VERSION 5.8 ;
BUSBITCHARS "[]" ;
DIVIDERCHAR "/" ;
UNITS
    DATABASE MICRONS 1000 ;
END UNITS

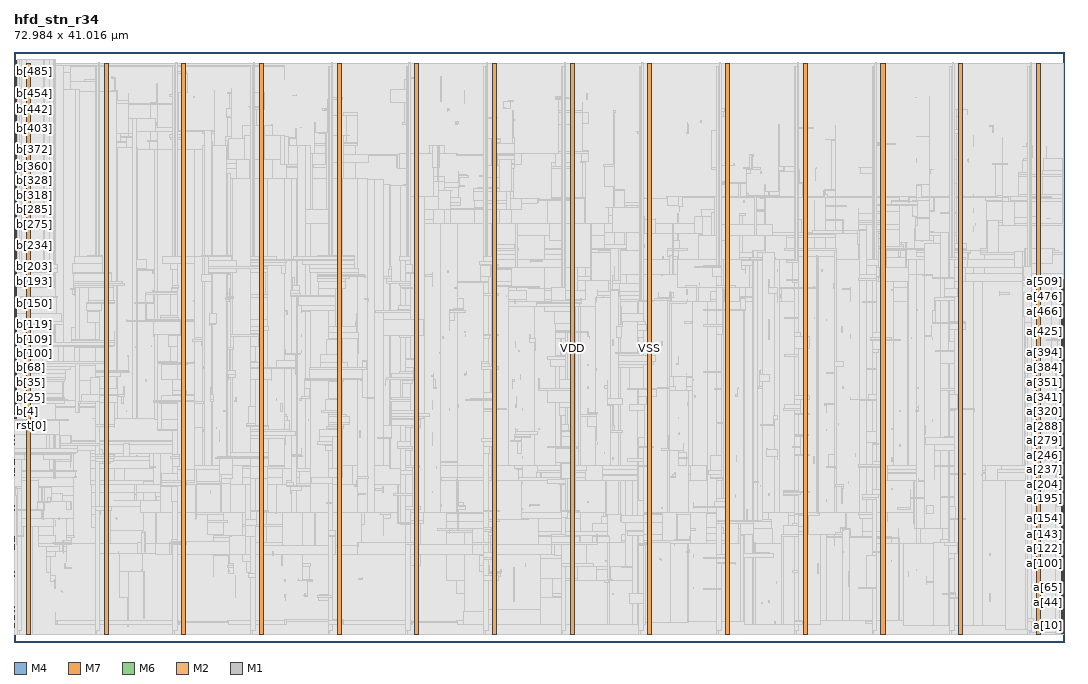
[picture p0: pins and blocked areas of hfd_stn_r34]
MACRO hfd_stn_r34
  FOREIGN hfd_stn_r34 0 0 ;
  CLASS BLOCK ;
  SIZE 72.984 BY 41.016 ;
  PIN a[0]
    DIRECTION INPUT ;
    USE SIGNAL ;
    PORT
      LAYER M4 ;
        RECT  72.792 0.624 72.984 0.648 ;
    END
  END a[0]
  PIN a[100]
    DIRECTION INPUT ;
    USE SIGNAL ;
    PORT
      LAYER M4 ;
        RECT  72.792 5.424 72.984 5.448 ;
    END
  END a[100]
  PIN a[101]
    DIRECTION INPUT ;
    USE SIGNAL ;
    PORT
      LAYER M4 ;
        RECT  72.792 5.472 72.984 5.496 ;
    END
  END a[101]
  PIN a[102]
    DIRECTION INPUT ;
    USE SIGNAL ;
    PORT
      LAYER M4 ;
        RECT  72.792 5.52 72.984 5.544 ;
    END
  END a[102]
  PIN a[103]
    DIRECTION INPUT ;
    USE SIGNAL ;
    PORT
      LAYER M4 ;
        RECT  72.792 5.568 72.984 5.592 ;
    END
  END a[103]
  PIN a[104]
    DIRECTION INPUT ;
    USE SIGNAL ;
    PORT
      LAYER M4 ;
        RECT  72.792 5.616 72.984 5.64 ;
    END
  END a[104]
  PIN a[105]
    DIRECTION INPUT ;
    USE SIGNAL ;
    PORT
      LAYER M4 ;
        RECT  72.792 5.664 72.984 5.688 ;
    END
  END a[105]
  PIN a[106]
    DIRECTION INPUT ;
    USE SIGNAL ;
    PORT
      LAYER M4 ;
        RECT  72.792 5.712 72.984 5.736 ;
    END
  END a[106]
  PIN a[107]
    DIRECTION INPUT ;
    USE SIGNAL ;
    PORT
      LAYER M4 ;
        RECT  72.792 5.76 72.984 5.784 ;
    END
  END a[107]
  PIN a[108]
    DIRECTION INPUT ;
    USE SIGNAL ;
    PORT
      LAYER M4 ;
        RECT  72.792 5.808 72.984 5.832 ;
    END
  END a[108]
  PIN a[109]
    DIRECTION INPUT ;
    USE SIGNAL ;
    PORT
      LAYER M4 ;
        RECT  72.792 5.856 72.984 5.88 ;
    END
  END a[109]
  PIN a[10]
    DIRECTION INPUT ;
    USE SIGNAL ;
    PORT
      LAYER M4 ;
        RECT  72.792 1.104 72.984 1.128 ;
    END
  END a[10]
  PIN a[110]
    DIRECTION INPUT ;
    USE SIGNAL ;
    PORT
      LAYER M4 ;
        RECT  72.792 5.904 72.984 5.928 ;
    END
  END a[110]
  PIN a[111]
    DIRECTION INPUT ;
    USE SIGNAL ;
    PORT
      LAYER M4 ;
        RECT  72.792 5.952 72.984 5.976 ;
    END
  END a[111]
  PIN a[112]
    DIRECTION INPUT ;
    USE SIGNAL ;
    PORT
      LAYER M4 ;
        RECT  72.792 6 72.984 6.024 ;
    END
  END a[112]
  PIN a[113]
    DIRECTION INPUT ;
    USE SIGNAL ;
    PORT
      LAYER M4 ;
        RECT  72.792 6.048 72.984 6.072 ;
    END
  END a[113]
  PIN a[114]
    DIRECTION INPUT ;
    USE SIGNAL ;
    PORT
      LAYER M4 ;
        RECT  72.792 6.096 72.984 6.12 ;
    END
  END a[114]
  PIN a[115]
    DIRECTION INPUT ;
    USE SIGNAL ;
    PORT
      LAYER M4 ;
        RECT  72.792 6.144 72.984 6.168 ;
    END
  END a[115]
  PIN a[116]
    DIRECTION INPUT ;
    USE SIGNAL ;
    PORT
      LAYER M4 ;
        RECT  72.792 6.192 72.984 6.216 ;
    END
  END a[116]
  PIN a[117]
    DIRECTION INPUT ;
    USE SIGNAL ;
    PORT
      LAYER M4 ;
        RECT  72.792 6.24 72.984 6.264 ;
    END
  END a[117]
  PIN a[118]
    DIRECTION INPUT ;
    USE SIGNAL ;
    PORT
      LAYER M4 ;
        RECT  72.792 6.288 72.984 6.312 ;
    END
  END a[118]
  PIN a[119]
    DIRECTION INPUT ;
    USE SIGNAL ;
    PORT
      LAYER M4 ;
        RECT  72.792 6.336 72.984 6.36 ;
    END
  END a[119]
  PIN a[11]
    DIRECTION INPUT ;
    USE SIGNAL ;
    PORT
      LAYER M4 ;
        RECT  72.792 1.152 72.984 1.176 ;
    END
  END a[11]
  PIN a[120]
    DIRECTION INPUT ;
    USE SIGNAL ;
    PORT
      LAYER M4 ;
        RECT  72.792 6.384 72.984 6.408 ;
    END
  END a[120]
  PIN a[121]
    DIRECTION INPUT ;
    USE SIGNAL ;
    PORT
      LAYER M4 ;
        RECT  72.792 6.432 72.984 6.456 ;
    END
  END a[121]
  PIN a[122]
    DIRECTION INPUT ;
    USE SIGNAL ;
    PORT
      LAYER M4 ;
        RECT  72.792 6.48 72.984 6.504 ;
    END
  END a[122]
  PIN a[123]
    DIRECTION INPUT ;
    USE SIGNAL ;
    PORT
      LAYER M4 ;
        RECT  72.792 6.528 72.984 6.552 ;
    END
  END a[123]
  PIN a[124]
    DIRECTION INPUT ;
    USE SIGNAL ;
    PORT
      LAYER M4 ;
        RECT  72.792 6.576 72.984 6.6 ;
    END
  END a[124]
  PIN a[125]
    DIRECTION INPUT ;
    USE SIGNAL ;
    PORT
      LAYER M4 ;
        RECT  72.792 6.624 72.984 6.648 ;
    END
  END a[125]
  PIN a[126]
    DIRECTION INPUT ;
    USE SIGNAL ;
    PORT
      LAYER M4 ;
        RECT  72.792 6.672 72.984 6.696 ;
    END
  END a[126]
  PIN a[127]
    DIRECTION INPUT ;
    USE SIGNAL ;
    PORT
      LAYER M4 ;
        RECT  72.792 6.72 72.984 6.744 ;
    END
  END a[127]
  PIN a[128]
    DIRECTION INPUT ;
    USE SIGNAL ;
    PORT
      LAYER M4 ;
        RECT  72.792 6.768 72.984 6.792 ;
    END
  END a[128]
  PIN a[129]
    DIRECTION INPUT ;
    USE SIGNAL ;
    PORT
      LAYER M4 ;
        RECT  72.792 6.816 72.984 6.84 ;
    END
  END a[129]
  PIN a[12]
    DIRECTION INPUT ;
    USE SIGNAL ;
    PORT
      LAYER M4 ;
        RECT  72.792 1.2 72.984 1.224 ;
    END
  END a[12]
  PIN a[130]
    DIRECTION INPUT ;
    USE SIGNAL ;
    PORT
      LAYER M4 ;
        RECT  72.792 6.864 72.984 6.888 ;
    END
  END a[130]
  PIN a[131]
    DIRECTION INPUT ;
    USE SIGNAL ;
    PORT
      LAYER M4 ;
        RECT  72.792 6.912 72.984 6.936 ;
    END
  END a[131]
  PIN a[132]
    DIRECTION INPUT ;
    USE SIGNAL ;
    PORT
      LAYER M4 ;
        RECT  72.792 6.96 72.984 6.984 ;
    END
  END a[132]
  PIN a[133]
    DIRECTION INPUT ;
    USE SIGNAL ;
    PORT
      LAYER M4 ;
        RECT  72.792 7.008 72.984 7.032 ;
    END
  END a[133]
  PIN a[134]
    DIRECTION INPUT ;
    USE SIGNAL ;
    PORT
      LAYER M4 ;
        RECT  72.792 7.056 72.984 7.08 ;
    END
  END a[134]
  PIN a[135]
    DIRECTION INPUT ;
    USE SIGNAL ;
    PORT
      LAYER M4 ;
        RECT  72.792 7.104 72.984 7.128 ;
    END
  END a[135]
  PIN a[136]
    DIRECTION INPUT ;
    USE SIGNAL ;
    PORT
      LAYER M4 ;
        RECT  72.792 7.152 72.984 7.176 ;
    END
  END a[136]
  PIN a[137]
    DIRECTION INPUT ;
    USE SIGNAL ;
    PORT
      LAYER M4 ;
        RECT  72.792 7.2 72.984 7.224 ;
    END
  END a[137]
  PIN a[138]
    DIRECTION INPUT ;
    USE SIGNAL ;
    PORT
      LAYER M4 ;
        RECT  72.792 7.248 72.984 7.272 ;
    END
  END a[138]
  PIN a[139]
    DIRECTION INPUT ;
    USE SIGNAL ;
    PORT
      LAYER M4 ;
        RECT  72.792 7.296 72.984 7.32 ;
    END
  END a[139]
  PIN a[13]
    DIRECTION INPUT ;
    USE SIGNAL ;
    PORT
      LAYER M4 ;
        RECT  72.792 1.248 72.984 1.272 ;
    END
  END a[13]
  PIN a[140]
    DIRECTION INPUT ;
    USE SIGNAL ;
    PORT
      LAYER M4 ;
        RECT  72.792 7.344 72.984 7.368 ;
    END
  END a[140]
  PIN a[141]
    DIRECTION INPUT ;
    USE SIGNAL ;
    PORT
      LAYER M4 ;
        RECT  72.792 7.392 72.984 7.416 ;
    END
  END a[141]
  PIN a[142]
    DIRECTION INPUT ;
    USE SIGNAL ;
    PORT
      LAYER M4 ;
        RECT  72.792 7.44 72.984 7.464 ;
    END
  END a[142]
  PIN a[143]
    DIRECTION INPUT ;
    USE SIGNAL ;
    PORT
      LAYER M4 ;
        RECT  72.792 7.488 72.984 7.512 ;
    END
  END a[143]
  PIN a[144]
    DIRECTION INPUT ;
    USE SIGNAL ;
    PORT
      LAYER M4 ;
        RECT  72.792 7.536 72.984 7.56 ;
    END
  END a[144]
  PIN a[145]
    DIRECTION INPUT ;
    USE SIGNAL ;
    PORT
      LAYER M4 ;
        RECT  72.792 7.584 72.984 7.608 ;
    END
  END a[145]
  PIN a[146]
    DIRECTION INPUT ;
    USE SIGNAL ;
    PORT
      LAYER M4 ;
        RECT  72.792 7.632 72.984 7.656 ;
    END
  END a[146]
  PIN a[147]
    DIRECTION INPUT ;
    USE SIGNAL ;
    PORT
      LAYER M4 ;
        RECT  72.792 7.68 72.984 7.704 ;
    END
  END a[147]
  PIN a[148]
    DIRECTION INPUT ;
    USE SIGNAL ;
    PORT
      LAYER M4 ;
        RECT  72.792 7.728 72.984 7.752 ;
    END
  END a[148]
  PIN a[149]
    DIRECTION INPUT ;
    USE SIGNAL ;
    PORT
      LAYER M4 ;
        RECT  72.792 7.776 72.984 7.8 ;
    END
  END a[149]
  PIN a[14]
    DIRECTION INPUT ;
    USE SIGNAL ;
    PORT
      LAYER M4 ;
        RECT  72.792 1.296 72.984 1.32 ;
    END
  END a[14]
  PIN a[150]
    DIRECTION INPUT ;
    USE SIGNAL ;
    PORT
      LAYER M4 ;
        RECT  72.792 7.824 72.984 7.848 ;
    END
  END a[150]
  PIN a[151]
    DIRECTION INPUT ;
    USE SIGNAL ;
    PORT
      LAYER M4 ;
        RECT  72.792 7.872 72.984 7.896 ;
    END
  END a[151]
  PIN a[152]
    DIRECTION INPUT ;
    USE SIGNAL ;
    PORT
      LAYER M4 ;
        RECT  72.792 7.92 72.984 7.944 ;
    END
  END a[152]
  PIN a[153]
    DIRECTION INPUT ;
    USE SIGNAL ;
    PORT
      LAYER M4 ;
        RECT  72.792 7.968 72.984 7.992 ;
    END
  END a[153]
  PIN a[154]
    DIRECTION INPUT ;
    USE SIGNAL ;
    PORT
      LAYER M4 ;
        RECT  72.792 8.016 72.984 8.04 ;
    END
  END a[154]
  PIN a[155]
    DIRECTION INPUT ;
    USE SIGNAL ;
    PORT
      LAYER M4 ;
        RECT  72.792 8.064 72.984 8.088 ;
    END
  END a[155]
  PIN a[156]
    DIRECTION INPUT ;
    USE SIGNAL ;
    PORT
      LAYER M4 ;
        RECT  72.792 8.112 72.984 8.136 ;
    END
  END a[156]
  PIN a[157]
    DIRECTION INPUT ;
    USE SIGNAL ;
    PORT
      LAYER M4 ;
        RECT  72.792 8.16 72.984 8.184 ;
    END
  END a[157]
  PIN a[158]
    DIRECTION INPUT ;
    USE SIGNAL ;
    PORT
      LAYER M4 ;
        RECT  72.792 8.208 72.984 8.232 ;
    END
  END a[158]
  PIN a[159]
    DIRECTION INPUT ;
    USE SIGNAL ;
    PORT
      LAYER M4 ;
        RECT  72.792 8.256 72.984 8.28 ;
    END
  END a[159]
  PIN a[15]
    DIRECTION INPUT ;
    USE SIGNAL ;
    PORT
      LAYER M4 ;
        RECT  72.792 1.344 72.984 1.368 ;
    END
  END a[15]
  PIN a[160]
    DIRECTION INPUT ;
    USE SIGNAL ;
    PORT
      LAYER M4 ;
        RECT  72.792 8.304 72.984 8.328 ;
    END
  END a[160]
  PIN a[161]
    DIRECTION INPUT ;
    USE SIGNAL ;
    PORT
      LAYER M4 ;
        RECT  72.792 8.352 72.984 8.376 ;
    END
  END a[161]
  PIN a[162]
    DIRECTION INPUT ;
    USE SIGNAL ;
    PORT
      LAYER M4 ;
        RECT  72.792 8.4 72.984 8.424 ;
    END
  END a[162]
  PIN a[163]
    DIRECTION INPUT ;
    USE SIGNAL ;
    PORT
      LAYER M4 ;
        RECT  72.792 8.448 72.984 8.472 ;
    END
  END a[163]
  PIN a[164]
    DIRECTION INPUT ;
    USE SIGNAL ;
    PORT
      LAYER M4 ;
        RECT  72.792 8.496 72.984 8.52 ;
    END
  END a[164]
  PIN a[165]
    DIRECTION INPUT ;
    USE SIGNAL ;
    PORT
      LAYER M4 ;
        RECT  72.792 8.544 72.984 8.568 ;
    END
  END a[165]
  PIN a[166]
    DIRECTION INPUT ;
    USE SIGNAL ;
    PORT
      LAYER M4 ;
        RECT  72.792 8.592 72.984 8.616 ;
    END
  END a[166]
  PIN a[167]
    DIRECTION INPUT ;
    USE SIGNAL ;
    PORT
      LAYER M4 ;
        RECT  72.792 8.64 72.984 8.664 ;
    END
  END a[167]
  PIN a[168]
    DIRECTION INPUT ;
    USE SIGNAL ;
    PORT
      LAYER M4 ;
        RECT  72.792 8.688 72.984 8.712 ;
    END
  END a[168]
  PIN a[169]
    DIRECTION INPUT ;
    USE SIGNAL ;
    PORT
      LAYER M4 ;
        RECT  72.792 8.736 72.984 8.76 ;
    END
  END a[169]
  PIN a[16]
    DIRECTION INPUT ;
    USE SIGNAL ;
    PORT
      LAYER M4 ;
        RECT  72.792 1.392 72.984 1.416 ;
    END
  END a[16]
  PIN a[170]
    DIRECTION INPUT ;
    USE SIGNAL ;
    PORT
      LAYER M4 ;
        RECT  72.792 8.784 72.984 8.808 ;
    END
  END a[170]
  PIN a[171]
    DIRECTION INPUT ;
    USE SIGNAL ;
    PORT
      LAYER M4 ;
        RECT  72.792 8.832 72.984 8.856 ;
    END
  END a[171]
  PIN a[172]
    DIRECTION INPUT ;
    USE SIGNAL ;
    PORT
      LAYER M4 ;
        RECT  72.792 8.88 72.984 8.904 ;
    END
  END a[172]
  PIN a[173]
    DIRECTION INPUT ;
    USE SIGNAL ;
    PORT
      LAYER M4 ;
        RECT  72.792 8.928 72.984 8.952 ;
    END
  END a[173]
  PIN a[174]
    DIRECTION INPUT ;
    USE SIGNAL ;
    PORT
      LAYER M4 ;
        RECT  72.792 8.976 72.984 9 ;
    END
  END a[174]
  PIN a[175]
    DIRECTION INPUT ;
    USE SIGNAL ;
    PORT
      LAYER M4 ;
        RECT  72.792 9.024 72.984 9.048 ;
    END
  END a[175]
  PIN a[176]
    DIRECTION INPUT ;
    USE SIGNAL ;
    PORT
      LAYER M4 ;
        RECT  72.792 9.072 72.984 9.096 ;
    END
  END a[176]
  PIN a[177]
    DIRECTION INPUT ;
    USE SIGNAL ;
    PORT
      LAYER M4 ;
        RECT  72.792 9.12 72.984 9.144 ;
    END
  END a[177]
  PIN a[178]
    DIRECTION INPUT ;
    USE SIGNAL ;
    PORT
      LAYER M4 ;
        RECT  72.792 9.168 72.984 9.192 ;
    END
  END a[178]
  PIN a[179]
    DIRECTION INPUT ;
    USE SIGNAL ;
    PORT
      LAYER M4 ;
        RECT  72.792 9.216 72.984 9.24 ;
    END
  END a[179]
  PIN a[17]
    DIRECTION INPUT ;
    USE SIGNAL ;
    PORT
      LAYER M4 ;
        RECT  72.792 1.44 72.984 1.464 ;
    END
  END a[17]
  PIN a[180]
    DIRECTION INPUT ;
    USE SIGNAL ;
    PORT
      LAYER M4 ;
        RECT  72.792 9.264 72.984 9.288 ;
    END
  END a[180]
  PIN a[181]
    DIRECTION INPUT ;
    USE SIGNAL ;
    PORT
      LAYER M4 ;
        RECT  72.792 9.312 72.984 9.336 ;
    END
  END a[181]
  PIN a[182]
    DIRECTION INPUT ;
    USE SIGNAL ;
    PORT
      LAYER M4 ;
        RECT  72.792 9.36 72.984 9.384 ;
    END
  END a[182]
  PIN a[183]
    DIRECTION INPUT ;
    USE SIGNAL ;
    PORT
      LAYER M4 ;
        RECT  72.792 9.408 72.984 9.432 ;
    END
  END a[183]
  PIN a[184]
    DIRECTION INPUT ;
    USE SIGNAL ;
    PORT
      LAYER M4 ;
        RECT  72.792 9.456 72.984 9.48 ;
    END
  END a[184]
  PIN a[185]
    DIRECTION INPUT ;
    USE SIGNAL ;
    PORT
      LAYER M4 ;
        RECT  72.792 9.504 72.984 9.528 ;
    END
  END a[185]
  PIN a[186]
    DIRECTION INPUT ;
    USE SIGNAL ;
    PORT
      LAYER M4 ;
        RECT  72.792 9.552 72.984 9.576 ;
    END
  END a[186]
  PIN a[187]
    DIRECTION INPUT ;
    USE SIGNAL ;
    PORT
      LAYER M4 ;
        RECT  72.792 9.6 72.984 9.624 ;
    END
  END a[187]
  PIN a[188]
    DIRECTION INPUT ;
    USE SIGNAL ;
    PORT
      LAYER M4 ;
        RECT  72.792 9.648 72.984 9.672 ;
    END
  END a[188]
  PIN a[189]
    DIRECTION INPUT ;
    USE SIGNAL ;
    PORT
      LAYER M4 ;
        RECT  72.792 9.696 72.984 9.72 ;
    END
  END a[189]
  PIN a[18]
    DIRECTION INPUT ;
    USE SIGNAL ;
    PORT
      LAYER M4 ;
        RECT  72.792 1.488 72.984 1.512 ;
    END
  END a[18]
  PIN a[190]
    DIRECTION INPUT ;
    USE SIGNAL ;
    PORT
      LAYER M4 ;
        RECT  72.792 9.744 72.984 9.768 ;
    END
  END a[190]
  PIN a[191]
    DIRECTION INPUT ;
    USE SIGNAL ;
    PORT
      LAYER M4 ;
        RECT  72.792 9.792 72.984 9.816 ;
    END
  END a[191]
  PIN a[192]
    DIRECTION INPUT ;
    USE SIGNAL ;
    PORT
      LAYER M4 ;
        RECT  72.792 9.84 72.984 9.864 ;
    END
  END a[192]
  PIN a[193]
    DIRECTION INPUT ;
    USE SIGNAL ;
    PORT
      LAYER M4 ;
        RECT  72.792 9.888 72.984 9.912 ;
    END
  END a[193]
  PIN a[194]
    DIRECTION INPUT ;
    USE SIGNAL ;
    PORT
      LAYER M4 ;
        RECT  72.792 9.936 72.984 9.96 ;
    END
  END a[194]
  PIN a[195]
    DIRECTION INPUT ;
    USE SIGNAL ;
    PORT
      LAYER M4 ;
        RECT  72.792 9.984 72.984 10.008 ;
    END
  END a[195]
  PIN a[196]
    DIRECTION INPUT ;
    USE SIGNAL ;
    PORT
      LAYER M4 ;
        RECT  72.792 10.032 72.984 10.056 ;
    END
  END a[196]
  PIN a[197]
    DIRECTION INPUT ;
    USE SIGNAL ;
    PORT
      LAYER M4 ;
        RECT  72.792 10.08 72.984 10.104 ;
    END
  END a[197]
  PIN a[198]
    DIRECTION INPUT ;
    USE SIGNAL ;
    PORT
      LAYER M4 ;
        RECT  72.792 10.128 72.984 10.152 ;
    END
  END a[198]
  PIN a[199]
    DIRECTION INPUT ;
    USE SIGNAL ;
    PORT
      LAYER M4 ;
        RECT  72.792 10.176 72.984 10.2 ;
    END
  END a[199]
  PIN a[19]
    DIRECTION INPUT ;
    USE SIGNAL ;
    PORT
      LAYER M4 ;
        RECT  72.792 1.536 72.984 1.56 ;
    END
  END a[19]
  PIN a[1]
    DIRECTION INPUT ;
    USE SIGNAL ;
    PORT
      LAYER M4 ;
        RECT  72.792 0.672 72.984 0.696 ;
    END
  END a[1]
  PIN a[200]
    DIRECTION INPUT ;
    USE SIGNAL ;
    PORT
      LAYER M4 ;
        RECT  72.792 10.224 72.984 10.248 ;
    END
  END a[200]
  PIN a[201]
    DIRECTION INPUT ;
    USE SIGNAL ;
    PORT
      LAYER M4 ;
        RECT  72.792 10.272 72.984 10.296 ;
    END
  END a[201]
  PIN a[202]
    DIRECTION INPUT ;
    USE SIGNAL ;
    PORT
      LAYER M4 ;
        RECT  72.792 10.32 72.984 10.344 ;
    END
  END a[202]
  PIN a[203]
    DIRECTION INPUT ;
    USE SIGNAL ;
    PORT
      LAYER M4 ;
        RECT  72.792 10.368 72.984 10.392 ;
    END
  END a[203]
  PIN a[204]
    DIRECTION INPUT ;
    USE SIGNAL ;
    PORT
      LAYER M4 ;
        RECT  72.792 10.416 72.984 10.44 ;
    END
  END a[204]
  PIN a[205]
    DIRECTION INPUT ;
    USE SIGNAL ;
    PORT
      LAYER M4 ;
        RECT  72.792 10.464 72.984 10.488 ;
    END
  END a[205]
  PIN a[206]
    DIRECTION INPUT ;
    USE SIGNAL ;
    PORT
      LAYER M4 ;
        RECT  72.792 10.512 72.984 10.536 ;
    END
  END a[206]
  PIN a[207]
    DIRECTION INPUT ;
    USE SIGNAL ;
    PORT
      LAYER M4 ;
        RECT  72.792 10.56 72.984 10.584 ;
    END
  END a[207]
  PIN a[208]
    DIRECTION INPUT ;
    USE SIGNAL ;
    PORT
      LAYER M4 ;
        RECT  72.792 10.608 72.984 10.632 ;
    END
  END a[208]
  PIN a[209]
    DIRECTION INPUT ;
    USE SIGNAL ;
    PORT
      LAYER M4 ;
        RECT  72.792 10.656 72.984 10.68 ;
    END
  END a[209]
  PIN a[20]
    DIRECTION INPUT ;
    USE SIGNAL ;
    PORT
      LAYER M4 ;
        RECT  72.792 1.584 72.984 1.608 ;
    END
  END a[20]
  PIN a[210]
    DIRECTION INPUT ;
    USE SIGNAL ;
    PORT
      LAYER M4 ;
        RECT  72.792 10.704 72.984 10.728 ;
    END
  END a[210]
  PIN a[211]
    DIRECTION INPUT ;
    USE SIGNAL ;
    PORT
      LAYER M4 ;
        RECT  72.792 10.752 72.984 10.776 ;
    END
  END a[211]
  PIN a[212]
    DIRECTION INPUT ;
    USE SIGNAL ;
    PORT
      LAYER M4 ;
        RECT  72.792 10.8 72.984 10.824 ;
    END
  END a[212]
  PIN a[213]
    DIRECTION INPUT ;
    USE SIGNAL ;
    PORT
      LAYER M4 ;
        RECT  72.792 10.848 72.984 10.872 ;
    END
  END a[213]
  PIN a[214]
    DIRECTION INPUT ;
    USE SIGNAL ;
    PORT
      LAYER M4 ;
        RECT  72.792 10.896 72.984 10.92 ;
    END
  END a[214]
  PIN a[215]
    DIRECTION INPUT ;
    USE SIGNAL ;
    PORT
      LAYER M4 ;
        RECT  72.792 10.944 72.984 10.968 ;
    END
  END a[215]
  PIN a[216]
    DIRECTION INPUT ;
    USE SIGNAL ;
    PORT
      LAYER M4 ;
        RECT  72.792 10.992 72.984 11.016 ;
    END
  END a[216]
  PIN a[217]
    DIRECTION INPUT ;
    USE SIGNAL ;
    PORT
      LAYER M4 ;
        RECT  72.792 11.04 72.984 11.064 ;
    END
  END a[217]
  PIN a[218]
    DIRECTION INPUT ;
    USE SIGNAL ;
    PORT
      LAYER M4 ;
        RECT  72.792 11.088 72.984 11.112 ;
    END
  END a[218]
  PIN a[219]
    DIRECTION INPUT ;
    USE SIGNAL ;
    PORT
      LAYER M4 ;
        RECT  72.792 11.136 72.984 11.16 ;
    END
  END a[219]
  PIN a[21]
    DIRECTION INPUT ;
    USE SIGNAL ;
    PORT
      LAYER M4 ;
        RECT  72.792 1.632 72.984 1.656 ;
    END
  END a[21]
  PIN a[220]
    DIRECTION INPUT ;
    USE SIGNAL ;
    PORT
      LAYER M4 ;
        RECT  72.792 11.184 72.984 11.208 ;
    END
  END a[220]
  PIN a[221]
    DIRECTION INPUT ;
    USE SIGNAL ;
    PORT
      LAYER M4 ;
        RECT  72.792 11.232 72.984 11.256 ;
    END
  END a[221]
  PIN a[222]
    DIRECTION INPUT ;
    USE SIGNAL ;
    PORT
      LAYER M4 ;
        RECT  72.792 11.28 72.984 11.304 ;
    END
  END a[222]
  PIN a[223]
    DIRECTION INPUT ;
    USE SIGNAL ;
    PORT
      LAYER M4 ;
        RECT  72.792 11.328 72.984 11.352 ;
    END
  END a[223]
  PIN a[224]
    DIRECTION INPUT ;
    USE SIGNAL ;
    PORT
      LAYER M4 ;
        RECT  72.792 11.376 72.984 11.4 ;
    END
  END a[224]
  PIN a[225]
    DIRECTION INPUT ;
    USE SIGNAL ;
    PORT
      LAYER M4 ;
        RECT  72.792 11.424 72.984 11.448 ;
    END
  END a[225]
  PIN a[226]
    DIRECTION INPUT ;
    USE SIGNAL ;
    PORT
      LAYER M4 ;
        RECT  72.792 11.472 72.984 11.496 ;
    END
  END a[226]
  PIN a[227]
    DIRECTION INPUT ;
    USE SIGNAL ;
    PORT
      LAYER M4 ;
        RECT  72.792 11.52 72.984 11.544 ;
    END
  END a[227]
  PIN a[228]
    DIRECTION INPUT ;
    USE SIGNAL ;
    PORT
      LAYER M4 ;
        RECT  72.792 11.568 72.984 11.592 ;
    END
  END a[228]
  PIN a[229]
    DIRECTION INPUT ;
    USE SIGNAL ;
    PORT
      LAYER M4 ;
        RECT  72.792 11.616 72.984 11.64 ;
    END
  END a[229]
  PIN a[22]
    DIRECTION INPUT ;
    USE SIGNAL ;
    PORT
      LAYER M4 ;
        RECT  72.792 1.68 72.984 1.704 ;
    END
  END a[22]
  PIN a[230]
    DIRECTION INPUT ;
    USE SIGNAL ;
    PORT
      LAYER M4 ;
        RECT  72.792 11.664 72.984 11.688 ;
    END
  END a[230]
  PIN a[231]
    DIRECTION INPUT ;
    USE SIGNAL ;
    PORT
      LAYER M4 ;
        RECT  72.792 11.712 72.984 11.736 ;
    END
  END a[231]
  PIN a[232]
    DIRECTION INPUT ;
    USE SIGNAL ;
    PORT
      LAYER M4 ;
        RECT  72.792 11.76 72.984 11.784 ;
    END
  END a[232]
  PIN a[233]
    DIRECTION INPUT ;
    USE SIGNAL ;
    PORT
      LAYER M4 ;
        RECT  72.792 11.808 72.984 11.832 ;
    END
  END a[233]
  PIN a[234]
    DIRECTION INPUT ;
    USE SIGNAL ;
    PORT
      LAYER M4 ;
        RECT  72.792 11.856 72.984 11.88 ;
    END
  END a[234]
  PIN a[235]
    DIRECTION INPUT ;
    USE SIGNAL ;
    PORT
      LAYER M4 ;
        RECT  72.792 11.904 72.984 11.928 ;
    END
  END a[235]
  PIN a[236]
    DIRECTION INPUT ;
    USE SIGNAL ;
    PORT
      LAYER M4 ;
        RECT  72.792 11.952 72.984 11.976 ;
    END
  END a[236]
  PIN a[237]
    DIRECTION INPUT ;
    USE SIGNAL ;
    PORT
      LAYER M4 ;
        RECT  72.792 12 72.984 12.024 ;
    END
  END a[237]
  PIN a[238]
    DIRECTION INPUT ;
    USE SIGNAL ;
    PORT
      LAYER M4 ;
        RECT  72.792 12.048 72.984 12.072 ;
    END
  END a[238]
  PIN a[239]
    DIRECTION INPUT ;
    USE SIGNAL ;
    PORT
      LAYER M4 ;
        RECT  72.792 12.096 72.984 12.12 ;
    END
  END a[239]
  PIN a[23]
    DIRECTION INPUT ;
    USE SIGNAL ;
    PORT
      LAYER M4 ;
        RECT  72.792 1.728 72.984 1.752 ;
    END
  END a[23]
  PIN a[240]
    DIRECTION INPUT ;
    USE SIGNAL ;
    PORT
      LAYER M4 ;
        RECT  72.792 12.144 72.984 12.168 ;
    END
  END a[240]
  PIN a[241]
    DIRECTION INPUT ;
    USE SIGNAL ;
    PORT
      LAYER M4 ;
        RECT  72.792 12.192 72.984 12.216 ;
    END
  END a[241]
  PIN a[242]
    DIRECTION INPUT ;
    USE SIGNAL ;
    PORT
      LAYER M4 ;
        RECT  72.792 12.24 72.984 12.264 ;
    END
  END a[242]
  PIN a[243]
    DIRECTION INPUT ;
    USE SIGNAL ;
    PORT
      LAYER M4 ;
        RECT  72.792 12.288 72.984 12.312 ;
    END
  END a[243]
  PIN a[244]
    DIRECTION INPUT ;
    USE SIGNAL ;
    PORT
      LAYER M4 ;
        RECT  72.792 12.336 72.984 12.36 ;
    END
  END a[244]
  PIN a[245]
    DIRECTION INPUT ;
    USE SIGNAL ;
    PORT
      LAYER M4 ;
        RECT  72.792 12.384 72.984 12.408 ;
    END
  END a[245]
  PIN a[246]
    DIRECTION INPUT ;
    USE SIGNAL ;
    PORT
      LAYER M4 ;
        RECT  72.792 12.432 72.984 12.456 ;
    END
  END a[246]
  PIN a[247]
    DIRECTION INPUT ;
    USE SIGNAL ;
    PORT
      LAYER M4 ;
        RECT  72.792 12.48 72.984 12.504 ;
    END
  END a[247]
  PIN a[248]
    DIRECTION INPUT ;
    USE SIGNAL ;
    PORT
      LAYER M4 ;
        RECT  72.792 12.528 72.984 12.552 ;
    END
  END a[248]
  PIN a[249]
    DIRECTION INPUT ;
    USE SIGNAL ;
    PORT
      LAYER M4 ;
        RECT  72.792 12.576 72.984 12.6 ;
    END
  END a[249]
  PIN a[24]
    DIRECTION INPUT ;
    USE SIGNAL ;
    PORT
      LAYER M4 ;
        RECT  72.792 1.776 72.984 1.8 ;
    END
  END a[24]
  PIN a[250]
    DIRECTION INPUT ;
    USE SIGNAL ;
    PORT
      LAYER M4 ;
        RECT  72.792 12.624 72.984 12.648 ;
    END
  END a[250]
  PIN a[251]
    DIRECTION INPUT ;
    USE SIGNAL ;
    PORT
      LAYER M4 ;
        RECT  72.792 12.672 72.984 12.696 ;
    END
  END a[251]
  PIN a[252]
    DIRECTION INPUT ;
    USE SIGNAL ;
    PORT
      LAYER M4 ;
        RECT  72.792 12.72 72.984 12.744 ;
    END
  END a[252]
  PIN a[253]
    DIRECTION INPUT ;
    USE SIGNAL ;
    PORT
      LAYER M4 ;
        RECT  72.792 12.768 72.984 12.792 ;
    END
  END a[253]
  PIN a[254]
    DIRECTION INPUT ;
    USE SIGNAL ;
    PORT
      LAYER M4 ;
        RECT  72.792 12.816 72.984 12.84 ;
    END
  END a[254]
  PIN a[255]
    DIRECTION INPUT ;
    USE SIGNAL ;
    PORT
      LAYER M4 ;
        RECT  72.792 12.864 72.984 12.888 ;
    END
  END a[255]
  PIN a[256]
    DIRECTION INPUT ;
    USE SIGNAL ;
    PORT
      LAYER M4 ;
        RECT  72.792 12.912 72.984 12.936 ;
    END
  END a[256]
  PIN a[257]
    DIRECTION INPUT ;
    USE SIGNAL ;
    PORT
      LAYER M4 ;
        RECT  72.792 12.96 72.984 12.984 ;
    END
  END a[257]
  PIN a[258]
    DIRECTION INPUT ;
    USE SIGNAL ;
    PORT
      LAYER M4 ;
        RECT  72.792 13.008 72.984 13.032 ;
    END
  END a[258]
  PIN a[259]
    DIRECTION INPUT ;
    USE SIGNAL ;
    PORT
      LAYER M4 ;
        RECT  72.792 13.056 72.984 13.08 ;
    END
  END a[259]
  PIN a[25]
    DIRECTION INPUT ;
    USE SIGNAL ;
    PORT
      LAYER M4 ;
        RECT  72.792 1.824 72.984 1.848 ;
    END
  END a[25]
  PIN a[260]
    DIRECTION INPUT ;
    USE SIGNAL ;
    PORT
      LAYER M4 ;
        RECT  72.792 13.104 72.984 13.128 ;
    END
  END a[260]
  PIN a[261]
    DIRECTION INPUT ;
    USE SIGNAL ;
    PORT
      LAYER M4 ;
        RECT  72.792 13.152 72.984 13.176 ;
    END
  END a[261]
  PIN a[262]
    DIRECTION INPUT ;
    USE SIGNAL ;
    PORT
      LAYER M4 ;
        RECT  72.792 13.2 72.984 13.224 ;
    END
  END a[262]
  PIN a[263]
    DIRECTION INPUT ;
    USE SIGNAL ;
    PORT
      LAYER M4 ;
        RECT  72.792 13.248 72.984 13.272 ;
    END
  END a[263]
  PIN a[264]
    DIRECTION INPUT ;
    USE SIGNAL ;
    PORT
      LAYER M4 ;
        RECT  72.792 13.296 72.984 13.32 ;
    END
  END a[264]
  PIN a[265]
    DIRECTION INPUT ;
    USE SIGNAL ;
    PORT
      LAYER M4 ;
        RECT  72.792 13.344 72.984 13.368 ;
    END
  END a[265]
  PIN a[266]
    DIRECTION INPUT ;
    USE SIGNAL ;
    PORT
      LAYER M4 ;
        RECT  72.792 13.392 72.984 13.416 ;
    END
  END a[266]
  PIN a[267]
    DIRECTION INPUT ;
    USE SIGNAL ;
    PORT
      LAYER M4 ;
        RECT  72.792 13.44 72.984 13.464 ;
    END
  END a[267]
  PIN a[268]
    DIRECTION INPUT ;
    USE SIGNAL ;
    PORT
      LAYER M4 ;
        RECT  72.792 13.488 72.984 13.512 ;
    END
  END a[268]
  PIN a[269]
    DIRECTION INPUT ;
    USE SIGNAL ;
    PORT
      LAYER M4 ;
        RECT  72.792 13.536 72.984 13.56 ;
    END
  END a[269]
  PIN a[26]
    DIRECTION INPUT ;
    USE SIGNAL ;
    PORT
      LAYER M4 ;
        RECT  72.792 1.872 72.984 1.896 ;
    END
  END a[26]
  PIN a[270]
    DIRECTION INPUT ;
    USE SIGNAL ;
    PORT
      LAYER M4 ;
        RECT  72.792 13.584 72.984 13.608 ;
    END
  END a[270]
  PIN a[271]
    DIRECTION INPUT ;
    USE SIGNAL ;
    PORT
      LAYER M4 ;
        RECT  72.792 13.632 72.984 13.656 ;
    END
  END a[271]
  PIN a[272]
    DIRECTION INPUT ;
    USE SIGNAL ;
    PORT
      LAYER M4 ;
        RECT  72.792 13.68 72.984 13.704 ;
    END
  END a[272]
  PIN a[273]
    DIRECTION INPUT ;
    USE SIGNAL ;
    PORT
      LAYER M4 ;
        RECT  72.792 13.728 72.984 13.752 ;
    END
  END a[273]
  PIN a[274]
    DIRECTION INPUT ;
    USE SIGNAL ;
    PORT
      LAYER M4 ;
        RECT  72.792 13.776 72.984 13.8 ;
    END
  END a[274]
  PIN a[275]
    DIRECTION INPUT ;
    USE SIGNAL ;
    PORT
      LAYER M4 ;
        RECT  72.792 13.824 72.984 13.848 ;
    END
  END a[275]
  PIN a[276]
    DIRECTION INPUT ;
    USE SIGNAL ;
    PORT
      LAYER M4 ;
        RECT  72.792 13.872 72.984 13.896 ;
    END
  END a[276]
  PIN a[277]
    DIRECTION INPUT ;
    USE SIGNAL ;
    PORT
      LAYER M4 ;
        RECT  72.792 13.92 72.984 13.944 ;
    END
  END a[277]
  PIN a[278]
    DIRECTION INPUT ;
    USE SIGNAL ;
    PORT
      LAYER M4 ;
        RECT  72.792 13.968 72.984 13.992 ;
    END
  END a[278]
  PIN a[279]
    DIRECTION INPUT ;
    USE SIGNAL ;
    PORT
      LAYER M4 ;
        RECT  72.792 14.016 72.984 14.04 ;
    END
  END a[279]
  PIN a[27]
    DIRECTION INPUT ;
    USE SIGNAL ;
    PORT
      LAYER M4 ;
        RECT  72.792 1.92 72.984 1.944 ;
    END
  END a[27]
  PIN a[280]
    DIRECTION INPUT ;
    USE SIGNAL ;
    PORT
      LAYER M4 ;
        RECT  72.792 14.064 72.984 14.088 ;
    END
  END a[280]
  PIN a[281]
    DIRECTION INPUT ;
    USE SIGNAL ;
    PORT
      LAYER M4 ;
        RECT  72.792 14.112 72.984 14.136 ;
    END
  END a[281]
  PIN a[282]
    DIRECTION INPUT ;
    USE SIGNAL ;
    PORT
      LAYER M4 ;
        RECT  72.792 14.16 72.984 14.184 ;
    END
  END a[282]
  PIN a[283]
    DIRECTION INPUT ;
    USE SIGNAL ;
    PORT
      LAYER M4 ;
        RECT  72.792 14.208 72.984 14.232 ;
    END
  END a[283]
  PIN a[284]
    DIRECTION INPUT ;
    USE SIGNAL ;
    PORT
      LAYER M4 ;
        RECT  72.792 14.256 72.984 14.28 ;
    END
  END a[284]
  PIN a[285]
    DIRECTION INPUT ;
    USE SIGNAL ;
    PORT
      LAYER M4 ;
        RECT  72.792 14.304 72.984 14.328 ;
    END
  END a[285]
  PIN a[286]
    DIRECTION INPUT ;
    USE SIGNAL ;
    PORT
      LAYER M4 ;
        RECT  72.792 14.352 72.984 14.376 ;
    END
  END a[286]
  PIN a[287]
    DIRECTION INPUT ;
    USE SIGNAL ;
    PORT
      LAYER M4 ;
        RECT  72.792 14.4 72.984 14.424 ;
    END
  END a[287]
  PIN a[288]
    DIRECTION INPUT ;
    USE SIGNAL ;
    PORT
      LAYER M4 ;
        RECT  72.792 14.448 72.984 14.472 ;
    END
  END a[288]
  PIN a[289]
    DIRECTION INPUT ;
    USE SIGNAL ;
    PORT
      LAYER M4 ;
        RECT  72.792 14.496 72.984 14.52 ;
    END
  END a[289]
  PIN a[28]
    DIRECTION INPUT ;
    USE SIGNAL ;
    PORT
      LAYER M4 ;
        RECT  72.792 1.968 72.984 1.992 ;
    END
  END a[28]
  PIN a[290]
    DIRECTION INPUT ;
    USE SIGNAL ;
    PORT
      LAYER M4 ;
        RECT  72.792 14.544 72.984 14.568 ;
    END
  END a[290]
  PIN a[291]
    DIRECTION INPUT ;
    USE SIGNAL ;
    PORT
      LAYER M4 ;
        RECT  72.792 14.592 72.984 14.616 ;
    END
  END a[291]
  PIN a[292]
    DIRECTION INPUT ;
    USE SIGNAL ;
    PORT
      LAYER M4 ;
        RECT  72.792 14.64 72.984 14.664 ;
    END
  END a[292]
  PIN a[293]
    DIRECTION INPUT ;
    USE SIGNAL ;
    PORT
      LAYER M4 ;
        RECT  72.792 14.688 72.984 14.712 ;
    END
  END a[293]
  PIN a[294]
    DIRECTION INPUT ;
    USE SIGNAL ;
    PORT
      LAYER M4 ;
        RECT  72.792 14.736 72.984 14.76 ;
    END
  END a[294]
  PIN a[295]
    DIRECTION INPUT ;
    USE SIGNAL ;
    PORT
      LAYER M4 ;
        RECT  72.792 14.784 72.984 14.808 ;
    END
  END a[295]
  PIN a[296]
    DIRECTION INPUT ;
    USE SIGNAL ;
    PORT
      LAYER M4 ;
        RECT  72.792 14.832 72.984 14.856 ;
    END
  END a[296]
  PIN a[297]
    DIRECTION INPUT ;
    USE SIGNAL ;
    PORT
      LAYER M4 ;
        RECT  72.792 14.88 72.984 14.904 ;
    END
  END a[297]
  PIN a[298]
    DIRECTION INPUT ;
    USE SIGNAL ;
    PORT
      LAYER M4 ;
        RECT  72.792 14.928 72.984 14.952 ;
    END
  END a[298]
  PIN a[299]
    DIRECTION INPUT ;
    USE SIGNAL ;
    PORT
      LAYER M4 ;
        RECT  72.792 14.976 72.984 15 ;
    END
  END a[299]
  PIN a[29]
    DIRECTION INPUT ;
    USE SIGNAL ;
    PORT
      LAYER M4 ;
        RECT  72.792 2.016 72.984 2.04 ;
    END
  END a[29]
  PIN a[2]
    DIRECTION INPUT ;
    USE SIGNAL ;
    PORT
      LAYER M4 ;
        RECT  72.792 0.72 72.984 0.744 ;
    END
  END a[2]
  PIN a[300]
    DIRECTION INPUT ;
    USE SIGNAL ;
    PORT
      LAYER M4 ;
        RECT  72.792 15.024 72.984 15.048 ;
    END
  END a[300]
  PIN a[301]
    DIRECTION INPUT ;
    USE SIGNAL ;
    PORT
      LAYER M4 ;
        RECT  72.792 15.072 72.984 15.096 ;
    END
  END a[301]
  PIN a[302]
    DIRECTION INPUT ;
    USE SIGNAL ;
    PORT
      LAYER M4 ;
        RECT  72.792 15.12 72.984 15.144 ;
    END
  END a[302]
  PIN a[303]
    DIRECTION INPUT ;
    USE SIGNAL ;
    PORT
      LAYER M4 ;
        RECT  72.792 15.168 72.984 15.192 ;
    END
  END a[303]
  PIN a[304]
    DIRECTION INPUT ;
    USE SIGNAL ;
    PORT
      LAYER M4 ;
        RECT  72.792 15.216 72.984 15.24 ;
    END
  END a[304]
  PIN a[305]
    DIRECTION INPUT ;
    USE SIGNAL ;
    PORT
      LAYER M4 ;
        RECT  72.792 15.264 72.984 15.288 ;
    END
  END a[305]
  PIN a[306]
    DIRECTION INPUT ;
    USE SIGNAL ;
    PORT
      LAYER M4 ;
        RECT  72.792 15.312 72.984 15.336 ;
    END
  END a[306]
  PIN a[307]
    DIRECTION INPUT ;
    USE SIGNAL ;
    PORT
      LAYER M4 ;
        RECT  72.792 15.36 72.984 15.384 ;
    END
  END a[307]
  PIN a[308]
    DIRECTION INPUT ;
    USE SIGNAL ;
    PORT
      LAYER M4 ;
        RECT  72.792 15.408 72.984 15.432 ;
    END
  END a[308]
  PIN a[309]
    DIRECTION INPUT ;
    USE SIGNAL ;
    PORT
      LAYER M4 ;
        RECT  72.792 15.456 72.984 15.48 ;
    END
  END a[309]
  PIN a[30]
    DIRECTION INPUT ;
    USE SIGNAL ;
    PORT
      LAYER M4 ;
        RECT  72.792 2.064 72.984 2.088 ;
    END
  END a[30]
  PIN a[310]
    DIRECTION INPUT ;
    USE SIGNAL ;
    PORT
      LAYER M4 ;
        RECT  72.792 15.504 72.984 15.528 ;
    END
  END a[310]
  PIN a[311]
    DIRECTION INPUT ;
    USE SIGNAL ;
    PORT
      LAYER M4 ;
        RECT  72.792 15.552 72.984 15.576 ;
    END
  END a[311]
  PIN a[312]
    DIRECTION INPUT ;
    USE SIGNAL ;
    PORT
      LAYER M4 ;
        RECT  72.792 15.6 72.984 15.624 ;
    END
  END a[312]
  PIN a[313]
    DIRECTION INPUT ;
    USE SIGNAL ;
    PORT
      LAYER M4 ;
        RECT  72.792 15.648 72.984 15.672 ;
    END
  END a[313]
  PIN a[314]
    DIRECTION INPUT ;
    USE SIGNAL ;
    PORT
      LAYER M4 ;
        RECT  72.792 15.696 72.984 15.72 ;
    END
  END a[314]
  PIN a[315]
    DIRECTION INPUT ;
    USE SIGNAL ;
    PORT
      LAYER M4 ;
        RECT  72.792 15.744 72.984 15.768 ;
    END
  END a[315]
  PIN a[316]
    DIRECTION INPUT ;
    USE SIGNAL ;
    PORT
      LAYER M4 ;
        RECT  72.792 15.792 72.984 15.816 ;
    END
  END a[316]
  PIN a[317]
    DIRECTION INPUT ;
    USE SIGNAL ;
    PORT
      LAYER M4 ;
        RECT  72.792 15.84 72.984 15.864 ;
    END
  END a[317]
  PIN a[318]
    DIRECTION INPUT ;
    USE SIGNAL ;
    PORT
      LAYER M4 ;
        RECT  72.792 15.888 72.984 15.912 ;
    END
  END a[318]
  PIN a[319]
    DIRECTION INPUT ;
    USE SIGNAL ;
    PORT
      LAYER M4 ;
        RECT  72.792 15.936 72.984 15.96 ;
    END
  END a[319]
  PIN a[31]
    DIRECTION INPUT ;
    USE SIGNAL ;
    PORT
      LAYER M4 ;
        RECT  72.792 2.112 72.984 2.136 ;
    END
  END a[31]
  PIN a[320]
    DIRECTION INPUT ;
    USE SIGNAL ;
    PORT
      LAYER M4 ;
        RECT  72.792 15.984 72.984 16.008 ;
    END
  END a[320]
  PIN a[321]
    DIRECTION INPUT ;
    USE SIGNAL ;
    PORT
      LAYER M4 ;
        RECT  72.792 16.032 72.984 16.056 ;
    END
  END a[321]
  PIN a[322]
    DIRECTION INPUT ;
    USE SIGNAL ;
    PORT
      LAYER M4 ;
        RECT  72.792 16.08 72.984 16.104 ;
    END
  END a[322]
  PIN a[323]
    DIRECTION INPUT ;
    USE SIGNAL ;
    PORT
      LAYER M4 ;
        RECT  72.792 16.128 72.984 16.152 ;
    END
  END a[323]
  PIN a[324]
    DIRECTION INPUT ;
    USE SIGNAL ;
    PORT
      LAYER M4 ;
        RECT  72.792 16.176 72.984 16.2 ;
    END
  END a[324]
  PIN a[325]
    DIRECTION INPUT ;
    USE SIGNAL ;
    PORT
      LAYER M4 ;
        RECT  72.792 16.224 72.984 16.248 ;
    END
  END a[325]
  PIN a[326]
    DIRECTION INPUT ;
    USE SIGNAL ;
    PORT
      LAYER M4 ;
        RECT  72.792 16.272 72.984 16.296 ;
    END
  END a[326]
  PIN a[327]
    DIRECTION INPUT ;
    USE SIGNAL ;
    PORT
      LAYER M4 ;
        RECT  72.792 16.32 72.984 16.344 ;
    END
  END a[327]
  PIN a[328]
    DIRECTION INPUT ;
    USE SIGNAL ;
    PORT
      LAYER M4 ;
        RECT  72.792 16.368 72.984 16.392 ;
    END
  END a[328]
  PIN a[329]
    DIRECTION INPUT ;
    USE SIGNAL ;
    PORT
      LAYER M4 ;
        RECT  72.792 16.416 72.984 16.44 ;
    END
  END a[329]
  PIN a[32]
    DIRECTION INPUT ;
    USE SIGNAL ;
    PORT
      LAYER M4 ;
        RECT  72.792 2.16 72.984 2.184 ;
    END
  END a[32]
  PIN a[330]
    DIRECTION INPUT ;
    USE SIGNAL ;
    PORT
      LAYER M4 ;
        RECT  72.792 16.464 72.984 16.488 ;
    END
  END a[330]
  PIN a[331]
    DIRECTION INPUT ;
    USE SIGNAL ;
    PORT
      LAYER M4 ;
        RECT  72.792 16.512 72.984 16.536 ;
    END
  END a[331]
  PIN a[332]
    DIRECTION INPUT ;
    USE SIGNAL ;
    PORT
      LAYER M4 ;
        RECT  72.792 16.56 72.984 16.584 ;
    END
  END a[332]
  PIN a[333]
    DIRECTION INPUT ;
    USE SIGNAL ;
    PORT
      LAYER M4 ;
        RECT  72.792 16.608 72.984 16.632 ;
    END
  END a[333]
  PIN a[334]
    DIRECTION INPUT ;
    USE SIGNAL ;
    PORT
      LAYER M4 ;
        RECT  72.792 16.656 72.984 16.68 ;
    END
  END a[334]
  PIN a[335]
    DIRECTION INPUT ;
    USE SIGNAL ;
    PORT
      LAYER M4 ;
        RECT  72.792 16.704 72.984 16.728 ;
    END
  END a[335]
  PIN a[336]
    DIRECTION INPUT ;
    USE SIGNAL ;
    PORT
      LAYER M4 ;
        RECT  72.792 16.752 72.984 16.776 ;
    END
  END a[336]
  PIN a[337]
    DIRECTION INPUT ;
    USE SIGNAL ;
    PORT
      LAYER M4 ;
        RECT  72.792 16.8 72.984 16.824 ;
    END
  END a[337]
  PIN a[338]
    DIRECTION INPUT ;
    USE SIGNAL ;
    PORT
      LAYER M4 ;
        RECT  72.792 16.848 72.984 16.872 ;
    END
  END a[338]
  PIN a[339]
    DIRECTION INPUT ;
    USE SIGNAL ;
    PORT
      LAYER M4 ;
        RECT  72.792 16.896 72.984 16.92 ;
    END
  END a[339]
  PIN a[33]
    DIRECTION INPUT ;
    USE SIGNAL ;
    PORT
      LAYER M4 ;
        RECT  72.792 2.208 72.984 2.232 ;
    END
  END a[33]
  PIN a[340]
    DIRECTION INPUT ;
    USE SIGNAL ;
    PORT
      LAYER M4 ;
        RECT  72.792 16.944 72.984 16.968 ;
    END
  END a[340]
  PIN a[341]
    DIRECTION INPUT ;
    USE SIGNAL ;
    PORT
      LAYER M4 ;
        RECT  72.792 16.992 72.984 17.016 ;
    END
  END a[341]
  PIN a[342]
    DIRECTION INPUT ;
    USE SIGNAL ;
    PORT
      LAYER M4 ;
        RECT  72.792 17.04 72.984 17.064 ;
    END
  END a[342]
  PIN a[343]
    DIRECTION INPUT ;
    USE SIGNAL ;
    PORT
      LAYER M4 ;
        RECT  72.792 17.088 72.984 17.112 ;
    END
  END a[343]
  PIN a[344]
    DIRECTION INPUT ;
    USE SIGNAL ;
    PORT
      LAYER M4 ;
        RECT  72.792 17.136 72.984 17.16 ;
    END
  END a[344]
  PIN a[345]
    DIRECTION INPUT ;
    USE SIGNAL ;
    PORT
      LAYER M4 ;
        RECT  72.792 17.184 72.984 17.208 ;
    END
  END a[345]
  PIN a[346]
    DIRECTION INPUT ;
    USE SIGNAL ;
    PORT
      LAYER M4 ;
        RECT  72.792 17.232 72.984 17.256 ;
    END
  END a[346]
  PIN a[347]
    DIRECTION INPUT ;
    USE SIGNAL ;
    PORT
      LAYER M4 ;
        RECT  72.792 17.28 72.984 17.304 ;
    END
  END a[347]
  PIN a[348]
    DIRECTION INPUT ;
    USE SIGNAL ;
    PORT
      LAYER M4 ;
        RECT  72.792 17.328 72.984 17.352 ;
    END
  END a[348]
  PIN a[349]
    DIRECTION INPUT ;
    USE SIGNAL ;
    PORT
      LAYER M4 ;
        RECT  72.792 17.376 72.984 17.4 ;
    END
  END a[349]
  PIN a[34]
    DIRECTION INPUT ;
    USE SIGNAL ;
    PORT
      LAYER M4 ;
        RECT  72.792 2.256 72.984 2.28 ;
    END
  END a[34]
  PIN a[350]
    DIRECTION INPUT ;
    USE SIGNAL ;
    PORT
      LAYER M4 ;
        RECT  72.792 17.424 72.984 17.448 ;
    END
  END a[350]
  PIN a[351]
    DIRECTION INPUT ;
    USE SIGNAL ;
    PORT
      LAYER M4 ;
        RECT  72.792 17.472 72.984 17.496 ;
    END
  END a[351]
  PIN a[352]
    DIRECTION INPUT ;
    USE SIGNAL ;
    PORT
      LAYER M4 ;
        RECT  72.792 17.52 72.984 17.544 ;
    END
  END a[352]
  PIN a[353]
    DIRECTION INPUT ;
    USE SIGNAL ;
    PORT
      LAYER M4 ;
        RECT  72.792 17.568 72.984 17.592 ;
    END
  END a[353]
  PIN a[354]
    DIRECTION INPUT ;
    USE SIGNAL ;
    PORT
      LAYER M4 ;
        RECT  72.792 17.616 72.984 17.64 ;
    END
  END a[354]
  PIN a[355]
    DIRECTION INPUT ;
    USE SIGNAL ;
    PORT
      LAYER M4 ;
        RECT  72.792 17.664 72.984 17.688 ;
    END
  END a[355]
  PIN a[356]
    DIRECTION INPUT ;
    USE SIGNAL ;
    PORT
      LAYER M4 ;
        RECT  72.792 17.712 72.984 17.736 ;
    END
  END a[356]
  PIN a[357]
    DIRECTION INPUT ;
    USE SIGNAL ;
    PORT
      LAYER M4 ;
        RECT  72.792 17.76 72.984 17.784 ;
    END
  END a[357]
  PIN a[358]
    DIRECTION INPUT ;
    USE SIGNAL ;
    PORT
      LAYER M4 ;
        RECT  72.792 17.808 72.984 17.832 ;
    END
  END a[358]
  PIN a[359]
    DIRECTION INPUT ;
    USE SIGNAL ;
    PORT
      LAYER M4 ;
        RECT  72.792 17.856 72.984 17.88 ;
    END
  END a[359]
  PIN a[35]
    DIRECTION INPUT ;
    USE SIGNAL ;
    PORT
      LAYER M4 ;
        RECT  72.792 2.304 72.984 2.328 ;
    END
  END a[35]
  PIN a[360]
    DIRECTION INPUT ;
    USE SIGNAL ;
    PORT
      LAYER M4 ;
        RECT  72.792 17.904 72.984 17.928 ;
    END
  END a[360]
  PIN a[361]
    DIRECTION INPUT ;
    USE SIGNAL ;
    PORT
      LAYER M4 ;
        RECT  72.792 17.952 72.984 17.976 ;
    END
  END a[361]
  PIN a[362]
    DIRECTION INPUT ;
    USE SIGNAL ;
    PORT
      LAYER M4 ;
        RECT  72.792 18 72.984 18.024 ;
    END
  END a[362]
  PIN a[363]
    DIRECTION INPUT ;
    USE SIGNAL ;
    PORT
      LAYER M4 ;
        RECT  72.792 18.048 72.984 18.072 ;
    END
  END a[363]
  PIN a[364]
    DIRECTION INPUT ;
    USE SIGNAL ;
    PORT
      LAYER M4 ;
        RECT  72.792 18.096 72.984 18.12 ;
    END
  END a[364]
  PIN a[365]
    DIRECTION INPUT ;
    USE SIGNAL ;
    PORT
      LAYER M4 ;
        RECT  72.792 18.144 72.984 18.168 ;
    END
  END a[365]
  PIN a[366]
    DIRECTION INPUT ;
    USE SIGNAL ;
    PORT
      LAYER M4 ;
        RECT  72.792 18.192 72.984 18.216 ;
    END
  END a[366]
  PIN a[367]
    DIRECTION INPUT ;
    USE SIGNAL ;
    PORT
      LAYER M4 ;
        RECT  72.792 18.24 72.984 18.264 ;
    END
  END a[367]
  PIN a[368]
    DIRECTION INPUT ;
    USE SIGNAL ;
    PORT
      LAYER M4 ;
        RECT  72.792 18.288 72.984 18.312 ;
    END
  END a[368]
  PIN a[369]
    DIRECTION INPUT ;
    USE SIGNAL ;
    PORT
      LAYER M4 ;
        RECT  72.792 18.336 72.984 18.36 ;
    END
  END a[369]
  PIN a[36]
    DIRECTION INPUT ;
    USE SIGNAL ;
    PORT
      LAYER M4 ;
        RECT  72.792 2.352 72.984 2.376 ;
    END
  END a[36]
  PIN a[370]
    DIRECTION INPUT ;
    USE SIGNAL ;
    PORT
      LAYER M4 ;
        RECT  72.792 18.384 72.984 18.408 ;
    END
  END a[370]
  PIN a[371]
    DIRECTION INPUT ;
    USE SIGNAL ;
    PORT
      LAYER M4 ;
        RECT  72.792 18.432 72.984 18.456 ;
    END
  END a[371]
  PIN a[372]
    DIRECTION INPUT ;
    USE SIGNAL ;
    PORT
      LAYER M4 ;
        RECT  72.792 18.48 72.984 18.504 ;
    END
  END a[372]
  PIN a[373]
    DIRECTION INPUT ;
    USE SIGNAL ;
    PORT
      LAYER M4 ;
        RECT  72.792 18.528 72.984 18.552 ;
    END
  END a[373]
  PIN a[374]
    DIRECTION INPUT ;
    USE SIGNAL ;
    PORT
      LAYER M4 ;
        RECT  72.792 18.576 72.984 18.6 ;
    END
  END a[374]
  PIN a[375]
    DIRECTION INPUT ;
    USE SIGNAL ;
    PORT
      LAYER M4 ;
        RECT  72.792 18.624 72.984 18.648 ;
    END
  END a[375]
  PIN a[376]
    DIRECTION INPUT ;
    USE SIGNAL ;
    PORT
      LAYER M4 ;
        RECT  72.792 18.672 72.984 18.696 ;
    END
  END a[376]
  PIN a[377]
    DIRECTION INPUT ;
    USE SIGNAL ;
    PORT
      LAYER M4 ;
        RECT  72.792 18.72 72.984 18.744 ;
    END
  END a[377]
  PIN a[378]
    DIRECTION INPUT ;
    USE SIGNAL ;
    PORT
      LAYER M4 ;
        RECT  72.792 18.768 72.984 18.792 ;
    END
  END a[378]
  PIN a[379]
    DIRECTION INPUT ;
    USE SIGNAL ;
    PORT
      LAYER M4 ;
        RECT  72.792 18.816 72.984 18.84 ;
    END
  END a[379]
  PIN a[37]
    DIRECTION INPUT ;
    USE SIGNAL ;
    PORT
      LAYER M4 ;
        RECT  72.792 2.4 72.984 2.424 ;
    END
  END a[37]
  PIN a[380]
    DIRECTION INPUT ;
    USE SIGNAL ;
    PORT
      LAYER M4 ;
        RECT  72.792 18.864 72.984 18.888 ;
    END
  END a[380]
  PIN a[381]
    DIRECTION INPUT ;
    USE SIGNAL ;
    PORT
      LAYER M4 ;
        RECT  72.792 18.912 72.984 18.936 ;
    END
  END a[381]
  PIN a[382]
    DIRECTION INPUT ;
    USE SIGNAL ;
    PORT
      LAYER M4 ;
        RECT  72.792 18.96 72.984 18.984 ;
    END
  END a[382]
  PIN a[383]
    DIRECTION INPUT ;
    USE SIGNAL ;
    PORT
      LAYER M4 ;
        RECT  72.792 19.008 72.984 19.032 ;
    END
  END a[383]
  PIN a[384]
    DIRECTION INPUT ;
    USE SIGNAL ;
    PORT
      LAYER M4 ;
        RECT  72.792 19.056 72.984 19.08 ;
    END
  END a[384]
  PIN a[385]
    DIRECTION INPUT ;
    USE SIGNAL ;
    PORT
      LAYER M4 ;
        RECT  72.792 19.104 72.984 19.128 ;
    END
  END a[385]
  PIN a[386]
    DIRECTION INPUT ;
    USE SIGNAL ;
    PORT
      LAYER M4 ;
        RECT  72.792 19.152 72.984 19.176 ;
    END
  END a[386]
  PIN a[387]
    DIRECTION INPUT ;
    USE SIGNAL ;
    PORT
      LAYER M4 ;
        RECT  72.792 19.2 72.984 19.224 ;
    END
  END a[387]
  PIN a[388]
    DIRECTION INPUT ;
    USE SIGNAL ;
    PORT
      LAYER M4 ;
        RECT  72.792 19.248 72.984 19.272 ;
    END
  END a[388]
  PIN a[389]
    DIRECTION INPUT ;
    USE SIGNAL ;
    PORT
      LAYER M4 ;
        RECT  72.792 19.296 72.984 19.32 ;
    END
  END a[389]
  PIN a[38]
    DIRECTION INPUT ;
    USE SIGNAL ;
    PORT
      LAYER M4 ;
        RECT  72.792 2.448 72.984 2.472 ;
    END
  END a[38]
  PIN a[390]
    DIRECTION INPUT ;
    USE SIGNAL ;
    PORT
      LAYER M4 ;
        RECT  72.792 19.344 72.984 19.368 ;
    END
  END a[390]
  PIN a[391]
    DIRECTION INPUT ;
    USE SIGNAL ;
    PORT
      LAYER M4 ;
        RECT  72.792 19.392 72.984 19.416 ;
    END
  END a[391]
  PIN a[392]
    DIRECTION INPUT ;
    USE SIGNAL ;
    PORT
      LAYER M4 ;
        RECT  72.792 19.44 72.984 19.464 ;
    END
  END a[392]
  PIN a[393]
    DIRECTION INPUT ;
    USE SIGNAL ;
    PORT
      LAYER M4 ;
        RECT  72.792 19.488 72.984 19.512 ;
    END
  END a[393]
  PIN a[394]
    DIRECTION INPUT ;
    USE SIGNAL ;
    PORT
      LAYER M4 ;
        RECT  72.792 19.536 72.984 19.56 ;
    END
  END a[394]
  PIN a[395]
    DIRECTION INPUT ;
    USE SIGNAL ;
    PORT
      LAYER M4 ;
        RECT  72.792 19.584 72.984 19.608 ;
    END
  END a[395]
  PIN a[396]
    DIRECTION INPUT ;
    USE SIGNAL ;
    PORT
      LAYER M4 ;
        RECT  72.792 19.632 72.984 19.656 ;
    END
  END a[396]
  PIN a[397]
    DIRECTION INPUT ;
    USE SIGNAL ;
    PORT
      LAYER M4 ;
        RECT  72.792 19.68 72.984 19.704 ;
    END
  END a[397]
  PIN a[398]
    DIRECTION INPUT ;
    USE SIGNAL ;
    PORT
      LAYER M4 ;
        RECT  72.792 19.728 72.984 19.752 ;
    END
  END a[398]
  PIN a[399]
    DIRECTION INPUT ;
    USE SIGNAL ;
    PORT
      LAYER M4 ;
        RECT  72.792 19.776 72.984 19.8 ;
    END
  END a[399]
  PIN a[39]
    DIRECTION INPUT ;
    USE SIGNAL ;
    PORT
      LAYER M4 ;
        RECT  72.792 2.496 72.984 2.52 ;
    END
  END a[39]
  PIN a[3]
    DIRECTION INPUT ;
    USE SIGNAL ;
    PORT
      LAYER M4 ;
        RECT  72.792 0.768 72.984 0.792 ;
    END
  END a[3]
  PIN a[400]
    DIRECTION INPUT ;
    USE SIGNAL ;
    PORT
      LAYER M4 ;
        RECT  72.792 19.824 72.984 19.848 ;
    END
  END a[400]
  PIN a[401]
    DIRECTION INPUT ;
    USE SIGNAL ;
    PORT
      LAYER M4 ;
        RECT  72.792 19.872 72.984 19.896 ;
    END
  END a[401]
  PIN a[402]
    DIRECTION INPUT ;
    USE SIGNAL ;
    PORT
      LAYER M4 ;
        RECT  72.792 19.92 72.984 19.944 ;
    END
  END a[402]
  PIN a[403]
    DIRECTION INPUT ;
    USE SIGNAL ;
    PORT
      LAYER M4 ;
        RECT  72.792 19.968 72.984 19.992 ;
    END
  END a[403]
  PIN a[404]
    DIRECTION INPUT ;
    USE SIGNAL ;
    PORT
      LAYER M4 ;
        RECT  72.792 20.016 72.984 20.04 ;
    END
  END a[404]
  PIN a[405]
    DIRECTION INPUT ;
    USE SIGNAL ;
    PORT
      LAYER M4 ;
        RECT  72.792 20.064 72.984 20.088 ;
    END
  END a[405]
  PIN a[406]
    DIRECTION INPUT ;
    USE SIGNAL ;
    PORT
      LAYER M4 ;
        RECT  72.792 20.112 72.984 20.136 ;
    END
  END a[406]
  PIN a[407]
    DIRECTION INPUT ;
    USE SIGNAL ;
    PORT
      LAYER M4 ;
        RECT  72.792 20.16 72.984 20.184 ;
    END
  END a[407]
  PIN a[408]
    DIRECTION INPUT ;
    USE SIGNAL ;
    PORT
      LAYER M4 ;
        RECT  72.792 20.208 72.984 20.232 ;
    END
  END a[408]
  PIN a[409]
    DIRECTION INPUT ;
    USE SIGNAL ;
    PORT
      LAYER M4 ;
        RECT  72.792 20.256 72.984 20.28 ;
    END
  END a[409]
  PIN a[40]
    DIRECTION INPUT ;
    USE SIGNAL ;
    PORT
      LAYER M4 ;
        RECT  72.792 2.544 72.984 2.568 ;
    END
  END a[40]
  PIN a[410]
    DIRECTION INPUT ;
    USE SIGNAL ;
    PORT
      LAYER M4 ;
        RECT  72.792 20.304 72.984 20.328 ;
    END
  END a[410]
  PIN a[411]
    DIRECTION INPUT ;
    USE SIGNAL ;
    PORT
      LAYER M4 ;
        RECT  72.792 20.352 72.984 20.376 ;
    END
  END a[411]
  PIN a[412]
    DIRECTION INPUT ;
    USE SIGNAL ;
    PORT
      LAYER M4 ;
        RECT  72.792 20.4 72.984 20.424 ;
    END
  END a[412]
  PIN a[413]
    DIRECTION INPUT ;
    USE SIGNAL ;
    PORT
      LAYER M4 ;
        RECT  72.792 20.448 72.984 20.472 ;
    END
  END a[413]
  PIN a[414]
    DIRECTION INPUT ;
    USE SIGNAL ;
    PORT
      LAYER M4 ;
        RECT  72.792 20.496 72.984 20.52 ;
    END
  END a[414]
  PIN a[415]
    DIRECTION INPUT ;
    USE SIGNAL ;
    PORT
      LAYER M4 ;
        RECT  72.792 20.544 72.984 20.568 ;
    END
  END a[415]
  PIN a[416]
    DIRECTION INPUT ;
    USE SIGNAL ;
    PORT
      LAYER M4 ;
        RECT  72.792 20.592 72.984 20.616 ;
    END
  END a[416]
  PIN a[417]
    DIRECTION INPUT ;
    USE SIGNAL ;
    PORT
      LAYER M4 ;
        RECT  72.792 20.64 72.984 20.664 ;
    END
  END a[417]
  PIN a[418]
    DIRECTION INPUT ;
    USE SIGNAL ;
    PORT
      LAYER M4 ;
        RECT  72.792 20.688 72.984 20.712 ;
    END
  END a[418]
  PIN a[419]
    DIRECTION INPUT ;
    USE SIGNAL ;
    PORT
      LAYER M4 ;
        RECT  72.792 20.736 72.984 20.76 ;
    END
  END a[419]
  PIN a[41]
    DIRECTION INPUT ;
    USE SIGNAL ;
    PORT
      LAYER M4 ;
        RECT  72.792 2.592 72.984 2.616 ;
    END
  END a[41]
  PIN a[420]
    DIRECTION INPUT ;
    USE SIGNAL ;
    PORT
      LAYER M4 ;
        RECT  72.792 20.784 72.984 20.808 ;
    END
  END a[420]
  PIN a[421]
    DIRECTION INPUT ;
    USE SIGNAL ;
    PORT
      LAYER M4 ;
        RECT  72.792 20.832 72.984 20.856 ;
    END
  END a[421]
  PIN a[422]
    DIRECTION INPUT ;
    USE SIGNAL ;
    PORT
      LAYER M4 ;
        RECT  72.792 20.88 72.984 20.904 ;
    END
  END a[422]
  PIN a[423]
    DIRECTION INPUT ;
    USE SIGNAL ;
    PORT
      LAYER M4 ;
        RECT  72.792 20.928 72.984 20.952 ;
    END
  END a[423]
  PIN a[424]
    DIRECTION INPUT ;
    USE SIGNAL ;
    PORT
      LAYER M4 ;
        RECT  72.792 20.976 72.984 21 ;
    END
  END a[424]
  PIN a[425]
    DIRECTION INPUT ;
    USE SIGNAL ;
    PORT
      LAYER M4 ;
        RECT  72.792 21.024 72.984 21.048 ;
    END
  END a[425]
  PIN a[426]
    DIRECTION INPUT ;
    USE SIGNAL ;
    PORT
      LAYER M4 ;
        RECT  72.792 21.072 72.984 21.096 ;
    END
  END a[426]
  PIN a[427]
    DIRECTION INPUT ;
    USE SIGNAL ;
    PORT
      LAYER M4 ;
        RECT  72.792 21.12 72.984 21.144 ;
    END
  END a[427]
  PIN a[428]
    DIRECTION INPUT ;
    USE SIGNAL ;
    PORT
      LAYER M4 ;
        RECT  72.792 21.168 72.984 21.192 ;
    END
  END a[428]
  PIN a[429]
    DIRECTION INPUT ;
    USE SIGNAL ;
    PORT
      LAYER M4 ;
        RECT  72.792 21.216 72.984 21.24 ;
    END
  END a[429]
  PIN a[42]
    DIRECTION INPUT ;
    USE SIGNAL ;
    PORT
      LAYER M4 ;
        RECT  72.792 2.64 72.984 2.664 ;
    END
  END a[42]
  PIN a[430]
    DIRECTION INPUT ;
    USE SIGNAL ;
    PORT
      LAYER M4 ;
        RECT  72.792 21.264 72.984 21.288 ;
    END
  END a[430]
  PIN a[431]
    DIRECTION INPUT ;
    USE SIGNAL ;
    PORT
      LAYER M4 ;
        RECT  72.792 21.312 72.984 21.336 ;
    END
  END a[431]
  PIN a[432]
    DIRECTION INPUT ;
    USE SIGNAL ;
    PORT
      LAYER M4 ;
        RECT  72.792 21.36 72.984 21.384 ;
    END
  END a[432]
  PIN a[433]
    DIRECTION INPUT ;
    USE SIGNAL ;
    PORT
      LAYER M4 ;
        RECT  72.792 21.408 72.984 21.432 ;
    END
  END a[433]
  PIN a[434]
    DIRECTION INPUT ;
    USE SIGNAL ;
    PORT
      LAYER M4 ;
        RECT  72.792 21.456 72.984 21.48 ;
    END
  END a[434]
  PIN a[435]
    DIRECTION INPUT ;
    USE SIGNAL ;
    PORT
      LAYER M4 ;
        RECT  72.792 21.504 72.984 21.528 ;
    END
  END a[435]
  PIN a[436]
    DIRECTION INPUT ;
    USE SIGNAL ;
    PORT
      LAYER M4 ;
        RECT  72.792 21.552 72.984 21.576 ;
    END
  END a[436]
  PIN a[437]
    DIRECTION INPUT ;
    USE SIGNAL ;
    PORT
      LAYER M4 ;
        RECT  72.792 21.6 72.984 21.624 ;
    END
  END a[437]
  PIN a[438]
    DIRECTION INPUT ;
    USE SIGNAL ;
    PORT
      LAYER M4 ;
        RECT  72.792 21.648 72.984 21.672 ;
    END
  END a[438]
  PIN a[439]
    DIRECTION INPUT ;
    USE SIGNAL ;
    PORT
      LAYER M4 ;
        RECT  72.792 21.696 72.984 21.72 ;
    END
  END a[439]
  PIN a[43]
    DIRECTION INPUT ;
    USE SIGNAL ;
    PORT
      LAYER M4 ;
        RECT  72.792 2.688 72.984 2.712 ;
    END
  END a[43]
  PIN a[440]
    DIRECTION INPUT ;
    USE SIGNAL ;
    PORT
      LAYER M4 ;
        RECT  72.792 21.744 72.984 21.768 ;
    END
  END a[440]
  PIN a[441]
    DIRECTION INPUT ;
    USE SIGNAL ;
    PORT
      LAYER M4 ;
        RECT  72.792 21.792 72.984 21.816 ;
    END
  END a[441]
  PIN a[442]
    DIRECTION INPUT ;
    USE SIGNAL ;
    PORT
      LAYER M4 ;
        RECT  72.792 21.84 72.984 21.864 ;
    END
  END a[442]
  PIN a[443]
    DIRECTION INPUT ;
    USE SIGNAL ;
    PORT
      LAYER M4 ;
        RECT  72.792 21.888 72.984 21.912 ;
    END
  END a[443]
  PIN a[444]
    DIRECTION INPUT ;
    USE SIGNAL ;
    PORT
      LAYER M4 ;
        RECT  72.792 21.936 72.984 21.96 ;
    END
  END a[444]
  PIN a[445]
    DIRECTION INPUT ;
    USE SIGNAL ;
    PORT
      LAYER M4 ;
        RECT  72.792 21.984 72.984 22.008 ;
    END
  END a[445]
  PIN a[446]
    DIRECTION INPUT ;
    USE SIGNAL ;
    PORT
      LAYER M4 ;
        RECT  72.792 22.032 72.984 22.056 ;
    END
  END a[446]
  PIN a[447]
    DIRECTION INPUT ;
    USE SIGNAL ;
    PORT
      LAYER M4 ;
        RECT  72.792 22.08 72.984 22.104 ;
    END
  END a[447]
  PIN a[448]
    DIRECTION INPUT ;
    USE SIGNAL ;
    PORT
      LAYER M4 ;
        RECT  72.792 22.128 72.984 22.152 ;
    END
  END a[448]
  PIN a[449]
    DIRECTION INPUT ;
    USE SIGNAL ;
    PORT
      LAYER M4 ;
        RECT  72.792 22.176 72.984 22.2 ;
    END
  END a[449]
  PIN a[44]
    DIRECTION INPUT ;
    USE SIGNAL ;
    PORT
      LAYER M4 ;
        RECT  72.792 2.736 72.984 2.76 ;
    END
  END a[44]
  PIN a[450]
    DIRECTION INPUT ;
    USE SIGNAL ;
    PORT
      LAYER M4 ;
        RECT  72.792 22.224 72.984 22.248 ;
    END
  END a[450]
  PIN a[451]
    DIRECTION INPUT ;
    USE SIGNAL ;
    PORT
      LAYER M4 ;
        RECT  72.792 22.272 72.984 22.296 ;
    END
  END a[451]
  PIN a[452]
    DIRECTION INPUT ;
    USE SIGNAL ;
    PORT
      LAYER M4 ;
        RECT  72.792 22.32 72.984 22.344 ;
    END
  END a[452]
  PIN a[453]
    DIRECTION INPUT ;
    USE SIGNAL ;
    PORT
      LAYER M4 ;
        RECT  72.792 22.368 72.984 22.392 ;
    END
  END a[453]
  PIN a[454]
    DIRECTION INPUT ;
    USE SIGNAL ;
    PORT
      LAYER M4 ;
        RECT  72.792 22.416 72.984 22.44 ;
    END
  END a[454]
  PIN a[455]
    DIRECTION INPUT ;
    USE SIGNAL ;
    PORT
      LAYER M4 ;
        RECT  72.792 22.464 72.984 22.488 ;
    END
  END a[455]
  PIN a[456]
    DIRECTION INPUT ;
    USE SIGNAL ;
    PORT
      LAYER M4 ;
        RECT  72.792 22.512 72.984 22.536 ;
    END
  END a[456]
  PIN a[457]
    DIRECTION INPUT ;
    USE SIGNAL ;
    PORT
      LAYER M4 ;
        RECT  72.792 22.56 72.984 22.584 ;
    END
  END a[457]
  PIN a[458]
    DIRECTION INPUT ;
    USE SIGNAL ;
    PORT
      LAYER M4 ;
        RECT  72.792 22.608 72.984 22.632 ;
    END
  END a[458]
  PIN a[459]
    DIRECTION INPUT ;
    USE SIGNAL ;
    PORT
      LAYER M4 ;
        RECT  72.792 22.656 72.984 22.68 ;
    END
  END a[459]
  PIN a[45]
    DIRECTION INPUT ;
    USE SIGNAL ;
    PORT
      LAYER M4 ;
        RECT  72.792 2.784 72.984 2.808 ;
    END
  END a[45]
  PIN a[460]
    DIRECTION INPUT ;
    USE SIGNAL ;
    PORT
      LAYER M4 ;
        RECT  72.792 22.704 72.984 22.728 ;
    END
  END a[460]
  PIN a[461]
    DIRECTION INPUT ;
    USE SIGNAL ;
    PORT
      LAYER M4 ;
        RECT  72.792 22.752 72.984 22.776 ;
    END
  END a[461]
  PIN a[462]
    DIRECTION INPUT ;
    USE SIGNAL ;
    PORT
      LAYER M4 ;
        RECT  72.792 22.8 72.984 22.824 ;
    END
  END a[462]
  PIN a[463]
    DIRECTION INPUT ;
    USE SIGNAL ;
    PORT
      LAYER M4 ;
        RECT  72.792 22.848 72.984 22.872 ;
    END
  END a[463]
  PIN a[464]
    DIRECTION INPUT ;
    USE SIGNAL ;
    PORT
      LAYER M4 ;
        RECT  72.792 22.896 72.984 22.92 ;
    END
  END a[464]
  PIN a[465]
    DIRECTION INPUT ;
    USE SIGNAL ;
    PORT
      LAYER M4 ;
        RECT  72.792 22.944 72.984 22.968 ;
    END
  END a[465]
  PIN a[466]
    DIRECTION INPUT ;
    USE SIGNAL ;
    PORT
      LAYER M4 ;
        RECT  72.792 22.992 72.984 23.016 ;
    END
  END a[466]
  PIN a[467]
    DIRECTION INPUT ;
    USE SIGNAL ;
    PORT
      LAYER M4 ;
        RECT  72.792 23.04 72.984 23.064 ;
    END
  END a[467]
  PIN a[468]
    DIRECTION INPUT ;
    USE SIGNAL ;
    PORT
      LAYER M4 ;
        RECT  72.792 23.088 72.984 23.112 ;
    END
  END a[468]
  PIN a[469]
    DIRECTION INPUT ;
    USE SIGNAL ;
    PORT
      LAYER M4 ;
        RECT  72.792 23.136 72.984 23.16 ;
    END
  END a[469]
  PIN a[46]
    DIRECTION INPUT ;
    USE SIGNAL ;
    PORT
      LAYER M4 ;
        RECT  72.792 2.832 72.984 2.856 ;
    END
  END a[46]
  PIN a[470]
    DIRECTION INPUT ;
    USE SIGNAL ;
    PORT
      LAYER M4 ;
        RECT  72.792 23.184 72.984 23.208 ;
    END
  END a[470]
  PIN a[471]
    DIRECTION INPUT ;
    USE SIGNAL ;
    PORT
      LAYER M4 ;
        RECT  72.792 23.232 72.984 23.256 ;
    END
  END a[471]
  PIN a[472]
    DIRECTION INPUT ;
    USE SIGNAL ;
    PORT
      LAYER M4 ;
        RECT  72.792 23.28 72.984 23.304 ;
    END
  END a[472]
  PIN a[473]
    DIRECTION INPUT ;
    USE SIGNAL ;
    PORT
      LAYER M4 ;
        RECT  72.792 23.328 72.984 23.352 ;
    END
  END a[473]
  PIN a[474]
    DIRECTION INPUT ;
    USE SIGNAL ;
    PORT
      LAYER M4 ;
        RECT  72.792 23.376 72.984 23.4 ;
    END
  END a[474]
  PIN a[475]
    DIRECTION INPUT ;
    USE SIGNAL ;
    PORT
      LAYER M4 ;
        RECT  72.792 23.424 72.984 23.448 ;
    END
  END a[475]
  PIN a[476]
    DIRECTION INPUT ;
    USE SIGNAL ;
    PORT
      LAYER M4 ;
        RECT  72.792 23.472 72.984 23.496 ;
    END
  END a[476]
  PIN a[477]
    DIRECTION INPUT ;
    USE SIGNAL ;
    PORT
      LAYER M4 ;
        RECT  72.792 23.52 72.984 23.544 ;
    END
  END a[477]
  PIN a[478]
    DIRECTION INPUT ;
    USE SIGNAL ;
    PORT
      LAYER M4 ;
        RECT  72.792 23.568 72.984 23.592 ;
    END
  END a[478]
  PIN a[479]
    DIRECTION INPUT ;
    USE SIGNAL ;
    PORT
      LAYER M4 ;
        RECT  72.792 23.616 72.984 23.64 ;
    END
  END a[479]
  PIN a[47]
    DIRECTION INPUT ;
    USE SIGNAL ;
    PORT
      LAYER M4 ;
        RECT  72.792 2.88 72.984 2.904 ;
    END
  END a[47]
  PIN a[480]
    DIRECTION INPUT ;
    USE SIGNAL ;
    PORT
      LAYER M4 ;
        RECT  72.792 23.664 72.984 23.688 ;
    END
  END a[480]
  PIN a[481]
    DIRECTION INPUT ;
    USE SIGNAL ;
    PORT
      LAYER M4 ;
        RECT  72.792 23.712 72.984 23.736 ;
    END
  END a[481]
  PIN a[482]
    DIRECTION INPUT ;
    USE SIGNAL ;
    PORT
      LAYER M4 ;
        RECT  72.792 23.76 72.984 23.784 ;
    END
  END a[482]
  PIN a[483]
    DIRECTION INPUT ;
    USE SIGNAL ;
    PORT
      LAYER M4 ;
        RECT  72.792 23.808 72.984 23.832 ;
    END
  END a[483]
  PIN a[484]
    DIRECTION INPUT ;
    USE SIGNAL ;
    PORT
      LAYER M4 ;
        RECT  72.792 23.856 72.984 23.88 ;
    END
  END a[484]
  PIN a[485]
    DIRECTION INPUT ;
    USE SIGNAL ;
    PORT
      LAYER M4 ;
        RECT  72.792 23.904 72.984 23.928 ;
    END
  END a[485]
  PIN a[486]
    DIRECTION INPUT ;
    USE SIGNAL ;
    PORT
      LAYER M4 ;
        RECT  72.792 23.952 72.984 23.976 ;
    END
  END a[486]
  PIN a[487]
    DIRECTION INPUT ;
    USE SIGNAL ;
    PORT
      LAYER M4 ;
        RECT  72.792 24 72.984 24.024 ;
    END
  END a[487]
  PIN a[488]
    DIRECTION INPUT ;
    USE SIGNAL ;
    PORT
      LAYER M4 ;
        RECT  72.792 24.048 72.984 24.072 ;
    END
  END a[488]
  PIN a[489]
    DIRECTION INPUT ;
    USE SIGNAL ;
    PORT
      LAYER M4 ;
        RECT  72.792 24.096 72.984 24.12 ;
    END
  END a[489]
  PIN a[48]
    DIRECTION INPUT ;
    USE SIGNAL ;
    PORT
      LAYER M4 ;
        RECT  72.792 2.928 72.984 2.952 ;
    END
  END a[48]
  PIN a[490]
    DIRECTION INPUT ;
    USE SIGNAL ;
    PORT
      LAYER M4 ;
        RECT  72.792 24.144 72.984 24.168 ;
    END
  END a[490]
  PIN a[491]
    DIRECTION INPUT ;
    USE SIGNAL ;
    PORT
      LAYER M4 ;
        RECT  72.792 24.192 72.984 24.216 ;
    END
  END a[491]
  PIN a[492]
    DIRECTION INPUT ;
    USE SIGNAL ;
    PORT
      LAYER M4 ;
        RECT  72.792 24.24 72.984 24.264 ;
    END
  END a[492]
  PIN a[493]
    DIRECTION INPUT ;
    USE SIGNAL ;
    PORT
      LAYER M4 ;
        RECT  72.792 24.288 72.984 24.312 ;
    END
  END a[493]
  PIN a[494]
    DIRECTION INPUT ;
    USE SIGNAL ;
    PORT
      LAYER M4 ;
        RECT  72.792 24.336 72.984 24.36 ;
    END
  END a[494]
  PIN a[495]
    DIRECTION INPUT ;
    USE SIGNAL ;
    PORT
      LAYER M4 ;
        RECT  72.792 24.384 72.984 24.408 ;
    END
  END a[495]
  PIN a[496]
    DIRECTION INPUT ;
    USE SIGNAL ;
    PORT
      LAYER M4 ;
        RECT  72.792 24.432 72.984 24.456 ;
    END
  END a[496]
  PIN a[497]
    DIRECTION INPUT ;
    USE SIGNAL ;
    PORT
      LAYER M4 ;
        RECT  72.792 24.48 72.984 24.504 ;
    END
  END a[497]
  PIN a[498]
    DIRECTION INPUT ;
    USE SIGNAL ;
    PORT
      LAYER M4 ;
        RECT  72.792 24.528 72.984 24.552 ;
    END
  END a[498]
  PIN a[499]
    DIRECTION INPUT ;
    USE SIGNAL ;
    PORT
      LAYER M4 ;
        RECT  72.792 24.576 72.984 24.6 ;
    END
  END a[499]
  PIN a[49]
    DIRECTION INPUT ;
    USE SIGNAL ;
    PORT
      LAYER M4 ;
        RECT  72.792 2.976 72.984 3 ;
    END
  END a[49]
  PIN a[4]
    DIRECTION INPUT ;
    USE SIGNAL ;
    PORT
      LAYER M4 ;
        RECT  72.792 0.816 72.984 0.84 ;
    END
  END a[4]
  PIN a[500]
    DIRECTION INPUT ;
    USE SIGNAL ;
    PORT
      LAYER M4 ;
        RECT  72.792 24.624 72.984 24.648 ;
    END
  END a[500]
  PIN a[501]
    DIRECTION INPUT ;
    USE SIGNAL ;
    PORT
      LAYER M4 ;
        RECT  72.792 24.672 72.984 24.696 ;
    END
  END a[501]
  PIN a[502]
    DIRECTION INPUT ;
    USE SIGNAL ;
    PORT
      LAYER M4 ;
        RECT  72.792 24.72 72.984 24.744 ;
    END
  END a[502]
  PIN a[503]
    DIRECTION INPUT ;
    USE SIGNAL ;
    PORT
      LAYER M4 ;
        RECT  72.792 24.768 72.984 24.792 ;
    END
  END a[503]
  PIN a[504]
    DIRECTION INPUT ;
    USE SIGNAL ;
    PORT
      LAYER M4 ;
        RECT  72.792 24.816 72.984 24.84 ;
    END
  END a[504]
  PIN a[505]
    DIRECTION INPUT ;
    USE SIGNAL ;
    PORT
      LAYER M4 ;
        RECT  72.792 24.864 72.984 24.888 ;
    END
  END a[505]
  PIN a[506]
    DIRECTION INPUT ;
    USE SIGNAL ;
    PORT
      LAYER M4 ;
        RECT  72.792 24.912 72.984 24.936 ;
    END
  END a[506]
  PIN a[507]
    DIRECTION INPUT ;
    USE SIGNAL ;
    PORT
      LAYER M4 ;
        RECT  72.792 24.96 72.984 24.984 ;
    END
  END a[507]
  PIN a[508]
    DIRECTION INPUT ;
    USE SIGNAL ;
    PORT
      LAYER M4 ;
        RECT  72.792 25.008 72.984 25.032 ;
    END
  END a[508]
  PIN a[509]
    DIRECTION INPUT ;
    USE SIGNAL ;
    PORT
      LAYER M4 ;
        RECT  72.792 25.056 72.984 25.08 ;
    END
  END a[509]
  PIN a[50]
    DIRECTION INPUT ;
    USE SIGNAL ;
    PORT
      LAYER M4 ;
        RECT  72.792 3.024 72.984 3.048 ;
    END
  END a[50]
  PIN a[510]
    DIRECTION INPUT ;
    USE SIGNAL ;
    PORT
      LAYER M4 ;
        RECT  72.792 25.104 72.984 25.128 ;
    END
  END a[510]
  PIN a[511]
    DIRECTION INPUT ;
    USE SIGNAL ;
    PORT
      LAYER M4 ;
        RECT  72.792 25.152 72.984 25.176 ;
    END
  END a[511]
  PIN a[512]
    DIRECTION INPUT ;
    USE SIGNAL ;
    PORT
      LAYER M4 ;
        RECT  72.792 25.2 72.984 25.224 ;
    END
  END a[512]
  PIN a[51]
    DIRECTION INPUT ;
    USE SIGNAL ;
    PORT
      LAYER M4 ;
        RECT  72.792 3.072 72.984 3.096 ;
    END
  END a[51]
  PIN a[52]
    DIRECTION INPUT ;
    USE SIGNAL ;
    PORT
      LAYER M4 ;
        RECT  72.792 3.12 72.984 3.144 ;
    END
  END a[52]
  PIN a[53]
    DIRECTION INPUT ;
    USE SIGNAL ;
    PORT
      LAYER M4 ;
        RECT  72.792 3.168 72.984 3.192 ;
    END
  END a[53]
  PIN a[54]
    DIRECTION INPUT ;
    USE SIGNAL ;
    PORT
      LAYER M4 ;
        RECT  72.792 3.216 72.984 3.24 ;
    END
  END a[54]
  PIN a[55]
    DIRECTION INPUT ;
    USE SIGNAL ;
    PORT
      LAYER M4 ;
        RECT  72.792 3.264 72.984 3.288 ;
    END
  END a[55]
  PIN a[56]
    DIRECTION INPUT ;
    USE SIGNAL ;
    PORT
      LAYER M4 ;
        RECT  72.792 3.312 72.984 3.336 ;
    END
  END a[56]
  PIN a[57]
    DIRECTION INPUT ;
    USE SIGNAL ;
    PORT
      LAYER M4 ;
        RECT  72.792 3.36 72.984 3.384 ;
    END
  END a[57]
  PIN a[58]
    DIRECTION INPUT ;
    USE SIGNAL ;
    PORT
      LAYER M4 ;
        RECT  72.792 3.408 72.984 3.432 ;
    END
  END a[58]
  PIN a[59]
    DIRECTION INPUT ;
    USE SIGNAL ;
    PORT
      LAYER M4 ;
        RECT  72.792 3.456 72.984 3.48 ;
    END
  END a[59]
  PIN a[5]
    DIRECTION INPUT ;
    USE SIGNAL ;
    PORT
      LAYER M4 ;
        RECT  72.792 0.864 72.984 0.888 ;
    END
  END a[5]
  PIN a[60]
    DIRECTION INPUT ;
    USE SIGNAL ;
    PORT
      LAYER M4 ;
        RECT  72.792 3.504 72.984 3.528 ;
    END
  END a[60]
  PIN a[61]
    DIRECTION INPUT ;
    USE SIGNAL ;
    PORT
      LAYER M4 ;
        RECT  72.792 3.552 72.984 3.576 ;
    END
  END a[61]
  PIN a[62]
    DIRECTION INPUT ;
    USE SIGNAL ;
    PORT
      LAYER M4 ;
        RECT  72.792 3.6 72.984 3.624 ;
    END
  END a[62]
  PIN a[63]
    DIRECTION INPUT ;
    USE SIGNAL ;
    PORT
      LAYER M4 ;
        RECT  72.792 3.648 72.984 3.672 ;
    END
  END a[63]
  PIN a[64]
    DIRECTION INPUT ;
    USE SIGNAL ;
    PORT
      LAYER M4 ;
        RECT  72.792 3.696 72.984 3.72 ;
    END
  END a[64]
  PIN a[65]
    DIRECTION INPUT ;
    USE SIGNAL ;
    PORT
      LAYER M4 ;
        RECT  72.792 3.744 72.984 3.768 ;
    END
  END a[65]
  PIN a[66]
    DIRECTION INPUT ;
    USE SIGNAL ;
    PORT
      LAYER M4 ;
        RECT  72.792 3.792 72.984 3.816 ;
    END
  END a[66]
  PIN a[67]
    DIRECTION INPUT ;
    USE SIGNAL ;
    PORT
      LAYER M4 ;
        RECT  72.792 3.84 72.984 3.864 ;
    END
  END a[67]
  PIN a[68]
    DIRECTION INPUT ;
    USE SIGNAL ;
    PORT
      LAYER M4 ;
        RECT  72.792 3.888 72.984 3.912 ;
    END
  END a[68]
  PIN a[69]
    DIRECTION INPUT ;
    USE SIGNAL ;
    PORT
      LAYER M4 ;
        RECT  72.792 3.936 72.984 3.96 ;
    END
  END a[69]
  PIN a[6]
    DIRECTION INPUT ;
    USE SIGNAL ;
    PORT
      LAYER M4 ;
        RECT  72.792 0.912 72.984 0.936 ;
    END
  END a[6]
  PIN a[70]
    DIRECTION INPUT ;
    USE SIGNAL ;
    PORT
      LAYER M4 ;
        RECT  72.792 3.984 72.984 4.008 ;
    END
  END a[70]
  PIN a[71]
    DIRECTION INPUT ;
    USE SIGNAL ;
    PORT
      LAYER M4 ;
        RECT  72.792 4.032 72.984 4.056 ;
    END
  END a[71]
  PIN a[72]
    DIRECTION INPUT ;
    USE SIGNAL ;
    PORT
      LAYER M4 ;
        RECT  72.792 4.08 72.984 4.104 ;
    END
  END a[72]
  PIN a[73]
    DIRECTION INPUT ;
    USE SIGNAL ;
    PORT
      LAYER M4 ;
        RECT  72.792 4.128 72.984 4.152 ;
    END
  END a[73]
  PIN a[74]
    DIRECTION INPUT ;
    USE SIGNAL ;
    PORT
      LAYER M4 ;
        RECT  72.792 4.176 72.984 4.2 ;
    END
  END a[74]
  PIN a[75]
    DIRECTION INPUT ;
    USE SIGNAL ;
    PORT
      LAYER M4 ;
        RECT  72.792 4.224 72.984 4.248 ;
    END
  END a[75]
  PIN a[76]
    DIRECTION INPUT ;
    USE SIGNAL ;
    PORT
      LAYER M4 ;
        RECT  72.792 4.272 72.984 4.296 ;
    END
  END a[76]
  PIN a[77]
    DIRECTION INPUT ;
    USE SIGNAL ;
    PORT
      LAYER M4 ;
        RECT  72.792 4.32 72.984 4.344 ;
    END
  END a[77]
  PIN a[78]
    DIRECTION INPUT ;
    USE SIGNAL ;
    PORT
      LAYER M4 ;
        RECT  72.792 4.368 72.984 4.392 ;
    END
  END a[78]
  PIN a[79]
    DIRECTION INPUT ;
    USE SIGNAL ;
    PORT
      LAYER M4 ;
        RECT  72.792 4.416 72.984 4.44 ;
    END
  END a[79]
  PIN a[7]
    DIRECTION INPUT ;
    USE SIGNAL ;
    PORT
      LAYER M4 ;
        RECT  72.792 0.96 72.984 0.984 ;
    END
  END a[7]
  PIN a[80]
    DIRECTION INPUT ;
    USE SIGNAL ;
    PORT
      LAYER M4 ;
        RECT  72.792 4.464 72.984 4.488 ;
    END
  END a[80]
  PIN a[81]
    DIRECTION INPUT ;
    USE SIGNAL ;
    PORT
      LAYER M4 ;
        RECT  72.792 4.512 72.984 4.536 ;
    END
  END a[81]
  PIN a[82]
    DIRECTION INPUT ;
    USE SIGNAL ;
    PORT
      LAYER M4 ;
        RECT  72.792 4.56 72.984 4.584 ;
    END
  END a[82]
  PIN a[83]
    DIRECTION INPUT ;
    USE SIGNAL ;
    PORT
      LAYER M4 ;
        RECT  72.792 4.608 72.984 4.632 ;
    END
  END a[83]
  PIN a[84]
    DIRECTION INPUT ;
    USE SIGNAL ;
    PORT
      LAYER M4 ;
        RECT  72.792 4.656 72.984 4.68 ;
    END
  END a[84]
  PIN a[85]
    DIRECTION INPUT ;
    USE SIGNAL ;
    PORT
      LAYER M4 ;
        RECT  72.792 4.704 72.984 4.728 ;
    END
  END a[85]
  PIN a[86]
    DIRECTION INPUT ;
    USE SIGNAL ;
    PORT
      LAYER M4 ;
        RECT  72.792 4.752 72.984 4.776 ;
    END
  END a[86]
  PIN a[87]
    DIRECTION INPUT ;
    USE SIGNAL ;
    PORT
      LAYER M4 ;
        RECT  72.792 4.8 72.984 4.824 ;
    END
  END a[87]
  PIN a[88]
    DIRECTION INPUT ;
    USE SIGNAL ;
    PORT
      LAYER M4 ;
        RECT  72.792 4.848 72.984 4.872 ;
    END
  END a[88]
  PIN a[89]
    DIRECTION INPUT ;
    USE SIGNAL ;
    PORT
      LAYER M4 ;
        RECT  72.792 4.896 72.984 4.92 ;
    END
  END a[89]
  PIN a[8]
    DIRECTION INPUT ;
    USE SIGNAL ;
    PORT
      LAYER M4 ;
        RECT  72.792 1.008 72.984 1.032 ;
    END
  END a[8]
  PIN a[90]
    DIRECTION INPUT ;
    USE SIGNAL ;
    PORT
      LAYER M4 ;
        RECT  72.792 4.944 72.984 4.968 ;
    END
  END a[90]
  PIN a[91]
    DIRECTION INPUT ;
    USE SIGNAL ;
    PORT
      LAYER M4 ;
        RECT  72.792 4.992 72.984 5.016 ;
    END
  END a[91]
  PIN a[92]
    DIRECTION INPUT ;
    USE SIGNAL ;
    PORT
      LAYER M4 ;
        RECT  72.792 5.04 72.984 5.064 ;
    END
  END a[92]
  PIN a[93]
    DIRECTION INPUT ;
    USE SIGNAL ;
    PORT
      LAYER M4 ;
        RECT  72.792 5.088 72.984 5.112 ;
    END
  END a[93]
  PIN a[94]
    DIRECTION INPUT ;
    USE SIGNAL ;
    PORT
      LAYER M4 ;
        RECT  72.792 5.136 72.984 5.16 ;
    END
  END a[94]
  PIN a[95]
    DIRECTION INPUT ;
    USE SIGNAL ;
    PORT
      LAYER M4 ;
        RECT  72.792 5.184 72.984 5.208 ;
    END
  END a[95]
  PIN a[96]
    DIRECTION INPUT ;
    USE SIGNAL ;
    PORT
      LAYER M4 ;
        RECT  72.792 5.232 72.984 5.256 ;
    END
  END a[96]
  PIN a[97]
    DIRECTION INPUT ;
    USE SIGNAL ;
    PORT
      LAYER M4 ;
        RECT  72.792 5.28 72.984 5.304 ;
    END
  END a[97]
  PIN a[98]
    DIRECTION INPUT ;
    USE SIGNAL ;
    PORT
      LAYER M4 ;
        RECT  72.792 5.328 72.984 5.352 ;
    END
  END a[98]
  PIN a[99]
    DIRECTION INPUT ;
    USE SIGNAL ;
    PORT
      LAYER M4 ;
        RECT  72.792 5.376 72.984 5.4 ;
    END
  END a[99]
  PIN a[9]
    DIRECTION INPUT ;
    USE SIGNAL ;
    PORT
      LAYER M4 ;
        RECT  72.792 1.056 72.984 1.08 ;
    END
  END a[9]
  PIN b[0]
    DIRECTION OUTPUT ;
    USE SIGNAL ;
    PORT
      LAYER M4 ;
        RECT  0 15.792 0.192 15.816 ;
    END
  END b[0]
  PIN b[100]
    DIRECTION OUTPUT ;
    USE SIGNAL ;
    PORT
      LAYER M4 ;
        RECT  0 20.592 0.192 20.616 ;
    END
  END b[100]
  PIN b[101]
    DIRECTION OUTPUT ;
    USE SIGNAL ;
    PORT
      LAYER M4 ;
        RECT  0 20.64 0.192 20.664 ;
    END
  END b[101]
  PIN b[102]
    DIRECTION OUTPUT ;
    USE SIGNAL ;
    PORT
      LAYER M4 ;
        RECT  0 20.688 0.192 20.712 ;
    END
  END b[102]
  PIN b[103]
    DIRECTION OUTPUT ;
    USE SIGNAL ;
    PORT
      LAYER M4 ;
        RECT  0 20.736 0.192 20.76 ;
    END
  END b[103]
  PIN b[104]
    DIRECTION OUTPUT ;
    USE SIGNAL ;
    PORT
      LAYER M4 ;
        RECT  0 20.784 0.192 20.808 ;
    END
  END b[104]
  PIN b[105]
    DIRECTION OUTPUT ;
    USE SIGNAL ;
    PORT
      LAYER M4 ;
        RECT  0 20.832 0.192 20.856 ;
    END
  END b[105]
  PIN b[106]
    DIRECTION OUTPUT ;
    USE SIGNAL ;
    PORT
      LAYER M4 ;
        RECT  0 20.88 0.192 20.904 ;
    END
  END b[106]
  PIN b[107]
    DIRECTION OUTPUT ;
    USE SIGNAL ;
    PORT
      LAYER M4 ;
        RECT  0 20.928 0.192 20.952 ;
    END
  END b[107]
  PIN b[108]
    DIRECTION OUTPUT ;
    USE SIGNAL ;
    PORT
      LAYER M4 ;
        RECT  0 20.976 0.192 21 ;
    END
  END b[108]
  PIN b[109]
    DIRECTION OUTPUT ;
    USE SIGNAL ;
    PORT
      LAYER M4 ;
        RECT  0 21.024 0.192 21.048 ;
    END
  END b[109]
  PIN b[10]
    DIRECTION OUTPUT ;
    USE SIGNAL ;
    PORT
      LAYER M4 ;
        RECT  0 16.272 0.192 16.296 ;
    END
  END b[10]
  PIN b[110]
    DIRECTION OUTPUT ;
    USE SIGNAL ;
    PORT
      LAYER M4 ;
        RECT  0 21.072 0.192 21.096 ;
    END
  END b[110]
  PIN b[111]
    DIRECTION OUTPUT ;
    USE SIGNAL ;
    PORT
      LAYER M4 ;
        RECT  0 21.12 0.192 21.144 ;
    END
  END b[111]
  PIN b[112]
    DIRECTION OUTPUT ;
    USE SIGNAL ;
    PORT
      LAYER M4 ;
        RECT  0 21.168 0.192 21.192 ;
    END
  END b[112]
  PIN b[113]
    DIRECTION OUTPUT ;
    USE SIGNAL ;
    PORT
      LAYER M4 ;
        RECT  0 21.216 0.192 21.24 ;
    END
  END b[113]
  PIN b[114]
    DIRECTION OUTPUT ;
    USE SIGNAL ;
    PORT
      LAYER M4 ;
        RECT  0 21.264 0.192 21.288 ;
    END
  END b[114]
  PIN b[115]
    DIRECTION OUTPUT ;
    USE SIGNAL ;
    PORT
      LAYER M4 ;
        RECT  0 21.312 0.192 21.336 ;
    END
  END b[115]
  PIN b[116]
    DIRECTION OUTPUT ;
    USE SIGNAL ;
    PORT
      LAYER M4 ;
        RECT  0 21.36 0.192 21.384 ;
    END
  END b[116]
  PIN b[117]
    DIRECTION OUTPUT ;
    USE SIGNAL ;
    PORT
      LAYER M4 ;
        RECT  0 21.408 0.192 21.432 ;
    END
  END b[117]
  PIN b[118]
    DIRECTION OUTPUT ;
    USE SIGNAL ;
    PORT
      LAYER M4 ;
        RECT  0 21.456 0.192 21.48 ;
    END
  END b[118]
  PIN b[119]
    DIRECTION OUTPUT ;
    USE SIGNAL ;
    PORT
      LAYER M4 ;
        RECT  0 21.504 0.192 21.528 ;
    END
  END b[119]
  PIN b[11]
    DIRECTION OUTPUT ;
    USE SIGNAL ;
    PORT
      LAYER M4 ;
        RECT  0 16.32 0.192 16.344 ;
    END
  END b[11]
  PIN b[120]
    DIRECTION OUTPUT ;
    USE SIGNAL ;
    PORT
      LAYER M4 ;
        RECT  0 21.552 0.192 21.576 ;
    END
  END b[120]
  PIN b[121]
    DIRECTION OUTPUT ;
    USE SIGNAL ;
    PORT
      LAYER M4 ;
        RECT  0 21.6 0.192 21.624 ;
    END
  END b[121]
  PIN b[122]
    DIRECTION OUTPUT ;
    USE SIGNAL ;
    PORT
      LAYER M4 ;
        RECT  0 21.648 0.192 21.672 ;
    END
  END b[122]
  PIN b[123]
    DIRECTION OUTPUT ;
    USE SIGNAL ;
    PORT
      LAYER M4 ;
        RECT  0 21.696 0.192 21.72 ;
    END
  END b[123]
  PIN b[124]
    DIRECTION OUTPUT ;
    USE SIGNAL ;
    PORT
      LAYER M4 ;
        RECT  0 21.744 0.192 21.768 ;
    END
  END b[124]
  PIN b[125]
    DIRECTION OUTPUT ;
    USE SIGNAL ;
    PORT
      LAYER M4 ;
        RECT  0 21.792 0.192 21.816 ;
    END
  END b[125]
  PIN b[126]
    DIRECTION OUTPUT ;
    USE SIGNAL ;
    PORT
      LAYER M4 ;
        RECT  0 21.84 0.192 21.864 ;
    END
  END b[126]
  PIN b[127]
    DIRECTION OUTPUT ;
    USE SIGNAL ;
    PORT
      LAYER M4 ;
        RECT  0 21.888 0.192 21.912 ;
    END
  END b[127]
  PIN b[128]
    DIRECTION OUTPUT ;
    USE SIGNAL ;
    PORT
      LAYER M4 ;
        RECT  0 21.936 0.192 21.96 ;
    END
  END b[128]
  PIN b[129]
    DIRECTION OUTPUT ;
    USE SIGNAL ;
    PORT
      LAYER M4 ;
        RECT  0 21.984 0.192 22.008 ;
    END
  END b[129]
  PIN b[12]
    DIRECTION OUTPUT ;
    USE SIGNAL ;
    PORT
      LAYER M4 ;
        RECT  0 16.368 0.192 16.392 ;
    END
  END b[12]
  PIN b[130]
    DIRECTION OUTPUT ;
    USE SIGNAL ;
    PORT
      LAYER M4 ;
        RECT  0 22.032 0.192 22.056 ;
    END
  END b[130]
  PIN b[131]
    DIRECTION OUTPUT ;
    USE SIGNAL ;
    PORT
      LAYER M4 ;
        RECT  0 22.08 0.192 22.104 ;
    END
  END b[131]
  PIN b[132]
    DIRECTION OUTPUT ;
    USE SIGNAL ;
    PORT
      LAYER M4 ;
        RECT  0 22.128 0.192 22.152 ;
    END
  END b[132]
  PIN b[133]
    DIRECTION OUTPUT ;
    USE SIGNAL ;
    PORT
      LAYER M4 ;
        RECT  0 22.176 0.192 22.2 ;
    END
  END b[133]
  PIN b[134]
    DIRECTION OUTPUT ;
    USE SIGNAL ;
    PORT
      LAYER M4 ;
        RECT  0 22.224 0.192 22.248 ;
    END
  END b[134]
  PIN b[135]
    DIRECTION OUTPUT ;
    USE SIGNAL ;
    PORT
      LAYER M4 ;
        RECT  0 22.272 0.192 22.296 ;
    END
  END b[135]
  PIN b[136]
    DIRECTION OUTPUT ;
    USE SIGNAL ;
    PORT
      LAYER M4 ;
        RECT  0 22.32 0.192 22.344 ;
    END
  END b[136]
  PIN b[137]
    DIRECTION OUTPUT ;
    USE SIGNAL ;
    PORT
      LAYER M4 ;
        RECT  0 22.368 0.192 22.392 ;
    END
  END b[137]
  PIN b[138]
    DIRECTION OUTPUT ;
    USE SIGNAL ;
    PORT
      LAYER M4 ;
        RECT  0 22.416 0.192 22.44 ;
    END
  END b[138]
  PIN b[139]
    DIRECTION OUTPUT ;
    USE SIGNAL ;
    PORT
      LAYER M4 ;
        RECT  0 22.464 0.192 22.488 ;
    END
  END b[139]
  PIN b[13]
    DIRECTION OUTPUT ;
    USE SIGNAL ;
    PORT
      LAYER M4 ;
        RECT  0 16.416 0.192 16.44 ;
    END
  END b[13]
  PIN b[140]
    DIRECTION OUTPUT ;
    USE SIGNAL ;
    PORT
      LAYER M4 ;
        RECT  0 22.512 0.192 22.536 ;
    END
  END b[140]
  PIN b[141]
    DIRECTION OUTPUT ;
    USE SIGNAL ;
    PORT
      LAYER M4 ;
        RECT  0 22.56 0.192 22.584 ;
    END
  END b[141]
  PIN b[142]
    DIRECTION OUTPUT ;
    USE SIGNAL ;
    PORT
      LAYER M4 ;
        RECT  0 22.608 0.192 22.632 ;
    END
  END b[142]
  PIN b[143]
    DIRECTION OUTPUT ;
    USE SIGNAL ;
    PORT
      LAYER M4 ;
        RECT  0 22.656 0.192 22.68 ;
    END
  END b[143]
  PIN b[144]
    DIRECTION OUTPUT ;
    USE SIGNAL ;
    PORT
      LAYER M4 ;
        RECT  0 22.704 0.192 22.728 ;
    END
  END b[144]
  PIN b[145]
    DIRECTION OUTPUT ;
    USE SIGNAL ;
    PORT
      LAYER M4 ;
        RECT  0 22.752 0.192 22.776 ;
    END
  END b[145]
  PIN b[146]
    DIRECTION OUTPUT ;
    USE SIGNAL ;
    PORT
      LAYER M4 ;
        RECT  0 22.8 0.192 22.824 ;
    END
  END b[146]
  PIN b[147]
    DIRECTION OUTPUT ;
    USE SIGNAL ;
    PORT
      LAYER M4 ;
        RECT  0 22.848 0.192 22.872 ;
    END
  END b[147]
  PIN b[148]
    DIRECTION OUTPUT ;
    USE SIGNAL ;
    PORT
      LAYER M4 ;
        RECT  0 22.896 0.192 22.92 ;
    END
  END b[148]
  PIN b[149]
    DIRECTION OUTPUT ;
    USE SIGNAL ;
    PORT
      LAYER M4 ;
        RECT  0 22.944 0.192 22.968 ;
    END
  END b[149]
  PIN b[14]
    DIRECTION OUTPUT ;
    USE SIGNAL ;
    PORT
      LAYER M4 ;
        RECT  0 16.464 0.192 16.488 ;
    END
  END b[14]
  PIN b[150]
    DIRECTION OUTPUT ;
    USE SIGNAL ;
    PORT
      LAYER M4 ;
        RECT  0 22.992 0.192 23.016 ;
    END
  END b[150]
  PIN b[151]
    DIRECTION OUTPUT ;
    USE SIGNAL ;
    PORT
      LAYER M4 ;
        RECT  0 23.04 0.192 23.064 ;
    END
  END b[151]
  PIN b[152]
    DIRECTION OUTPUT ;
    USE SIGNAL ;
    PORT
      LAYER M4 ;
        RECT  0 23.088 0.192 23.112 ;
    END
  END b[152]
  PIN b[153]
    DIRECTION OUTPUT ;
    USE SIGNAL ;
    PORT
      LAYER M4 ;
        RECT  0 23.136 0.192 23.16 ;
    END
  END b[153]
  PIN b[154]
    DIRECTION OUTPUT ;
    USE SIGNAL ;
    PORT
      LAYER M4 ;
        RECT  0 23.184 0.192 23.208 ;
    END
  END b[154]
  PIN b[155]
    DIRECTION OUTPUT ;
    USE SIGNAL ;
    PORT
      LAYER M4 ;
        RECT  0 23.232 0.192 23.256 ;
    END
  END b[155]
  PIN b[156]
    DIRECTION OUTPUT ;
    USE SIGNAL ;
    PORT
      LAYER M4 ;
        RECT  0 23.28 0.192 23.304 ;
    END
  END b[156]
  PIN b[157]
    DIRECTION OUTPUT ;
    USE SIGNAL ;
    PORT
      LAYER M4 ;
        RECT  0 23.328 0.192 23.352 ;
    END
  END b[157]
  PIN b[158]
    DIRECTION OUTPUT ;
    USE SIGNAL ;
    PORT
      LAYER M4 ;
        RECT  0 23.376 0.192 23.4 ;
    END
  END b[158]
  PIN b[159]
    DIRECTION OUTPUT ;
    USE SIGNAL ;
    PORT
      LAYER M4 ;
        RECT  0 23.424 0.192 23.448 ;
    END
  END b[159]
  PIN b[15]
    DIRECTION OUTPUT ;
    USE SIGNAL ;
    PORT
      LAYER M4 ;
        RECT  0 16.512 0.192 16.536 ;
    END
  END b[15]
  PIN b[160]
    DIRECTION OUTPUT ;
    USE SIGNAL ;
    PORT
      LAYER M4 ;
        RECT  0 23.472 0.192 23.496 ;
    END
  END b[160]
  PIN b[161]
    DIRECTION OUTPUT ;
    USE SIGNAL ;
    PORT
      LAYER M4 ;
        RECT  0 23.52 0.192 23.544 ;
    END
  END b[161]
  PIN b[162]
    DIRECTION OUTPUT ;
    USE SIGNAL ;
    PORT
      LAYER M4 ;
        RECT  0 23.568 0.192 23.592 ;
    END
  END b[162]
  PIN b[163]
    DIRECTION OUTPUT ;
    USE SIGNAL ;
    PORT
      LAYER M4 ;
        RECT  0 23.616 0.192 23.64 ;
    END
  END b[163]
  PIN b[164]
    DIRECTION OUTPUT ;
    USE SIGNAL ;
    PORT
      LAYER M4 ;
        RECT  0 23.664 0.192 23.688 ;
    END
  END b[164]
  PIN b[165]
    DIRECTION OUTPUT ;
    USE SIGNAL ;
    PORT
      LAYER M4 ;
        RECT  0 23.712 0.192 23.736 ;
    END
  END b[165]
  PIN b[166]
    DIRECTION OUTPUT ;
    USE SIGNAL ;
    PORT
      LAYER M4 ;
        RECT  0 23.76 0.192 23.784 ;
    END
  END b[166]
  PIN b[167]
    DIRECTION OUTPUT ;
    USE SIGNAL ;
    PORT
      LAYER M4 ;
        RECT  0 23.808 0.192 23.832 ;
    END
  END b[167]
  PIN b[168]
    DIRECTION OUTPUT ;
    USE SIGNAL ;
    PORT
      LAYER M4 ;
        RECT  0 23.856 0.192 23.88 ;
    END
  END b[168]
  PIN b[169]
    DIRECTION OUTPUT ;
    USE SIGNAL ;
    PORT
      LAYER M4 ;
        RECT  0 23.904 0.192 23.928 ;
    END
  END b[169]
  PIN b[16]
    DIRECTION OUTPUT ;
    USE SIGNAL ;
    PORT
      LAYER M4 ;
        RECT  0 16.56 0.192 16.584 ;
    END
  END b[16]
  PIN b[170]
    DIRECTION OUTPUT ;
    USE SIGNAL ;
    PORT
      LAYER M4 ;
        RECT  0 23.952 0.192 23.976 ;
    END
  END b[170]
  PIN b[171]
    DIRECTION OUTPUT ;
    USE SIGNAL ;
    PORT
      LAYER M4 ;
        RECT  0 24 0.192 24.024 ;
    END
  END b[171]
  PIN b[172]
    DIRECTION OUTPUT ;
    USE SIGNAL ;
    PORT
      LAYER M4 ;
        RECT  0 24.048 0.192 24.072 ;
    END
  END b[172]
  PIN b[173]
    DIRECTION OUTPUT ;
    USE SIGNAL ;
    PORT
      LAYER M4 ;
        RECT  0 24.096 0.192 24.12 ;
    END
  END b[173]
  PIN b[174]
    DIRECTION OUTPUT ;
    USE SIGNAL ;
    PORT
      LAYER M4 ;
        RECT  0 24.144 0.192 24.168 ;
    END
  END b[174]
  PIN b[175]
    DIRECTION OUTPUT ;
    USE SIGNAL ;
    PORT
      LAYER M4 ;
        RECT  0 24.192 0.192 24.216 ;
    END
  END b[175]
  PIN b[176]
    DIRECTION OUTPUT ;
    USE SIGNAL ;
    PORT
      LAYER M4 ;
        RECT  0 24.24 0.192 24.264 ;
    END
  END b[176]
  PIN b[177]
    DIRECTION OUTPUT ;
    USE SIGNAL ;
    PORT
      LAYER M4 ;
        RECT  0 24.288 0.192 24.312 ;
    END
  END b[177]
  PIN b[178]
    DIRECTION OUTPUT ;
    USE SIGNAL ;
    PORT
      LAYER M4 ;
        RECT  0 24.336 0.192 24.36 ;
    END
  END b[178]
  PIN b[179]
    DIRECTION OUTPUT ;
    USE SIGNAL ;
    PORT
      LAYER M4 ;
        RECT  0 24.384 0.192 24.408 ;
    END
  END b[179]
  PIN b[17]
    DIRECTION OUTPUT ;
    USE SIGNAL ;
    PORT
      LAYER M4 ;
        RECT  0 16.608 0.192 16.632 ;
    END
  END b[17]
  PIN b[180]
    DIRECTION OUTPUT ;
    USE SIGNAL ;
    PORT
      LAYER M4 ;
        RECT  0 24.432 0.192 24.456 ;
    END
  END b[180]
  PIN b[181]
    DIRECTION OUTPUT ;
    USE SIGNAL ;
    PORT
      LAYER M4 ;
        RECT  0 24.48 0.192 24.504 ;
    END
  END b[181]
  PIN b[182]
    DIRECTION OUTPUT ;
    USE SIGNAL ;
    PORT
      LAYER M4 ;
        RECT  0 24.528 0.192 24.552 ;
    END
  END b[182]
  PIN b[183]
    DIRECTION OUTPUT ;
    USE SIGNAL ;
    PORT
      LAYER M4 ;
        RECT  0 24.576 0.192 24.6 ;
    END
  END b[183]
  PIN b[184]
    DIRECTION OUTPUT ;
    USE SIGNAL ;
    PORT
      LAYER M4 ;
        RECT  0 24.624 0.192 24.648 ;
    END
  END b[184]
  PIN b[185]
    DIRECTION OUTPUT ;
    USE SIGNAL ;
    PORT
      LAYER M4 ;
        RECT  0 24.672 0.192 24.696 ;
    END
  END b[185]
  PIN b[186]
    DIRECTION OUTPUT ;
    USE SIGNAL ;
    PORT
      LAYER M4 ;
        RECT  0 24.72 0.192 24.744 ;
    END
  END b[186]
  PIN b[187]
    DIRECTION OUTPUT ;
    USE SIGNAL ;
    PORT
      LAYER M4 ;
        RECT  0 24.768 0.192 24.792 ;
    END
  END b[187]
  PIN b[188]
    DIRECTION OUTPUT ;
    USE SIGNAL ;
    PORT
      LAYER M4 ;
        RECT  0 24.816 0.192 24.84 ;
    END
  END b[188]
  PIN b[189]
    DIRECTION OUTPUT ;
    USE SIGNAL ;
    PORT
      LAYER M4 ;
        RECT  0 24.864 0.192 24.888 ;
    END
  END b[189]
  PIN b[18]
    DIRECTION OUTPUT ;
    USE SIGNAL ;
    PORT
      LAYER M4 ;
        RECT  0 16.656 0.192 16.68 ;
    END
  END b[18]
  PIN b[190]
    DIRECTION OUTPUT ;
    USE SIGNAL ;
    PORT
      LAYER M4 ;
        RECT  0 24.912 0.192 24.936 ;
    END
  END b[190]
  PIN b[191]
    DIRECTION OUTPUT ;
    USE SIGNAL ;
    PORT
      LAYER M4 ;
        RECT  0 24.96 0.192 24.984 ;
    END
  END b[191]
  PIN b[192]
    DIRECTION OUTPUT ;
    USE SIGNAL ;
    PORT
      LAYER M4 ;
        RECT  0 25.008 0.192 25.032 ;
    END
  END b[192]
  PIN b[193]
    DIRECTION OUTPUT ;
    USE SIGNAL ;
    PORT
      LAYER M4 ;
        RECT  0 25.056 0.192 25.08 ;
    END
  END b[193]
  PIN b[194]
    DIRECTION OUTPUT ;
    USE SIGNAL ;
    PORT
      LAYER M4 ;
        RECT  0 25.104 0.192 25.128 ;
    END
  END b[194]
  PIN b[195]
    DIRECTION OUTPUT ;
    USE SIGNAL ;
    PORT
      LAYER M4 ;
        RECT  0 25.152 0.192 25.176 ;
    END
  END b[195]
  PIN b[196]
    DIRECTION OUTPUT ;
    USE SIGNAL ;
    PORT
      LAYER M4 ;
        RECT  0 25.2 0.192 25.224 ;
    END
  END b[196]
  PIN b[197]
    DIRECTION OUTPUT ;
    USE SIGNAL ;
    PORT
      LAYER M4 ;
        RECT  0 25.248 0.192 25.272 ;
    END
  END b[197]
  PIN b[198]
    DIRECTION OUTPUT ;
    USE SIGNAL ;
    PORT
      LAYER M4 ;
        RECT  0 25.296 0.192 25.32 ;
    END
  END b[198]
  PIN b[199]
    DIRECTION OUTPUT ;
    USE SIGNAL ;
    PORT
      LAYER M4 ;
        RECT  0 25.344 0.192 25.368 ;
    END
  END b[199]
  PIN b[19]
    DIRECTION OUTPUT ;
    USE SIGNAL ;
    PORT
      LAYER M4 ;
        RECT  0 16.704 0.192 16.728 ;
    END
  END b[19]
  PIN b[1]
    DIRECTION OUTPUT ;
    USE SIGNAL ;
    PORT
      LAYER M4 ;
        RECT  0 15.84 0.192 15.864 ;
    END
  END b[1]
  PIN b[200]
    DIRECTION OUTPUT ;
    USE SIGNAL ;
    PORT
      LAYER M4 ;
        RECT  0 25.392 0.192 25.416 ;
    END
  END b[200]
  PIN b[201]
    DIRECTION OUTPUT ;
    USE SIGNAL ;
    PORT
      LAYER M4 ;
        RECT  0 25.44 0.192 25.464 ;
    END
  END b[201]
  PIN b[202]
    DIRECTION OUTPUT ;
    USE SIGNAL ;
    PORT
      LAYER M4 ;
        RECT  0 25.488 0.192 25.512 ;
    END
  END b[202]
  PIN b[203]
    DIRECTION OUTPUT ;
    USE SIGNAL ;
    PORT
      LAYER M4 ;
        RECT  0 25.536 0.192 25.56 ;
    END
  END b[203]
  PIN b[204]
    DIRECTION OUTPUT ;
    USE SIGNAL ;
    PORT
      LAYER M4 ;
        RECT  0 25.584 0.192 25.608 ;
    END
  END b[204]
  PIN b[205]
    DIRECTION OUTPUT ;
    USE SIGNAL ;
    PORT
      LAYER M4 ;
        RECT  0 25.632 0.192 25.656 ;
    END
  END b[205]
  PIN b[206]
    DIRECTION OUTPUT ;
    USE SIGNAL ;
    PORT
      LAYER M4 ;
        RECT  0 25.68 0.192 25.704 ;
    END
  END b[206]
  PIN b[207]
    DIRECTION OUTPUT ;
    USE SIGNAL ;
    PORT
      LAYER M4 ;
        RECT  0 25.728 0.192 25.752 ;
    END
  END b[207]
  PIN b[208]
    DIRECTION OUTPUT ;
    USE SIGNAL ;
    PORT
      LAYER M4 ;
        RECT  0 25.776 0.192 25.8 ;
    END
  END b[208]
  PIN b[209]
    DIRECTION OUTPUT ;
    USE SIGNAL ;
    PORT
      LAYER M4 ;
        RECT  0 25.824 0.192 25.848 ;
    END
  END b[209]
  PIN b[20]
    DIRECTION OUTPUT ;
    USE SIGNAL ;
    PORT
      LAYER M4 ;
        RECT  0 16.752 0.192 16.776 ;
    END
  END b[20]
  PIN b[210]
    DIRECTION OUTPUT ;
    USE SIGNAL ;
    PORT
      LAYER M4 ;
        RECT  0 25.872 0.192 25.896 ;
    END
  END b[210]
  PIN b[211]
    DIRECTION OUTPUT ;
    USE SIGNAL ;
    PORT
      LAYER M4 ;
        RECT  0 25.92 0.192 25.944 ;
    END
  END b[211]
  PIN b[212]
    DIRECTION OUTPUT ;
    USE SIGNAL ;
    PORT
      LAYER M4 ;
        RECT  0 25.968 0.192 25.992 ;
    END
  END b[212]
  PIN b[213]
    DIRECTION OUTPUT ;
    USE SIGNAL ;
    PORT
      LAYER M4 ;
        RECT  0 26.016 0.192 26.04 ;
    END
  END b[213]
  PIN b[214]
    DIRECTION OUTPUT ;
    USE SIGNAL ;
    PORT
      LAYER M4 ;
        RECT  0 26.064 0.192 26.088 ;
    END
  END b[214]
  PIN b[215]
    DIRECTION OUTPUT ;
    USE SIGNAL ;
    PORT
      LAYER M4 ;
        RECT  0 26.112 0.192 26.136 ;
    END
  END b[215]
  PIN b[216]
    DIRECTION OUTPUT ;
    USE SIGNAL ;
    PORT
      LAYER M4 ;
        RECT  0 26.16 0.192 26.184 ;
    END
  END b[216]
  PIN b[217]
    DIRECTION OUTPUT ;
    USE SIGNAL ;
    PORT
      LAYER M4 ;
        RECT  0 26.208 0.192 26.232 ;
    END
  END b[217]
  PIN b[218]
    DIRECTION OUTPUT ;
    USE SIGNAL ;
    PORT
      LAYER M4 ;
        RECT  0 26.256 0.192 26.28 ;
    END
  END b[218]
  PIN b[219]
    DIRECTION OUTPUT ;
    USE SIGNAL ;
    PORT
      LAYER M4 ;
        RECT  0 26.304 0.192 26.328 ;
    END
  END b[219]
  PIN b[21]
    DIRECTION OUTPUT ;
    USE SIGNAL ;
    PORT
      LAYER M4 ;
        RECT  0 16.8 0.192 16.824 ;
    END
  END b[21]
  PIN b[220]
    DIRECTION OUTPUT ;
    USE SIGNAL ;
    PORT
      LAYER M4 ;
        RECT  0 26.352 0.192 26.376 ;
    END
  END b[220]
  PIN b[221]
    DIRECTION OUTPUT ;
    USE SIGNAL ;
    PORT
      LAYER M4 ;
        RECT  0 26.4 0.192 26.424 ;
    END
  END b[221]
  PIN b[222]
    DIRECTION OUTPUT ;
    USE SIGNAL ;
    PORT
      LAYER M4 ;
        RECT  0 26.448 0.192 26.472 ;
    END
  END b[222]
  PIN b[223]
    DIRECTION OUTPUT ;
    USE SIGNAL ;
    PORT
      LAYER M4 ;
        RECT  0 26.496 0.192 26.52 ;
    END
  END b[223]
  PIN b[224]
    DIRECTION OUTPUT ;
    USE SIGNAL ;
    PORT
      LAYER M4 ;
        RECT  0 26.544 0.192 26.568 ;
    END
  END b[224]
  PIN b[225]
    DIRECTION OUTPUT ;
    USE SIGNAL ;
    PORT
      LAYER M4 ;
        RECT  0 26.592 0.192 26.616 ;
    END
  END b[225]
  PIN b[226]
    DIRECTION OUTPUT ;
    USE SIGNAL ;
    PORT
      LAYER M4 ;
        RECT  0 26.64 0.192 26.664 ;
    END
  END b[226]
  PIN b[227]
    DIRECTION OUTPUT ;
    USE SIGNAL ;
    PORT
      LAYER M4 ;
        RECT  0 26.688 0.192 26.712 ;
    END
  END b[227]
  PIN b[228]
    DIRECTION OUTPUT ;
    USE SIGNAL ;
    PORT
      LAYER M4 ;
        RECT  0 26.736 0.192 26.76 ;
    END
  END b[228]
  PIN b[229]
    DIRECTION OUTPUT ;
    USE SIGNAL ;
    PORT
      LAYER M4 ;
        RECT  0 26.784 0.192 26.808 ;
    END
  END b[229]
  PIN b[22]
    DIRECTION OUTPUT ;
    USE SIGNAL ;
    PORT
      LAYER M4 ;
        RECT  0 16.848 0.192 16.872 ;
    END
  END b[22]
  PIN b[230]
    DIRECTION OUTPUT ;
    USE SIGNAL ;
    PORT
      LAYER M4 ;
        RECT  0 26.832 0.192 26.856 ;
    END
  END b[230]
  PIN b[231]
    DIRECTION OUTPUT ;
    USE SIGNAL ;
    PORT
      LAYER M4 ;
        RECT  0 26.88 0.192 26.904 ;
    END
  END b[231]
  PIN b[232]
    DIRECTION OUTPUT ;
    USE SIGNAL ;
    PORT
      LAYER M4 ;
        RECT  0 26.928 0.192 26.952 ;
    END
  END b[232]
  PIN b[233]
    DIRECTION OUTPUT ;
    USE SIGNAL ;
    PORT
      LAYER M4 ;
        RECT  0 26.976 0.192 27 ;
    END
  END b[233]
  PIN b[234]
    DIRECTION OUTPUT ;
    USE SIGNAL ;
    PORT
      LAYER M4 ;
        RECT  0 27.024 0.192 27.048 ;
    END
  END b[234]
  PIN b[235]
    DIRECTION OUTPUT ;
    USE SIGNAL ;
    PORT
      LAYER M4 ;
        RECT  0 27.072 0.192 27.096 ;
    END
  END b[235]
  PIN b[236]
    DIRECTION OUTPUT ;
    USE SIGNAL ;
    PORT
      LAYER M4 ;
        RECT  0 27.12 0.192 27.144 ;
    END
  END b[236]
  PIN b[237]
    DIRECTION OUTPUT ;
    USE SIGNAL ;
    PORT
      LAYER M4 ;
        RECT  0 27.168 0.192 27.192 ;
    END
  END b[237]
  PIN b[238]
    DIRECTION OUTPUT ;
    USE SIGNAL ;
    PORT
      LAYER M4 ;
        RECT  0 27.216 0.192 27.24 ;
    END
  END b[238]
  PIN b[239]
    DIRECTION OUTPUT ;
    USE SIGNAL ;
    PORT
      LAYER M4 ;
        RECT  0 27.264 0.192 27.288 ;
    END
  END b[239]
  PIN b[23]
    DIRECTION OUTPUT ;
    USE SIGNAL ;
    PORT
      LAYER M4 ;
        RECT  0 16.896 0.192 16.92 ;
    END
  END b[23]
  PIN b[240]
    DIRECTION OUTPUT ;
    USE SIGNAL ;
    PORT
      LAYER M4 ;
        RECT  0 27.312 0.192 27.336 ;
    END
  END b[240]
  PIN b[241]
    DIRECTION OUTPUT ;
    USE SIGNAL ;
    PORT
      LAYER M4 ;
        RECT  0 27.36 0.192 27.384 ;
    END
  END b[241]
  PIN b[242]
    DIRECTION OUTPUT ;
    USE SIGNAL ;
    PORT
      LAYER M4 ;
        RECT  0 27.408 0.192 27.432 ;
    END
  END b[242]
  PIN b[243]
    DIRECTION OUTPUT ;
    USE SIGNAL ;
    PORT
      LAYER M4 ;
        RECT  0 27.456 0.192 27.48 ;
    END
  END b[243]
  PIN b[244]
    DIRECTION OUTPUT ;
    USE SIGNAL ;
    PORT
      LAYER M4 ;
        RECT  0 27.504 0.192 27.528 ;
    END
  END b[244]
  PIN b[245]
    DIRECTION OUTPUT ;
    USE SIGNAL ;
    PORT
      LAYER M4 ;
        RECT  0 27.552 0.192 27.576 ;
    END
  END b[245]
  PIN b[246]
    DIRECTION OUTPUT ;
    USE SIGNAL ;
    PORT
      LAYER M4 ;
        RECT  0 27.6 0.192 27.624 ;
    END
  END b[246]
  PIN b[247]
    DIRECTION OUTPUT ;
    USE SIGNAL ;
    PORT
      LAYER M4 ;
        RECT  0 27.648 0.192 27.672 ;
    END
  END b[247]
  PIN b[248]
    DIRECTION OUTPUT ;
    USE SIGNAL ;
    PORT
      LAYER M4 ;
        RECT  0 27.696 0.192 27.72 ;
    END
  END b[248]
  PIN b[249]
    DIRECTION OUTPUT ;
    USE SIGNAL ;
    PORT
      LAYER M4 ;
        RECT  0 27.744 0.192 27.768 ;
    END
  END b[249]
  PIN b[24]
    DIRECTION OUTPUT ;
    USE SIGNAL ;
    PORT
      LAYER M4 ;
        RECT  0 16.944 0.192 16.968 ;
    END
  END b[24]
  PIN b[250]
    DIRECTION OUTPUT ;
    USE SIGNAL ;
    PORT
      LAYER M4 ;
        RECT  0 27.792 0.192 27.816 ;
    END
  END b[250]
  PIN b[251]
    DIRECTION OUTPUT ;
    USE SIGNAL ;
    PORT
      LAYER M4 ;
        RECT  0 27.84 0.192 27.864 ;
    END
  END b[251]
  PIN b[252]
    DIRECTION OUTPUT ;
    USE SIGNAL ;
    PORT
      LAYER M4 ;
        RECT  0 27.888 0.192 27.912 ;
    END
  END b[252]
  PIN b[253]
    DIRECTION OUTPUT ;
    USE SIGNAL ;
    PORT
      LAYER M4 ;
        RECT  0 27.936 0.192 27.96 ;
    END
  END b[253]
  PIN b[254]
    DIRECTION OUTPUT ;
    USE SIGNAL ;
    PORT
      LAYER M4 ;
        RECT  0 27.984 0.192 28.008 ;
    END
  END b[254]
  PIN b[255]
    DIRECTION OUTPUT ;
    USE SIGNAL ;
    PORT
      LAYER M4 ;
        RECT  0 28.032 0.192 28.056 ;
    END
  END b[255]
  PIN b[256]
    DIRECTION OUTPUT ;
    USE SIGNAL ;
    PORT
      LAYER M4 ;
        RECT  0 28.08 0.192 28.104 ;
    END
  END b[256]
  PIN b[257]
    DIRECTION OUTPUT ;
    USE SIGNAL ;
    PORT
      LAYER M4 ;
        RECT  0 28.128 0.192 28.152 ;
    END
  END b[257]
  PIN b[258]
    DIRECTION OUTPUT ;
    USE SIGNAL ;
    PORT
      LAYER M4 ;
        RECT  0 28.176 0.192 28.2 ;
    END
  END b[258]
  PIN b[259]
    DIRECTION OUTPUT ;
    USE SIGNAL ;
    PORT
      LAYER M4 ;
        RECT  0 28.224 0.192 28.248 ;
    END
  END b[259]
  PIN b[25]
    DIRECTION OUTPUT ;
    USE SIGNAL ;
    PORT
      LAYER M4 ;
        RECT  0 16.992 0.192 17.016 ;
    END
  END b[25]
  PIN b[260]
    DIRECTION OUTPUT ;
    USE SIGNAL ;
    PORT
      LAYER M4 ;
        RECT  0 28.272 0.192 28.296 ;
    END
  END b[260]
  PIN b[261]
    DIRECTION OUTPUT ;
    USE SIGNAL ;
    PORT
      LAYER M4 ;
        RECT  0 28.32 0.192 28.344 ;
    END
  END b[261]
  PIN b[262]
    DIRECTION OUTPUT ;
    USE SIGNAL ;
    PORT
      LAYER M4 ;
        RECT  0 28.368 0.192 28.392 ;
    END
  END b[262]
  PIN b[263]
    DIRECTION OUTPUT ;
    USE SIGNAL ;
    PORT
      LAYER M4 ;
        RECT  0 28.416 0.192 28.44 ;
    END
  END b[263]
  PIN b[264]
    DIRECTION OUTPUT ;
    USE SIGNAL ;
    PORT
      LAYER M4 ;
        RECT  0 28.464 0.192 28.488 ;
    END
  END b[264]
  PIN b[265]
    DIRECTION OUTPUT ;
    USE SIGNAL ;
    PORT
      LAYER M4 ;
        RECT  0 28.512 0.192 28.536 ;
    END
  END b[265]
  PIN b[266]
    DIRECTION OUTPUT ;
    USE SIGNAL ;
    PORT
      LAYER M4 ;
        RECT  0 28.56 0.192 28.584 ;
    END
  END b[266]
  PIN b[267]
    DIRECTION OUTPUT ;
    USE SIGNAL ;
    PORT
      LAYER M4 ;
        RECT  0 28.608 0.192 28.632 ;
    END
  END b[267]
  PIN b[268]
    DIRECTION OUTPUT ;
    USE SIGNAL ;
    PORT
      LAYER M4 ;
        RECT  0 28.656 0.192 28.68 ;
    END
  END b[268]
  PIN b[269]
    DIRECTION OUTPUT ;
    USE SIGNAL ;
    PORT
      LAYER M4 ;
        RECT  0 28.704 0.192 28.728 ;
    END
  END b[269]
  PIN b[26]
    DIRECTION OUTPUT ;
    USE SIGNAL ;
    PORT
      LAYER M4 ;
        RECT  0 17.04 0.192 17.064 ;
    END
  END b[26]
  PIN b[270]
    DIRECTION OUTPUT ;
    USE SIGNAL ;
    PORT
      LAYER M4 ;
        RECT  0 28.752 0.192 28.776 ;
    END
  END b[270]
  PIN b[271]
    DIRECTION OUTPUT ;
    USE SIGNAL ;
    PORT
      LAYER M4 ;
        RECT  0 28.8 0.192 28.824 ;
    END
  END b[271]
  PIN b[272]
    DIRECTION OUTPUT ;
    USE SIGNAL ;
    PORT
      LAYER M4 ;
        RECT  0 28.848 0.192 28.872 ;
    END
  END b[272]
  PIN b[273]
    DIRECTION OUTPUT ;
    USE SIGNAL ;
    PORT
      LAYER M4 ;
        RECT  0 28.896 0.192 28.92 ;
    END
  END b[273]
  PIN b[274]
    DIRECTION OUTPUT ;
    USE SIGNAL ;
    PORT
      LAYER M4 ;
        RECT  0 28.944 0.192 28.968 ;
    END
  END b[274]
  PIN b[275]
    DIRECTION OUTPUT ;
    USE SIGNAL ;
    PORT
      LAYER M4 ;
        RECT  0 28.992 0.192 29.016 ;
    END
  END b[275]
  PIN b[276]
    DIRECTION OUTPUT ;
    USE SIGNAL ;
    PORT
      LAYER M4 ;
        RECT  0 29.04 0.192 29.064 ;
    END
  END b[276]
  PIN b[277]
    DIRECTION OUTPUT ;
    USE SIGNAL ;
    PORT
      LAYER M4 ;
        RECT  0 29.088 0.192 29.112 ;
    END
  END b[277]
  PIN b[278]
    DIRECTION OUTPUT ;
    USE SIGNAL ;
    PORT
      LAYER M4 ;
        RECT  0 29.136 0.192 29.16 ;
    END
  END b[278]
  PIN b[279]
    DIRECTION OUTPUT ;
    USE SIGNAL ;
    PORT
      LAYER M4 ;
        RECT  0 29.184 0.192 29.208 ;
    END
  END b[279]
  PIN b[27]
    DIRECTION OUTPUT ;
    USE SIGNAL ;
    PORT
      LAYER M4 ;
        RECT  0 17.088 0.192 17.112 ;
    END
  END b[27]
  PIN b[280]
    DIRECTION OUTPUT ;
    USE SIGNAL ;
    PORT
      LAYER M4 ;
        RECT  0 29.232 0.192 29.256 ;
    END
  END b[280]
  PIN b[281]
    DIRECTION OUTPUT ;
    USE SIGNAL ;
    PORT
      LAYER M4 ;
        RECT  0 29.28 0.192 29.304 ;
    END
  END b[281]
  PIN b[282]
    DIRECTION OUTPUT ;
    USE SIGNAL ;
    PORT
      LAYER M4 ;
        RECT  0 29.328 0.192 29.352 ;
    END
  END b[282]
  PIN b[283]
    DIRECTION OUTPUT ;
    USE SIGNAL ;
    PORT
      LAYER M4 ;
        RECT  0 29.376 0.192 29.4 ;
    END
  END b[283]
  PIN b[284]
    DIRECTION OUTPUT ;
    USE SIGNAL ;
    PORT
      LAYER M4 ;
        RECT  0 29.424 0.192 29.448 ;
    END
  END b[284]
  PIN b[285]
    DIRECTION OUTPUT ;
    USE SIGNAL ;
    PORT
      LAYER M4 ;
        RECT  0 29.472 0.192 29.496 ;
    END
  END b[285]
  PIN b[286]
    DIRECTION OUTPUT ;
    USE SIGNAL ;
    PORT
      LAYER M4 ;
        RECT  0 29.52 0.192 29.544 ;
    END
  END b[286]
  PIN b[287]
    DIRECTION OUTPUT ;
    USE SIGNAL ;
    PORT
      LAYER M4 ;
        RECT  0 29.568 0.192 29.592 ;
    END
  END b[287]
  PIN b[288]
    DIRECTION OUTPUT ;
    USE SIGNAL ;
    PORT
      LAYER M4 ;
        RECT  0 29.616 0.192 29.64 ;
    END
  END b[288]
  PIN b[289]
    DIRECTION OUTPUT ;
    USE SIGNAL ;
    PORT
      LAYER M4 ;
        RECT  0 29.664 0.192 29.688 ;
    END
  END b[289]
  PIN b[28]
    DIRECTION OUTPUT ;
    USE SIGNAL ;
    PORT
      LAYER M4 ;
        RECT  0 17.136 0.192 17.16 ;
    END
  END b[28]
  PIN b[290]
    DIRECTION OUTPUT ;
    USE SIGNAL ;
    PORT
      LAYER M4 ;
        RECT  0 29.712 0.192 29.736 ;
    END
  END b[290]
  PIN b[291]
    DIRECTION OUTPUT ;
    USE SIGNAL ;
    PORT
      LAYER M4 ;
        RECT  0 29.76 0.192 29.784 ;
    END
  END b[291]
  PIN b[292]
    DIRECTION OUTPUT ;
    USE SIGNAL ;
    PORT
      LAYER M4 ;
        RECT  0 29.808 0.192 29.832 ;
    END
  END b[292]
  PIN b[293]
    DIRECTION OUTPUT ;
    USE SIGNAL ;
    PORT
      LAYER M4 ;
        RECT  0 29.856 0.192 29.88 ;
    END
  END b[293]
  PIN b[294]
    DIRECTION OUTPUT ;
    USE SIGNAL ;
    PORT
      LAYER M4 ;
        RECT  0 29.904 0.192 29.928 ;
    END
  END b[294]
  PIN b[295]
    DIRECTION OUTPUT ;
    USE SIGNAL ;
    PORT
      LAYER M4 ;
        RECT  0 29.952 0.192 29.976 ;
    END
  END b[295]
  PIN b[296]
    DIRECTION OUTPUT ;
    USE SIGNAL ;
    PORT
      LAYER M4 ;
        RECT  0 30 0.192 30.024 ;
    END
  END b[296]
  PIN b[297]
    DIRECTION OUTPUT ;
    USE SIGNAL ;
    PORT
      LAYER M4 ;
        RECT  0 30.048 0.192 30.072 ;
    END
  END b[297]
  PIN b[298]
    DIRECTION OUTPUT ;
    USE SIGNAL ;
    PORT
      LAYER M4 ;
        RECT  0 30.096 0.192 30.12 ;
    END
  END b[298]
  PIN b[299]
    DIRECTION OUTPUT ;
    USE SIGNAL ;
    PORT
      LAYER M4 ;
        RECT  0 30.144 0.192 30.168 ;
    END
  END b[299]
  PIN b[29]
    DIRECTION OUTPUT ;
    USE SIGNAL ;
    PORT
      LAYER M4 ;
        RECT  0 17.184 0.192 17.208 ;
    END
  END b[29]
  PIN b[2]
    DIRECTION OUTPUT ;
    USE SIGNAL ;
    PORT
      LAYER M4 ;
        RECT  0 15.888 0.192 15.912 ;
    END
  END b[2]
  PIN b[300]
    DIRECTION OUTPUT ;
    USE SIGNAL ;
    PORT
      LAYER M4 ;
        RECT  0 30.192 0.192 30.216 ;
    END
  END b[300]
  PIN b[301]
    DIRECTION OUTPUT ;
    USE SIGNAL ;
    PORT
      LAYER M4 ;
        RECT  0 30.24 0.192 30.264 ;
    END
  END b[301]
  PIN b[302]
    DIRECTION OUTPUT ;
    USE SIGNAL ;
    PORT
      LAYER M4 ;
        RECT  0 30.288 0.192 30.312 ;
    END
  END b[302]
  PIN b[303]
    DIRECTION OUTPUT ;
    USE SIGNAL ;
    PORT
      LAYER M4 ;
        RECT  0 30.336 0.192 30.36 ;
    END
  END b[303]
  PIN b[304]
    DIRECTION OUTPUT ;
    USE SIGNAL ;
    PORT
      LAYER M4 ;
        RECT  0 30.384 0.192 30.408 ;
    END
  END b[304]
  PIN b[305]
    DIRECTION OUTPUT ;
    USE SIGNAL ;
    PORT
      LAYER M4 ;
        RECT  0 30.432 0.192 30.456 ;
    END
  END b[305]
  PIN b[306]
    DIRECTION OUTPUT ;
    USE SIGNAL ;
    PORT
      LAYER M4 ;
        RECT  0 30.48 0.192 30.504 ;
    END
  END b[306]
  PIN b[307]
    DIRECTION OUTPUT ;
    USE SIGNAL ;
    PORT
      LAYER M4 ;
        RECT  0 30.528 0.192 30.552 ;
    END
  END b[307]
  PIN b[308]
    DIRECTION OUTPUT ;
    USE SIGNAL ;
    PORT
      LAYER M4 ;
        RECT  0 30.576 0.192 30.6 ;
    END
  END b[308]
  PIN b[309]
    DIRECTION OUTPUT ;
    USE SIGNAL ;
    PORT
      LAYER M4 ;
        RECT  0 30.624 0.192 30.648 ;
    END
  END b[309]
  PIN b[30]
    DIRECTION OUTPUT ;
    USE SIGNAL ;
    PORT
      LAYER M4 ;
        RECT  0 17.232 0.192 17.256 ;
    END
  END b[30]
  PIN b[310]
    DIRECTION OUTPUT ;
    USE SIGNAL ;
    PORT
      LAYER M4 ;
        RECT  0 30.672 0.192 30.696 ;
    END
  END b[310]
  PIN b[311]
    DIRECTION OUTPUT ;
    USE SIGNAL ;
    PORT
      LAYER M4 ;
        RECT  0 30.72 0.192 30.744 ;
    END
  END b[311]
  PIN b[312]
    DIRECTION OUTPUT ;
    USE SIGNAL ;
    PORT
      LAYER M4 ;
        RECT  0 30.768 0.192 30.792 ;
    END
  END b[312]
  PIN b[313]
    DIRECTION OUTPUT ;
    USE SIGNAL ;
    PORT
      LAYER M4 ;
        RECT  0 30.816 0.192 30.84 ;
    END
  END b[313]
  PIN b[314]
    DIRECTION OUTPUT ;
    USE SIGNAL ;
    PORT
      LAYER M4 ;
        RECT  0 30.864 0.192 30.888 ;
    END
  END b[314]
  PIN b[315]
    DIRECTION OUTPUT ;
    USE SIGNAL ;
    PORT
      LAYER M4 ;
        RECT  0 30.912 0.192 30.936 ;
    END
  END b[315]
  PIN b[316]
    DIRECTION OUTPUT ;
    USE SIGNAL ;
    PORT
      LAYER M4 ;
        RECT  0 30.96 0.192 30.984 ;
    END
  END b[316]
  PIN b[317]
    DIRECTION OUTPUT ;
    USE SIGNAL ;
    PORT
      LAYER M4 ;
        RECT  0 31.008 0.192 31.032 ;
    END
  END b[317]
  PIN b[318]
    DIRECTION OUTPUT ;
    USE SIGNAL ;
    PORT
      LAYER M4 ;
        RECT  0 31.056 0.192 31.08 ;
    END
  END b[318]
  PIN b[319]
    DIRECTION OUTPUT ;
    USE SIGNAL ;
    PORT
      LAYER M4 ;
        RECT  0 31.104 0.192 31.128 ;
    END
  END b[319]
  PIN b[31]
    DIRECTION OUTPUT ;
    USE SIGNAL ;
    PORT
      LAYER M4 ;
        RECT  0 17.28 0.192 17.304 ;
    END
  END b[31]
  PIN b[320]
    DIRECTION OUTPUT ;
    USE SIGNAL ;
    PORT
      LAYER M4 ;
        RECT  0 31.152 0.192 31.176 ;
    END
  END b[320]
  PIN b[321]
    DIRECTION OUTPUT ;
    USE SIGNAL ;
    PORT
      LAYER M4 ;
        RECT  0 31.2 0.192 31.224 ;
    END
  END b[321]
  PIN b[322]
    DIRECTION OUTPUT ;
    USE SIGNAL ;
    PORT
      LAYER M4 ;
        RECT  0 31.248 0.192 31.272 ;
    END
  END b[322]
  PIN b[323]
    DIRECTION OUTPUT ;
    USE SIGNAL ;
    PORT
      LAYER M4 ;
        RECT  0 31.296 0.192 31.32 ;
    END
  END b[323]
  PIN b[324]
    DIRECTION OUTPUT ;
    USE SIGNAL ;
    PORT
      LAYER M4 ;
        RECT  0 31.344 0.192 31.368 ;
    END
  END b[324]
  PIN b[325]
    DIRECTION OUTPUT ;
    USE SIGNAL ;
    PORT
      LAYER M4 ;
        RECT  0 31.392 0.192 31.416 ;
    END
  END b[325]
  PIN b[326]
    DIRECTION OUTPUT ;
    USE SIGNAL ;
    PORT
      LAYER M4 ;
        RECT  0 31.44 0.192 31.464 ;
    END
  END b[326]
  PIN b[327]
    DIRECTION OUTPUT ;
    USE SIGNAL ;
    PORT
      LAYER M4 ;
        RECT  0 31.488 0.192 31.512 ;
    END
  END b[327]
  PIN b[328]
    DIRECTION OUTPUT ;
    USE SIGNAL ;
    PORT
      LAYER M4 ;
        RECT  0 31.536 0.192 31.56 ;
    END
  END b[328]
  PIN b[329]
    DIRECTION OUTPUT ;
    USE SIGNAL ;
    PORT
      LAYER M4 ;
        RECT  0 31.584 0.192 31.608 ;
    END
  END b[329]
  PIN b[32]
    DIRECTION OUTPUT ;
    USE SIGNAL ;
    PORT
      LAYER M4 ;
        RECT  0 17.328 0.192 17.352 ;
    END
  END b[32]
  PIN b[330]
    DIRECTION OUTPUT ;
    USE SIGNAL ;
    PORT
      LAYER M4 ;
        RECT  0 31.632 0.192 31.656 ;
    END
  END b[330]
  PIN b[331]
    DIRECTION OUTPUT ;
    USE SIGNAL ;
    PORT
      LAYER M4 ;
        RECT  0 31.68 0.192 31.704 ;
    END
  END b[331]
  PIN b[332]
    DIRECTION OUTPUT ;
    USE SIGNAL ;
    PORT
      LAYER M4 ;
        RECT  0 31.728 0.192 31.752 ;
    END
  END b[332]
  PIN b[333]
    DIRECTION OUTPUT ;
    USE SIGNAL ;
    PORT
      LAYER M4 ;
        RECT  0 31.776 0.192 31.8 ;
    END
  END b[333]
  PIN b[334]
    DIRECTION OUTPUT ;
    USE SIGNAL ;
    PORT
      LAYER M4 ;
        RECT  0 31.824 0.192 31.848 ;
    END
  END b[334]
  PIN b[335]
    DIRECTION OUTPUT ;
    USE SIGNAL ;
    PORT
      LAYER M4 ;
        RECT  0 31.872 0.192 31.896 ;
    END
  END b[335]
  PIN b[336]
    DIRECTION OUTPUT ;
    USE SIGNAL ;
    PORT
      LAYER M4 ;
        RECT  0 31.92 0.192 31.944 ;
    END
  END b[336]
  PIN b[337]
    DIRECTION OUTPUT ;
    USE SIGNAL ;
    PORT
      LAYER M4 ;
        RECT  0 31.968 0.192 31.992 ;
    END
  END b[337]
  PIN b[338]
    DIRECTION OUTPUT ;
    USE SIGNAL ;
    PORT
      LAYER M4 ;
        RECT  0 32.016 0.192 32.04 ;
    END
  END b[338]
  PIN b[339]
    DIRECTION OUTPUT ;
    USE SIGNAL ;
    PORT
      LAYER M4 ;
        RECT  0 32.064 0.192 32.088 ;
    END
  END b[339]
  PIN b[33]
    DIRECTION OUTPUT ;
    USE SIGNAL ;
    PORT
      LAYER M4 ;
        RECT  0 17.376 0.192 17.4 ;
    END
  END b[33]
  PIN b[340]
    DIRECTION OUTPUT ;
    USE SIGNAL ;
    PORT
      LAYER M4 ;
        RECT  0 32.112 0.192 32.136 ;
    END
  END b[340]
  PIN b[341]
    DIRECTION OUTPUT ;
    USE SIGNAL ;
    PORT
      LAYER M4 ;
        RECT  0 32.16 0.192 32.184 ;
    END
  END b[341]
  PIN b[342]
    DIRECTION OUTPUT ;
    USE SIGNAL ;
    PORT
      LAYER M4 ;
        RECT  0 32.208 0.192 32.232 ;
    END
  END b[342]
  PIN b[343]
    DIRECTION OUTPUT ;
    USE SIGNAL ;
    PORT
      LAYER M4 ;
        RECT  0 32.256 0.192 32.28 ;
    END
  END b[343]
  PIN b[344]
    DIRECTION OUTPUT ;
    USE SIGNAL ;
    PORT
      LAYER M4 ;
        RECT  0 32.304 0.192 32.328 ;
    END
  END b[344]
  PIN b[345]
    DIRECTION OUTPUT ;
    USE SIGNAL ;
    PORT
      LAYER M4 ;
        RECT  0 32.352 0.192 32.376 ;
    END
  END b[345]
  PIN b[346]
    DIRECTION OUTPUT ;
    USE SIGNAL ;
    PORT
      LAYER M4 ;
        RECT  0 32.4 0.192 32.424 ;
    END
  END b[346]
  PIN b[347]
    DIRECTION OUTPUT ;
    USE SIGNAL ;
    PORT
      LAYER M4 ;
        RECT  0 32.448 0.192 32.472 ;
    END
  END b[347]
  PIN b[348]
    DIRECTION OUTPUT ;
    USE SIGNAL ;
    PORT
      LAYER M4 ;
        RECT  0 32.496 0.192 32.52 ;
    END
  END b[348]
  PIN b[349]
    DIRECTION OUTPUT ;
    USE SIGNAL ;
    PORT
      LAYER M4 ;
        RECT  0 32.544 0.192 32.568 ;
    END
  END b[349]
  PIN b[34]
    DIRECTION OUTPUT ;
    USE SIGNAL ;
    PORT
      LAYER M4 ;
        RECT  0 17.424 0.192 17.448 ;
    END
  END b[34]
  PIN b[350]
    DIRECTION OUTPUT ;
    USE SIGNAL ;
    PORT
      LAYER M4 ;
        RECT  0 32.592 0.192 32.616 ;
    END
  END b[350]
  PIN b[351]
    DIRECTION OUTPUT ;
    USE SIGNAL ;
    PORT
      LAYER M4 ;
        RECT  0 32.64 0.192 32.664 ;
    END
  END b[351]
  PIN b[352]
    DIRECTION OUTPUT ;
    USE SIGNAL ;
    PORT
      LAYER M4 ;
        RECT  0 32.688 0.192 32.712 ;
    END
  END b[352]
  PIN b[353]
    DIRECTION OUTPUT ;
    USE SIGNAL ;
    PORT
      LAYER M4 ;
        RECT  0 32.736 0.192 32.76 ;
    END
  END b[353]
  PIN b[354]
    DIRECTION OUTPUT ;
    USE SIGNAL ;
    PORT
      LAYER M4 ;
        RECT  0 32.784 0.192 32.808 ;
    END
  END b[354]
  PIN b[355]
    DIRECTION OUTPUT ;
    USE SIGNAL ;
    PORT
      LAYER M4 ;
        RECT  0 32.832 0.192 32.856 ;
    END
  END b[355]
  PIN b[356]
    DIRECTION OUTPUT ;
    USE SIGNAL ;
    PORT
      LAYER M4 ;
        RECT  0 32.88 0.192 32.904 ;
    END
  END b[356]
  PIN b[357]
    DIRECTION OUTPUT ;
    USE SIGNAL ;
    PORT
      LAYER M4 ;
        RECT  0 32.928 0.192 32.952 ;
    END
  END b[357]
  PIN b[358]
    DIRECTION OUTPUT ;
    USE SIGNAL ;
    PORT
      LAYER M4 ;
        RECT  0 32.976 0.192 33 ;
    END
  END b[358]
  PIN b[359]
    DIRECTION OUTPUT ;
    USE SIGNAL ;
    PORT
      LAYER M4 ;
        RECT  0 33.024 0.192 33.048 ;
    END
  END b[359]
  PIN b[35]
    DIRECTION OUTPUT ;
    USE SIGNAL ;
    PORT
      LAYER M4 ;
        RECT  0 17.472 0.192 17.496 ;
    END
  END b[35]
  PIN b[360]
    DIRECTION OUTPUT ;
    USE SIGNAL ;
    PORT
      LAYER M4 ;
        RECT  0 33.072 0.192 33.096 ;
    END
  END b[360]
  PIN b[361]
    DIRECTION OUTPUT ;
    USE SIGNAL ;
    PORT
      LAYER M4 ;
        RECT  0 33.12 0.192 33.144 ;
    END
  END b[361]
  PIN b[362]
    DIRECTION OUTPUT ;
    USE SIGNAL ;
    PORT
      LAYER M4 ;
        RECT  0 33.168 0.192 33.192 ;
    END
  END b[362]
  PIN b[363]
    DIRECTION OUTPUT ;
    USE SIGNAL ;
    PORT
      LAYER M4 ;
        RECT  0 33.216 0.192 33.24 ;
    END
  END b[363]
  PIN b[364]
    DIRECTION OUTPUT ;
    USE SIGNAL ;
    PORT
      LAYER M4 ;
        RECT  0 33.264 0.192 33.288 ;
    END
  END b[364]
  PIN b[365]
    DIRECTION OUTPUT ;
    USE SIGNAL ;
    PORT
      LAYER M4 ;
        RECT  0 33.312 0.192 33.336 ;
    END
  END b[365]
  PIN b[366]
    DIRECTION OUTPUT ;
    USE SIGNAL ;
    PORT
      LAYER M4 ;
        RECT  0 33.36 0.192 33.384 ;
    END
  END b[366]
  PIN b[367]
    DIRECTION OUTPUT ;
    USE SIGNAL ;
    PORT
      LAYER M4 ;
        RECT  0 33.408 0.192 33.432 ;
    END
  END b[367]
  PIN b[368]
    DIRECTION OUTPUT ;
    USE SIGNAL ;
    PORT
      LAYER M4 ;
        RECT  0 33.456 0.192 33.48 ;
    END
  END b[368]
  PIN b[369]
    DIRECTION OUTPUT ;
    USE SIGNAL ;
    PORT
      LAYER M4 ;
        RECT  0 33.504 0.192 33.528 ;
    END
  END b[369]
  PIN b[36]
    DIRECTION OUTPUT ;
    USE SIGNAL ;
    PORT
      LAYER M4 ;
        RECT  0 17.52 0.192 17.544 ;
    END
  END b[36]
  PIN b[370]
    DIRECTION OUTPUT ;
    USE SIGNAL ;
    PORT
      LAYER M4 ;
        RECT  0 33.552 0.192 33.576 ;
    END
  END b[370]
  PIN b[371]
    DIRECTION OUTPUT ;
    USE SIGNAL ;
    PORT
      LAYER M4 ;
        RECT  0 33.6 0.192 33.624 ;
    END
  END b[371]
  PIN b[372]
    DIRECTION OUTPUT ;
    USE SIGNAL ;
    PORT
      LAYER M4 ;
        RECT  0 33.648 0.192 33.672 ;
    END
  END b[372]
  PIN b[373]
    DIRECTION OUTPUT ;
    USE SIGNAL ;
    PORT
      LAYER M4 ;
        RECT  0 33.696 0.192 33.72 ;
    END
  END b[373]
  PIN b[374]
    DIRECTION OUTPUT ;
    USE SIGNAL ;
    PORT
      LAYER M4 ;
        RECT  0 33.744 0.192 33.768 ;
    END
  END b[374]
  PIN b[375]
    DIRECTION OUTPUT ;
    USE SIGNAL ;
    PORT
      LAYER M4 ;
        RECT  0 33.792 0.192 33.816 ;
    END
  END b[375]
  PIN b[376]
    DIRECTION OUTPUT ;
    USE SIGNAL ;
    PORT
      LAYER M4 ;
        RECT  0 33.84 0.192 33.864 ;
    END
  END b[376]
  PIN b[377]
    DIRECTION OUTPUT ;
    USE SIGNAL ;
    PORT
      LAYER M4 ;
        RECT  0 33.888 0.192 33.912 ;
    END
  END b[377]
  PIN b[378]
    DIRECTION OUTPUT ;
    USE SIGNAL ;
    PORT
      LAYER M4 ;
        RECT  0 33.936 0.192 33.96 ;
    END
  END b[378]
  PIN b[379]
    DIRECTION OUTPUT ;
    USE SIGNAL ;
    PORT
      LAYER M4 ;
        RECT  0 33.984 0.192 34.008 ;
    END
  END b[379]
  PIN b[37]
    DIRECTION OUTPUT ;
    USE SIGNAL ;
    PORT
      LAYER M4 ;
        RECT  0 17.568 0.192 17.592 ;
    END
  END b[37]
  PIN b[380]
    DIRECTION OUTPUT ;
    USE SIGNAL ;
    PORT
      LAYER M4 ;
        RECT  0 34.032 0.192 34.056 ;
    END
  END b[380]
  PIN b[381]
    DIRECTION OUTPUT ;
    USE SIGNAL ;
    PORT
      LAYER M4 ;
        RECT  0 34.08 0.192 34.104 ;
    END
  END b[381]
  PIN b[382]
    DIRECTION OUTPUT ;
    USE SIGNAL ;
    PORT
      LAYER M4 ;
        RECT  0 34.128 0.192 34.152 ;
    END
  END b[382]
  PIN b[383]
    DIRECTION OUTPUT ;
    USE SIGNAL ;
    PORT
      LAYER M4 ;
        RECT  0 34.176 0.192 34.2 ;
    END
  END b[383]
  PIN b[384]
    DIRECTION OUTPUT ;
    USE SIGNAL ;
    PORT
      LAYER M4 ;
        RECT  0 34.224 0.192 34.248 ;
    END
  END b[384]
  PIN b[385]
    DIRECTION OUTPUT ;
    USE SIGNAL ;
    PORT
      LAYER M4 ;
        RECT  0 34.272 0.192 34.296 ;
    END
  END b[385]
  PIN b[386]
    DIRECTION OUTPUT ;
    USE SIGNAL ;
    PORT
      LAYER M4 ;
        RECT  0 34.32 0.192 34.344 ;
    END
  END b[386]
  PIN b[387]
    DIRECTION OUTPUT ;
    USE SIGNAL ;
    PORT
      LAYER M4 ;
        RECT  0 34.368 0.192 34.392 ;
    END
  END b[387]
  PIN b[388]
    DIRECTION OUTPUT ;
    USE SIGNAL ;
    PORT
      LAYER M4 ;
        RECT  0 34.416 0.192 34.44 ;
    END
  END b[388]
  PIN b[389]
    DIRECTION OUTPUT ;
    USE SIGNAL ;
    PORT
      LAYER M4 ;
        RECT  0 34.464 0.192 34.488 ;
    END
  END b[389]
  PIN b[38]
    DIRECTION OUTPUT ;
    USE SIGNAL ;
    PORT
      LAYER M4 ;
        RECT  0 17.616 0.192 17.64 ;
    END
  END b[38]
  PIN b[390]
    DIRECTION OUTPUT ;
    USE SIGNAL ;
    PORT
      LAYER M4 ;
        RECT  0 34.512 0.192 34.536 ;
    END
  END b[390]
  PIN b[391]
    DIRECTION OUTPUT ;
    USE SIGNAL ;
    PORT
      LAYER M4 ;
        RECT  0 34.56 0.192 34.584 ;
    END
  END b[391]
  PIN b[392]
    DIRECTION OUTPUT ;
    USE SIGNAL ;
    PORT
      LAYER M4 ;
        RECT  0 34.608 0.192 34.632 ;
    END
  END b[392]
  PIN b[393]
    DIRECTION OUTPUT ;
    USE SIGNAL ;
    PORT
      LAYER M4 ;
        RECT  0 34.656 0.192 34.68 ;
    END
  END b[393]
  PIN b[394]
    DIRECTION OUTPUT ;
    USE SIGNAL ;
    PORT
      LAYER M4 ;
        RECT  0 34.704 0.192 34.728 ;
    END
  END b[394]
  PIN b[395]
    DIRECTION OUTPUT ;
    USE SIGNAL ;
    PORT
      LAYER M4 ;
        RECT  0 34.752 0.192 34.776 ;
    END
  END b[395]
  PIN b[396]
    DIRECTION OUTPUT ;
    USE SIGNAL ;
    PORT
      LAYER M4 ;
        RECT  0 34.8 0.192 34.824 ;
    END
  END b[396]
  PIN b[397]
    DIRECTION OUTPUT ;
    USE SIGNAL ;
    PORT
      LAYER M4 ;
        RECT  0 34.848 0.192 34.872 ;
    END
  END b[397]
  PIN b[398]
    DIRECTION OUTPUT ;
    USE SIGNAL ;
    PORT
      LAYER M4 ;
        RECT  0 34.896 0.192 34.92 ;
    END
  END b[398]
  PIN b[399]
    DIRECTION OUTPUT ;
    USE SIGNAL ;
    PORT
      LAYER M4 ;
        RECT  0 34.944 0.192 34.968 ;
    END
  END b[399]
  PIN b[39]
    DIRECTION OUTPUT ;
    USE SIGNAL ;
    PORT
      LAYER M4 ;
        RECT  0 17.664 0.192 17.688 ;
    END
  END b[39]
  PIN b[3]
    DIRECTION OUTPUT ;
    USE SIGNAL ;
    PORT
      LAYER M4 ;
        RECT  0 15.936 0.192 15.96 ;
    END
  END b[3]
  PIN b[400]
    DIRECTION OUTPUT ;
    USE SIGNAL ;
    PORT
      LAYER M4 ;
        RECT  0 34.992 0.192 35.016 ;
    END
  END b[400]
  PIN b[401]
    DIRECTION OUTPUT ;
    USE SIGNAL ;
    PORT
      LAYER M4 ;
        RECT  0 35.04 0.192 35.064 ;
    END
  END b[401]
  PIN b[402]
    DIRECTION OUTPUT ;
    USE SIGNAL ;
    PORT
      LAYER M4 ;
        RECT  0 35.088 0.192 35.112 ;
    END
  END b[402]
  PIN b[403]
    DIRECTION OUTPUT ;
    USE SIGNAL ;
    PORT
      LAYER M4 ;
        RECT  0 35.136 0.192 35.16 ;
    END
  END b[403]
  PIN b[404]
    DIRECTION OUTPUT ;
    USE SIGNAL ;
    PORT
      LAYER M4 ;
        RECT  0 35.184 0.192 35.208 ;
    END
  END b[404]
  PIN b[405]
    DIRECTION OUTPUT ;
    USE SIGNAL ;
    PORT
      LAYER M4 ;
        RECT  0 35.232 0.192 35.256 ;
    END
  END b[405]
  PIN b[406]
    DIRECTION OUTPUT ;
    USE SIGNAL ;
    PORT
      LAYER M4 ;
        RECT  0 35.28 0.192 35.304 ;
    END
  END b[406]
  PIN b[407]
    DIRECTION OUTPUT ;
    USE SIGNAL ;
    PORT
      LAYER M4 ;
        RECT  0 35.328 0.192 35.352 ;
    END
  END b[407]
  PIN b[408]
    DIRECTION OUTPUT ;
    USE SIGNAL ;
    PORT
      LAYER M4 ;
        RECT  0 35.376 0.192 35.4 ;
    END
  END b[408]
  PIN b[409]
    DIRECTION OUTPUT ;
    USE SIGNAL ;
    PORT
      LAYER M4 ;
        RECT  0 35.424 0.192 35.448 ;
    END
  END b[409]
  PIN b[40]
    DIRECTION OUTPUT ;
    USE SIGNAL ;
    PORT
      LAYER M4 ;
        RECT  0 17.712 0.192 17.736 ;
    END
  END b[40]
  PIN b[410]
    DIRECTION OUTPUT ;
    USE SIGNAL ;
    PORT
      LAYER M4 ;
        RECT  0 35.472 0.192 35.496 ;
    END
  END b[410]
  PIN b[411]
    DIRECTION OUTPUT ;
    USE SIGNAL ;
    PORT
      LAYER M4 ;
        RECT  0 35.52 0.192 35.544 ;
    END
  END b[411]
  PIN b[412]
    DIRECTION OUTPUT ;
    USE SIGNAL ;
    PORT
      LAYER M4 ;
        RECT  0 35.568 0.192 35.592 ;
    END
  END b[412]
  PIN b[413]
    DIRECTION OUTPUT ;
    USE SIGNAL ;
    PORT
      LAYER M4 ;
        RECT  0 35.616 0.192 35.64 ;
    END
  END b[413]
  PIN b[414]
    DIRECTION OUTPUT ;
    USE SIGNAL ;
    PORT
      LAYER M4 ;
        RECT  0 35.664 0.192 35.688 ;
    END
  END b[414]
  PIN b[415]
    DIRECTION OUTPUT ;
    USE SIGNAL ;
    PORT
      LAYER M4 ;
        RECT  0 35.712 0.192 35.736 ;
    END
  END b[415]
  PIN b[416]
    DIRECTION OUTPUT ;
    USE SIGNAL ;
    PORT
      LAYER M4 ;
        RECT  0 35.76 0.192 35.784 ;
    END
  END b[416]
  PIN b[417]
    DIRECTION OUTPUT ;
    USE SIGNAL ;
    PORT
      LAYER M4 ;
        RECT  0 35.808 0.192 35.832 ;
    END
  END b[417]
  PIN b[418]
    DIRECTION OUTPUT ;
    USE SIGNAL ;
    PORT
      LAYER M4 ;
        RECT  0 35.856 0.192 35.88 ;
    END
  END b[418]
  PIN b[419]
    DIRECTION OUTPUT ;
    USE SIGNAL ;
    PORT
      LAYER M4 ;
        RECT  0 35.904 0.192 35.928 ;
    END
  END b[419]
  PIN b[41]
    DIRECTION OUTPUT ;
    USE SIGNAL ;
    PORT
      LAYER M4 ;
        RECT  0 17.76 0.192 17.784 ;
    END
  END b[41]
  PIN b[420]
    DIRECTION OUTPUT ;
    USE SIGNAL ;
    PORT
      LAYER M4 ;
        RECT  0 35.952 0.192 35.976 ;
    END
  END b[420]
  PIN b[421]
    DIRECTION OUTPUT ;
    USE SIGNAL ;
    PORT
      LAYER M4 ;
        RECT  0 36 0.192 36.024 ;
    END
  END b[421]
  PIN b[422]
    DIRECTION OUTPUT ;
    USE SIGNAL ;
    PORT
      LAYER M4 ;
        RECT  0 36.048 0.192 36.072 ;
    END
  END b[422]
  PIN b[423]
    DIRECTION OUTPUT ;
    USE SIGNAL ;
    PORT
      LAYER M4 ;
        RECT  0 36.096 0.192 36.12 ;
    END
  END b[423]
  PIN b[424]
    DIRECTION OUTPUT ;
    USE SIGNAL ;
    PORT
      LAYER M4 ;
        RECT  0 36.144 0.192 36.168 ;
    END
  END b[424]
  PIN b[425]
    DIRECTION OUTPUT ;
    USE SIGNAL ;
    PORT
      LAYER M4 ;
        RECT  0 36.192 0.192 36.216 ;
    END
  END b[425]
  PIN b[426]
    DIRECTION OUTPUT ;
    USE SIGNAL ;
    PORT
      LAYER M4 ;
        RECT  0 36.24 0.192 36.264 ;
    END
  END b[426]
  PIN b[427]
    DIRECTION OUTPUT ;
    USE SIGNAL ;
    PORT
      LAYER M4 ;
        RECT  0 36.288 0.192 36.312 ;
    END
  END b[427]
  PIN b[428]
    DIRECTION OUTPUT ;
    USE SIGNAL ;
    PORT
      LAYER M4 ;
        RECT  0 36.336 0.192 36.36 ;
    END
  END b[428]
  PIN b[429]
    DIRECTION OUTPUT ;
    USE SIGNAL ;
    PORT
      LAYER M4 ;
        RECT  0 36.384 0.192 36.408 ;
    END
  END b[429]
  PIN b[42]
    DIRECTION OUTPUT ;
    USE SIGNAL ;
    PORT
      LAYER M4 ;
        RECT  0 17.808 0.192 17.832 ;
    END
  END b[42]
  PIN b[430]
    DIRECTION OUTPUT ;
    USE SIGNAL ;
    PORT
      LAYER M4 ;
        RECT  0 36.432 0.192 36.456 ;
    END
  END b[430]
  PIN b[431]
    DIRECTION OUTPUT ;
    USE SIGNAL ;
    PORT
      LAYER M4 ;
        RECT  0 36.48 0.192 36.504 ;
    END
  END b[431]
  PIN b[432]
    DIRECTION OUTPUT ;
    USE SIGNAL ;
    PORT
      LAYER M4 ;
        RECT  0 36.528 0.192 36.552 ;
    END
  END b[432]
  PIN b[433]
    DIRECTION OUTPUT ;
    USE SIGNAL ;
    PORT
      LAYER M4 ;
        RECT  0 36.576 0.192 36.6 ;
    END
  END b[433]
  PIN b[434]
    DIRECTION OUTPUT ;
    USE SIGNAL ;
    PORT
      LAYER M4 ;
        RECT  0 36.624 0.192 36.648 ;
    END
  END b[434]
  PIN b[435]
    DIRECTION OUTPUT ;
    USE SIGNAL ;
    PORT
      LAYER M4 ;
        RECT  0 36.672 0.192 36.696 ;
    END
  END b[435]
  PIN b[436]
    DIRECTION OUTPUT ;
    USE SIGNAL ;
    PORT
      LAYER M4 ;
        RECT  0 36.72 0.192 36.744 ;
    END
  END b[436]
  PIN b[437]
    DIRECTION OUTPUT ;
    USE SIGNAL ;
    PORT
      LAYER M4 ;
        RECT  0 36.768 0.192 36.792 ;
    END
  END b[437]
  PIN b[438]
    DIRECTION OUTPUT ;
    USE SIGNAL ;
    PORT
      LAYER M4 ;
        RECT  0 36.816 0.192 36.84 ;
    END
  END b[438]
  PIN b[439]
    DIRECTION OUTPUT ;
    USE SIGNAL ;
    PORT
      LAYER M4 ;
        RECT  0 36.864 0.192 36.888 ;
    END
  END b[439]
  PIN b[43]
    DIRECTION OUTPUT ;
    USE SIGNAL ;
    PORT
      LAYER M4 ;
        RECT  0 17.856 0.192 17.88 ;
    END
  END b[43]
  PIN b[440]
    DIRECTION OUTPUT ;
    USE SIGNAL ;
    PORT
      LAYER M4 ;
        RECT  0 36.912 0.192 36.936 ;
    END
  END b[440]
  PIN b[441]
    DIRECTION OUTPUT ;
    USE SIGNAL ;
    PORT
      LAYER M4 ;
        RECT  0 36.96 0.192 36.984 ;
    END
  END b[441]
  PIN b[442]
    DIRECTION OUTPUT ;
    USE SIGNAL ;
    PORT
      LAYER M4 ;
        RECT  0 37.008 0.192 37.032 ;
    END
  END b[442]
  PIN b[443]
    DIRECTION OUTPUT ;
    USE SIGNAL ;
    PORT
      LAYER M4 ;
        RECT  0 37.056 0.192 37.08 ;
    END
  END b[443]
  PIN b[444]
    DIRECTION OUTPUT ;
    USE SIGNAL ;
    PORT
      LAYER M4 ;
        RECT  0 37.104 0.192 37.128 ;
    END
  END b[444]
  PIN b[445]
    DIRECTION OUTPUT ;
    USE SIGNAL ;
    PORT
      LAYER M4 ;
        RECT  0 37.152 0.192 37.176 ;
    END
  END b[445]
  PIN b[446]
    DIRECTION OUTPUT ;
    USE SIGNAL ;
    PORT
      LAYER M4 ;
        RECT  0 37.2 0.192 37.224 ;
    END
  END b[446]
  PIN b[447]
    DIRECTION OUTPUT ;
    USE SIGNAL ;
    PORT
      LAYER M4 ;
        RECT  0 37.248 0.192 37.272 ;
    END
  END b[447]
  PIN b[448]
    DIRECTION OUTPUT ;
    USE SIGNAL ;
    PORT
      LAYER M4 ;
        RECT  0 37.296 0.192 37.32 ;
    END
  END b[448]
  PIN b[449]
    DIRECTION OUTPUT ;
    USE SIGNAL ;
    PORT
      LAYER M4 ;
        RECT  0 37.344 0.192 37.368 ;
    END
  END b[449]
  PIN b[44]
    DIRECTION OUTPUT ;
    USE SIGNAL ;
    PORT
      LAYER M4 ;
        RECT  0 17.904 0.192 17.928 ;
    END
  END b[44]
  PIN b[450]
    DIRECTION OUTPUT ;
    USE SIGNAL ;
    PORT
      LAYER M4 ;
        RECT  0 37.392 0.192 37.416 ;
    END
  END b[450]
  PIN b[451]
    DIRECTION OUTPUT ;
    USE SIGNAL ;
    PORT
      LAYER M4 ;
        RECT  0 37.44 0.192 37.464 ;
    END
  END b[451]
  PIN b[452]
    DIRECTION OUTPUT ;
    USE SIGNAL ;
    PORT
      LAYER M4 ;
        RECT  0 37.488 0.192 37.512 ;
    END
  END b[452]
  PIN b[453]
    DIRECTION OUTPUT ;
    USE SIGNAL ;
    PORT
      LAYER M4 ;
        RECT  0 37.536 0.192 37.56 ;
    END
  END b[453]
  PIN b[454]
    DIRECTION OUTPUT ;
    USE SIGNAL ;
    PORT
      LAYER M4 ;
        RECT  0 37.584 0.192 37.608 ;
    END
  END b[454]
  PIN b[455]
    DIRECTION OUTPUT ;
    USE SIGNAL ;
    PORT
      LAYER M4 ;
        RECT  0 37.632 0.192 37.656 ;
    END
  END b[455]
  PIN b[456]
    DIRECTION OUTPUT ;
    USE SIGNAL ;
    PORT
      LAYER M4 ;
        RECT  0 37.68 0.192 37.704 ;
    END
  END b[456]
  PIN b[457]
    DIRECTION OUTPUT ;
    USE SIGNAL ;
    PORT
      LAYER M4 ;
        RECT  0 37.728 0.192 37.752 ;
    END
  END b[457]
  PIN b[458]
    DIRECTION OUTPUT ;
    USE SIGNAL ;
    PORT
      LAYER M4 ;
        RECT  0 37.776 0.192 37.8 ;
    END
  END b[458]
  PIN b[459]
    DIRECTION OUTPUT ;
    USE SIGNAL ;
    PORT
      LAYER M4 ;
        RECT  0 37.824 0.192 37.848 ;
    END
  END b[459]
  PIN b[45]
    DIRECTION OUTPUT ;
    USE SIGNAL ;
    PORT
      LAYER M4 ;
        RECT  0 17.952 0.192 17.976 ;
    END
  END b[45]
  PIN b[460]
    DIRECTION OUTPUT ;
    USE SIGNAL ;
    PORT
      LAYER M4 ;
        RECT  0 37.872 0.192 37.896 ;
    END
  END b[460]
  PIN b[461]
    DIRECTION OUTPUT ;
    USE SIGNAL ;
    PORT
      LAYER M4 ;
        RECT  0 37.92 0.192 37.944 ;
    END
  END b[461]
  PIN b[462]
    DIRECTION OUTPUT ;
    USE SIGNAL ;
    PORT
      LAYER M4 ;
        RECT  0 37.968 0.192 37.992 ;
    END
  END b[462]
  PIN b[463]
    DIRECTION OUTPUT ;
    USE SIGNAL ;
    PORT
      LAYER M4 ;
        RECT  0 38.016 0.192 38.04 ;
    END
  END b[463]
  PIN b[464]
    DIRECTION OUTPUT ;
    USE SIGNAL ;
    PORT
      LAYER M4 ;
        RECT  0 38.064 0.192 38.088 ;
    END
  END b[464]
  PIN b[465]
    DIRECTION OUTPUT ;
    USE SIGNAL ;
    PORT
      LAYER M4 ;
        RECT  0 38.112 0.192 38.136 ;
    END
  END b[465]
  PIN b[466]
    DIRECTION OUTPUT ;
    USE SIGNAL ;
    PORT
      LAYER M4 ;
        RECT  0 38.16 0.192 38.184 ;
    END
  END b[466]
  PIN b[467]
    DIRECTION OUTPUT ;
    USE SIGNAL ;
    PORT
      LAYER M4 ;
        RECT  0 38.208 0.192 38.232 ;
    END
  END b[467]
  PIN b[468]
    DIRECTION OUTPUT ;
    USE SIGNAL ;
    PORT
      LAYER M4 ;
        RECT  0 38.256 0.192 38.28 ;
    END
  END b[468]
  PIN b[469]
    DIRECTION OUTPUT ;
    USE SIGNAL ;
    PORT
      LAYER M4 ;
        RECT  0 38.304 0.192 38.328 ;
    END
  END b[469]
  PIN b[46]
    DIRECTION OUTPUT ;
    USE SIGNAL ;
    PORT
      LAYER M4 ;
        RECT  0 18 0.192 18.024 ;
    END
  END b[46]
  PIN b[470]
    DIRECTION OUTPUT ;
    USE SIGNAL ;
    PORT
      LAYER M4 ;
        RECT  0 38.352 0.192 38.376 ;
    END
  END b[470]
  PIN b[471]
    DIRECTION OUTPUT ;
    USE SIGNAL ;
    PORT
      LAYER M4 ;
        RECT  0 38.4 0.192 38.424 ;
    END
  END b[471]
  PIN b[472]
    DIRECTION OUTPUT ;
    USE SIGNAL ;
    PORT
      LAYER M4 ;
        RECT  0 38.448 0.192 38.472 ;
    END
  END b[472]
  PIN b[473]
    DIRECTION OUTPUT ;
    USE SIGNAL ;
    PORT
      LAYER M4 ;
        RECT  0 38.496 0.192 38.52 ;
    END
  END b[473]
  PIN b[474]
    DIRECTION OUTPUT ;
    USE SIGNAL ;
    PORT
      LAYER M4 ;
        RECT  0 38.544 0.192 38.568 ;
    END
  END b[474]
  PIN b[475]
    DIRECTION OUTPUT ;
    USE SIGNAL ;
    PORT
      LAYER M4 ;
        RECT  0 38.592 0.192 38.616 ;
    END
  END b[475]
  PIN b[476]
    DIRECTION OUTPUT ;
    USE SIGNAL ;
    PORT
      LAYER M4 ;
        RECT  0 38.64 0.192 38.664 ;
    END
  END b[476]
  PIN b[477]
    DIRECTION OUTPUT ;
    USE SIGNAL ;
    PORT
      LAYER M4 ;
        RECT  0 38.688 0.192 38.712 ;
    END
  END b[477]
  PIN b[478]
    DIRECTION OUTPUT ;
    USE SIGNAL ;
    PORT
      LAYER M4 ;
        RECT  0 38.736 0.192 38.76 ;
    END
  END b[478]
  PIN b[479]
    DIRECTION OUTPUT ;
    USE SIGNAL ;
    PORT
      LAYER M4 ;
        RECT  0 38.784 0.192 38.808 ;
    END
  END b[479]
  PIN b[47]
    DIRECTION OUTPUT ;
    USE SIGNAL ;
    PORT
      LAYER M4 ;
        RECT  0 18.048 0.192 18.072 ;
    END
  END b[47]
  PIN b[480]
    DIRECTION OUTPUT ;
    USE SIGNAL ;
    PORT
      LAYER M4 ;
        RECT  0 38.832 0.192 38.856 ;
    END
  END b[480]
  PIN b[481]
    DIRECTION OUTPUT ;
    USE SIGNAL ;
    PORT
      LAYER M4 ;
        RECT  0 38.88 0.192 38.904 ;
    END
  END b[481]
  PIN b[482]
    DIRECTION OUTPUT ;
    USE SIGNAL ;
    PORT
      LAYER M4 ;
        RECT  0 38.928 0.192 38.952 ;
    END
  END b[482]
  PIN b[483]
    DIRECTION OUTPUT ;
    USE SIGNAL ;
    PORT
      LAYER M4 ;
        RECT  0 38.976 0.192 39 ;
    END
  END b[483]
  PIN b[484]
    DIRECTION OUTPUT ;
    USE SIGNAL ;
    PORT
      LAYER M4 ;
        RECT  0 39.024 0.192 39.048 ;
    END
  END b[484]
  PIN b[485]
    DIRECTION OUTPUT ;
    USE SIGNAL ;
    PORT
      LAYER M4 ;
        RECT  0 39.072 0.192 39.096 ;
    END
  END b[485]
  PIN b[486]
    DIRECTION OUTPUT ;
    USE SIGNAL ;
    PORT
      LAYER M4 ;
        RECT  0 39.12 0.192 39.144 ;
    END
  END b[486]
  PIN b[487]
    DIRECTION OUTPUT ;
    USE SIGNAL ;
    PORT
      LAYER M4 ;
        RECT  0 39.168 0.192 39.192 ;
    END
  END b[487]
  PIN b[488]
    DIRECTION OUTPUT ;
    USE SIGNAL ;
    PORT
      LAYER M4 ;
        RECT  0 39.216 0.192 39.24 ;
    END
  END b[488]
  PIN b[489]
    DIRECTION OUTPUT ;
    USE SIGNAL ;
    PORT
      LAYER M4 ;
        RECT  0 39.264 0.192 39.288 ;
    END
  END b[489]
  PIN b[48]
    DIRECTION OUTPUT ;
    USE SIGNAL ;
    PORT
      LAYER M4 ;
        RECT  0 18.096 0.192 18.12 ;
    END
  END b[48]
  PIN b[490]
    DIRECTION OUTPUT ;
    USE SIGNAL ;
    PORT
      LAYER M4 ;
        RECT  0 39.312 0.192 39.336 ;
    END
  END b[490]
  PIN b[491]
    DIRECTION OUTPUT ;
    USE SIGNAL ;
    PORT
      LAYER M4 ;
        RECT  0 39.36 0.192 39.384 ;
    END
  END b[491]
  PIN b[492]
    DIRECTION OUTPUT ;
    USE SIGNAL ;
    PORT
      LAYER M4 ;
        RECT  0 39.408 0.192 39.432 ;
    END
  END b[492]
  PIN b[493]
    DIRECTION OUTPUT ;
    USE SIGNAL ;
    PORT
      LAYER M4 ;
        RECT  0 39.456 0.192 39.48 ;
    END
  END b[493]
  PIN b[494]
    DIRECTION OUTPUT ;
    USE SIGNAL ;
    PORT
      LAYER M4 ;
        RECT  0 39.504 0.192 39.528 ;
    END
  END b[494]
  PIN b[495]
    DIRECTION OUTPUT ;
    USE SIGNAL ;
    PORT
      LAYER M4 ;
        RECT  0 39.552 0.192 39.576 ;
    END
  END b[495]
  PIN b[496]
    DIRECTION OUTPUT ;
    USE SIGNAL ;
    PORT
      LAYER M4 ;
        RECT  0 39.6 0.192 39.624 ;
    END
  END b[496]
  PIN b[497]
    DIRECTION OUTPUT ;
    USE SIGNAL ;
    PORT
      LAYER M4 ;
        RECT  0 39.648 0.192 39.672 ;
    END
  END b[497]
  PIN b[498]
    DIRECTION OUTPUT ;
    USE SIGNAL ;
    PORT
      LAYER M4 ;
        RECT  0 39.696 0.192 39.72 ;
    END
  END b[498]
  PIN b[499]
    DIRECTION OUTPUT ;
    USE SIGNAL ;
    PORT
      LAYER M4 ;
        RECT  0 39.744 0.192 39.768 ;
    END
  END b[499]
  PIN b[49]
    DIRECTION OUTPUT ;
    USE SIGNAL ;
    PORT
      LAYER M4 ;
        RECT  0 18.144 0.192 18.168 ;
    END
  END b[49]
  PIN b[4]
    DIRECTION OUTPUT ;
    USE SIGNAL ;
    PORT
      LAYER M4 ;
        RECT  0 15.984 0.192 16.008 ;
    END
  END b[4]
  PIN b[500]
    DIRECTION OUTPUT ;
    USE SIGNAL ;
    PORT
      LAYER M4 ;
        RECT  0 39.792 0.192 39.816 ;
    END
  END b[500]
  PIN b[501]
    DIRECTION OUTPUT ;
    USE SIGNAL ;
    PORT
      LAYER M4 ;
        RECT  0 39.84 0.192 39.864 ;
    END
  END b[501]
  PIN b[502]
    DIRECTION OUTPUT ;
    USE SIGNAL ;
    PORT
      LAYER M4 ;
        RECT  0 39.888 0.192 39.912 ;
    END
  END b[502]
  PIN b[503]
    DIRECTION OUTPUT ;
    USE SIGNAL ;
    PORT
      LAYER M4 ;
        RECT  0 39.936 0.192 39.96 ;
    END
  END b[503]
  PIN b[504]
    DIRECTION OUTPUT ;
    USE SIGNAL ;
    PORT
      LAYER M4 ;
        RECT  0 39.984 0.192 40.008 ;
    END
  END b[504]
  PIN b[505]
    DIRECTION OUTPUT ;
    USE SIGNAL ;
    PORT
      LAYER M4 ;
        RECT  0 40.032 0.192 40.056 ;
    END
  END b[505]
  PIN b[506]
    DIRECTION OUTPUT ;
    USE SIGNAL ;
    PORT
      LAYER M4 ;
        RECT  0 40.08 0.192 40.104 ;
    END
  END b[506]
  PIN b[507]
    DIRECTION OUTPUT ;
    USE SIGNAL ;
    PORT
      LAYER M4 ;
        RECT  0 40.128 0.192 40.152 ;
    END
  END b[507]
  PIN b[508]
    DIRECTION OUTPUT ;
    USE SIGNAL ;
    PORT
      LAYER M4 ;
        RECT  0 40.176 0.192 40.2 ;
    END
  END b[508]
  PIN b[509]
    DIRECTION OUTPUT ;
    USE SIGNAL ;
    PORT
      LAYER M4 ;
        RECT  0 40.224 0.192 40.248 ;
    END
  END b[509]
  PIN b[50]
    DIRECTION OUTPUT ;
    USE SIGNAL ;
    PORT
      LAYER M4 ;
        RECT  0 18.192 0.192 18.216 ;
    END
  END b[50]
  PIN b[510]
    DIRECTION OUTPUT ;
    USE SIGNAL ;
    PORT
      LAYER M4 ;
        RECT  0 40.272 0.192 40.296 ;
    END
  END b[510]
  PIN b[511]
    DIRECTION OUTPUT ;
    USE SIGNAL ;
    PORT
      LAYER M4 ;
        RECT  0 40.32 0.192 40.344 ;
    END
  END b[511]
  PIN b[512]
    DIRECTION OUTPUT ;
    USE SIGNAL ;
    PORT
      LAYER M4 ;
        RECT  0 40.368 0.192 40.392 ;
    END
  END b[512]
  PIN b[51]
    DIRECTION OUTPUT ;
    USE SIGNAL ;
    PORT
      LAYER M4 ;
        RECT  0 18.24 0.192 18.264 ;
    END
  END b[51]
  PIN b[52]
    DIRECTION OUTPUT ;
    USE SIGNAL ;
    PORT
      LAYER M4 ;
        RECT  0 18.288 0.192 18.312 ;
    END
  END b[52]
  PIN b[53]
    DIRECTION OUTPUT ;
    USE SIGNAL ;
    PORT
      LAYER M4 ;
        RECT  0 18.336 0.192 18.36 ;
    END
  END b[53]
  PIN b[54]
    DIRECTION OUTPUT ;
    USE SIGNAL ;
    PORT
      LAYER M4 ;
        RECT  0 18.384 0.192 18.408 ;
    END
  END b[54]
  PIN b[55]
    DIRECTION OUTPUT ;
    USE SIGNAL ;
    PORT
      LAYER M4 ;
        RECT  0 18.432 0.192 18.456 ;
    END
  END b[55]
  PIN b[56]
    DIRECTION OUTPUT ;
    USE SIGNAL ;
    PORT
      LAYER M4 ;
        RECT  0 18.48 0.192 18.504 ;
    END
  END b[56]
  PIN b[57]
    DIRECTION OUTPUT ;
    USE SIGNAL ;
    PORT
      LAYER M4 ;
        RECT  0 18.528 0.192 18.552 ;
    END
  END b[57]
  PIN b[58]
    DIRECTION OUTPUT ;
    USE SIGNAL ;
    PORT
      LAYER M4 ;
        RECT  0 18.576 0.192 18.6 ;
    END
  END b[58]
  PIN b[59]
    DIRECTION OUTPUT ;
    USE SIGNAL ;
    PORT
      LAYER M4 ;
        RECT  0 18.624 0.192 18.648 ;
    END
  END b[59]
  PIN b[5]
    DIRECTION OUTPUT ;
    USE SIGNAL ;
    PORT
      LAYER M4 ;
        RECT  0 16.032 0.192 16.056 ;
    END
  END b[5]
  PIN b[60]
    DIRECTION OUTPUT ;
    USE SIGNAL ;
    PORT
      LAYER M4 ;
        RECT  0 18.672 0.192 18.696 ;
    END
  END b[60]
  PIN b[61]
    DIRECTION OUTPUT ;
    USE SIGNAL ;
    PORT
      LAYER M4 ;
        RECT  0 18.72 0.192 18.744 ;
    END
  END b[61]
  PIN b[62]
    DIRECTION OUTPUT ;
    USE SIGNAL ;
    PORT
      LAYER M4 ;
        RECT  0 18.768 0.192 18.792 ;
    END
  END b[62]
  PIN b[63]
    DIRECTION OUTPUT ;
    USE SIGNAL ;
    PORT
      LAYER M4 ;
        RECT  0 18.816 0.192 18.84 ;
    END
  END b[63]
  PIN b[64]
    DIRECTION OUTPUT ;
    USE SIGNAL ;
    PORT
      LAYER M4 ;
        RECT  0 18.864 0.192 18.888 ;
    END
  END b[64]
  PIN b[65]
    DIRECTION OUTPUT ;
    USE SIGNAL ;
    PORT
      LAYER M4 ;
        RECT  0 18.912 0.192 18.936 ;
    END
  END b[65]
  PIN b[66]
    DIRECTION OUTPUT ;
    USE SIGNAL ;
    PORT
      LAYER M4 ;
        RECT  0 18.96 0.192 18.984 ;
    END
  END b[66]
  PIN b[67]
    DIRECTION OUTPUT ;
    USE SIGNAL ;
    PORT
      LAYER M4 ;
        RECT  0 19.008 0.192 19.032 ;
    END
  END b[67]
  PIN b[68]
    DIRECTION OUTPUT ;
    USE SIGNAL ;
    PORT
      LAYER M4 ;
        RECT  0 19.056 0.192 19.08 ;
    END
  END b[68]
  PIN b[69]
    DIRECTION OUTPUT ;
    USE SIGNAL ;
    PORT
      LAYER M4 ;
        RECT  0 19.104 0.192 19.128 ;
    END
  END b[69]
  PIN b[6]
    DIRECTION OUTPUT ;
    USE SIGNAL ;
    PORT
      LAYER M4 ;
        RECT  0 16.08 0.192 16.104 ;
    END
  END b[6]
  PIN b[70]
    DIRECTION OUTPUT ;
    USE SIGNAL ;
    PORT
      LAYER M4 ;
        RECT  0 19.152 0.192 19.176 ;
    END
  END b[70]
  PIN b[71]
    DIRECTION OUTPUT ;
    USE SIGNAL ;
    PORT
      LAYER M4 ;
        RECT  0 19.2 0.192 19.224 ;
    END
  END b[71]
  PIN b[72]
    DIRECTION OUTPUT ;
    USE SIGNAL ;
    PORT
      LAYER M4 ;
        RECT  0 19.248 0.192 19.272 ;
    END
  END b[72]
  PIN b[73]
    DIRECTION OUTPUT ;
    USE SIGNAL ;
    PORT
      LAYER M4 ;
        RECT  0 19.296 0.192 19.32 ;
    END
  END b[73]
  PIN b[74]
    DIRECTION OUTPUT ;
    USE SIGNAL ;
    PORT
      LAYER M4 ;
        RECT  0 19.344 0.192 19.368 ;
    END
  END b[74]
  PIN b[75]
    DIRECTION OUTPUT ;
    USE SIGNAL ;
    PORT
      LAYER M4 ;
        RECT  0 19.392 0.192 19.416 ;
    END
  END b[75]
  PIN b[76]
    DIRECTION OUTPUT ;
    USE SIGNAL ;
    PORT
      LAYER M4 ;
        RECT  0 19.44 0.192 19.464 ;
    END
  END b[76]
  PIN b[77]
    DIRECTION OUTPUT ;
    USE SIGNAL ;
    PORT
      LAYER M4 ;
        RECT  0 19.488 0.192 19.512 ;
    END
  END b[77]
  PIN b[78]
    DIRECTION OUTPUT ;
    USE SIGNAL ;
    PORT
      LAYER M4 ;
        RECT  0 19.536 0.192 19.56 ;
    END
  END b[78]
  PIN b[79]
    DIRECTION OUTPUT ;
    USE SIGNAL ;
    PORT
      LAYER M4 ;
        RECT  0 19.584 0.192 19.608 ;
    END
  END b[79]
  PIN b[7]
    DIRECTION OUTPUT ;
    USE SIGNAL ;
    PORT
      LAYER M4 ;
        RECT  0 16.128 0.192 16.152 ;
    END
  END b[7]
  PIN b[80]
    DIRECTION OUTPUT ;
    USE SIGNAL ;
    PORT
      LAYER M4 ;
        RECT  0 19.632 0.192 19.656 ;
    END
  END b[80]
  PIN b[81]
    DIRECTION OUTPUT ;
    USE SIGNAL ;
    PORT
      LAYER M4 ;
        RECT  0 19.68 0.192 19.704 ;
    END
  END b[81]
  PIN b[82]
    DIRECTION OUTPUT ;
    USE SIGNAL ;
    PORT
      LAYER M4 ;
        RECT  0 19.728 0.192 19.752 ;
    END
  END b[82]
  PIN b[83]
    DIRECTION OUTPUT ;
    USE SIGNAL ;
    PORT
      LAYER M4 ;
        RECT  0 19.776 0.192 19.8 ;
    END
  END b[83]
  PIN b[84]
    DIRECTION OUTPUT ;
    USE SIGNAL ;
    PORT
      LAYER M4 ;
        RECT  0 19.824 0.192 19.848 ;
    END
  END b[84]
  PIN b[85]
    DIRECTION OUTPUT ;
    USE SIGNAL ;
    PORT
      LAYER M4 ;
        RECT  0 19.872 0.192 19.896 ;
    END
  END b[85]
  PIN b[86]
    DIRECTION OUTPUT ;
    USE SIGNAL ;
    PORT
      LAYER M4 ;
        RECT  0 19.92 0.192 19.944 ;
    END
  END b[86]
  PIN b[87]
    DIRECTION OUTPUT ;
    USE SIGNAL ;
    PORT
      LAYER M4 ;
        RECT  0 19.968 0.192 19.992 ;
    END
  END b[87]
  PIN b[88]
    DIRECTION OUTPUT ;
    USE SIGNAL ;
    PORT
      LAYER M4 ;
        RECT  0 20.016 0.192 20.04 ;
    END
  END b[88]
  PIN b[89]
    DIRECTION OUTPUT ;
    USE SIGNAL ;
    PORT
      LAYER M4 ;
        RECT  0 20.064 0.192 20.088 ;
    END
  END b[89]
  PIN b[8]
    DIRECTION OUTPUT ;
    USE SIGNAL ;
    PORT
      LAYER M4 ;
        RECT  0 16.176 0.192 16.2 ;
    END
  END b[8]
  PIN b[90]
    DIRECTION OUTPUT ;
    USE SIGNAL ;
    PORT
      LAYER M4 ;
        RECT  0 20.112 0.192 20.136 ;
    END
  END b[90]
  PIN b[91]
    DIRECTION OUTPUT ;
    USE SIGNAL ;
    PORT
      LAYER M4 ;
        RECT  0 20.16 0.192 20.184 ;
    END
  END b[91]
  PIN b[92]
    DIRECTION OUTPUT ;
    USE SIGNAL ;
    PORT
      LAYER M4 ;
        RECT  0 20.208 0.192 20.232 ;
    END
  END b[92]
  PIN b[93]
    DIRECTION OUTPUT ;
    USE SIGNAL ;
    PORT
      LAYER M4 ;
        RECT  0 20.256 0.192 20.28 ;
    END
  END b[93]
  PIN b[94]
    DIRECTION OUTPUT ;
    USE SIGNAL ;
    PORT
      LAYER M4 ;
        RECT  0 20.304 0.192 20.328 ;
    END
  END b[94]
  PIN b[95]
    DIRECTION OUTPUT ;
    USE SIGNAL ;
    PORT
      LAYER M4 ;
        RECT  0 20.352 0.192 20.376 ;
    END
  END b[95]
  PIN b[96]
    DIRECTION OUTPUT ;
    USE SIGNAL ;
    PORT
      LAYER M4 ;
        RECT  0 20.4 0.192 20.424 ;
    END
  END b[96]
  PIN b[97]
    DIRECTION OUTPUT ;
    USE SIGNAL ;
    PORT
      LAYER M4 ;
        RECT  0 20.448 0.192 20.472 ;
    END
  END b[97]
  PIN b[98]
    DIRECTION OUTPUT ;
    USE SIGNAL ;
    PORT
      LAYER M4 ;
        RECT  0 20.496 0.192 20.52 ;
    END
  END b[98]
  PIN b[99]
    DIRECTION OUTPUT ;
    USE SIGNAL ;
    PORT
      LAYER M4 ;
        RECT  0 20.544 0.192 20.568 ;
    END
  END b[99]
  PIN b[9]
    DIRECTION OUTPUT ;
    USE SIGNAL ;
    PORT
      LAYER M4 ;
        RECT  0 16.224 0.192 16.248 ;
    END
  END b[9]
  PIN rst[0]
    DIRECTION INPUT ;
    USE SIGNAL ;
    PORT
      LAYER M4 ;
        RECT  0 15.552 0.192 15.576 ;
    END
  END rst[0]
  PIN VDD
    DIRECTION INOUT ;
    USE POWER ;
    PORT
      LAYER M7 ;
        RECT  71.056 0.531 71.344 40.239 ;
        RECT  60.256 0.531 60.544 40.239 ;
        RECT  49.456 0.531 49.744 40.239 ;
        RECT  38.656 0.531 38.944 40.239 ;
        RECT  27.856 0.531 28.144 40.239 ;
        RECT  17.056 0.531 17.344 40.239 ;
        RECT  6.256 0.531 6.544 40.239 ;
      LAYER M6 ;
        RECT  0 39.372 0.032 39.66 ;
        RECT  0 33.972 0.032 34.26 ;
        RECT  0 28.572 0.032 28.86 ;
        RECT  0 23.172 0.032 23.46 ;
        RECT  0 17.772 0.032 18.06 ;
        RECT  0 12.372 0.032 12.66 ;
        RECT  0 6.972 0.032 7.26 ;
        RECT  0 1.572 0.032 1.86 ;
      LAYER M2 ;
        RECT  0 40.221 0.018 40.239 ;
        RECT  0 39.681 0.018 39.699 ;
        RECT  0 39.141 0.018 39.159 ;
        RECT  0 38.601 0.018 38.619 ;
        RECT  0 38.061 0.018 38.079 ;
        RECT  0 37.521 0.018 37.539 ;
        RECT  0 36.981 0.018 36.999 ;
        RECT  0 36.441 0.018 36.459 ;
        RECT  0 35.901 0.018 35.919 ;
        RECT  0 35.361 0.018 35.379 ;
        RECT  0 34.821 0.018 34.839 ;
        RECT  0 34.281 0.018 34.299 ;
        RECT  0 33.741 0.018 33.759 ;
        RECT  0 33.201 0.018 33.219 ;
        RECT  0 32.661 0.018 32.679 ;
        RECT  0 32.121 0.018 32.139 ;
        RECT  0 31.581 0.018 31.599 ;
        RECT  0 31.041 0.018 31.059 ;
        RECT  0 30.501 0.018 30.519 ;
        RECT  0 29.961 0.018 29.979 ;
        RECT  0 29.421 0.018 29.439 ;
        RECT  0 28.881 0.018 28.899 ;
        RECT  0 28.341 0.018 28.359 ;
        RECT  0 27.801 0.018 27.819 ;
        RECT  0 27.261 0.018 27.279 ;
        RECT  0 26.721 0.018 26.739 ;
        RECT  0 26.181 0.018 26.199 ;
        RECT  0 25.641 0.018 25.659 ;
        RECT  0 25.101 0.018 25.119 ;
        RECT  0 24.561 0.018 24.579 ;
        RECT  0 24.021 0.018 24.039 ;
        RECT  0 23.481 0.018 23.499 ;
        RECT  0 22.941 0.018 22.959 ;
        RECT  0 22.401 0.018 22.419 ;
        RECT  0 21.861 0.018 21.879 ;
        RECT  0 21.321 0.018 21.339 ;
        RECT  0 20.781 0.018 20.799 ;
        RECT  0 20.241 0.018 20.259 ;
        RECT  0 19.701 0.018 19.719 ;
        RECT  0 19.161 0.018 19.179 ;
        RECT  0 18.621 0.018 18.639 ;
        RECT  0 18.081 0.018 18.099 ;
        RECT  0 17.541 0.018 17.559 ;
        RECT  0 17.001 0.018 17.019 ;
        RECT  0 16.461 0.018 16.479 ;
        RECT  0 15.921 0.018 15.939 ;
        RECT  0 15.381 0.018 15.399 ;
        RECT  0 14.841 0.018 14.859 ;
        RECT  0 14.301 0.018 14.319 ;
        RECT  0 13.761 0.018 13.779 ;
        RECT  0 13.221 0.018 13.239 ;
        RECT  0 12.681 0.018 12.699 ;
        RECT  0 12.141 0.018 12.159 ;
        RECT  0 11.601 0.018 11.619 ;
        RECT  0 11.061 0.018 11.079 ;
        RECT  0 10.521 0.018 10.539 ;
        RECT  0 9.981 0.018 9.999 ;
        RECT  0 9.441 0.018 9.459 ;
        RECT  0 8.901 0.018 8.919 ;
        RECT  0 8.361 0.018 8.379 ;
        RECT  0 7.821 0.018 7.839 ;
        RECT  0 7.281 0.018 7.299 ;
        RECT  0 6.741 0.018 6.759 ;
        RECT  0 6.201 0.018 6.219 ;
        RECT  0 5.661 0.018 5.679 ;
        RECT  0 5.121 0.018 5.139 ;
        RECT  0 4.581 0.018 4.599 ;
        RECT  0 4.041 0.018 4.059 ;
        RECT  0 3.501 0.018 3.519 ;
        RECT  0 2.961 0.018 2.979 ;
        RECT  0 2.421 0.018 2.439 ;
        RECT  0 1.881 0.018 1.899 ;
        RECT  0 1.341 0.018 1.359 ;
        RECT  0 0.801 0.018 0.819 ;
      LAYER M1 ;
        RECT  0 40.221 0.018 40.239 ;
        RECT  0 39.681 0.018 39.699 ;
        RECT  0 39.141 0.018 39.159 ;
        RECT  0 38.601 0.018 38.619 ;
        RECT  0 38.061 0.018 38.079 ;
        RECT  0 37.521 0.018 37.539 ;
        RECT  0 36.981 0.018 36.999 ;
        RECT  0 36.441 0.018 36.459 ;
        RECT  0 35.901 0.018 35.919 ;
        RECT  0 35.361 0.018 35.379 ;
        RECT  0 34.821 0.018 34.839 ;
        RECT  0 34.281 0.018 34.299 ;
        RECT  0 33.741 0.018 33.759 ;
        RECT  0 33.201 0.018 33.219 ;
        RECT  0 32.661 0.018 32.679 ;
        RECT  0 32.121 0.018 32.139 ;
        RECT  0 31.581 0.018 31.599 ;
        RECT  0 31.041 0.018 31.059 ;
        RECT  0 30.501 0.018 30.519 ;
        RECT  0 29.961 0.018 29.979 ;
        RECT  0 29.421 0.018 29.439 ;
        RECT  0 28.881 0.018 28.899 ;
        RECT  0 28.341 0.018 28.359 ;
        RECT  0 27.801 0.018 27.819 ;
        RECT  0 27.261 0.018 27.279 ;
        RECT  0 26.721 0.018 26.739 ;
        RECT  0 26.181 0.018 26.199 ;
        RECT  0 25.641 0.018 25.659 ;
        RECT  0 25.101 0.018 25.119 ;
        RECT  0 24.561 0.018 24.579 ;
        RECT  0 24.021 0.018 24.039 ;
        RECT  0 23.481 0.018 23.499 ;
        RECT  0 22.941 0.018 22.959 ;
        RECT  0 22.401 0.018 22.419 ;
        RECT  0 21.861 0.018 21.879 ;
        RECT  0 21.321 0.018 21.339 ;
        RECT  0 20.781 0.018 20.799 ;
        RECT  0 20.241 0.018 20.259 ;
        RECT  0 19.701 0.018 19.719 ;
        RECT  0 19.161 0.018 19.179 ;
        RECT  0 18.621 0.018 18.639 ;
        RECT  0 18.081 0.018 18.099 ;
        RECT  0 17.541 0.018 17.559 ;
        RECT  0 17.001 0.018 17.019 ;
        RECT  0 16.461 0.018 16.479 ;
        RECT  0 15.921 0.018 15.939 ;
        RECT  0 15.381 0.018 15.399 ;
        RECT  0 14.841 0.018 14.859 ;
        RECT  0 14.301 0.018 14.319 ;
        RECT  0 13.761 0.018 13.779 ;
        RECT  0 13.221 0.018 13.239 ;
        RECT  0 12.681 0.018 12.699 ;
        RECT  0 12.141 0.018 12.159 ;
        RECT  0 11.601 0.018 11.619 ;
        RECT  0 11.061 0.018 11.079 ;
        RECT  0 10.521 0.018 10.539 ;
        RECT  0 9.981 0.018 9.999 ;
        RECT  0 9.441 0.018 9.459 ;
        RECT  0 8.901 0.018 8.919 ;
        RECT  0 8.361 0.018 8.379 ;
        RECT  0 7.821 0.018 7.839 ;
        RECT  0 7.281 0.018 7.299 ;
        RECT  0 6.741 0.018 6.759 ;
        RECT  0 6.201 0.018 6.219 ;
        RECT  0 5.661 0.018 5.679 ;
        RECT  0 5.121 0.018 5.139 ;
        RECT  0 4.581 0.018 4.599 ;
        RECT  0 4.041 0.018 4.059 ;
        RECT  0 3.501 0.018 3.519 ;
        RECT  0 2.961 0.018 2.979 ;
        RECT  0 2.421 0.018 2.439 ;
        RECT  0 1.881 0.018 1.899 ;
        RECT  0 1.341 0.018 1.359 ;
        RECT  0 0.801 0.018 0.819 ;
    END
  END VDD
  PIN VSS
    DIRECTION INOUT ;
    USE GROUND ;
    PORT
      LAYER M7 ;
        RECT  65.656 0.531 65.944 40.239 ;
        RECT  54.856 0.531 55.144 40.239 ;
        RECT  44.056 0.531 44.344 40.239 ;
        RECT  33.256 0.531 33.544 40.239 ;
        RECT  22.456 0.531 22.744 40.239 ;
        RECT  11.656 0.531 11.944 40.239 ;
        RECT  0.856 0.531 1.144 40.239 ;
      LAYER M6 ;
        RECT  0 38.796 0.032 39.084 ;
        RECT  0 33.396 0.032 33.684 ;
        RECT  0 27.996 0.032 28.284 ;
        RECT  0 22.596 0.032 22.884 ;
        RECT  0 17.196 0.032 17.484 ;
        RECT  0 11.796 0.032 12.084 ;
        RECT  0 6.396 0.032 6.684 ;
        RECT  0 0.996 0.032 1.284 ;
      LAYER M2 ;
        RECT  0 39.951 0.018 39.969 ;
        RECT  0 39.411 0.018 39.429 ;
        RECT  0 38.871 0.018 38.889 ;
        RECT  0 38.331 0.018 38.349 ;
        RECT  0 37.791 0.018 37.809 ;
        RECT  0 37.251 0.018 37.269 ;
        RECT  0 36.711 0.018 36.729 ;
        RECT  0 36.171 0.018 36.189 ;
        RECT  0 35.631 0.018 35.649 ;
        RECT  0 35.091 0.018 35.109 ;
        RECT  0 34.551 0.018 34.569 ;
        RECT  0 34.011 0.018 34.029 ;
        RECT  0 33.471 0.018 33.489 ;
        RECT  0 32.931 0.018 32.949 ;
        RECT  0 32.391 0.018 32.409 ;
        RECT  0 31.851 0.018 31.869 ;
        RECT  0 31.311 0.018 31.329 ;
        RECT  0 30.771 0.018 30.789 ;
        RECT  0 30.231 0.018 30.249 ;
        RECT  0 29.691 0.018 29.709 ;
        RECT  0 29.151 0.018 29.169 ;
        RECT  0 28.611 0.018 28.629 ;
        RECT  0 28.071 0.018 28.089 ;
        RECT  0 27.531 0.018 27.549 ;
        RECT  0 26.991 0.018 27.009 ;
        RECT  0 26.451 0.018 26.469 ;
        RECT  0 25.911 0.018 25.929 ;
        RECT  0 25.371 0.018 25.389 ;
        RECT  0 24.831 0.018 24.849 ;
        RECT  0 24.291 0.018 24.309 ;
        RECT  0 23.751 0.018 23.769 ;
        RECT  0 23.211 0.018 23.229 ;
        RECT  0 22.671 0.018 22.689 ;
        RECT  0 22.131 0.018 22.149 ;
        RECT  0 21.591 0.018 21.609 ;
        RECT  0 21.051 0.018 21.069 ;
        RECT  0 20.511 0.018 20.529 ;
        RECT  0 19.971 0.018 19.989 ;
        RECT  0 19.431 0.018 19.449 ;
        RECT  0 18.891 0.018 18.909 ;
        RECT  0 18.351 0.018 18.369 ;
        RECT  0 17.811 0.018 17.829 ;
        RECT  0 17.271 0.018 17.289 ;
        RECT  0 16.731 0.018 16.749 ;
        RECT  0 16.191 0.018 16.209 ;
        RECT  0 15.651 0.018 15.669 ;
        RECT  0 15.111 0.018 15.129 ;
        RECT  0 14.571 0.018 14.589 ;
        RECT  0 14.031 0.018 14.049 ;
        RECT  0 13.491 0.018 13.509 ;
        RECT  0 12.951 0.018 12.969 ;
        RECT  0 12.411 0.018 12.429 ;
        RECT  0 11.871 0.018 11.889 ;
        RECT  0 11.331 0.018 11.349 ;
        RECT  0 10.791 0.018 10.809 ;
        RECT  0 10.251 0.018 10.269 ;
        RECT  0 9.711 0.018 9.729 ;
        RECT  0 9.171 0.018 9.189 ;
        RECT  0 8.631 0.018 8.649 ;
        RECT  0 8.091 0.018 8.109 ;
        RECT  0 7.551 0.018 7.569 ;
        RECT  0 7.011 0.018 7.029 ;
        RECT  0 6.471 0.018 6.489 ;
        RECT  0 5.931 0.018 5.949 ;
        RECT  0 5.391 0.018 5.409 ;
        RECT  0 4.851 0.018 4.869 ;
        RECT  0 4.311 0.018 4.329 ;
        RECT  0 3.771 0.018 3.789 ;
        RECT  0 3.231 0.018 3.249 ;
        RECT  0 2.691 0.018 2.709 ;
        RECT  0 2.151 0.018 2.169 ;
        RECT  0 1.611 0.018 1.629 ;
        RECT  0 1.071 0.018 1.089 ;
        RECT  0 0.531 0.018 0.549 ;
      LAYER M1 ;
        RECT  0 39.951 0.018 39.969 ;
        RECT  0 39.411 0.018 39.429 ;
        RECT  0 38.871 0.018 38.889 ;
        RECT  0 38.331 0.018 38.349 ;
        RECT  0 37.791 0.018 37.809 ;
        RECT  0 37.251 0.018 37.269 ;
        RECT  0 36.711 0.018 36.729 ;
        RECT  0 36.171 0.018 36.189 ;
        RECT  0 35.631 0.018 35.649 ;
        RECT  0 35.091 0.018 35.109 ;
        RECT  0 34.551 0.018 34.569 ;
        RECT  0 34.011 0.018 34.029 ;
        RECT  0 33.471 0.018 33.489 ;
        RECT  0 32.931 0.018 32.949 ;
        RECT  0 32.391 0.018 32.409 ;
        RECT  0 31.851 0.018 31.869 ;
        RECT  0 31.311 0.018 31.329 ;
        RECT  0 30.771 0.018 30.789 ;
        RECT  0 30.231 0.018 30.249 ;
        RECT  0 29.691 0.018 29.709 ;
        RECT  0 29.151 0.018 29.169 ;
        RECT  0 28.611 0.018 28.629 ;
        RECT  0 28.071 0.018 28.089 ;
        RECT  0 27.531 0.018 27.549 ;
        RECT  0 26.991 0.018 27.009 ;
        RECT  0 26.451 0.018 26.469 ;
        RECT  0 25.911 0.018 25.929 ;
        RECT  0 25.371 0.018 25.389 ;
        RECT  0 24.831 0.018 24.849 ;
        RECT  0 24.291 0.018 24.309 ;
        RECT  0 23.751 0.018 23.769 ;
        RECT  0 23.211 0.018 23.229 ;
        RECT  0 22.671 0.018 22.689 ;
        RECT  0 22.131 0.018 22.149 ;
        RECT  0 21.591 0.018 21.609 ;
        RECT  0 21.051 0.018 21.069 ;
        RECT  0 20.511 0.018 20.529 ;
        RECT  0 19.971 0.018 19.989 ;
        RECT  0 19.431 0.018 19.449 ;
        RECT  0 18.891 0.018 18.909 ;
        RECT  0 18.351 0.018 18.369 ;
        RECT  0 17.811 0.018 17.829 ;
        RECT  0 17.271 0.018 17.289 ;
        RECT  0 16.731 0.018 16.749 ;
        RECT  0 16.191 0.018 16.209 ;
        RECT  0 15.651 0.018 15.669 ;
        RECT  0 15.111 0.018 15.129 ;
        RECT  0 14.571 0.018 14.589 ;
        RECT  0 14.031 0.018 14.049 ;
        RECT  0 13.491 0.018 13.509 ;
        RECT  0 12.951 0.018 12.969 ;
        RECT  0 12.411 0.018 12.429 ;
        RECT  0 11.871 0.018 11.889 ;
        RECT  0 11.331 0.018 11.349 ;
        RECT  0 10.791 0.018 10.809 ;
        RECT  0 10.251 0.018 10.269 ;
        RECT  0 9.711 0.018 9.729 ;
        RECT  0 9.171 0.018 9.189 ;
        RECT  0 8.631 0.018 8.649 ;
        RECT  0 8.091 0.018 8.109 ;
        RECT  0 7.551 0.018 7.569 ;
        RECT  0 7.011 0.018 7.029 ;
        RECT  0 6.471 0.018 6.489 ;
        RECT  0 5.931 0.018 5.949 ;
        RECT  0 5.391 0.018 5.409 ;
        RECT  0 4.851 0.018 4.869 ;
        RECT  0 4.311 0.018 4.329 ;
        RECT  0 3.771 0.018 3.789 ;
        RECT  0 3.231 0.018 3.249 ;
        RECT  0 2.691 0.018 2.709 ;
        RECT  0 2.151 0.018 2.169 ;
        RECT  0 1.611 0.018 1.629 ;
        RECT  0 1.071 0.018 1.089 ;
        RECT  0 0.531 0.018 0.549 ;
    END
  END VSS
  OBS
    LAYER RVTN ;
     RECT  0 0.54 72.954 0.675 ;
     RECT  0 0.945 72.954 1.215 ;
     RECT  0 1.485 72.954 1.755 ;
     RECT  0 2.025 72.954 2.295 ;
     RECT  0 2.565 72.954 2.835 ;
     RECT  0 3.105 72.954 3.375 ;
     RECT  0 3.645 72.954 3.915 ;
     RECT  0 4.185 72.954 4.455 ;
     RECT  0 4.725 72.954 4.995 ;
     RECT  0 5.265 72.954 5.535 ;
     RECT  0 5.805 72.954 6.075 ;
     RECT  0 6.345 72.954 6.615 ;
     RECT  0 6.885 72.954 7.155 ;
     RECT  0 7.425 72.954 7.695 ;
     RECT  0 7.965 72.954 8.235 ;
     RECT  0 8.505 72.954 8.775 ;
     RECT  0 9.045 72.954 9.315 ;
     RECT  0 9.585 72.954 9.855 ;
     RECT  0 10.125 72.954 10.395 ;
     RECT  0 10.665 72.954 10.935 ;
     RECT  0 11.205 72.954 11.475 ;
     RECT  0 11.745 72.954 12.015 ;
     RECT  0 12.285 72.954 12.555 ;
     RECT  0 12.825 72.954 13.095 ;
     RECT  0 13.365 72.954 13.635 ;
     RECT  0 13.905 72.954 14.175 ;
     RECT  0 14.445 72.954 14.715 ;
     RECT  0 14.985 72.954 15.255 ;
     RECT  0 15.525 72.954 15.795 ;
     RECT  0 16.065 72.954 16.335 ;
     RECT  0 16.605 72.954 16.875 ;
     RECT  0 17.145 72.954 17.415 ;
     RECT  0 17.685 72.954 17.955 ;
     RECT  0 18.225 72.954 18.495 ;
     RECT  0 18.765 72.954 19.035 ;
     RECT  0 19.305 72.954 19.575 ;
     RECT  0 19.845 72.954 20.115 ;
     RECT  0 20.385 72.954 20.655 ;
     RECT  0 20.925 72.954 21.195 ;
     RECT  0 21.465 72.954 21.735 ;
     RECT  0 22.005 72.954 22.275 ;
     RECT  0 22.545 72.954 22.815 ;
     RECT  0 23.085 72.954 23.355 ;
     RECT  0 23.625 72.954 23.895 ;
     RECT  0 24.165 72.954 24.435 ;
     RECT  0 24.705 72.954 24.975 ;
     RECT  0 25.245 72.954 25.515 ;
     RECT  0 25.785 72.954 26.055 ;
     RECT  0 26.325 72.954 26.595 ;
     RECT  0 26.865 72.954 27.135 ;
     RECT  0 27.405 72.954 27.675 ;
     RECT  0 27.945 72.954 28.215 ;
     RECT  0 28.485 72.954 28.755 ;
     RECT  0 29.025 72.954 29.295 ;
     RECT  0 29.565 72.954 29.835 ;
     RECT  0 30.105 72.954 30.375 ;
     RECT  0 30.645 72.954 30.915 ;
     RECT  0 31.185 72.954 31.455 ;
     RECT  0 31.725 72.954 31.995 ;
     RECT  0 32.265 72.954 32.535 ;
     RECT  0 32.805 72.954 33.075 ;
     RECT  0 33.345 72.954 33.615 ;
     RECT  0 33.885 72.954 34.155 ;
     RECT  0 34.425 72.954 34.695 ;
     RECT  0 34.965 72.954 35.235 ;
     RECT  0 35.505 72.954 35.775 ;
     RECT  0 36.045 72.954 36.315 ;
     RECT  0 36.585 72.954 36.855 ;
     RECT  0 37.125 72.954 37.395 ;
     RECT  0 37.665 72.954 37.935 ;
     RECT  0 38.205 72.954 38.475 ;
     RECT  0 38.745 72.954 39.015 ;
     RECT  0 39.285 72.954 39.555 ;
     RECT  0 39.825 72.954 40.095 ;
    LAYER RVTP ;
     RECT  0 0.675 72.954 0.945 ;
     RECT  0 1.215 72.954 1.485 ;
     RECT  0 1.755 72.954 2.025 ;
     RECT  0 2.295 72.954 2.565 ;
     RECT  0 2.835 72.954 3.105 ;
     RECT  0 3.375 72.954 3.645 ;
     RECT  0 3.915 72.954 4.185 ;
     RECT  0 4.455 72.954 4.725 ;
     RECT  0 4.995 72.954 5.265 ;
     RECT  0 5.535 72.954 5.805 ;
     RECT  0 6.075 72.954 6.345 ;
     RECT  0 6.615 72.954 6.885 ;
     RECT  0 7.155 72.954 7.425 ;
     RECT  0 7.695 72.954 7.965 ;
     RECT  0 8.235 72.954 8.505 ;
     RECT  0 8.775 72.954 9.045 ;
     RECT  0 9.315 72.954 9.585 ;
     RECT  0 9.855 72.954 10.125 ;
     RECT  0 10.395 72.954 10.665 ;
     RECT  0 10.935 72.954 11.205 ;
     RECT  0 11.475 72.954 11.745 ;
     RECT  0 12.015 72.954 12.285 ;
     RECT  0 12.555 72.954 12.825 ;
     RECT  0 13.095 72.954 13.365 ;
     RECT  0 13.635 72.954 13.905 ;
     RECT  0 14.175 72.954 14.445 ;
     RECT  0 14.715 72.954 14.985 ;
     RECT  0 15.255 72.954 15.525 ;
     RECT  0 15.795 72.954 16.065 ;
     RECT  0 16.335 72.954 16.605 ;
     RECT  0 16.875 72.954 17.145 ;
     RECT  0 17.415 72.954 17.685 ;
     RECT  0 17.955 72.954 18.225 ;
     RECT  0 18.495 72.954 18.765 ;
     RECT  0 19.035 72.954 19.305 ;
     RECT  0 19.575 72.954 19.845 ;
     RECT  0 20.115 72.954 20.385 ;
     RECT  0 20.655 72.954 20.925 ;
     RECT  0 21.195 72.954 21.465 ;
     RECT  0 21.735 72.954 22.005 ;
     RECT  0 22.275 72.954 22.545 ;
     RECT  0 22.815 72.954 23.085 ;
     RECT  0 23.355 72.954 23.625 ;
     RECT  0 23.895 72.954 24.165 ;
     RECT  0 24.435 72.954 24.705 ;
     RECT  0 24.975 72.954 25.245 ;
     RECT  0 25.515 72.954 25.785 ;
     RECT  0 26.055 72.954 26.325 ;
     RECT  0 26.595 72.954 26.865 ;
     RECT  0 27.135 72.954 27.405 ;
     RECT  0 27.675 72.954 27.945 ;
     RECT  0 28.215 72.954 28.485 ;
     RECT  0 28.755 72.954 29.025 ;
     RECT  0 29.295 72.954 29.565 ;
     RECT  0 29.835 72.954 30.105 ;
     RECT  0 30.375 72.954 30.645 ;
     RECT  0 30.915 72.954 31.185 ;
     RECT  0 31.455 72.954 31.725 ;
     RECT  0 31.995 72.954 32.265 ;
     RECT  0 32.535 72.954 32.805 ;
     RECT  0 33.075 72.954 33.345 ;
     RECT  0 33.615 72.954 33.885 ;
     RECT  0 34.155 72.954 34.425 ;
     RECT  0 34.695 72.954 34.965 ;
     RECT  0 35.235 72.954 35.505 ;
     RECT  0 35.775 72.954 36.045 ;
     RECT  0 36.315 72.954 36.585 ;
     RECT  0 36.855 72.954 37.125 ;
     RECT  0 37.395 72.954 37.665 ;
     RECT  0 37.935 72.954 38.205 ;
     RECT  0 38.475 72.954 38.745 ;
     RECT  0 39.015 72.954 39.285 ;
     RECT  0 39.555 72.954 39.825 ;
     RECT  0 40.095 72.954 40.23 ;
    LAYER M1 ;
     RECT  0 0.531 72.954 40.239 ;
    LAYER M2 ;
     RECT  0 0.531 0.319 40.239 ;
     RECT  0.319 0.531 1.283 40.284 ;
     RECT  1.283 0.531 72.954 40.239 ;
     RECT  72.954 25.056 72.959 25.074 ;
     RECT  72.954 29.034 72.959 29.052 ;
    LAYER M3 ;
     RECT  70.455 0.523 70.545 0.667 ;
     RECT  70.455 0.667 71.262 0.715 ;
     RECT  72.396 0.619 72.414 0.715 ;
     RECT  70.455 0.715 72.414 0.763 ;
     RECT  0.255 0.523 0.345 0.793 ;
     RECT  5.655 0.523 5.745 0.793 ;
     RECT  11.055 0.523 11.145 0.793 ;
     RECT  16.455 0.523 16.545 0.793 ;
     RECT  21.855 0.523 21.945 0.793 ;
     RECT  27.255 0.523 27.345 0.793 ;
     RECT  32.655 0.523 32.745 0.793 ;
     RECT  38.055 0.523 38.145 0.793 ;
     RECT  43.455 0.523 43.545 0.793 ;
     RECT  48.855 0.523 48.945 0.793 ;
     RECT  54.255 0.523 54.345 0.793 ;
     RECT  59.655 0.523 59.745 0.793 ;
     RECT  65.055 0.523 65.145 0.793 ;
     RECT  69.408 0.841 69.426 0.859 ;
     RECT  70.455 0.763 72.594 0.859 ;
     RECT  68.94 0.859 69.426 0.907 ;
     RECT  70.455 0.859 72.63 0.949 ;
     RECT  70.38 0.949 72.63 0.955 ;
     RECT  70.38 0.955 72.666 1.021 ;
     RECT  66.744 1.183 66.762 1.195 ;
     RECT  11.055 0.793 11.337 1.243 ;
     RECT  27.255 0.793 27.537 1.243 ;
     RECT  43.455 0.793 43.737 1.243 ;
     RECT  59.655 0.793 59.937 1.291 ;
     RECT  14.904 1.243 14.922 1.339 ;
     RECT  30.852 1.243 30.87 1.339 ;
     RECT  46.764 1.339 46.782 1.387 ;
     RECT  65.055 0.793 65.337 1.387 ;
     RECT  66.168 1.195 66.762 1.387 ;
     RECT  50.76 1.195 50.778 1.417 ;
     RECT  54.255 0.793 54.537 1.417 ;
     RECT  11.055 1.243 11.502 1.421 ;
     RECT  14.832 1.339 14.922 1.421 ;
     RECT  27.255 1.243 27.702 1.421 ;
     RECT  43.455 1.243 43.902 1.421 ;
     RECT  18.936 1.243 18.954 1.435 ;
     RECT  54.255 1.417 54.738 1.435 ;
     RECT  65.055 1.387 66.762 1.435 ;
     RECT  46.764 1.387 46.854 1.445 ;
     RECT  59.22 1.291 59.937 1.445 ;
     RECT  11.055 1.421 11.43 1.469 ;
     RECT  14.832 1.421 14.85 1.469 ;
     RECT  18.828 1.435 18.954 1.469 ;
     RECT  27.255 1.421 27.63 1.469 ;
     RECT  30.78 1.339 30.87 1.469 ;
     RECT  43.455 1.421 43.83 1.469 ;
     RECT  46.764 1.445 46.782 1.469 ;
     RECT  50.508 1.417 50.778 1.469 ;
     RECT  38.055 0.793 38.337 1.483 ;
     RECT  68.94 0.907 69.534 1.489 ;
     RECT  50.508 1.469 50.742 1.517 ;
     RECT  54.255 1.435 54.846 1.525 ;
     RECT  68.832 1.489 69.534 1.561 ;
     RECT  70.38 1.021 72.81 1.561 ;
     RECT  18.828 1.469 18.846 1.565 ;
     RECT  22.896 1.435 22.914 1.565 ;
     RECT  50.508 1.517 50.526 1.679 ;
     RECT  54.255 1.525 55.062 1.679 ;
     RECT  45.72 1.561 45.738 1.715 ;
     RECT  54.255 1.679 54.846 1.715 ;
     RECT  59.328 1.445 59.937 1.723 ;
     RECT  64.944 1.435 66.762 1.723 ;
     RECT  56.052 1.243 56.07 1.831 ;
     RECT  55.872 1.831 56.07 1.985 ;
     RECT  59.328 1.723 60.534 2.101 ;
     RECT  56.052 1.985 56.07 2.191 ;
     RECT  64.944 1.723 66.798 2.255 ;
     RECT  68.832 1.561 72.81 2.263 ;
     RECT  46.08 1.963 46.098 2.335 ;
     RECT  68.832 2.263 72.846 2.335 ;
     RECT  42.588 2.227 42.606 2.371 ;
     RECT  48.855 0.793 49.137 2.461 ;
     RECT  50.904 2.299 50.922 2.533 ;
     RECT  53.28 1.687 53.298 2.533 ;
     RECT  38.055 1.483 38.754 2.569 ;
     RECT  46.08 2.335 46.314 2.587 ;
     RECT  54.255 1.715 54.537 2.605 ;
     RECT  37.404 2.569 38.754 2.641 ;
     RECT  43.455 1.469 43.737 2.641 ;
     RECT  48.204 2.461 49.137 2.641 ;
     RECT  50.904 2.533 50.994 2.641 ;
     RECT  50.904 2.641 51.606 2.725 ;
     RECT  42.588 2.371 42.714 2.731 ;
     RECT  43.455 2.641 44.046 2.731 ;
     RECT  52.92 2.533 53.298 2.731 ;
     RECT  54.255 2.605 54.666 2.731 ;
     RECT  68.364 2.335 72.846 2.759 ;
     RECT  50.904 2.725 51.966 2.765 ;
     RECT  50.904 2.765 51.822 2.795 ;
     RECT  42.588 2.731 44.046 2.803 ;
     RECT  42.084 2.803 44.046 2.827 ;
     RECT  50.904 2.795 50.994 2.831 ;
     RECT  54.216 2.731 54.666 2.839 ;
     RECT  62.712 2.101 62.73 2.839 ;
     RECT  68.364 2.759 68.382 2.861 ;
     RECT  62.712 2.839 62.766 2.875 ;
     RECT  21.855 0.793 22.137 2.911 ;
     RECT  59.328 2.101 60.606 3.037 ;
     RECT  64.944 2.255 66.726 3.037 ;
     RECT  18.864 2.911 18.882 3.1 ;
     RECT  18.828 3.1 18.882 3.101 ;
     RECT  7.92 1.111 7.938 3.109 ;
     RECT  58.788 3.037 60.606 3.109 ;
     RECT  62.712 2.875 62.802 3.109 ;
     RECT  46.08 2.587 46.854 3.137 ;
     RECT  50.652 3.037 50.742 3.137 ;
     RECT  62.712 3.109 62.874 3.137 ;
     RECT  37.404 2.641 38.79 3.145 ;
     RECT  64.944 3.037 66.798 3.145 ;
     RECT  21.168 2.911 22.137 3.163 ;
     RECT  62.784 3.137 62.874 3.173 ;
     RECT  37.404 3.145 39.186 3.181 ;
     RECT  56.052 2.191 56.718 3.181 ;
     RECT  21.132 3.163 22.137 3.209 ;
     RECT  50.724 3.137 50.742 3.209 ;
     RECT  64.728 3.145 66.798 3.211 ;
     RECT  20.196 3.181 20.394 3.245 ;
     RECT  18.828 3.101 18.846 3.299 ;
     RECT  21.204 3.209 22.137 3.299 ;
     RECT  64.728 3.211 67.05 3.301 ;
     RECT  55.872 3.181 56.718 3.335 ;
     RECT  64.512 3.301 67.05 3.341 ;
     RECT  31.284 2.059 31.302 3.343 ;
     RECT  52.884 2.731 53.298 3.355 ;
     RECT  41.436 2.827 44.046 3.358 ;
     RECT  37.404 3.181 39.222 3.371 ;
     RECT  62.856 3.173 62.874 3.371 ;
     RECT  64.944 3.341 67.05 3.371 ;
     RECT  54.144 2.839 54.666 3.379 ;
     RECT  55.98 3.335 56.718 3.407 ;
     RECT  46.08 3.137 46.17 3.443 ;
     RECT  42.588 3.358 44.046 3.451 ;
     RECT  3.312 3.499 3.33 3.569 ;
     RECT  69.228 2.759 72.846 3.569 ;
     RECT  42.588 3.451 44.586 3.605 ;
     RECT  58.716 3.109 60.606 3.649 ;
     RECT  42.588 3.605 43.974 3.677 ;
     RECT  41.436 3.358 41.454 3.685 ;
     RECT  58.32 3.649 60.606 3.685 ;
     RECT  48.204 2.641 49.734 3.691 ;
     RECT  48.132 3.691 49.734 3.749 ;
     RECT  58.032 3.685 60.606 3.787 ;
     RECT  57.96 3.787 60.606 3.839 ;
     RECT  58.032 3.839 60.606 3.911 ;
     RECT  58.032 3.911 58.05 3.917 ;
     RECT  58.968 3.911 60.606 3.919 ;
     RECT  68.4 3.649 68.418 3.931 ;
     RECT  69.228 3.569 72.774 3.931 ;
     RECT  63.252 3.691 63.27 4.075 ;
     RECT  64.944 3.371 67.014 4.081 ;
     RECT  63.252 4.075 63.414 4.115 ;
     RECT  64.332 4.081 67.014 4.157 ;
     RECT  41.292 3.685 41.454 4.171 ;
     RECT  2.844 3.721 2.862 4.189 ;
     RECT  20.376 3.245 20.394 4.189 ;
     RECT  42.588 3.677 43.737 4.205 ;
     RECT  20.376 4.189 20.754 4.261 ;
     RECT  30.744 3.343 31.302 4.261 ;
     RECT  41.292 4.171 41.562 4.261 ;
     RECT  52.704 3.355 53.298 4.261 ;
     RECT  54.144 3.379 55.242 4.261 ;
     RECT  63.252 4.115 63.27 4.261 ;
     RECT  52.704 4.261 55.242 4.289 ;
     RECT  19.764 4.261 20.754 4.301 ;
     RECT  46.08 3.443 46.098 4.363 ;
     RECT  47.196 3.181 47.394 4.363 ;
     RECT  18.828 4.189 18.846 4.379 ;
     RECT  20.052 4.301 20.754 4.379 ;
     RECT  41.292 4.261 41.634 4.379 ;
     RECT  50.796 4.261 50.814 4.379 ;
     RECT  53.964 4.289 55.242 4.379 ;
     RECT  23.976 4.351 24.246 4.397 ;
     RECT  36.576 3.067 36.594 4.423 ;
     RECT  37.404 3.371 39.186 4.423 ;
     RECT  24.228 4.397 24.246 4.451 ;
     RECT  43.02 4.205 43.737 4.507 ;
     RECT  16.455 0.793 16.737 4.555 ;
     RECT  48.204 3.749 49.734 4.621 ;
     RECT  2.52 4.189 2.862 4.649 ;
     RECT  15.408 3.073 15.426 4.649 ;
     RECT  32.655 0.793 32.937 4.729 ;
     RECT  33.804 4.555 33.822 4.729 ;
     RECT  34.74 2.803 34.758 4.729 ;
     RECT  62.712 4.261 63.27 4.765 ;
     RECT  2.52 4.649 2.538 4.801 ;
     RECT  16.452 4.555 16.737 4.801 ;
     RECT  32.655 4.729 33.822 4.801 ;
     RECT  56.052 3.407 56.718 4.801 ;
     RECT  58.968 3.919 61.002 4.801 ;
     RECT  34.74 4.729 34.794 4.829 ;
     RECT  61.812 1.147 61.83 4.843 ;
     RECT  62.676 4.765 63.27 4.843 ;
     RECT  54.144 4.379 55.242 4.891 ;
     RECT  56.052 4.801 57.582 4.891 ;
     RECT  9.036 1.651 9.054 4.919 ;
     RECT  32.655 4.801 33.858 4.919 ;
     RECT  7.308 3.109 7.938 4.927 ;
     RECT  32.655 4.919 33.03 4.927 ;
     RECT  58.536 4.801 61.002 5.027 ;
     RECT  11.055 1.469 11.337 5.035 ;
     RECT  33.84 4.919 33.858 5.063 ;
     RECT  64.944 4.157 67.014 5.063 ;
     RECT  40.464 4.225 40.482 5.071 ;
     RECT  41.292 4.379 41.454 5.071 ;
     RECT  58.536 5.027 58.806 5.131 ;
     RECT  48.204 4.621 50.382 5.161 ;
     RECT  34.74 4.829 34.758 5.189 ;
     RECT  61.812 4.843 63.27 5.189 ;
     RECT  14.94 4.765 15.246 5.197 ;
     RECT  42.228 5.161 42.246 5.197 ;
     RECT  43.02 4.507 43.83 5.197 ;
     RECT  48.204 5.161 50.634 5.197 ;
     RECT  48.204 5.197 50.706 5.233 ;
     RECT  20.052 4.379 20.538 5.269 ;
     RECT  48.168 5.233 50.706 5.269 ;
     RECT  52.704 4.289 52.974 5.269 ;
     RECT  14.832 5.197 15.246 5.297 ;
     RECT  32.364 4.927 33.03 5.297 ;
     RECT  54.144 4.891 57.582 5.297 ;
     RECT  27.255 1.469 27.537 5.305 ;
     RECT  46.08 4.363 47.394 5.323 ;
     RECT  61.812 5.189 61.83 5.333 ;
     RECT  40.464 5.071 41.454 5.419 ;
     RECT  45.756 5.323 47.394 5.431 ;
     RECT  48.168 5.269 50.922 5.431 ;
     RECT  3.528 5.131 3.546 5.459 ;
     RECT  14.94 5.297 15.246 5.459 ;
     RECT  20.052 5.269 20.61 5.459 ;
     RECT  35.568 5.269 35.586 5.459 ;
     RECT  45.756 5.431 50.922 5.459 ;
     RECT  54.144 5.297 56.718 5.459 ;
     RECT  62.604 5.189 63.27 5.459 ;
     RECT  40.212 5.419 41.454 5.495 ;
     RECT  58.356 5.131 58.806 5.495 ;
     RECT  45.756 5.459 49.518 5.501 ;
     RECT  68.4 3.931 72.774 5.501 ;
     RECT  54.144 5.459 55.386 5.531 ;
     RECT  42.228 5.197 43.83 5.539 ;
     RECT  16.164 4.801 16.737 5.611 ;
     RECT  54.144 5.531 55.242 5.611 ;
     RECT  56.16 5.459 56.718 5.639 ;
     RECT  45.756 5.501 49.137 5.701 ;
     RECT  50.292 5.459 50.922 5.701 ;
     RECT  51.804 2.795 51.822 5.701 ;
     RECT  44.892 5.701 49.137 5.729 ;
     RECT  57.564 5.297 57.582 5.755 ;
     RECT  40.464 5.495 41.454 5.765 ;
     RECT  36.576 4.423 39.186 5.773 ;
     RECT  59.544 5.027 61.002 5.773 ;
     RECT  64.944 5.063 65.826 5.803 ;
     RECT  50.292 5.701 51.966 5.809 ;
     RECT  52.704 5.269 53.046 5.809 ;
     RECT  64.368 5.803 65.826 5.881 ;
     RECT  59.544 5.773 61.182 5.909 ;
     RECT  44.892 5.729 47.214 5.933 ;
     RECT  58.608 5.495 58.806 5.947 ;
     RECT  59.544 5.909 61.11 5.947 ;
     RECT  2.232 4.801 2.538 5.971 ;
     RECT  50.292 5.809 53.046 6.035 ;
     RECT  13.86 4.531 13.878 6.043 ;
     RECT  14.94 5.459 14.958 6.043 ;
     RECT  32.364 5.297 32.937 6.043 ;
     RECT  58.608 5.947 61.11 6.071 ;
     RECT  66.708 5.063 67.014 6.115 ;
     RECT  67.896 6.091 67.986 6.115 ;
     RECT  7.308 4.927 8.946 6.139 ;
     RECT  6.732 6.139 8.946 6.151 ;
     RECT  9.864 6.091 9.882 6.151 ;
     RECT  11.055 5.035 11.394 6.187 ;
     RECT  42.192 5.539 43.83 6.187 ;
     RECT  57.564 5.755 57.834 6.241 ;
     RECT  58.608 6.071 61.002 6.241 ;
     RECT  6.732 6.151 9.882 6.269 ;
     RECT  44.892 5.933 47.106 6.269 ;
     RECT  32.364 6.043 33.21 6.277 ;
     RECT  36.576 5.773 39.726 6.277 ;
     RECT  2.232 5.971 2.862 6.283 ;
     RECT  3.636 5.611 3.654 6.283 ;
     RECT  18.612 5.305 18.63 6.283 ;
     RECT  15.876 5.611 16.737 6.313 ;
     RECT  66.708 6.115 67.986 6.313 ;
     RECT  11.055 6.187 11.43 6.317 ;
     RECT  32.364 6.277 33.246 6.317 ;
     RECT  35.892 6.277 39.726 6.365 ;
     RECT  48.096 5.729 49.137 6.377 ;
     RECT  15.876 6.313 17.118 6.385 ;
     RECT  17.964 6.283 18.63 6.385 ;
     RECT  56.7 5.639 56.718 6.385 ;
     RECT  50.364 6.035 53.046 6.413 ;
     RECT  68.94 5.501 72.774 6.413 ;
     RECT  36.468 6.365 39.726 6.421 ;
     RECT  40.464 5.765 41.418 6.421 ;
     RECT  56.376 6.385 56.718 6.421 ;
     RECT  57.564 6.241 61.002 6.421 ;
     RECT  62.712 5.459 63.27 6.421 ;
     RECT  64.26 5.881 65.826 6.421 ;
     RECT  44.892 6.269 47.034 6.461 ;
     RECT  66.564 6.313 67.986 6.475 ;
     RECT  62.712 6.421 65.826 6.511 ;
     RECT  66.564 6.475 68.166 6.511 ;
     RECT  56.376 6.421 61.002 6.547 ;
     RECT  56.088 6.547 61.002 6.571 ;
     RECT  36.468 6.421 41.418 6.575 ;
     RECT  68.976 6.413 72.774 6.583 ;
     RECT  50.364 6.413 53.01 6.611 ;
     RECT  56.016 6.571 61.002 6.611 ;
     RECT  2.232 6.283 3.654 6.619 ;
     RECT  62.712 6.511 68.166 6.653 ;
     RECT  42.192 6.187 43.866 6.655 ;
     RECT  44.892 6.461 46.998 6.655 ;
     RECT  50.364 6.611 52.974 6.683 ;
     RECT  62.712 6.653 67.806 6.719 ;
     RECT  0.255 0.793 0.537 6.781 ;
     RECT  56.088 6.611 61.002 6.797 ;
     RECT  68.976 6.583 72.882 6.809 ;
     RECT  1.728 6.619 3.654 6.845 ;
     RECT  63.9 6.719 67.806 6.845 ;
     RECT  15.876 6.385 18.63 6.893 ;
     RECT  63.9 6.845 65.826 6.893 ;
     RECT  66.6 6.845 67.806 6.893 ;
     RECT  3.636 6.845 3.654 6.907 ;
     RECT  48.168 6.377 49.137 7.051 ;
     RECT  42.192 6.655 46.998 7.079 ;
     RECT  45.9 7.079 46.998 7.115 ;
     RECT  64.368 6.893 65.826 7.115 ;
     RECT  66.672 6.893 67.806 7.181 ;
     RECT  56.448 6.797 61.002 7.189 ;
     RECT  56.448 7.189 61.542 7.229 ;
     RECT  3.636 6.907 3.978 7.231 ;
     RECT  13.86 6.043 14.958 7.231 ;
     RECT  15.876 6.893 16.737 7.231 ;
     RECT  46.98 7.115 46.998 7.231 ;
     RECT  36.468 6.575 39.186 7.321 ;
     RECT  40.176 6.575 41.418 7.349 ;
     RECT  46.98 7.231 47.034 7.349 ;
     RECT  56.448 7.229 60.966 7.349 ;
     RECT  13.86 7.231 16.737 7.373 ;
     RECT  0.144 6.781 0.537 7.384 ;
     RECT  1.728 6.845 2.862 7.385 ;
     RECT  3.636 7.231 4.23 7.385 ;
     RECT  40.176 7.349 41.346 7.385 ;
     RECT  66.744 7.181 67.806 7.385 ;
     RECT  21.855 3.299 22.137 7.387 ;
     RECT  21.855 7.387 22.338 7.427 ;
     RECT  32.364 6.317 33.138 7.429 ;
     RECT  36.468 7.321 39.258 7.429 ;
     RECT  40.176 7.385 41.238 7.429 ;
     RECT  56.448 7.349 58.158 7.469 ;
     RECT  42.192 7.079 45.09 7.493 ;
     RECT  13.86 7.373 14.562 7.501 ;
     RECT  48.168 7.051 49.626 7.529 ;
     RECT  57.132 7.469 58.158 7.619 ;
     RECT  30.096 4.261 31.302 7.621 ;
     RECT  32.364 7.429 33.318 7.621 ;
     RECT  69.048 6.809 72.882 7.627 ;
     RECT  36.468 7.429 41.238 7.655 ;
     RECT  46.08 7.115 46.134 7.655 ;
     RECT  53.856 5.611 55.242 7.663 ;
     RECT  58.968 7.349 60.606 7.691 ;
     RECT  30.096 7.621 33.318 7.735 ;
     RECT  6.732 6.269 8.946 7.771 ;
     RECT  47.016 7.349 47.034 7.771 ;
     RECT  62.712 6.719 62.982 7.867 ;
     RECT  29.412 7.735 33.318 7.889 ;
     RECT  47.016 7.771 47.394 7.889 ;
     RECT  50.364 6.683 52.722 7.889 ;
     RECT  57.456 7.619 58.158 7.889 ;
     RECT  68.976 7.627 72.882 7.889 ;
     RECT  30.096 7.889 33.318 7.897 ;
     RECT  68.976 7.889 72.846 7.915 ;
     RECT  48.168 7.529 49.302 7.961 ;
     RECT  57.456 7.889 57.87 7.961 ;
     RECT  5.655 0.793 5.937 7.969 ;
     RECT  53.712 7.663 55.242 8.005 ;
     RECT  64.512 7.115 65.826 8.005 ;
     RECT  66.744 7.385 67.554 8.005 ;
     RECT  0.144 7.384 0.63 8.041 ;
     RECT  1.728 7.385 2.718 8.041 ;
     RECT  15.876 7.373 16.737 8.041 ;
     RECT  17.568 6.893 18.63 8.041 ;
     RECT  53.496 8.005 55.242 8.045 ;
     RECT  24.156 6.583 24.174 8.167 ;
     RECT  68.652 7.915 72.846 8.167 ;
     RECT  15.876 8.041 18.63 8.195 ;
     RECT  27.255 5.305 28.242 8.203 ;
     RECT  68.292 8.167 72.846 8.231 ;
     RECT  62.604 7.867 62.982 8.251 ;
     RECT  40.176 7.655 41.238 8.267 ;
     RECT  13.428 7.501 14.562 8.311 ;
     RECT  42.516 7.493 45.09 8.311 ;
     RECT  50.364 7.889 52.65 8.392 ;
     RECT  30.096 7.897 33.462 8.401 ;
     RECT  13.428 8.311 14.85 8.429 ;
     RECT  26.712 8.203 28.494 8.429 ;
     RECT  68.292 8.231 72.81 8.429 ;
     RECT  50.148 8.392 52.65 8.537 ;
     RECT  35.28 8.539 35.298 8.545 ;
     RECT  64.512 8.005 67.554 8.545 ;
     RECT  25.668 7.429 25.686 8.581 ;
     RECT  35.28 8.545 35.73 8.581 ;
     RECT  36.468 7.655 39.402 8.581 ;
     RECT  58.968 7.691 59.937 8.581 ;
     RECT  63.972 8.545 67.554 8.581 ;
     RECT  0.144 8.041 2.718 8.587 ;
     RECT  3.636 7.385 4.158 8.587 ;
     RECT  12.6 8.587 12.618 8.699 ;
     RECT  50.148 8.537 50.166 8.707 ;
     RECT  62.568 8.251 62.982 8.707 ;
     RECT  40.86 8.267 41.238 8.735 ;
     RECT  53.856 8.045 55.242 8.815 ;
     RECT  62.532 8.707 62.982 8.827 ;
     RECT  63.72 8.581 67.554 8.827 ;
     RECT  5.364 7.969 5.937 8.851 ;
     RECT  13.428 8.429 14.562 8.851 ;
     RECT  25.668 8.581 26.154 8.851 ;
     RECT  42.336 8.311 45.09 8.851 ;
     RECT  46.08 7.655 46.098 8.851 ;
     RECT  47.016 7.889 47.034 8.851 ;
     RECT  58.788 8.581 59.937 8.851 ;
     RECT  42.192 8.851 45.09 8.909 ;
     RECT  48.168 7.961 49.194 8.923 ;
     RECT  30.096 8.401 33.75 8.941 ;
     RECT  30.096 8.941 33.786 8.969 ;
     RECT  46.08 8.851 47.034 8.969 ;
     RECT  62.532 8.827 67.554 9.011 ;
     RECT  58.716 8.851 59.937 9.041 ;
     RECT  50.04 8.707 50.166 9.053 ;
     RECT  50.976 8.537 52.47 9.077 ;
     RECT  33.732 8.969 33.786 9.085 ;
     RECT  33.732 9.085 34.218 9.101 ;
     RECT  33.768 9.101 34.218 9.113 ;
     RECT  35.28 8.581 39.402 9.113 ;
     RECT  42.696 8.909 45.09 9.211 ;
     RECT  57.816 7.961 57.87 9.211 ;
     RECT  61.704 9.121 61.722 9.211 ;
     RECT  62.532 9.011 63.522 9.211 ;
     RECT  21.855 7.427 22.137 9.247 ;
     RECT  25.488 8.851 26.154 9.247 ;
     RECT  27.255 8.429 28.494 9.247 ;
     RECT  47.016 8.969 47.034 9.247 ;
     RECT  56.988 9.211 58.086 9.247 ;
     RECT  61.704 9.211 63.522 9.247 ;
     RECT  53.856 8.815 55.962 9.259 ;
     RECT  56.88 9.247 58.086 9.259 ;
     RECT  68.652 8.429 72.81 9.259 ;
     RECT  42.696 9.211 45.27 9.293 ;
     RECT  61.488 9.247 63.522 9.293 ;
     RECT  48.168 8.923 49.23 9.307 ;
     RECT  17.568 8.195 18.63 9.319 ;
     RECT  21.855 9.247 22.842 9.319 ;
     RECT  30.096 8.969 32.937 9.319 ;
     RECT  35.568 9.113 39.402 9.355 ;
     RECT  5.364 8.851 5.994 9.391 ;
     RECT  6.732 7.771 8.982 9.391 ;
     RECT  20.052 5.459 20.07 9.391 ;
     RECT  47.016 9.247 47.25 9.391 ;
     RECT  48.168 9.307 49.59 9.391 ;
     RECT  21.855 9.319 22.914 9.419 ;
     RECT  40.968 8.735 41.238 9.419 ;
     RECT  53.856 9.259 58.086 9.419 ;
     RECT  21.855 9.419 22.41 9.509 ;
     RECT  35.568 9.355 40.014 9.509 ;
     RECT  53.856 9.419 57.942 9.509 ;
     RECT  35.928 9.509 40.014 9.59 ;
     RECT  21.855 9.509 22.137 9.625 ;
     RECT  42.696 9.293 45.126 9.653 ;
     RECT  47.016 9.391 49.59 9.653 ;
     RECT  20.052 9.391 20.178 9.661 ;
     RECT  20.916 6.619 20.934 9.661 ;
     RECT  24.156 8.167 24.39 9.661 ;
     RECT  25.2 9.247 28.494 9.661 ;
     RECT  21.744 9.625 22.137 9.677 ;
     RECT  53.856 9.509 57.078 9.677 ;
     RECT  53.856 9.677 56.754 9.689 ;
     RECT  11.055 6.317 11.394 9.751 ;
     RECT  29.88 9.319 32.937 9.779 ;
     RECT  35.928 9.59 39.978 9.779 ;
     RECT  29.88 9.779 29.898 9.787 ;
     RECT  62.568 9.293 63.522 9.787 ;
     RECT  64.404 9.011 67.554 9.787 ;
     RECT  29.736 9.787 29.898 9.815 ;
     RECT  53.856 9.689 56.682 9.821 ;
     RECT  46.08 8.969 46.098 9.823 ;
     RECT  47.016 9.653 47.034 9.823 ;
     RECT  50.724 9.481 50.85 9.823 ;
     RECT  51.804 9.077 52.47 9.823 ;
     RECT  34.2 9.113 34.218 9.859 ;
     RECT  41.112 9.419 41.238 9.859 ;
     RECT  17.568 9.319 18.846 9.895 ;
     RECT  20.052 9.661 20.934 9.895 ;
     RECT  10.836 9.751 11.394 9.931 ;
     RECT  24.156 9.661 28.494 9.931 ;
     RECT  34.2 9.859 34.794 9.931 ;
     RECT  48.168 9.653 49.59 9.931 ;
     RECT  48.168 9.931 49.806 9.968 ;
     RECT  50.724 9.823 52.47 9.979 ;
     RECT  17.568 9.895 20.934 10.021 ;
     RECT  50.508 9.979 52.47 10.021 ;
     RECT  58.968 9.041 59.937 10.027 ;
     RECT  60.696 8.401 60.714 10.027 ;
     RECT  33.984 9.931 34.794 10.049 ;
     RECT  35.928 9.779 39.942 10.049 ;
     RECT  50.508 10.021 52.65 10.049 ;
     RECT  62.568 9.787 67.554 10.049 ;
     RECT  58.968 10.027 60.714 10.075 ;
     RECT  50.616 10.049 52.65 10.109 ;
     RECT  34.2 10.049 34.794 10.121 ;
     RECT  41.112 9.859 41.67 10.121 ;
     RECT  9.864 6.269 9.882 10.123 ;
     RECT  10.656 9.931 11.394 10.123 ;
     RECT  53.856 9.821 56.394 10.129 ;
     RECT  0.144 8.587 4.158 10.201 ;
     RECT  30.672 9.779 32.937 10.201 ;
     RECT  41.112 10.121 41.238 10.201 ;
     RECT  61.812 9.293 61.83 10.201 ;
     RECT  62.568 10.049 63.522 10.201 ;
     RECT  50.724 10.109 52.65 10.229 ;
     RECT  53.532 10.129 56.394 10.253 ;
     RECT  23.832 9.931 28.494 10.291 ;
     RECT  29.736 9.815 29.754 10.291 ;
     RECT  5.364 9.391 8.982 10.399 ;
     RECT  9.864 10.123 11.394 10.399 ;
     RECT  23.832 10.291 29.754 10.445 ;
     RECT  23.832 10.445 28.638 10.471 ;
     RECT  57.816 9.509 57.942 10.471 ;
     RECT  58.752 10.075 60.714 10.471 ;
     RECT  57.816 10.471 60.714 10.561 ;
     RECT  61.812 10.201 63.522 10.561 ;
     RECT  23.472 10.471 28.638 10.589 ;
     RECT  34.2 10.121 34.218 10.589 ;
     RECT  57.816 10.561 63.522 10.595 ;
     RECT  23.544 10.589 28.638 10.637 ;
     RECT  53.856 10.253 56.394 10.705 ;
     RECT  29.736 10.445 29.754 10.741 ;
     RECT  30.672 10.201 33.174 10.741 ;
     RECT  48.168 9.968 49.626 10.769 ;
     RECT  0.072 10.201 4.158 10.829 ;
     RECT  35.172 10.315 35.19 10.831 ;
     RECT  35.928 10.049 39.726 10.831 ;
     RECT  17.532 10.021 20.934 10.877 ;
     RECT  64.404 10.049 67.554 10.895 ;
     RECT  53.856 10.705 57.078 10.897 ;
     RECT  5.364 10.399 11.394 10.939 ;
     RECT  35.172 10.831 39.726 10.939 ;
     RECT  51.696 10.229 52.65 10.939 ;
     RECT  17.532 10.877 18.846 10.967 ;
     RECT  19.584 10.877 20.934 10.967 ;
     RECT  40.896 10.201 41.238 10.975 ;
     RECT  12.708 8.851 14.562 10.987 ;
     RECT  51.696 10.939 52.758 11.039 ;
     RECT  60.696 10.595 63.522 11.101 ;
     RECT  12.708 10.987 14.958 11.129 ;
     RECT  51.696 11.039 52.686 11.131 ;
     RECT  34.776 10.939 39.726 11.165 ;
     RECT  5.328 10.939 11.394 11.201 ;
     RECT  40.896 10.975 41.958 11.227 ;
     RECT  42.696 9.653 45.09 11.227 ;
     RECT  50.724 10.229 50.886 11.245 ;
     RECT  51.66 11.131 52.686 11.245 ;
     RECT  53.856 10.897 56.394 11.273 ;
     RECT  50.724 11.245 52.686 11.309 ;
     RECT  20.592 10.967 20.934 11.371 ;
     RECT  21.855 9.677 22.137 11.371 ;
     RECT  50.724 11.309 52.362 11.399 ;
     RECT  57.816 10.595 59.937 11.399 ;
     RECT  19.584 10.967 19.818 11.405 ;
     RECT  15.876 8.195 16.737 11.407 ;
     RECT  17.532 10.967 18.63 11.407 ;
     RECT  29.736 10.741 33.174 11.407 ;
     RECT  35.1 11.165 39.726 11.435 ;
     RECT  0.108 10.829 4.158 11.467 ;
     RECT  50.724 11.399 51.822 11.479 ;
     RECT  50.616 11.479 51.822 11.515 ;
     RECT  40.896 11.227 45.09 11.551 ;
     RECT  50.436 11.515 51.822 11.597 ;
     RECT  40.896 11.551 45.27 11.611 ;
     RECT  46.08 9.823 47.034 11.611 ;
     RECT  50.436 11.597 51.786 11.641 ;
     RECT  40.896 11.611 47.034 11.669 ;
     RECT  60.696 11.101 63.918 11.713 ;
     RECT  64.764 10.895 67.554 11.713 ;
     RECT  60.696 11.713 67.554 11.777 ;
     RECT  36.324 11.435 39.726 11.813 ;
     RECT  45.936 11.669 45.954 11.813 ;
     RECT  50.292 11.641 51.786 11.813 ;
     RECT  68.364 9.259 72.81 11.813 ;
     RECT  0.108 11.467 4.266 11.821 ;
     RECT  19.656 11.405 19.818 11.821 ;
     RECT  20.592 11.371 22.137 11.821 ;
     RECT  55.548 11.273 56.394 11.821 ;
     RECT  50.292 11.813 51.714 11.849 ;
     RECT  36.396 11.813 39.726 11.911 ;
     RECT  48.168 10.769 49.374 11.911 ;
     RECT  50.292 11.849 50.814 11.911 ;
     RECT  0.108 11.821 4.338 11.939 ;
     RECT  51.696 11.849 51.714 11.939 ;
     RECT  63.9 11.777 67.554 11.939 ;
     RECT  40.896 11.669 45.09 11.975 ;
     RECT  60.696 11.777 62.802 11.975 ;
     RECT  68.364 11.813 72.774 11.975 ;
     RECT  40.896 11.975 44.874 11.981 ;
     RECT  48.168 11.911 50.814 11.981 ;
     RECT  35.1 11.435 35.37 11.983 ;
     RECT  12.708 11.129 14.31 11.995 ;
     RECT  63.9 11.939 65.862 12.029 ;
     RECT  15.876 11.407 18.63 12.043 ;
     RECT  55.548 11.821 57.042 12.047 ;
     RECT  5.328 11.201 6.966 12.091 ;
     RECT  7.704 11.201 11.394 12.091 ;
     RECT  34.92 11.983 35.37 12.091 ;
     RECT  57.816 11.399 57.942 12.181 ;
     RECT  58.968 11.399 59.937 12.181 ;
     RECT  15.876 12.043 18.846 12.209 ;
     RECT  53.856 11.273 54.81 12.217 ;
     RECT  55.548 12.047 56.898 12.217 ;
     RECT  12.168 11.995 14.85 12.235 ;
     RECT  29.628 11.407 33.174 12.235 ;
     RECT  60.696 11.975 62.73 12.245 ;
     RECT  29.556 12.235 33.174 12.283 ;
     RECT  34.812 12.091 35.37 12.361 ;
     RECT  36.396 11.911 39.798 12.361 ;
     RECT  17.892 12.209 18.846 12.365 ;
     RECT  46.764 11.669 47.034 12.451 ;
     RECT  57.816 12.181 59.937 12.475 ;
     RECT  60.696 12.245 62.514 12.475 ;
     RECT  23.544 10.637 28.494 12.479 ;
     RECT  29.232 12.283 33.174 12.479 ;
     RECT  34.776 12.361 35.37 12.619 ;
     RECT  5.328 12.091 11.394 12.631 ;
     RECT  12.168 12.235 14.886 12.631 ;
     RECT  46.188 12.451 47.034 12.631 ;
     RECT  53.856 12.217 56.898 12.667 ;
     RECT  34.524 12.619 35.37 12.721 ;
     RECT  48.168 11.981 50.778 12.749 ;
     RECT  46.188 12.631 47.106 12.793 ;
     RECT  34.524 12.721 35.658 12.797 ;
     RECT  57.816 12.475 62.514 12.821 ;
     RECT  50.724 12.749 50.778 12.857 ;
     RECT  19.656 11.821 22.137 12.865 ;
     RECT  23.544 12.479 28.206 12.865 ;
     RECT  34.524 12.797 35.37 12.865 ;
     RECT  40.896 11.981 44.478 12.865 ;
     RECT  5.328 12.631 14.886 12.901 ;
     RECT  34.416 12.865 35.37 12.901 ;
     RECT  52.272 12.763 52.29 12.901 ;
     RECT  53.352 12.667 56.898 12.901 ;
     RECT  46.188 12.793 47.142 12.941 ;
     RECT  52.272 12.901 56.898 12.991 ;
     RECT  19.476 12.865 28.206 13.019 ;
     RECT  19.476 13.019 22.137 13.055 ;
     RECT  58.356 12.821 62.514 13.055 ;
     RECT  52.272 12.991 57.546 13.085 ;
     RECT  58.428 13.055 62.514 13.085 ;
     RECT  5.328 12.901 15.03 13.091 ;
     RECT  0.108 11.939 4.158 13.099 ;
     RECT  58.716 13.085 62.514 13.099 ;
     RECT  63.252 12.991 63.342 13.099 ;
     RECT  64.44 12.029 65.862 13.135 ;
     RECT  66.708 11.939 67.554 13.135 ;
     RECT  0.072 13.099 4.158 13.147 ;
     RECT  58.716 13.099 63.342 13.243 ;
     RECT  64.44 13.135 67.626 13.243 ;
     RECT  40.896 12.865 45.054 13.289 ;
     RECT  58.716 13.243 67.626 13.325 ;
     RECT  15.876 12.209 16.794 13.361 ;
     RECT  23.22 13.019 28.206 13.387 ;
     RECT  45.036 13.289 45.054 13.387 ;
     RECT  52.992 13.085 56.898 13.397 ;
     RECT  68.652 11.975 72.774 13.397 ;
     RECT  51.408 12.865 51.426 13.405 ;
     RECT  23.22 13.387 28.494 13.433 ;
     RECT  29.556 12.479 33.174 13.441 ;
     RECT  48.168 12.749 49.878 13.441 ;
     RECT  45.036 13.387 45.234 13.469 ;
     RECT  52.992 13.397 54.81 13.469 ;
     RECT  36.396 12.361 39.942 13.517 ;
     RECT  0.072 13.147 4.266 13.531 ;
     RECT  51.408 13.405 51.858 13.559 ;
     RECT  52.992 13.469 54.594 13.559 ;
     RECT  68.652 13.397 72.738 13.559 ;
     RECT  36.396 13.517 38.826 13.565 ;
     RECT  54.144 13.559 54.594 13.568 ;
     RECT  29.556 13.441 33.426 13.595 ;
     RECT  23.22 13.433 27.954 13.613 ;
     RECT  37.332 13.565 38.826 13.613 ;
     RECT  29.556 13.595 29.826 13.627 ;
     RECT  51.552 13.559 51.858 13.631 ;
     RECT  47.664 13.441 49.878 13.703 ;
     RECT  0.072 13.531 4.338 13.711 ;
     RECT  5.328 13.091 14.562 13.711 ;
     RECT  39.672 13.517 39.942 13.711 ;
     RECT  40.896 13.289 44.298 13.711 ;
     RECT  46.188 12.941 46.854 13.711 ;
     RECT  47.664 13.703 47.682 13.711 ;
     RECT  39.672 13.711 44.298 13.829 ;
     RECT  0.072 13.711 14.562 13.909 ;
     RECT  34.38 12.901 35.37 13.909 ;
     RECT  23.22 13.613 27.63 13.945 ;
     RECT  46.188 13.711 47.682 13.973 ;
     RECT  0.036 13.909 14.562 13.981 ;
     RECT  17.892 12.365 18.63 13.981 ;
     RECT  28.692 13.441 28.71 14.009 ;
     RECT  30.6 13.595 33.426 14.009 ;
     RECT  39.708 13.829 44.298 14.009 ;
     RECT  32.184 14.009 33.426 14.107 ;
     RECT  34.38 13.909 35.406 14.107 ;
     RECT  17.892 13.981 18.666 14.179 ;
     RECT  58.716 13.325 67.014 14.189 ;
     RECT  32.184 14.107 35.406 14.215 ;
     RECT  36.396 13.565 36.414 14.215 ;
     RECT  52.992 13.559 53.37 14.215 ;
     RECT  17.676 14.179 18.666 14.237 ;
     RECT  32.184 14.215 36.414 14.243 ;
     RECT  37.656 13.613 38.826 14.243 ;
     RECT  46.404 13.973 47.682 14.243 ;
     RECT  58.716 14.189 64.206 14.243 ;
     RECT  19.656 13.055 22.137 14.251 ;
     RECT  39.78 14.009 44.298 14.251 ;
     RECT  54.255 13.568 54.594 14.251 ;
     RECT  55.548 13.397 56.898 14.251 ;
     RECT  29.484 13.627 29.826 14.279 ;
     RECT  46.404 14.243 47.286 14.279 ;
     RECT  23.076 13.945 27.63 14.285 ;
     RECT  54.255 14.251 54.774 14.341 ;
     RECT  55.548 14.251 57.15 14.341 ;
     RECT  19.62 14.251 22.137 14.369 ;
     RECT  34.2 14.243 36.414 14.429 ;
     RECT  25.92 14.285 27.63 14.443 ;
     RECT  34.38 14.429 36.414 14.449 ;
     RECT  37.656 14.243 38.79 14.477 ;
     RECT  39.78 14.251 44.658 14.513 ;
     RECT  18.252 14.237 18.666 14.521 ;
     RECT  52.704 14.215 53.37 14.521 ;
     RECT  54.255 14.341 57.15 14.521 ;
     RECT  25.92 14.443 27.99 14.549 ;
     RECT  40.608 14.513 44.658 14.611 ;
     RECT  45.468 14.299 45.486 14.611 ;
     RECT  40.608 14.611 45.486 14.639 ;
     RECT  46.404 14.279 46.782 14.639 ;
     RECT  18.252 14.521 18.81 14.647 ;
     RECT  19.656 14.369 22.137 14.647 ;
     RECT  23.076 14.285 24.93 14.647 ;
     RECT  50.76 14.521 50.778 14.647 ;
     RECT  50.724 14.647 50.778 14.648 ;
     RECT  68.652 13.559 72.702 14.683 ;
     RECT  19.656 14.647 24.93 14.711 ;
     RECT  45.36 14.639 45.486 14.717 ;
     RECT  25.92 14.549 27.954 14.783 ;
     RECT  46.404 14.639 46.566 14.791 ;
     RECT  52.704 14.521 57.15 14.791 ;
     RECT  40.608 14.639 44.442 14.813 ;
     RECT  45.828 14.791 46.566 14.819 ;
     RECT  58.716 14.243 63.846 14.819 ;
     RECT  65.055 14.189 67.014 14.917 ;
     RECT  30.6 14.009 30.978 14.971 ;
     RECT  52.416 14.791 57.15 14.989 ;
     RECT  60.84 14.819 63.846 14.989 ;
     RECT  65.055 14.917 67.662 14.989 ;
     RECT  25.92 14.783 26.226 15.019 ;
     RECT  51.552 13.631 51.57 15.025 ;
     RECT  52.416 14.989 57.402 15.025 ;
     RECT  60.84 14.989 67.662 15.053 ;
     RECT  29.484 14.279 29.574 15.061 ;
     RECT  51.552 15.025 57.402 15.061 ;
     RECT  68.652 14.683 72.738 15.067 ;
     RECT  27.036 14.783 27.954 15.101 ;
     RECT  37.656 14.477 38.574 15.101 ;
     RECT  16.236 13.361 16.794 15.115 ;
     RECT  18.252 14.647 18.846 15.151 ;
     RECT  19.656 14.711 24.786 15.151 ;
     RECT  58.716 14.819 60.03 15.151 ;
     RECT  60.84 15.053 67.626 15.179 ;
     RECT  34.38 14.449 36.846 15.251 ;
     RECT  36.396 15.251 36.846 15.259 ;
     RECT  60.876 15.179 67.626 15.287 ;
     RECT  27.255 15.101 27.954 15.307 ;
     RECT  58.68 15.151 60.03 15.323 ;
     RECT  16.092 15.115 16.794 15.331 ;
     RECT  29.484 15.061 29.718 15.331 ;
     RECT  30.6 14.971 31.014 15.331 ;
     RECT  48.816 13.703 49.878 15.331 ;
     RECT  50.724 14.648 50.742 15.331 ;
     RECT  25.704 15.019 26.226 15.359 ;
     RECT  60.948 15.287 67.626 15.359 ;
     RECT  61.524 15.359 67.626 15.389 ;
     RECT  51.552 15.061 57.438 15.421 ;
     RECT  58.68 15.323 59.937 15.421 ;
     RECT  25.704 15.359 26.01 15.449 ;
     RECT  48.816 15.331 50.742 15.451 ;
     RECT  51.552 15.421 59.937 15.451 ;
     RECT  16.092 15.331 17.046 15.547 ;
     RECT  48.816 15.451 59.937 15.557 ;
     RECT  45.828 14.819 45.846 15.565 ;
     RECT  48.816 15.557 57.726 15.581 ;
     RECT  45.828 15.565 45.954 15.592 ;
     RECT  46.764 15.421 46.782 15.592 ;
     RECT  51.552 15.581 57.726 15.593 ;
     RECT  58.716 15.557 59.937 15.593 ;
     RECT  27.255 15.307 28.242 15.595 ;
     RECT  32.184 14.243 33.462 15.595 ;
     RECT  34.38 15.251 35.658 15.595 ;
     RECT  18.252 15.151 24.786 15.601 ;
     RECT  25.704 15.449 25.938 15.601 ;
     RECT  39.78 14.513 39.798 15.601 ;
     RECT  40.608 14.813 43.866 15.601 ;
     RECT  45.828 15.592 46.782 15.629 ;
     RECT  27.255 15.595 28.458 15.691 ;
     RECT  39.348 15.601 39.798 15.719 ;
     RECT  68.652 15.067 72.774 15.727 ;
     RECT  27.255 15.691 28.53 15.773 ;
     RECT  39.348 15.719 39.474 15.773 ;
     RECT  18.252 15.601 25.938 15.791 ;
     RECT  45.828 15.629 46.17 15.799 ;
     RECT  61.524 15.389 64.098 15.827 ;
     RECT  52.488 15.593 57.726 15.863 ;
     RECT  37.656 15.101 38.394 15.871 ;
     RECT  40.536 15.601 43.866 15.871 ;
     RECT  40.32 15.871 43.866 16.075 ;
     RECT  29.484 15.331 31.014 16.105 ;
     RECT  48.816 15.581 50.814 16.133 ;
     RECT  27.255 15.773 28.314 16.141 ;
     RECT  29.376 16.105 31.014 16.141 ;
     RECT  32.184 15.595 35.658 16.141 ;
     RECT  36.396 15.259 36.918 16.141 ;
     RECT  24.768 15.791 25.938 16.169 ;
     RECT  0.036 13.981 14.598 16.267 ;
     RECT  15.552 15.547 17.046 16.267 ;
     RECT  40.32 16.075 44.046 16.295 ;
     RECT  25.416 16.169 25.938 16.339 ;
     RECT  27.144 16.141 28.314 16.339 ;
     RECT  0.036 16.267 17.046 16.363 ;
     RECT  37.656 15.871 38.862 16.367 ;
     RECT  50.796 16.133 50.814 16.367 ;
     RECT  45.54 15.799 46.17 16.405 ;
     RECT  46.908 15.961 46.962 16.405 ;
     RECT  18.252 15.791 23.562 16.411 ;
     RECT  40.932 16.295 44.046 16.411 ;
     RECT  29.376 16.141 36.918 16.445 ;
     RECT  61.56 15.827 64.098 16.445 ;
     RECT  17.892 16.411 23.562 16.529 ;
     RECT  25.416 16.339 28.314 16.529 ;
     RECT  30.996 16.445 36.918 16.529 ;
     RECT  40.932 16.411 44.442 16.529 ;
     RECT  61.632 16.445 64.098 16.529 ;
     RECT  61.632 16.529 62.694 16.541 ;
     RECT  63.576 16.529 64.098 16.555 ;
     RECT  64.836 15.389 67.626 16.555 ;
     RECT  41.4 16.529 44.442 16.651 ;
     RECT  17.964 16.529 23.562 16.681 ;
     RECT  36.18 16.529 36.918 16.681 ;
     RECT  37.656 16.367 38.826 16.681 ;
     RECT  52.704 15.863 57.726 16.681 ;
     RECT  58.788 15.593 59.937 16.681 ;
     RECT  68.652 15.727 72.846 16.871 ;
     RECT  52.704 16.681 59.937 16.877 ;
     RECT  17.964 16.681 24.39 16.891 ;
     RECT  25.416 16.529 26.082 16.891 ;
     RECT  52.704 16.877 57.15 16.907 ;
     RECT  48.816 16.133 49.878 16.915 ;
     RECT  45.54 16.405 46.962 16.943 ;
     RECT  41.4 16.651 44.478 17.041 ;
     RECT  47.988 16.681 48.006 17.041 ;
     RECT  48.78 16.915 49.878 17.041 ;
     RECT  36.18 16.681 38.826 17.069 ;
     RECT  47.988 17.041 49.878 17.069 ;
     RECT  46.764 16.943 46.962 17.083 ;
     RECT  41.4 17.041 44.694 17.113 ;
     RECT  48.636 17.069 49.878 17.131 ;
     RECT  50.724 17.083 50.742 17.131 ;
     RECT  41.4 17.113 44.73 17.149 ;
     RECT  0.036 16.363 17.082 17.165 ;
     RECT  29.376 16.445 30.186 17.179 ;
     RECT  30.996 16.529 35.226 17.179 ;
     RECT  0.036 17.165 14.598 17.213 ;
     RECT  17.964 16.891 26.082 17.213 ;
     RECT  48.636 17.131 50.742 17.213 ;
     RECT  41.4 17.149 44.802 17.221 ;
     RECT  45.54 16.943 45.954 17.221 ;
     RECT  19.368 17.213 26.082 17.311 ;
     RECT  62.136 16.541 62.514 17.311 ;
     RECT  37.296 17.069 38.826 17.347 ;
     RECT  41.4 17.221 45.954 17.375 ;
     RECT  37.296 17.347 38.862 17.383 ;
     RECT  68.652 16.871 72.81 17.383 ;
     RECT  48.636 17.213 50.238 17.411 ;
     RECT  58.104 16.877 59.937 17.411 ;
     RECT  62.136 17.311 62.73 17.411 ;
     RECT  29.376 17.179 35.226 17.453 ;
     RECT  63.576 16.555 67.626 17.491 ;
     RECT  41.4 17.375 44.622 17.492 ;
     RECT  29.376 17.453 35.118 17.519 ;
     RECT  37.296 17.383 38.934 17.519 ;
     RECT  53.208 16.907 57.15 17.519 ;
     RECT  63.252 17.491 67.626 17.549 ;
     RECT  19.368 17.311 26.118 17.581 ;
     RECT  26.928 16.529 28.314 17.581 ;
     RECT  63.252 17.549 64.17 17.597 ;
     RECT  19.368 17.581 28.314 17.609 ;
     RECT  41.4 17.492 44.586 17.609 ;
     RECT  53.208 17.519 56.178 17.609 ;
     RECT  56.952 17.519 57.15 17.609 ;
     RECT  57.132 17.609 57.15 17.611 ;
     RECT  0.036 17.213 13.986 17.645 ;
     RECT  41.4 17.609 44.55 17.645 ;
     RECT  41.4 17.645 44.514 17.681 ;
     RECT  15.444 17.165 17.082 17.689 ;
     RECT  17.964 17.213 18.63 17.689 ;
     RECT  57.132 17.611 57.258 17.707 ;
     RECT  58.104 17.411 58.122 17.707 ;
     RECT  46.764 17.083 47.898 17.725 ;
     RECT  45.54 17.375 45.954 17.753 ;
     RECT  25.416 17.609 28.314 17.755 ;
     RECT  29.376 17.519 35.046 17.755 ;
     RECT  51.552 15.593 51.57 17.761 ;
     RECT  52.452 17.185 52.47 17.761 ;
     RECT  59.292 17.411 59.937 17.761 ;
     RECT  13.464 17.645 13.986 17.879 ;
     RECT  57.132 17.707 58.122 17.902 ;
     RECT  0.036 17.645 12.258 17.951 ;
     RECT  59.292 17.761 60.39 17.959 ;
     RECT  15.444 17.689 18.63 18.059 ;
     RECT  57.384 17.902 58.122 18.059 ;
     RECT  16.455 18.059 18.63 18.091 ;
     RECT  19.368 17.609 24.678 18.091 ;
     RECT  15.444 18.059 15.57 18.121 ;
     RECT  51.552 17.761 52.47 18.121 ;
     RECT  53.208 17.609 53.226 18.121 ;
     RECT  59.292 17.959 60.57 18.121 ;
     RECT  57.672 18.059 58.122 18.149 ;
     RECT  59.292 18.121 60.894 18.149 ;
     RECT  14.796 18.121 15.57 18.221 ;
     RECT  51.372 18.121 53.226 18.221 ;
     RECT  59.292 18.149 59.937 18.229 ;
     RECT  60.876 18.149 60.894 18.229 ;
     RECT  16.455 18.091 24.678 18.269 ;
     RECT  58.86 18.229 59.937 18.301 ;
     RECT  62.136 17.411 62.298 18.301 ;
     RECT  68.4 17.383 72.81 18.329 ;
     RECT  51.012 18.265 51.03 18.391 ;
     RECT  14.868 18.221 15.57 18.419 ;
     RECT  25.416 17.755 35.046 18.419 ;
     RECT  46.728 17.725 47.898 18.419 ;
     RECT  62.136 18.301 62.766 18.419 ;
     RECT  60.876 18.229 61.362 18.455 ;
     RECT  62.136 18.419 62.586 18.455 ;
     RECT  25.416 18.419 33.03 18.461 ;
     RECT  33.912 18.419 35.046 18.461 ;
     RECT  62.568 18.455 62.586 18.461 ;
     RECT  25.416 18.461 30.078 18.491 ;
     RECT  34.128 18.461 35.046 18.523 ;
     RECT  46.764 18.419 47.898 18.571 ;
     RECT  48.636 17.411 49.878 18.571 ;
     RECT  50.688 18.391 51.03 18.571 ;
     RECT  64.98 17.549 67.626 18.599 ;
     RECT  54.255 17.609 56.178 18.661 ;
     RECT  19.368 18.269 24.678 18.749 ;
     RECT  34.128 18.523 35.298 18.749 ;
     RECT  46.764 18.571 51.03 18.761 ;
     RECT  37.296 17.519 38.826 18.841 ;
     RECT  58.428 18.301 59.937 18.931 ;
     RECT  54.255 18.661 56.61 18.955 ;
     RECT  36.18 17.069 36.45 19.003 ;
     RECT  37.296 18.841 38.898 19.003 ;
     RECT  44.496 17.681 44.514 19.003 ;
     RECT  45.54 17.753 45.846 19.003 ;
     RECT  64.98 18.599 66.438 19.031 ;
     RECT  48.636 18.761 51.03 19.039 ;
     RECT  51.876 18.221 53.226 19.039 ;
     RECT  58.356 18.931 59.937 19.075 ;
     RECT  54.255 18.955 56.646 19.111 ;
     RECT  57.528 18.811 57.546 19.111 ;
     RECT  58.356 19.075 60.03 19.111 ;
     RECT  48.636 19.039 53.226 19.139 ;
     RECT  54.255 19.111 60.066 19.195 ;
     RECT  60.876 18.455 60.894 19.195 ;
     RECT  44.496 19.003 45.846 19.201 ;
     RECT  46.764 18.761 47.61 19.201 ;
     RECT  67.284 18.599 67.626 19.201 ;
     RECT  44.496 19.201 47.61 19.229 ;
     RECT  48.636 19.139 52.002 19.229 ;
     RECT  54.255 19.195 60.894 19.229 ;
     RECT  15.192 18.419 15.57 19.273 ;
     RECT  55.8 19.229 58.806 19.301 ;
     RECT  59.544 19.229 60.894 19.301 ;
     RECT  34.128 18.749 35.19 19.337 ;
     RECT  29.052 18.491 30.078 19.345 ;
     RECT  30.888 18.461 33.03 19.345 ;
     RECT  41.4 17.681 43.737 19.345 ;
     RECT  44.496 19.229 47.07 19.345 ;
     RECT  67.284 19.201 67.698 19.345 ;
     RECT  68.652 18.329 72.81 19.345 ;
     RECT  41.4 19.345 47.07 19.373 ;
     RECT  51.264 19.229 52.002 19.373 ;
     RECT  16.455 18.269 18.63 19.381 ;
     RECT  19.368 18.749 22.194 19.381 ;
     RECT  29.052 19.345 33.03 19.381 ;
     RECT  34.128 19.337 35.046 19.381 ;
     RECT  41.4 19.373 46.998 19.409 ;
     RECT  51.264 19.373 51.93 19.409 ;
     RECT  12.24 17.951 12.258 19.435 ;
     RECT  25.416 18.491 28.314 19.471 ;
     RECT  29.052 19.381 35.046 19.471 ;
     RECT  65.055 19.031 66.438 19.471 ;
     RECT  67.284 19.345 72.81 19.471 ;
     RECT  12.24 19.435 12.51 19.499 ;
     RECT  16.455 19.381 22.194 19.507 ;
     RECT  63.576 17.597 64.17 19.507 ;
     RECT  22.968 18.749 24.678 19.531 ;
     RECT  25.416 19.471 35.046 19.531 ;
     RECT  16.455 19.507 22.23 19.543 ;
     RECT  22.968 19.531 35.046 19.543 ;
     RECT  41.4 19.409 46.602 19.571 ;
     RECT  36.18 19.003 38.898 19.579 ;
     RECT  0.036 17.951 11.502 19.651 ;
     RECT  12.24 19.499 12.258 19.651 ;
     RECT  16.455 19.543 35.046 19.679 ;
     RECT  41.4 19.571 46.566 19.805 ;
     RECT  16.455 19.679 28.314 19.841 ;
     RECT  65.055 19.471 72.81 19.849 ;
     RECT  56.052 19.301 58.806 19.949 ;
     RECT  54.255 19.229 54.99 19.963 ;
     RECT  52.74 19.139 53.226 20.011 ;
     RECT  54 19.963 54.99 20.011 ;
     RECT  16.455 19.841 20.718 20.039 ;
     RECT  58.464 19.949 58.806 20.039 ;
     RECT  52.74 20.011 54.99 20.047 ;
     RECT  58.716 20.039 58.806 20.047 ;
     RECT  59.544 19.301 60.138 20.047 ;
     RECT  62.892 19.507 64.17 20.047 ;
     RECT  65.016 19.849 72.81 20.047 ;
     RECT  58.716 20.047 60.138 20.059 ;
     RECT  60.876 19.301 60.894 20.059 ;
     RECT  52.74 20.047 55.314 20.083 ;
     RECT  56.052 19.949 57.546 20.083 ;
     RECT  14.832 19.273 15.57 20.119 ;
     RECT  48.636 19.229 50.454 20.155 ;
     RECT  14.724 20.119 15.57 20.191 ;
     RECT  16.455 20.039 18.306 20.191 ;
     RECT  29.052 19.679 35.046 20.191 ;
     RECT  36.144 19.579 38.898 20.191 ;
     RECT  47.844 20.047 47.862 20.191 ;
     RECT  48.636 20.155 50.814 20.191 ;
     RECT  21.456 19.841 28.314 20.219 ;
     RECT  47.844 20.191 50.814 20.281 ;
     RECT  0.036 19.651 12.258 20.309 ;
     RECT  14.724 20.191 18.306 20.309 ;
     RECT  21.708 20.219 28.314 20.309 ;
     RECT  41.4 19.805 46.494 20.309 ;
     RECT  52.74 20.083 57.546 20.309 ;
     RECT  25.344 20.309 28.314 20.381 ;
     RECT  39.636 20.191 39.654 20.381 ;
     RECT  62.784 20.047 64.17 20.389 ;
     RECT  29.052 20.191 38.898 20.395 ;
     RECT  41.4 20.309 46.386 20.417 ;
     RECT  65.016 20.047 72.846 20.443 ;
     RECT  47.448 20.281 50.814 20.453 ;
     RECT  62.748 20.389 64.17 20.461 ;
     RECT  64.944 20.443 72.846 20.461 ;
     RECT  0.036 20.309 12.042 20.489 ;
     RECT  19.152 20.039 20.718 20.489 ;
     RECT  54.255 20.309 57.546 20.489 ;
     RECT  26.856 20.381 28.314 20.587 ;
     RECT  29.052 20.395 38.97 20.587 ;
     RECT  58.716 20.059 60.894 20.623 ;
     RECT  13.968 17.879 13.986 20.651 ;
     RECT  58.716 20.623 61.218 20.659 ;
     RECT  61.992 20.551 62.01 20.659 ;
     RECT  58.716 20.659 62.01 20.731 ;
     RECT  62.748 20.461 72.846 20.731 ;
     RECT  14.724 20.309 15.57 20.759 ;
     RECT  58.716 20.731 72.846 20.861 ;
     RECT  56.448 20.489 57.546 20.893 ;
     RECT  65.016 20.861 72.846 20.957 ;
     RECT  51.696 19.409 51.714 21.001 ;
     RECT  52.74 20.309 53.226 21.001 ;
     RECT  58.716 20.861 64.278 21.029 ;
     RECT  47.448 20.453 47.466 21.091 ;
     RECT  48.636 20.453 50.814 21.091 ;
     RECT  51.696 21.001 53.226 21.091 ;
     RECT  16.455 20.309 18.306 21.115 ;
     RECT  19.152 20.489 20.214 21.115 ;
     RECT  26.856 20.587 38.97 21.119 ;
     RECT  41.4 20.417 45.666 21.119 ;
     RECT  48.636 21.091 53.226 21.119 ;
     RECT  58.716 21.029 61.218 21.119 ;
     RECT  52.74 21.119 53.226 21.127 ;
     RECT  56.448 20.893 57.762 21.127 ;
     RECT  58.716 21.119 61.074 21.127 ;
     RECT  26.856 21.119 35.442 21.155 ;
     RECT  56.448 21.127 61.074 21.155 ;
     RECT  44.496 21.119 45.666 21.163 ;
     RECT  46.8 21.091 47.466 21.163 ;
     RECT  12.672 21.091 12.69 21.199 ;
     RECT  26.856 21.155 35.118 21.199 ;
     RECT  41.4 21.119 43.737 21.235 ;
     RECT  16.455 21.115 20.214 21.271 ;
     RECT  12.672 21.199 12.834 21.299 ;
     RECT  62.136 21.029 64.278 21.299 ;
     RECT  14.832 20.759 15.57 21.307 ;
     RECT  56.448 21.155 59.937 21.341 ;
     RECT  16.455 21.271 20.79 21.389 ;
     RECT  65.016 20.957 72.81 21.389 ;
     RECT  54.255 20.489 55.71 21.397 ;
     RECT  56.448 21.341 57.942 21.397 ;
     RECT  26.784 21.199 35.118 21.425 ;
     RECT  58.68 21.341 59.937 21.425 ;
     RECT  16.455 21.389 20.214 21.437 ;
     RECT  54.255 21.397 57.942 21.437 ;
     RECT  56.448 21.437 57.942 21.461 ;
     RECT  58.752 21.425 59.937 21.485 ;
     RECT  60.732 21.155 61.074 21.485 ;
     RECT  56.448 21.461 57.906 21.497 ;
     RECT  48.636 21.119 51.714 21.505 ;
     RECT  26.784 21.425 35.046 21.533 ;
     RECT  44.496 21.163 45.918 21.533 ;
     RECT  58.824 21.485 59.937 21.533 ;
     RECT  14.832 21.307 15.714 21.541 ;
     RECT  16.455 21.437 18.306 21.541 ;
     RECT  21.708 20.309 24.39 21.541 ;
     RECT  25.344 20.381 26.046 21.541 ;
     RECT  40.104 21.541 40.122 21.547 ;
     RECT  54.255 21.437 55.71 21.569 ;
     RECT  58.896 21.533 59.937 21.569 ;
     RECT  63.36 21.299 64.278 21.569 ;
     RECT  56.448 21.497 57.762 21.581 ;
     RECT  36.18 21.119 38.97 21.629 ;
     RECT  14.256 21.541 18.306 21.659 ;
     RECT  26.784 21.533 35.01 21.659 ;
     RECT  40.104 21.547 40.194 21.659 ;
     RECT  60.732 21.485 60.894 21.659 ;
     RECT  0.036 20.489 11.79 21.811 ;
     RECT  12.672 21.299 12.762 21.811 ;
     RECT  21.708 21.541 26.046 21.811 ;
     RECT  26.784 21.659 34.938 21.811 ;
     RECT  45.612 21.533 45.918 21.811 ;
     RECT  48.42 21.505 51.714 21.901 ;
     RECT  0.036 21.811 12.762 21.929 ;
     RECT  45.612 21.811 45.99 21.929 ;
     RECT  21.708 21.811 34.938 21.973 ;
     RECT  46.764 21.163 47.466 21.979 ;
     RECT  48.384 21.901 51.714 21.979 ;
     RECT  45.612 21.929 45.63 22.037 ;
     RECT  52.74 21.127 53.298 22.045 ;
     RECT  46.764 21.979 51.714 22.081 ;
     RECT  52.74 22.045 53.406 22.081 ;
     RECT  46.728 22.081 51.714 22.109 ;
     RECT  46.728 22.109 49.374 22.157 ;
     RECT  41.328 21.235 43.737 22.171 ;
     RECT  44.496 21.533 44.802 22.171 ;
     RECT  52.452 22.081 53.406 22.171 ;
     RECT  54.255 21.569 55.638 22.171 ;
     RECT  63.54 21.569 64.278 22.171 ;
     RECT  65.016 21.389 65.574 22.171 ;
     RECT  21.096 21.973 34.938 22.199 ;
     RECT  46.764 22.157 49.374 22.199 ;
     RECT  63.54 22.171 65.574 22.219 ;
     RECT  66.708 21.389 72.81 22.219 ;
     RECT  48.42 22.199 49.266 22.235 ;
     RECT  21.456 22.199 34.938 22.271 ;
     RECT  14.256 21.659 15.57 22.343 ;
     RECT  36.18 21.629 38.502 22.351 ;
     RECT  50.436 22.109 51.714 22.351 ;
     RECT  52.452 22.171 55.638 22.351 ;
     RECT  41.328 22.171 44.802 22.469 ;
     RECT  63.54 22.219 72.81 22.469 ;
     RECT  41.328 22.469 43.938 22.493 ;
     RECT  66.384 22.469 72.81 22.505 ;
     RECT  36.18 22.351 38.754 22.507 ;
     RECT  50.436 22.351 55.638 22.549 ;
     RECT  56.448 21.581 56.898 22.549 ;
     RECT  32.184 22.271 34.938 22.621 ;
     RECT  36.18 22.507 39.186 22.621 ;
     RECT  58.68 22.549 58.698 22.621 ;
     RECT  63.54 22.469 65.574 22.621 ;
     RECT  32.184 22.621 39.186 22.637 ;
     RECT  50.436 22.549 56.898 22.649 ;
     RECT  58.68 22.621 58.734 22.649 ;
     RECT  62.136 21.299 62.154 22.651 ;
     RECT  63.072 22.621 65.574 22.651 ;
     RECT  50.436 22.649 55.818 22.739 ;
     RECT  56.556 22.649 56.898 22.739 ;
     RECT  66.6 22.505 72.81 22.739 ;
     RECT  58.716 22.649 58.734 22.775 ;
     RECT  32.184 22.637 39.114 22.781 ;
     RECT  12.132 21.929 12.762 22.795 ;
     RECT  46.764 22.199 47.286 22.811 ;
     RECT  50.436 22.739 54.954 22.811 ;
     RECT  0.036 21.929 11.337 22.843 ;
     RECT  12.132 22.795 13.014 22.843 ;
     RECT  19.152 21.437 20.214 22.843 ;
     RECT  56.7 22.739 56.898 22.855 ;
     RECT  57.744 21.581 57.762 22.855 ;
     RECT  16.455 21.659 18.306 22.939 ;
     RECT  19.152 22.843 20.682 22.939 ;
     RECT  0.036 22.843 13.014 22.973 ;
     RECT  48.456 22.235 49.266 22.981 ;
     RECT  66.708 22.739 72.81 22.981 ;
     RECT  16.455 22.939 20.682 23.009 ;
     RECT  48.024 22.981 49.266 23.035 ;
     RECT  50.436 22.811 51.39 23.035 ;
     RECT  56.7 22.855 57.762 23.045 ;
     RECT  48.024 23.035 51.39 23.069 ;
     RECT  48.384 23.069 51.39 23.081 ;
     RECT  66.708 22.981 72.918 23.081 ;
     RECT  46.908 22.811 47.286 23.125 ;
     RECT  21.456 22.271 31.338 23.131 ;
     RECT  32.184 22.781 39.042 23.131 ;
     RECT  12.096 22.973 13.014 23.161 ;
     RECT  50.364 23.081 51.39 23.165 ;
     RECT  46.908 23.125 47.574 23.279 ;
     RECT  66.708 23.081 66.762 23.279 ;
     RECT  16.455 23.009 20.322 23.357 ;
     RECT  59.58 21.569 59.937 23.359 ;
     RECT  62.136 22.651 65.574 23.359 ;
     RECT  57.744 23.045 57.762 23.431 ;
     RECT  14.544 22.343 15.57 23.512 ;
     RECT  57.744 23.431 58.374 23.521 ;
     RECT  59.112 23.359 59.937 23.521 ;
     RECT  50.364 23.165 51.354 23.549 ;
     RECT  62.136 23.359 65.646 23.593 ;
     RECT  41.328 22.493 43.737 23.611 ;
     RECT  52.2 22.811 54.954 23.621 ;
     RECT  44.784 22.469 44.802 23.629 ;
     RECT  12.096 23.161 13.086 23.657 ;
     RECT  21.456 23.131 39.042 23.659 ;
     RECT  12.132 23.657 13.086 23.665 ;
     RECT  14.04 23.512 15.57 23.665 ;
     RECT  45.54 23.557 45.558 23.665 ;
     RECT  52.2 23.621 53.37 23.665 ;
     RECT  21.456 23.659 39.222 23.693 ;
     RECT  44.748 23.629 44.802 23.701 ;
     RECT  45.54 23.665 45.594 23.701 ;
     RECT  44.748 23.701 45.594 23.707 ;
     RECT  57.744 23.521 59.937 23.741 ;
     RECT  41.004 23.611 43.737 23.791 ;
     RECT  46.8 23.629 46.818 23.819 ;
     RECT  48.384 23.081 49.41 23.819 ;
     RECT  36.864 23.693 39.222 23.827 ;
     RECT  0.036 22.973 11.337 23.837 ;
     RECT  21.456 23.693 35.622 23.837 ;
     RECT  44.532 23.707 45.594 23.855 ;
     RECT  62.136 23.593 66.15 23.891 ;
     RECT  44.784 23.855 45.594 23.927 ;
     RECT  62.136 23.891 63.702 23.933 ;
     RECT  50.436 23.549 51.354 23.971 ;
     RECT  52.128 23.665 53.37 23.971 ;
     RECT  58.716 23.741 59.937 23.971 ;
     RECT  60.876 21.659 60.894 23.971 ;
     RECT  0.036 23.837 4.554 23.981 ;
     RECT  50.436 23.971 53.37 23.999 ;
     RECT  56.7 23.045 56.898 23.999 ;
     RECT  17.568 23.357 20.322 24.089 ;
     RECT  51.588 23.999 53.37 24.089 ;
     RECT  40.968 23.791 43.737 24.097 ;
     RECT  56.7 23.999 56.718 24.097 ;
     RECT  51.696 24.089 53.37 24.125 ;
     RECT  64.476 23.891 66.15 24.161 ;
     RECT  64.548 24.161 66.15 24.169 ;
     RECT  5.328 23.837 11.337 24.173 ;
     RECT  18.288 24.089 20.322 24.241 ;
     RECT  21.456 23.837 31.374 24.241 ;
     RECT  44.784 23.927 44.802 24.269 ;
     RECT  58.716 23.971 60.894 24.269 ;
     RECT  45.612 23.971 45.81 24.317 ;
     RECT  48.384 23.819 49.374 24.359 ;
     RECT  60.876 24.269 60.894 24.359 ;
     RECT  40.536 24.097 43.737 24.395 ;
     RECT  36.864 23.827 39.69 24.431 ;
     RECT  32.184 23.837 35.622 24.467 ;
     RECT  61.092 24.427 61.11 24.467 ;
     RECT  40.536 24.395 40.554 24.503 ;
     RECT  46.764 24.133 46.782 24.503 ;
     RECT  48.855 24.359 49.374 24.503 ;
     RECT  17.46 24.241 17.478 24.509 ;
     RECT  54.255 23.621 54.954 24.511 ;
     RECT  56.52 24.097 56.718 24.511 ;
     RECT  58.716 24.269 60.102 24.512 ;
     RECT  57.744 23.741 57.762 24.523 ;
     RECT  18.288 24.241 31.374 24.539 ;
     RECT  55.908 24.511 56.718 24.571 ;
     RECT  52.272 24.125 53.37 24.601 ;
     RECT  54.216 24.511 54.954 24.601 ;
     RECT  55.836 24.571 56.718 24.601 ;
     RECT  18.288 24.539 31.194 24.629 ;
     RECT  5.328 24.173 6.246 24.637 ;
     RECT  32.184 24.467 34.938 24.665 ;
     RECT  47.556 23.279 47.574 24.709 ;
     RECT  50.436 23.999 50.814 24.715 ;
     RECT  5.04 24.637 6.246 24.737 ;
     RECT  49.896 24.715 50.814 24.745 ;
     RECT  57.744 24.523 57.978 24.745 ;
     RECT  58.716 24.512 60.066 24.745 ;
     RECT  46.152 24.667 46.71 24.773 ;
     RECT  32.184 24.665 34.614 24.781 ;
     RECT  52.272 24.601 56.718 24.859 ;
     RECT  64.548 24.169 66.798 24.871 ;
     RECT  67.536 23.081 72.918 24.871 ;
     RECT  49.896 24.745 50.886 24.899 ;
     RECT  52.272 24.859 56.97 24.899 ;
     RECT  5.112 24.737 6.246 24.907 ;
     RECT  7.164 24.173 11.337 24.907 ;
     RECT  62.604 23.933 63.702 24.907 ;
     RECT  64.548 24.871 72.918 24.907 ;
     RECT  41.328 24.395 43.737 24.935 ;
     RECT  56.52 24.899 56.97 24.935 ;
     RECT  5.112 24.907 11.337 24.971 ;
     RECT  31.932 24.781 34.614 25.037 ;
     RECT  47.556 24.709 47.826 25.043 ;
     RECT  57.744 24.745 60.066 25.043 ;
     RECT  62.604 24.907 72.918 25.051 ;
     RECT  18.288 24.629 31.122 25.079 ;
     RECT  56.52 24.935 56.826 25.079 ;
     RECT  57.744 25.043 57.978 25.079 ;
     RECT  62.604 25.051 72.954 25.079 ;
     RECT  0.036 23.981 4.266 25.099 ;
     RECT  39.168 24.431 39.69 25.099 ;
     RECT  50.436 24.899 50.886 25.099 ;
     RECT  48.855 24.503 49.137 25.141 ;
     RECT  62.604 25.079 65.337 25.141 ;
     RECT  18.288 25.079 25.29 25.213 ;
     RECT  16.455 23.357 16.737 25.249 ;
     RECT  17.64 25.213 25.29 25.277 ;
     RECT  12.132 23.665 15.57 25.291 ;
     RECT  16.38 25.249 16.737 25.291 ;
     RECT  5.148 24.971 11.337 25.321 ;
     RECT  58.716 25.043 60.066 25.321 ;
     RECT  0.036 25.099 4.374 25.439 ;
     RECT  26.028 25.079 31.122 25.439 ;
     RECT  39.168 25.099 40.122 25.439 ;
     RECT  58.716 25.321 60.138 25.439 ;
     RECT  62.388 25.141 65.337 25.439 ;
     RECT  48.6 25.141 49.137 25.469 ;
     RECT  26.244 25.439 31.122 25.517 ;
     RECT  62.496 25.439 65.337 25.565 ;
     RECT  62.604 25.565 65.337 25.619 ;
     RECT  66.132 25.079 72.954 25.619 ;
     RECT  12.132 25.291 16.737 25.672 ;
     RECT  17.64 25.277 24.21 25.672 ;
     RECT  52.272 24.899 55.674 25.681 ;
     RECT  56.52 25.079 56.754 25.681 ;
     RECT  12.132 25.672 24.21 25.709 ;
     RECT  57.744 25.079 57.762 25.709 ;
     RECT  45.036 25.447 45.054 25.717 ;
     RECT  52.272 25.681 56.754 25.717 ;
     RECT  5.148 25.321 11.394 25.789 ;
     RECT  12.132 25.709 16.794 25.789 ;
     RECT  48.78 25.469 49.137 25.789 ;
     RECT  50.436 25.099 51.462 25.789 ;
     RECT  52.236 25.717 56.754 25.789 ;
     RECT  26.532 25.517 31.122 25.861 ;
     RECT  48.78 25.789 56.754 25.861 ;
     RECT  63.576 25.619 65.337 25.889 ;
     RECT  26.532 25.861 31.194 25.915 ;
     RECT  31.968 25.037 34.614 25.915 ;
     RECT  26.532 25.915 34.614 25.979 ;
     RECT  48.78 25.861 57.222 25.979 ;
     RECT  66.132 25.619 66.69 26.015 ;
     RECT  5.148 25.789 16.794 26.051 ;
     RECT  45.036 25.717 45.162 26.051 ;
     RECT  17.712 25.709 24.21 26.059 ;
     RECT  47.556 25.043 47.574 26.059 ;
     RECT  47.556 26.059 47.826 26.096 ;
     RECT  31.104 25.979 34.614 26.159 ;
     RECT  48.78 25.979 57.15 26.159 ;
     RECT  45.036 26.051 45.126 26.189 ;
     RECT  0.036 25.439 4.23 26.221 ;
     RECT  5.148 26.051 15.57 26.221 ;
     RECT  58.824 25.439 60.138 26.221 ;
     RECT  48.855 26.159 57.15 26.249 ;
     RECT  58.5 26.221 60.138 26.251 ;
     RECT  0.036 26.221 15.57 26.285 ;
     RECT  58.5 26.251 60.174 26.293 ;
     RECT  58.5 26.293 60.606 26.357 ;
     RECT  25.272 25.277 25.29 26.365 ;
     RECT  31.896 26.159 34.614 26.365 ;
     RECT  25.272 26.365 25.362 26.393 ;
     RECT  53.676 26.249 57.114 26.393 ;
     RECT  58.572 26.357 60.606 26.393 ;
     RECT  53.748 26.393 57.114 26.477 ;
     RECT  36.864 24.431 38.337 26.491 ;
     RECT  8.712 26.285 13.698 26.519 ;
     RECT  31.896 26.365 34.866 26.519 ;
     RECT  62.604 25.619 62.694 26.519 ;
     RECT  36.756 26.491 38.337 26.555 ;
     RECT  58.572 26.393 60.534 26.555 ;
     RECT  48.855 26.249 52.938 26.591 ;
     RECT  26.532 25.979 30.366 26.599 ;
     RECT  58.68 26.555 60.534 26.627 ;
     RECT  63.576 25.889 63.702 26.635 ;
     RECT  17.712 26.059 24.498 26.663 ;
     RECT  8.748 26.519 13.698 26.669 ;
     RECT  18.252 26.663 24.39 26.669 ;
     RECT  64.656 25.889 65.337 26.671 ;
     RECT  66.132 26.015 66.33 26.671 ;
     RECT  18.252 26.669 23.958 26.699 ;
     RECT  50.436 26.591 52.938 26.699 ;
     RECT  61.488 26.671 61.506 26.731 ;
     RECT  18.432 26.699 23.958 26.789 ;
     RECT  45.108 26.189 45.126 26.789 ;
     RECT  16.38 26.051 16.794 26.797 ;
     RECT  41.328 24.935 42.57 26.797 ;
     RECT  63.432 26.635 63.702 26.797 ;
     RECT  64.656 26.671 66.33 26.797 ;
     RECT  26.316 26.599 30.366 26.827 ;
     RECT  31.104 26.159 31.122 26.827 ;
     RECT  46.152 24.773 46.17 26.827 ;
     RECT  67.428 25.619 72.954 26.905 ;
     RECT  16.38 26.797 16.866 26.923 ;
     RECT  32.04 26.519 34.866 26.941 ;
     RECT  36.864 26.555 38.337 26.941 ;
     RECT  39.168 25.439 39.69 26.941 ;
     RECT  64.548 26.797 66.33 27.031 ;
     RECT  0.036 26.285 7.938 27.059 ;
     RECT  50.436 26.699 52.83 27.059 ;
     RECT  64.548 27.031 66.474 27.067 ;
     RECT  67.212 26.905 72.954 27.095 ;
     RECT  16.38 26.923 16.938 27.103 ;
     RECT  62.712 26.797 63.702 27.103 ;
     RECT  64.512 27.067 66.474 27.103 ;
     RECT  26.316 26.827 31.122 27.139 ;
     RECT  40.644 26.797 42.57 27.205 ;
     RECT  43.455 24.935 43.737 27.205 ;
     RECT  5.148 27.059 7.938 27.211 ;
     RECT  32.04 26.941 35.01 27.211 ;
     RECT  45.432 26.827 46.17 27.211 ;
     RECT  54.255 26.477 57.114 27.211 ;
     RECT  58.716 26.627 60.534 27.211 ;
     RECT  61.488 26.731 61.614 27.211 ;
     RECT  62.712 27.103 66.474 27.211 ;
     RECT  67.212 27.095 67.662 27.211 ;
     RECT  51.624 27.059 52.218 27.239 ;
     RECT  58.716 27.211 61.938 27.239 ;
     RECT  62.712 27.211 67.662 27.239 ;
     RECT  40.644 27.205 43.737 27.245 ;
     RECT  36.864 26.941 39.69 27.301 ;
     RECT  40.644 27.245 42.57 27.301 ;
     RECT  59.655 27.239 61.938 27.301 ;
     RECT  62.712 27.239 66.222 27.301 ;
     RECT  32.04 27.211 35.046 27.329 ;
     RECT  36.864 27.301 42.57 27.329 ;
     RECT  45.432 27.211 46.818 27.329 ;
     RECT  53.568 27.211 57.15 27.329 ;
     RECT  67.176 27.239 67.662 27.329 ;
     RECT  32.04 27.329 34.974 27.341 ;
     RECT  36.864 27.329 40.086 27.341 ;
     RECT  59.655 27.301 66.222 27.341 ;
     RECT  45.828 27.329 46.818 27.365 ;
     RECT  53.64 27.329 55.674 27.365 ;
     RECT  62.604 27.341 66.222 27.365 ;
     RECT  43.455 27.245 43.737 27.409 ;
     RECT  59.655 27.341 61.794 27.473 ;
     RECT  8.748 26.669 9.162 27.485 ;
     RECT  25.344 26.393 25.362 27.499 ;
     RECT  26.1 27.139 31.122 27.499 ;
     RECT  58.716 27.239 58.914 27.595 ;
     RECT  61.524 27.473 61.794 27.599 ;
     RECT  18.432 26.789 23.85 27.607 ;
     RECT  25.344 27.499 31.122 27.629 ;
     RECT  41.04 27.329 42.57 27.635 ;
     RECT  43.455 27.409 43.794 27.635 ;
     RECT  58.644 27.595 58.914 27.635 ;
     RECT  14.544 26.285 15.57 27.679 ;
     RECT  16.38 27.103 17.082 27.679 ;
     RECT  5.148 27.211 7.974 27.68 ;
     RECT  26.28 27.629 31.122 27.707 ;
     RECT  64.656 27.365 66.222 27.707 ;
     RECT  26.928 27.707 31.122 27.751 ;
     RECT  61.524 27.599 61.686 27.779 ;
     RECT  18.252 27.607 23.85 27.841 ;
     RECT  26.928 27.751 31.194 27.869 ;
     RECT  39.672 27.341 40.086 27.869 ;
     RECT  62.604 27.365 63.882 27.875 ;
     RECT  18.252 27.841 23.958 27.913 ;
     RECT  27.216 27.869 31.194 27.917 ;
     RECT  48.855 26.591 49.137 27.931 ;
     RECT  9.9 26.669 13.698 27.941 ;
     RECT  27.255 27.917 31.194 27.941 ;
     RECT  32.04 27.341 34.794 27.941 ;
     RECT  45.828 27.365 46.278 27.941 ;
     RECT  12.528 27.941 13.698 28.021 ;
     RECT  58.752 27.635 58.914 28.075 ;
     RECT  59.655 27.473 60.498 28.075 ;
     RECT  48.855 27.931 49.662 28.139 ;
     RECT  53.676 27.365 55.674 28.147 ;
     RECT  56.412 27.329 57.114 28.147 ;
     RECT  34.56 27.941 34.794 28.219 ;
     RECT  63.612 27.875 63.882 28.255 ;
     RECT  64.656 27.707 65.502 28.255 ;
     RECT  34.56 28.219 34.938 28.267 ;
     RECT  47.556 26.096 47.574 28.267 ;
     RECT  5.148 27.68 6.354 28.291 ;
     RECT  50.436 27.059 50.67 28.291 ;
     RECT  7.164 27.68 7.974 28.301 ;
     RECT  36.864 27.341 38.934 28.301 ;
     RECT  5.04 28.291 6.354 28.319 ;
     RECT  47.556 28.267 47.862 28.319 ;
     RECT  53.676 28.147 57.114 28.319 ;
     RECT  43.455 27.635 43.737 28.363 ;
     RECT  47.556 28.319 47.574 28.363 ;
     RECT  36.864 28.301 38.898 28.381 ;
     RECT  5.04 28.319 6.246 28.409 ;
     RECT  54.255 28.319 57.114 28.409 ;
     RECT  58.752 28.075 60.498 28.411 ;
     RECT  34.56 28.267 35.01 28.445 ;
     RECT  36.504 28.381 38.898 28.445 ;
     RECT  63.612 28.255 65.502 28.445 ;
     RECT  0.036 27.059 4.266 28.453 ;
     RECT  18.252 27.913 24.174 28.453 ;
     RECT  5.256 28.409 6.246 28.481 ;
     RECT  36.864 28.445 38.898 28.481 ;
     RECT  50.436 28.291 50.706 28.481 ;
     RECT  17.928 28.453 24.174 28.507 ;
     RECT  32.04 27.941 33.75 28.507 ;
     RECT  63.612 28.445 63.882 28.553 ;
     RECT  55.548 28.409 55.674 28.589 ;
     RECT  58.716 28.411 60.498 28.651 ;
     RECT  61.524 27.779 61.542 28.651 ;
     RECT  47.052 28.363 47.574 28.679 ;
     RECT  52.2 27.239 52.218 28.687 ;
     RECT  51.768 28.687 52.218 28.733 ;
     RECT  62.604 27.875 62.694 28.751 ;
     RECT  27.255 27.941 30.87 28.795 ;
     RECT  52.2 28.733 52.218 28.831 ;
     RECT  25.344 27.629 25.362 28.859 ;
     RECT  47.556 28.679 47.574 28.859 ;
     RECT  66.708 28.561 66.726 28.859 ;
     RECT  26.784 28.795 30.87 28.877 ;
     RECT  17.892 28.507 24.174 28.921 ;
     RECT  29.916 28.877 30.87 28.921 ;
     RECT  41.04 27.635 41.706 28.921 ;
     RECT  62.676 28.751 62.694 28.921 ;
     RECT  32.004 28.507 33.75 28.939 ;
     RECT  17.892 28.921 24.93 28.949 ;
     RECT  68.4 27.095 72.954 28.985 ;
     RECT  46.152 27.941 46.206 28.987 ;
     RECT  29.916 28.921 30.942 28.993 ;
     RECT  17.928 28.949 24.93 29.021 ;
     RECT  26.784 28.877 29.178 29.021 ;
     RECT  52.2 28.831 52.722 29.021 ;
     RECT  58.716 28.651 61.542 29.021 ;
     RECT  9.9 27.941 11.754 29.029 ;
     RECT  12.528 28.021 13.77 29.029 ;
     RECT  66.816 28.921 66.834 29.057 ;
     RECT  69.516 28.985 72.954 29.057 ;
     RECT  29.916 28.993 31.086 29.069 ;
     RECT  31.968 28.939 33.75 29.069 ;
     RECT  40.716 28.921 41.706 29.069 ;
     RECT  41.328 29.069 41.706 29.083 ;
     RECT  42.444 27.635 42.57 29.083 ;
     RECT  46.152 28.987 46.782 29.117 ;
     RECT  68.4 28.985 68.742 29.129 ;
     RECT  48.855 28.139 49.137 29.191 ;
     RECT  58.716 29.021 60.498 29.191 ;
     RECT  47.592 29.179 47.61 29.219 ;
     RECT  43.455 28.363 43.83 29.291 ;
     RECT  44.604 29.191 44.622 29.291 ;
     RECT  58.68 29.191 60.498 29.291 ;
     RECT  7.164 28.301 7.938 29.299 ;
     RECT  8.748 27.485 8.766 29.299 ;
     RECT  67.572 27.329 67.662 29.299 ;
     RECT  68.4 29.129 68.706 29.299 ;
     RECT  56.412 28.409 57.114 29.323 ;
     RECT  27.255 29.021 29.178 29.363 ;
     RECT  54.255 28.409 54.738 29.363 ;
     RECT  5.292 28.481 6.246 29.371 ;
     RECT  7.164 29.299 8.766 29.371 ;
     RECT  9.9 29.029 13.77 29.371 ;
     RECT  14.544 27.679 17.082 29.371 ;
     RECT  56.412 29.323 57.618 29.399 ;
     RECT  44.568 29.371 44.586 29.408 ;
     RECT  62.676 28.921 62.802 29.461 ;
     RECT  63.612 28.553 63.63 29.461 ;
     RECT  5.292 29.371 17.082 29.489 ;
     RECT  5.292 29.489 7.974 29.501 ;
     RECT  62.676 29.461 63.63 29.501 ;
     RECT  43.455 29.291 43.794 29.515 ;
     RECT  43.344 29.515 43.794 29.549 ;
     RECT  48.42 29.191 49.137 29.563 ;
     RECT  62.676 29.501 62.802 29.605 ;
     RECT  0.036 28.453 4.302 29.641 ;
     RECT  41.328 29.083 42.57 29.641 ;
     RECT  50.436 28.481 50.67 29.641 ;
     RECT  50.436 29.641 50.814 29.759 ;
     RECT  58.716 29.291 60.498 29.759 ;
     RECT  65.055 28.445 65.502 29.767 ;
     RECT  46.152 29.117 46.17 29.795 ;
     RECT  50.436 29.759 50.67 29.795 ;
     RECT  64.872 29.767 65.502 29.837 ;
     RECT  8.748 29.489 17.082 29.885 ;
     RECT  59.655 29.759 60.498 29.899 ;
     RECT  61.524 29.021 61.542 29.899 ;
     RECT  8.748 29.885 11.754 29.903 ;
     RECT  52.2 29.021 52.218 29.911 ;
     RECT  63.612 29.501 63.63 29.911 ;
     RECT  51.516 29.911 52.218 29.981 ;
     RECT  63.612 29.911 63.954 29.981 ;
     RECT  17.928 29.021 24.174 30.029 ;
     RECT  47.772 29.563 49.137 30.029 ;
     RECT  51.588 29.981 52.218 30.029 ;
     RECT  34.56 28.445 34.614 30.091 ;
     RECT  58.716 29.759 58.734 30.101 ;
     RECT  66.708 29.875 66.726 30.101 ;
     RECT  0.036 29.641 4.518 30.145 ;
     RECT  5.292 29.501 7.938 30.145 ;
     RECT  28.404 29.363 29.178 30.173 ;
     RECT  32.04 29.069 33.75 30.181 ;
     RECT  34.56 30.091 35.298 30.181 ;
     RECT  41.328 29.641 42.606 30.181 ;
     RECT  32.04 30.181 35.298 30.209 ;
     RECT  41.148 30.181 42.606 30.209 ;
     RECT  41.148 30.209 41.706 30.221 ;
     RECT  48.744 30.029 49.137 30.221 ;
     RECT  12.636 29.885 17.082 30.235 ;
     RECT  17.928 30.029 20.574 30.235 ;
     RECT  27.255 29.363 27.537 30.271 ;
     RECT  46.26 29.911 46.278 30.271 ;
     RECT  56.412 29.399 57.114 30.271 ;
     RECT  27.255 30.271 27.63 30.283 ;
     RECT  12.636 30.235 20.574 30.299 ;
     RECT  46.26 30.271 46.458 30.299 ;
     RECT  59.655 29.899 61.542 30.307 ;
     RECT  62.46 29.605 62.802 30.307 ;
     RECT  46.44 30.299 46.458 30.317 ;
     RECT  24.912 29.911 24.93 30.343 ;
     RECT  29.916 29.069 30.366 30.343 ;
     RECT  42.444 30.209 42.606 30.343 ;
     RECT  43.344 29.549 43.737 30.343 ;
     RECT  26.82 30.283 27.63 30.365 ;
     RECT  45.504 30.307 45.522 30.365 ;
     RECT  56.412 30.271 57.834 30.371 ;
     RECT  59.655 30.307 62.802 30.407 ;
     RECT  26.064 30.283 26.082 30.415 ;
     RECT  26.82 30.365 27.537 30.415 ;
     RECT  28.908 30.173 29.178 30.479 ;
     RECT  21.348 30.029 24.174 30.509 ;
     RECT  35.928 30.523 35.946 30.541 ;
     RECT  26.064 30.415 27.537 30.569 ;
     RECT  29.916 30.343 31.05 30.569 ;
     RECT  35.928 30.541 36.054 30.569 ;
     RECT  42.444 30.343 43.737 30.569 ;
     RECT  46.476 30.343 46.494 30.569 ;
     RECT  36.036 30.569 36.054 30.605 ;
     RECT  60.984 30.407 62.802 30.605 ;
     RECT  67.572 29.299 68.706 30.613 ;
     RECT  69.516 29.057 72.846 30.613 ;
     RECT  12.78 30.299 20.574 30.641 ;
     RECT  67.572 30.613 72.846 30.653 ;
     RECT  32.04 30.209 34.794 30.677 ;
     RECT  50.724 30.541 50.742 30.677 ;
     RECT  37.08 28.481 38.898 30.685 ;
     RECT  55.656 28.589 55.674 30.713 ;
     RECT  60.984 30.605 61.614 30.713 ;
     RECT  62.46 30.605 62.802 30.713 ;
     RECT  24.912 30.343 24.966 30.721 ;
     RECT  32.04 30.677 34.686 30.721 ;
     RECT  62.712 30.713 62.802 30.721 ;
     RECT  63.612 29.981 63.63 30.721 ;
     RECT  67.572 30.653 68.706 30.721 ;
     RECT  36.864 30.685 38.898 30.749 ;
     RECT  61.596 30.713 61.614 30.749 ;
     RECT  14.688 30.641 20.574 30.811 ;
     RECT  21.348 30.509 23.742 30.811 ;
     RECT  37.332 30.749 38.898 30.811 ;
     RECT  39.672 27.869 39.69 30.811 ;
     RECT  43.455 30.569 43.737 30.811 ;
     RECT  69.516 30.653 72.846 30.839 ;
     RECT  52.2 30.029 52.218 30.847 ;
     RECT  44.712 30.811 44.73 30.848 ;
     RECT  29.916 30.569 31.014 30.875 ;
     RECT  43.455 30.811 43.794 30.875 ;
     RECT  67.536 30.721 68.706 30.875 ;
     RECT  37.332 30.811 39.69 30.911 ;
     RECT  67.572 30.875 68.706 30.911 ;
     RECT  51.912 30.847 52.218 30.955 ;
     RECT  45.396 30.907 45.414 30.983 ;
     RECT  0.036 30.145 7.938 30.991 ;
     RECT  50.904 30.847 50.922 30.991 ;
     RECT  51.732 30.955 52.218 30.991 ;
     RECT  54.255 29.363 54.537 30.991 ;
     RECT  50.904 30.991 53.19 31.019 ;
     RECT  24.552 30.721 24.966 31.051 ;
     RECT  66.708 30.991 66.726 31.109 ;
     RECT  69.804 30.839 72.846 31.109 ;
     RECT  14.688 30.811 23.742 31.133 ;
     RECT  50.904 31.019 51.03 31.181 ;
     RECT  52.2 31.019 53.19 31.289 ;
     RECT  31.968 30.721 34.686 31.325 ;
     RECT  24.552 31.051 25.002 31.351 ;
     RECT  26.892 30.569 27.537 31.351 ;
     RECT  41.688 30.221 41.706 31.351 ;
     RECT  42.444 30.569 42.462 31.351 ;
     RECT  56.412 30.371 57.114 31.381 ;
     RECT  41.688 31.351 42.462 31.421 ;
     RECT  56.304 31.381 57.114 31.421 ;
     RECT  42.444 31.421 42.462 31.451 ;
     RECT  12.78 30.641 13.806 31.487 ;
     RECT  26.46 31.351 27.537 31.487 ;
     RECT  31.968 31.325 33.75 31.523 ;
     RECT  18.828 31.133 23.742 31.525 ;
     RECT  24.516 31.351 25.002 31.525 ;
     RECT  9.396 29.903 11.754 31.531 ;
     RECT  18.828 31.525 25.002 31.531 ;
     RECT  32.184 31.523 33.75 31.559 ;
     RECT  29.916 30.875 30.906 31.621 ;
     RECT  26.316 31.531 26.334 31.649 ;
     RECT  0.036 30.991 8.586 31.657 ;
     RECT  9.396 31.531 12.222 31.657 ;
     RECT  41.688 31.421 41.706 31.657 ;
     RECT  18.828 31.531 25.578 31.661 ;
     RECT  18.936 31.661 25.578 31.765 ;
     RECT  0.036 31.657 12.222 31.793 ;
     RECT  27.072 31.487 27.537 31.793 ;
     RECT  48.855 30.221 49.137 31.801 ;
     RECT  54.255 30.991 54.702 31.801 ;
     RECT  18.936 31.765 26.118 31.805 ;
     RECT  14.688 31.133 17.982 31.829 ;
     RECT  52.2 31.289 52.218 31.829 ;
     RECT  62.712 30.721 63.63 31.829 ;
     RECT  48.855 31.801 49.734 31.867 ;
     RECT  50.904 31.181 50.922 31.867 ;
     RECT  18.936 31.805 25.578 31.901 ;
     RECT  29.916 31.621 30.942 31.919 ;
     RECT  48.855 31.867 50.922 31.919 ;
     RECT  54.255 31.801 54.954 31.919 ;
     RECT  48.855 31.919 49.518 31.997 ;
     RECT  29.16 30.479 29.178 32.011 ;
     RECT  29.916 31.919 29.934 32.011 ;
     RECT  18.936 31.901 24.534 32.099 ;
     RECT  9.396 31.793 12.222 32.189 ;
     RECT  22.932 32.099 24.534 32.189 ;
     RECT  24.516 32.189 24.534 32.237 ;
     RECT  30.888 31.919 30.942 32.269 ;
     RECT  32.655 31.559 33.75 32.297 ;
     RECT  32.655 32.297 32.937 32.341 ;
     RECT  69.804 31.109 70.737 32.341 ;
     RECT  71.46 31.109 72.846 32.341 ;
     RECT  29.16 32.011 29.934 32.369 ;
     RECT  30.888 32.269 31.626 32.459 ;
     RECT  32.364 32.341 32.937 32.459 ;
     RECT  30.888 32.459 31.446 32.477 ;
     RECT  69.804 32.341 72.846 32.495 ;
     RECT  63.612 31.829 63.63 32.539 ;
     RECT  50.904 31.919 50.922 32.575 ;
     RECT  69.804 32.495 70.737 32.639 ;
     RECT  53.172 31.289 53.19 32.701 ;
     RECT  54.255 31.919 54.594 32.701 ;
     RECT  30.888 32.477 30.906 32.729 ;
     RECT  51.912 32.587 51.93 32.729 ;
     RECT  53.172 32.701 54.594 32.765 ;
     RECT  71.46 32.495 72.846 32.765 ;
     RECT  48.855 31.997 49.137 32.809 ;
     RECT  50.904 32.575 51.174 32.809 ;
     RECT  63.612 32.539 63.702 32.827 ;
     RECT  54.255 32.765 54.594 32.837 ;
     RECT  13.392 31.487 13.806 32.845 ;
     RECT  63.612 32.827 63.918 32.873 ;
     RECT  34.56 31.325 34.686 32.881 ;
     RECT  37.332 30.911 38.337 32.881 ;
     RECT  55.692 32.071 55.71 32.881 ;
     RECT  55.692 32.881 55.782 32.909 ;
     RECT  13.248 32.845 13.806 32.923 ;
     RECT  14.688 31.829 15.498 32.923 ;
     RECT  27.255 31.793 27.537 32.923 ;
     RECT  18.936 32.099 22.137 32.957 ;
     RECT  29.16 32.369 29.466 32.957 ;
     RECT  50.904 32.809 51.894 32.957 ;
     RECT  10.656 32.189 12.222 32.971 ;
     RECT  48.492 32.809 49.137 32.971 ;
     RECT  58.824 32.539 58.842 32.971 ;
     RECT  59.655 30.407 59.937 32.971 ;
     RECT  26.64 32.923 27.537 32.999 ;
     RECT  51.156 32.957 51.894 32.999 ;
     RECT  55.764 32.909 55.782 32.999 ;
     RECT  58.824 32.971 59.937 32.999 ;
     RECT  26.748 32.999 27.537 33.005 ;
     RECT  9.396 32.189 9.918 33.007 ;
     RECT  10.656 32.971 12.258 33.007 ;
     RECT  58.932 32.999 59.937 33.008 ;
     RECT  51.156 32.999 51.282 33.035 ;
     RECT  0.036 31.793 8.622 33.043 ;
     RECT  9.396 33.007 12.258 33.043 ;
     RECT  41.076 31.657 41.706 33.043 ;
     RECT  0.036 33.043 12.258 33.053 ;
     RECT  18.936 32.957 20.07 33.053 ;
     RECT  53.172 32.765 53.514 33.053 ;
     RECT  37.332 32.881 38.718 33.071 ;
     RECT  32.655 32.459 32.937 33.115 ;
     RECT  33.732 32.297 33.75 33.115 ;
     RECT  0.036 33.053 12.222 33.143 ;
     RECT  34.56 32.881 34.794 33.163 ;
     RECT  41.004 33.043 41.706 33.179 ;
     RECT  68.22 30.911 68.706 33.211 ;
     RECT  13.248 32.923 15.498 33.269 ;
     RECT  34.56 33.163 35.298 33.269 ;
     RECT  50.04 33.115 50.058 33.269 ;
     RECT  68.04 33.211 68.994 33.269 ;
     RECT  20.808 32.957 22.137 33.293 ;
     RECT  18.936 33.053 19.854 33.307 ;
     RECT  37.332 33.071 38.682 33.341 ;
     RECT  39.492 30.911 39.69 33.355 ;
     RECT  39.456 33.355 39.69 33.421 ;
     RECT  66.348 33.349 66.366 33.421 ;
     RECT  0.036 33.143 9.954 33.449 ;
     RECT  70.128 32.639 70.737 33.449 ;
     RECT  32.655 33.115 33.75 33.511 ;
     RECT  34.56 33.269 34.794 33.511 ;
     RECT  66.276 33.421 66.366 33.539 ;
     RECT  65.055 29.837 65.502 33.547 ;
     RECT  71.568 32.765 72.846 33.575 ;
     RECT  62.712 33.349 62.73 33.611 ;
     RECT  66.348 33.539 66.366 33.611 ;
     RECT  70.2 33.449 70.737 33.611 ;
     RECT  71.568 33.575 71.802 33.611 ;
     RECT  72.828 33.575 72.846 33.611 ;
     RECT  20.916 33.293 22.137 33.691 ;
     RECT  22.932 32.189 23.742 33.691 ;
     RECT  70.455 33.611 70.737 33.691 ;
     RECT  51.264 33.035 51.282 33.781 ;
     RECT  8.568 33.449 9.954 33.809 ;
     RECT  27.255 33.005 27.537 33.835 ;
     RECT  8.568 33.809 8.622 33.845 ;
     RECT  18.72 33.307 19.854 33.845 ;
     RECT  51.264 33.781 51.39 33.869 ;
     RECT  11.055 33.143 12.222 33.883 ;
     RECT  51.264 33.869 51.282 33.917 ;
     RECT  37.836 33.341 38.682 33.931 ;
     RECT  39.456 33.421 39.906 33.931 ;
     RECT  9.396 33.809 9.954 33.961 ;
     RECT  26.784 33.835 27.537 33.965 ;
     RECT  30.78 33.835 30.798 33.965 ;
     RECT  32.655 33.511 34.794 33.965 ;
     RECT  10.836 33.883 12.222 33.989 ;
     RECT  16.38 31.829 17.982 34.051 ;
     RECT  18.72 33.845 19.602 34.051 ;
     RECT  9.396 33.961 10.062 34.079 ;
     RECT  37.836 33.931 39.906 34.079 ;
     RECT  39.492 34.079 39.906 34.151 ;
     RECT  11.055 33.989 12.222 34.187 ;
     RECT  16.38 34.051 19.602 34.205 ;
     RECT  29.16 32.957 29.178 34.349 ;
     RECT  8.568 33.845 8.586 34.397 ;
     RECT  70.455 33.691 70.794 34.411 ;
     RECT  71.784 33.611 71.802 34.457 ;
     RECT  14.688 33.269 15.498 34.501 ;
     RECT  16.38 34.205 18.414 34.501 ;
     RECT  20.916 33.691 23.742 34.501 ;
     RECT  59.655 33.008 59.937 34.501 ;
     RECT  70.344 34.411 70.794 34.529 ;
     RECT  28.908 34.465 28.926 34.541 ;
     RECT  29.88 34.501 29.898 34.541 ;
     RECT  59.655 34.501 60.534 34.591 ;
     RECT  20.916 34.501 23.85 34.619 ;
     RECT  59.655 34.591 61.254 34.619 ;
     RECT  61.236 34.619 61.254 34.637 ;
     RECT  32.655 33.965 34.758 34.655 ;
     RECT  70.344 34.529 70.737 34.655 ;
     RECT  22.86 34.619 23.85 34.685 ;
     RECT  32.655 34.655 33.822 34.685 ;
     RECT  59.655 34.619 60.318 34.685 ;
     RECT  0.036 33.449 7.83 34.733 ;
     RECT  9.396 34.079 9.954 34.771 ;
     RECT  4.248 34.733 7.83 34.781 ;
     RECT  4.248 34.781 6.57 34.889 ;
     RECT  9.252 34.771 9.954 34.889 ;
     RECT  14.688 34.501 18.414 34.889 ;
     RECT  56.844 31.421 57.114 34.889 ;
     RECT  15.876 34.889 18.126 34.925 ;
     RECT  56.916 34.889 57.114 34.925 ;
     RECT  11.055 34.187 11.682 34.933 ;
     RECT  33.804 34.685 33.822 34.973 ;
     RECT  19.152 34.205 19.602 34.987 ;
     RECT  18.936 34.987 19.602 35.033 ;
     RECT  10.908 34.933 11.682 35.041 ;
     RECT  0.036 34.733 3.402 35.069 ;
     RECT  34.668 34.655 34.758 35.069 ;
     RECT  68.688 33.269 68.706 35.069 ;
     RECT  7.416 34.781 7.83 35.083 ;
     RECT  63.612 32.873 63.63 35.131 ;
     RECT  7.416 35.083 8.298 35.159 ;
     RECT  14.688 34.889 15.102 35.159 ;
     RECT  63.072 35.131 63.63 35.168 ;
     RECT  66.708 34.429 66.726 35.195 ;
     RECT  10.836 35.041 11.682 35.267 ;
     RECT  13.248 33.269 13.95 35.311 ;
     RECT  65.055 33.547 65.538 35.311 ;
     RECT  43.455 30.875 43.737 35.371 ;
     RECT  20.916 34.619 22.137 35.429 ;
     RECT  43.344 35.371 43.737 35.429 ;
     RECT  46.836 35.371 46.854 35.429 ;
     RECT  11.055 35.267 11.682 35.465 ;
     RECT  13.068 35.311 13.95 35.501 ;
     RECT  43.416 35.429 43.737 35.501 ;
     RECT  48.456 32.971 49.137 35.537 ;
     RECT  13.68 35.501 13.95 35.549 ;
     RECT  19.548 35.033 19.602 35.699 ;
     RECT  55.512 35.671 55.53 35.741 ;
     RECT  19.944 35.743 19.962 35.789 ;
     RECT  15.876 34.925 17.946 35.879 ;
     RECT  57.096 34.925 57.114 35.879 ;
     RECT  16.455 35.879 17.946 35.885 ;
     RECT  68.04 35.401 68.058 35.885 ;
     RECT  9.468 34.889 9.954 35.899 ;
     RECT  27.255 33.965 27.537 35.947 ;
     RECT  9 35.899 9.954 35.969 ;
     RECT  53.172 33.053 53.19 35.969 ;
     RECT  30.672 35.941 30.69 35.977 ;
     RECT  17.928 35.885 17.946 36.005 ;
     RECT  37.836 34.079 38.682 36.005 ;
     RECT  4.5 34.889 6.57 36.029 ;
     RECT  9.072 35.969 9.954 36.041 ;
     RECT  30.672 35.977 30.834 36.049 ;
     RECT  39.492 34.151 39.51 36.049 ;
     RECT  9.144 36.041 9.954 36.077 ;
     RECT  20.916 35.429 20.934 36.113 ;
     RECT  27.036 35.947 27.537 36.113 ;
     RECT  46.8 35.947 46.818 36.113 ;
     RECT  30.672 36.049 30.906 36.149 ;
     RECT  34.668 35.069 34.686 36.247 ;
     RECT  47.736 36.121 47.754 36.275 ;
     RECT  34.668 36.247 34.794 36.347 ;
     RECT  4.536 36.029 6.57 36.391 ;
     RECT  7.416 35.159 7.974 36.391 ;
     RECT  32.655 34.685 32.937 36.391 ;
     RECT  32.655 36.391 33.57 36.461 ;
     RECT  14.868 35.159 15.102 36.475 ;
     RECT  65.055 35.311 65.754 36.509 ;
     RECT  48.855 35.537 49.137 36.523 ;
     RECT  23.112 34.685 23.85 36.571 ;
     RECT  4.536 36.391 7.974 36.751 ;
     RECT  22.896 36.571 23.85 36.779 ;
     RECT  39.492 36.049 39.942 36.779 ;
     RECT  37.836 36.005 38.337 36.823 ;
     RECT  39.492 36.779 39.51 36.823 ;
     RECT  41.688 33.179 41.706 36.823 ;
     RECT  48.855 36.523 49.302 36.895 ;
     RECT  37.836 36.823 39.51 36.923 ;
     RECT  41.688 36.823 41.778 36.923 ;
     RECT  0.036 35.069 3.33 36.931 ;
     RECT  4.464 36.751 7.974 36.931 ;
     RECT  21.78 35.429 22.137 36.931 ;
     RECT  30.132 36.895 30.15 36.955 ;
     RECT  34.668 36.347 34.686 36.959 ;
     RECT  16.455 35.885 16.83 37.021 ;
     RECT  66.276 36.661 66.294 37.037 ;
     RECT  0.036 36.931 7.974 37.049 ;
     RECT  14.76 36.475 15.102 37.049 ;
     RECT  21.456 36.931 22.137 37.049 ;
     RECT  30.132 36.955 30.222 37.049 ;
     RECT  48.855 36.895 49.374 37.049 ;
     RECT  16.455 37.021 17.406 37.165 ;
     RECT  16.344 37.165 17.406 37.229 ;
     RECT  9.504 36.077 9.954 37.469 ;
     RECT  27.144 36.113 27.537 37.471 ;
     RECT  39.492 36.923 39.51 37.499 ;
     RECT  26.424 37.471 27.537 37.589 ;
     RECT  34.056 37.099 34.542 37.589 ;
     RECT  3.96 37.049 7.974 37.625 ;
     RECT  34.416 37.589 34.434 37.625 ;
     RECT  37.836 36.923 38.337 37.675 ;
     RECT  21.78 37.049 22.137 37.733 ;
     RECT  21.855 37.733 22.137 37.741 ;
     RECT  39.78 37.675 39.798 37.741 ;
     RECT  37.62 37.675 38.337 37.771 ;
     RECT  21.855 37.741 22.806 37.859 ;
     RECT  37.62 37.771 38.574 37.859 ;
     RECT  62.712 37.819 62.73 37.859 ;
     RECT  37.62 37.859 38.337 37.895 ;
     RECT  12.456 37.831 12.474 37.901 ;
     RECT  3.96 37.625 7.182 37.904 ;
     RECT  63.612 35.168 63.63 37.931 ;
     RECT  11.055 35.465 11.43 37.939 ;
     RECT  10.836 37.939 11.43 38.039 ;
     RECT  19.62 37.963 19.638 38.039 ;
     RECT  15.012 37.049 15.102 38.101 ;
     RECT  7.956 37.625 7.974 38.129 ;
     RECT  39.78 37.741 39.87 38.129 ;
     RECT  3.96 37.904 5.937 38.173 ;
     RECT  11.055 38.039 11.43 38.173 ;
     RECT  14.832 38.101 15.102 38.201 ;
     RECT  16.455 37.229 17.406 38.201 ;
     RECT  6.768 37.904 7.182 38.309 ;
     RECT  13.932 35.549 13.95 38.309 ;
     RECT  31.32 37.435 31.338 38.309 ;
     RECT  26.388 38.281 26.406 38.371 ;
     RECT  27.144 37.589 27.537 38.371 ;
     RECT  26.388 38.371 27.537 38.399 ;
     RECT  26.46 38.399 27.537 38.429 ;
     RECT  15.084 38.201 15.102 38.471 ;
     RECT  0.036 37.049 3.15 38.632 ;
     RECT  0.036 38.632 3.186 38.669 ;
     RECT  0.036 38.669 3.15 38.813 ;
     RECT  9.936 37.469 9.954 38.813 ;
     RECT  3.924 38.173 5.937 38.975 ;
     RECT  4.932 38.975 5.937 39.119 ;
     RECT  27.144 38.429 27.537 39.119 ;
     RECT  7.02 38.309 7.038 39.181 ;
     RECT  27.255 39.119 27.537 39.181 ;
     RECT  6.804 39.181 7.038 39.209 ;
     RECT  27.255 39.181 27.954 39.245 ;
     RECT  6.804 39.209 6.822 39.281 ;
     RECT  29.664 37.597 29.682 39.281 ;
     RECT  11.055 38.173 12.042 39.515 ;
     RECT  3.924 38.975 3.942 39.629 ;
     RECT  11.055 39.515 12.006 39.659 ;
     RECT  0.036 38.813 3.042 39.821 ;
     RECT  0.036 39.821 2.862 39.917 ;
     RECT  0.036 39.917 0.537 39.965 ;
     RECT  5.655 39.119 5.937 39.977 ;
     RECT  11.055 39.659 11.337 39.977 ;
     RECT  16.455 38.201 16.737 39.977 ;
     RECT  21.855 37.859 22.137 39.977 ;
     RECT  27.255 39.245 27.537 39.977 ;
     RECT  32.655 36.461 32.937 39.977 ;
     RECT  38.055 37.895 38.337 39.977 ;
     RECT  43.455 35.501 43.737 39.977 ;
     RECT  48.855 37.049 49.137 39.977 ;
     RECT  54.255 32.837 54.537 39.977 ;
     RECT  59.655 34.685 59.937 39.977 ;
     RECT  65.055 36.509 65.337 39.977 ;
     RECT  70.455 34.655 70.737 39.977 ;
     RECT  18.792 39.091 18.81 40.061 ;
     RECT  1.26 39.917 2.862 40.163 ;
     RECT  1.26 40.163 1.926 40.199 ;
     RECT  0.252 39.965 0.537 40.247 ;
     RECT  5.847 39.977 5.937 40.247 ;
     RECT  11.247 39.977 11.337 40.247 ;
     RECT  16.647 39.977 16.737 40.247 ;
     RECT  22.047 39.977 22.137 40.247 ;
     RECT  27.447 39.977 27.537 40.247 ;
     RECT  32.847 39.977 32.937 40.247 ;
     RECT  38.247 39.977 38.337 40.247 ;
     RECT  43.647 39.977 43.737 40.247 ;
     RECT  49.047 39.977 49.137 40.247 ;
     RECT  54.447 39.977 54.537 40.247 ;
     RECT  59.847 39.977 59.937 40.247 ;
     RECT  65.247 39.977 65.337 40.247 ;
     RECT  70.647 39.977 70.737 40.247 ;
     RECT  1.26 40.199 1.818 40.289 ;
     RECT  0.252 40.247 0.342 40.301 ;
     RECT  1.8 40.289 1.818 40.397 ;
     RECT  0.252 40.301 0.27 40.493 ;
     RECT  2.844 40.163 2.862 40.493 ;
    LAYER M4 ;
     RECT  0.017 14.64 0.037 14.664 ;
     RECT  0.025 16.224 0.037 17.304 ;
     RECT  0.025 19.968 0.037 19.992 ;
     RECT  0.025 22.128 0.037 22.728 ;
     RECT  0.025 23.712 0.037 24.264 ;
     RECT  0.025 26.976 0.037 34.584 ;
     RECT  0.025 35.616 0.037 36.744 ;
     RECT  0.025 38.352 0.037 39.96 ;
     RECT  0.037 14.64 0.053 17.304 ;
     RECT  0.053 14.304 0.085 17.304 ;
     RECT  0.017 10.8 0.133 10.824 ;
     RECT  0.085 13.344 0.133 17.304 ;
     RECT  0.037 18.384 0.133 21.096 ;
     RECT  0.037 22.128 0.133 25.944 ;
     RECT  0.037 26.976 0.133 36.744 ;
     RECT  0.037 37.824 0.133 39.96 ;
     RECT  0.133 13.344 0.156 40.008 ;
     RECT  0.156 13.344 0.241 40.392 ;
     RECT  0.133 10.704 0.248 10.824 ;
     RECT  0.241 13.344 0.248 40.488 ;
     RECT  0.248 0.528 0.352 40.488 ;
     RECT  0.352 0.798 0.544 40.488 ;
     RECT  0.544 7.392 0.685 7.416 ;
     RECT  0.544 12.72 0.857 40.488 ;
     RECT  0.544 9.168 1.715 11.256 ;
     RECT  1.715 9.168 1.925 10.728 ;
     RECT  1.925 8.592 2.009 10.728 ;
     RECT  0.857 13.056 2.053 40.488 ;
     RECT  2.009 9.168 2.089 10.728 ;
     RECT  2.053 12.768 2.152 40.488 ;
     RECT  2.152 12.72 2.437 40.488 ;
     RECT  2.089 9.744 2.585 10.728 ;
     RECT  2.653 6.864 2.761 6.888 ;
     RECT  2.437 12 2.78 40.488 ;
     RECT  2.732 4.272 2.819 4.296 ;
     RECT  2.78 11.376 2.819 40.488 ;
     RECT  2.819 11.376 2.867 15.48 ;
     RECT  2.819 16.752 2.873 40.488 ;
     RECT  2.869 1.248 3.013 1.272 ;
     RECT  3.085 8.592 3.169 8.616 ;
     RECT  2.867 12.528 3.169 15.48 ;
     RECT  2.761 6.816 3.193 6.888 ;
     RECT  2.585 9.744 3.341 10.344 ;
     RECT  3.301 3.504 3.395 3.528 ;
     RECT  3.193 6.288 3.397 6.888 ;
     RECT  3.397 6.288 3.443 7.032 ;
     RECT  2.873 16.752 3.443 40.056 ;
     RECT  3.341 9.744 3.661 9.768 ;
     RECT  3.169 15.456 3.817 15.48 ;
     RECT  3.443 39.6 3.953 40.056 ;
     RECT  3.517 5.136 3.971 5.16 ;
     RECT  3.661 9.216 3.971 9.768 ;
     RECT  3.169 12.528 3.971 14.376 ;
     RECT  3.971 13.152 3.997 14.376 ;
     RECT  3.443 6.816 4.019 7.032 ;
     RECT  3.443 16.752 4.273 38.376 ;
     RECT  3.997 13.152 4.321 13.752 ;
     RECT  4.237 11.472 4.355 11.496 ;
     RECT  4.273 15.984 4.529 38.376 ;
     RECT  4.529 15.984 4.547 18.168 ;
     RECT  4.529 19.248 4.547 38.376 ;
     RECT  3.013 1.248 5.648 1.464 ;
     RECT  4.019 6.816 5.648 6.84 ;
     RECT  5.317 10.944 5.648 10.968 ;
     RECT  4.321 13.344 5.648 13.752 ;
     RECT  5.425 15.504 5.648 15.528 ;
     RECT  4.547 16.608 5.648 18.168 ;
     RECT  4.547 19.248 5.648 38.232 ;
     RECT  3.953 40.032 5.648 40.056 ;
     RECT  5.648 0.528 5.752 40.056 ;
     RECT  5.752 0.798 5.84 40.056 ;
     RECT  5.84 0.798 5.944 40.242 ;
     RECT  5.944 12.384 6.149 13.368 ;
     RECT  6.149 12.384 6.689 13.128 ;
     RECT  5.944 9.216 6.797 9.432 ;
     RECT  6.689 12.528 6.947 13.128 ;
     RECT  6.947 12.816 6.995 13.128 ;
     RECT  5.944 14.976 6.995 16.632 ;
     RECT  5.944 17.616 7.157 38.232 ;
     RECT  7.081 8.592 7.165 8.616 ;
     RECT  6.995 15.504 7.189 16.632 ;
     RECT  7.157 17.616 7.189 34.392 ;
     RECT  6.995 12.864 7.585 13.128 ;
     RECT  7.157 35.376 7.985 37.464 ;
     RECT  7.585 12.864 8.003 13.8 ;
     RECT  7.189 15.504 8.269 34.392 ;
     RECT  7.985 35.376 8.269 36.36 ;
     RECT  6.937 9.84 8.405 9.864 ;
     RECT  5.944 10.944 8.405 10.968 ;
     RECT  8.405 9.84 8.489 10.968 ;
     RECT  8.269 15.504 8.531 36.36 ;
     RECT  5.944 6.144 8.557 6.84 ;
     RECT  8.531 15.504 8.597 34.392 ;
     RECT  8.489 9.84 8.809 9.864 ;
     RECT  8.557 6.144 8.881 6.888 ;
     RECT  8.828 4.944 8.915 4.968 ;
     RECT  8.489 10.944 8.989 10.968 ;
     RECT  8.881 6.144 9.107 7.608 ;
     RECT  8.003 12.864 9.397 13.128 ;
     RECT  7.985 37.392 9.533 37.464 ;
     RECT  8.989 10.944 9.673 11.16 ;
     RECT  9.397 12.144 9.673 13.128 ;
     RECT  8.597 15.504 9.781 34.248 ;
     RECT  8.531 35.472 9.827 36.36 ;
     RECT  9.107 6.144 9.853 6.84 ;
     RECT  9.781 15.456 9.973 34.248 ;
     RECT  8.809 9.024 10.177 9.864 ;
     RECT  9.673 10.944 10.177 13.128 ;
     RECT  9.853 6.096 10.837 6.84 ;
     RECT  10.837 6.096 10.933 6.888 ;
     RECT  5.944 1.248 11.048 1.464 ;
     RECT  10.933 6.096 11.048 7.128 ;
     RECT  10.177 9.024 11.048 13.128 ;
     RECT  9.973 14.736 11.048 34.248 ;
     RECT  9.827 35.472 11.048 35.736 ;
     RECT  9.533 37.392 11.048 37.416 ;
     RECT  5.944 40.032 11.048 40.056 ;
     RECT  11.048 0.528 11.152 40.056 ;
     RECT  11.152 0.798 11.24 40.056 ;
     RECT  11.24 0.798 11.344 40.242 ;
     RECT  11.344 1.248 11.441 1.464 ;
     RECT  11.344 37.392 11.441 37.416 ;
     RECT  11.344 35.472 11.459 35.736 ;
     RECT  11.441 1.248 11.513 1.416 ;
     RECT  12.445 37.872 12.529 37.896 ;
     RECT  11.344 12 12.563 34.248 ;
     RECT  11.344 9.024 12.589 10.968 ;
     RECT  12.589 8.592 12.673 10.968 ;
     RECT  12.563 12.24 13.093 34.248 ;
     RECT  13.093 12.24 13.237 34.488 ;
     RECT  11.459 35.472 13.237 35.544 ;
     RECT  13.237 12.24 13.709 35.544 ;
     RECT  13.709 12.24 13.763 34.776 ;
     RECT  12.673 9.024 14.348 10.968 ;
     RECT  14.348 9.024 14.435 11.064 ;
     RECT  13.763 12.24 14.789 34.488 ;
     RECT  11.513 1.344 14.821 1.416 ;
     RECT  14.789 12.24 14.821 32.568 ;
     RECT  14.789 33.552 14.869 34.488 ;
     RECT  14.821 1.344 14.893 1.464 ;
     RECT  14.869 33.552 14.929 34.728 ;
     RECT  14.749 36.48 14.963 36.504 ;
     RECT  11.344 6.096 14.965 6.984 ;
     RECT  14.885 4.944 14.969 4.968 ;
     RECT  14.821 12 15.049 32.568 ;
     RECT  14.435 9.024 15.059 11.016 ;
     RECT  15.049 12 15.203 32.232 ;
     RECT  14.929 33.552 16.021 35.016 ;
     RECT  14.965 6.096 16.069 7.416 ;
     RECT  15.059 9.024 16.069 10.968 ;
     RECT  14.893 1.248 16.448 1.464 ;
     RECT  16.309 4.56 16.448 4.68 ;
     RECT  16.069 6.096 16.448 10.968 ;
     RECT  15.203 12.288 16.448 32.232 ;
     RECT  16.021 33.552 16.448 35.208 ;
     RECT  16.289 37.2 16.448 37.224 ;
     RECT  11.344 40.032 16.448 40.056 ;
     RECT  16.448 0.528 16.552 40.056 ;
     RECT  16.552 0.798 16.64 40.056 ;
     RECT  16.64 0.798 16.744 40.242 ;
     RECT  16.744 8.16 17.057 32.232 ;
     RECT  16.744 6.096 17.129 6.888 ;
     RECT  16.744 33.552 17.411 35.88 ;
     RECT  17.057 8.976 17.651 32.232 ;
     RECT  17.651 8.976 18.227 10.968 ;
     RECT  17.411 33.552 18.517 35.208 ;
     RECT  18.517 33.216 18.803 35.208 ;
     RECT  16.744 1.248 18.817 1.464 ;
     RECT  17.651 12.24 18.817 32.232 ;
     RECT  16.744 40.032 18.821 40.056 ;
     RECT  18.817 1.248 18.965 1.56 ;
     RECT  18.803 33.216 19.091 35.16 ;
     RECT  18.227 9.024 19.285 10.968 ;
     RECT  18.817 12.048 19.285 32.232 ;
     RECT  19.285 9.024 19.613 32.232 ;
     RECT  19.381 37.968 19.649 37.992 ;
     RECT  19.613 12.048 19.717 32.232 ;
     RECT  19.091 33.216 19.717 34.488 ;
     RECT  19.724 4.272 19.811 4.296 ;
     RECT  19.933 35.76 20.017 35.784 ;
     RECT  20.156 3.216 20.243 3.24 ;
     RECT  19.717 12.048 20.243 34.488 ;
     RECT  20.243 30.096 20.579 34.488 ;
     RECT  19.613 9.024 20.581 11.016 ;
     RECT  20.243 12.048 20.581 29.064 ;
     RECT  20.579 30.096 20.729 33.96 ;
     RECT  20.729 33.216 21.625 33.96 ;
     RECT  21.193 35.376 21.625 35.4 ;
     RECT  20.729 30.096 21.733 32.232 ;
     RECT  21.625 33.216 21.733 35.4 ;
     RECT  18.965 1.44 21.848 1.56 ;
     RECT  21.077 3.168 21.848 3.192 ;
     RECT  17.129 6.096 21.848 6.696 ;
     RECT  20.581 9.024 21.848 29.064 ;
     RECT  21.733 30.096 21.848 35.4 ;
     RECT  21.617 37.008 21.848 37.032 ;
     RECT  21.848 0.528 21.952 39.972 ;
     RECT  21.952 0.798 22.04 39.972 ;
     RECT  22.04 0.798 22.144 40.242 ;
     RECT  22.144 6.096 22.355 7.416 ;
     RECT  22.144 12.048 22.835 32.232 ;
     RECT  22.144 33.312 22.889 35.208 ;
     RECT  22.144 1.248 22.925 1.56 ;
     RECT  22.889 33.312 22.931 34.008 ;
     RECT  22.144 36.576 22.969 36.6 ;
     RECT  22.889 35.184 23.321 35.208 ;
     RECT  22.355 6.096 23.893 6.696 ;
     RECT  22.144 9.024 23.893 10.968 ;
     RECT  22.835 12.24 23.893 32.232 ;
     RECT  23.921 4.368 24.005 4.392 ;
     RECT  23.893 9.024 24.545 32.232 ;
     RECT  22.931 33.312 24.659 33.864 ;
     RECT  24.545 9.024 25.091 32.136 ;
     RECT  25.091 12.24 25.667 32.136 ;
     RECT  25.667 12.24 26.101 31.8 ;
     RECT  26.101 12.048 26.14 31.8 ;
     RECT  24.659 33.84 26.581 33.864 ;
     RECT  26.581 32.976 26.629 33.864 ;
     RECT  25.091 9.024 26.677 10.968 ;
     RECT  26.677 8.256 26.701 10.968 ;
     RECT  26.629 32.928 26.773 33.864 ;
     RECT  26.701 8.208 26.869 10.968 ;
     RECT  26.14 12.048 26.869 31.752 ;
     RECT  22.925 1.248 27.248 1.464 ;
     RECT  23.893 6.096 27.248 6.888 ;
     RECT  26.869 8.208 27.248 31.752 ;
     RECT  26.773 32.928 27.248 33.96 ;
     RECT  27.025 35.952 27.248 35.976 ;
     RECT  26.197 37.488 27.248 38.424 ;
     RECT  27.248 0.528 27.352 39.972 ;
     RECT  27.352 0.798 27.44 39.972 ;
     RECT  27.44 0.798 27.544 40.242 ;
     RECT  27.544 1.248 27.641 1.464 ;
     RECT  27.641 1.248 27.713 1.416 ;
     RECT  27.544 6.096 27.971 6.888 ;
     RECT  27.544 39.216 28.009 39.24 ;
     RECT  27.544 9.024 28.547 30.936 ;
     RECT  27.544 33.936 28.885 33.96 ;
     RECT  28.885 33.936 29.077 34.536 ;
     RECT  29.077 32.976 29.413 34.536 ;
     RECT  29.413 32.928 29.437 34.536 ;
     RECT  28.547 30.096 29.509 30.936 ;
     RECT  29.437 32.016 29.509 34.536 ;
     RECT  29.509 30.096 29.521 34.536 ;
     RECT  29.521 32.976 29.555 34.536 ;
     RECT  28.547 9.024 29.657 29.064 ;
     RECT  29.555 33.936 29.932 34.536 ;
     RECT  30.193 36.96 30.277 36.984 ;
     RECT  29.521 30.096 30.313 31.416 ;
     RECT  30.313 31.392 30.449 31.416 ;
     RECT  30.229 7.872 30.481 7.896 ;
     RECT  29.657 9.024 30.725 11.208 ;
     RECT  27.713 1.344 30.769 1.416 ;
     RECT  29.932 33.936 30.769 33.96 ;
     RECT  30.689 36.096 30.773 36.12 ;
     RECT  30.481 7.776 30.797 7.896 ;
     RECT  30.725 9.024 30.797 11.304 ;
     RECT  30.797 7.776 30.805 11.304 ;
     RECT  29.657 12.576 30.805 29.064 ;
     RECT  30.769 33.84 30.809 33.96 ;
     RECT  30.769 1.344 30.841 1.464 ;
     RECT  30.805 7.776 30.844 29.064 ;
     RECT  30.844 7.776 30.881 11.208 ;
     RECT  30.841 1.248 31.273 1.464 ;
     RECT  30.913 31.68 31.331 31.704 ;
     RECT  31.388 32.448 31.475 32.472 ;
     RECT  27.971 6.096 31.861 6.792 ;
     RECT  30.881 7.776 31.861 7.896 ;
     RECT  31.273 1.248 32.648 2.088 ;
     RECT  31.861 6.096 32.648 7.896 ;
     RECT  30.881 9.024 32.648 11.208 ;
     RECT  30.844 12.24 32.648 29.064 ;
     RECT  30.313 30.096 32.648 30.12 ;
     RECT  30.809 33.84 32.648 33.864 ;
     RECT  32.648 0.528 32.752 39.972 ;
     RECT  32.752 0.798 32.84 39.972 ;
     RECT  32.84 0.798 32.944 40.242 ;
     RECT  32.944 5.76 33.113 6.888 ;
     RECT  32.944 12.24 33.185 29.064 ;
     RECT  32.944 33.12 33.185 34.968 ;
     RECT  33.113 5.76 33.251 6.744 ;
     RECT  33.185 26.064 33.365 29.064 ;
     RECT  32.944 36.432 33.581 36.456 ;
     RECT  33.185 33.12 33.617 33.864 ;
     RECT  32.944 4.56 33.833 4.584 ;
     RECT  33.185 34.944 33.833 34.968 ;
     RECT  34.045 37.104 34.129 37.128 ;
     RECT  32.944 30.096 34.213 30.504 ;
     RECT  33.185 12.24 34.373 24.696 ;
     RECT  34.213 30.096 34.481 31.32 ;
     RECT  34.405 37.584 34.739 37.608 ;
     RECT  33.617 33.84 34.765 33.864 ;
     RECT  34.765 33.84 34.789 33.96 ;
     RECT  33.365 26.064 34.837 26.616 ;
     RECT  33.365 27.648 34.837 29.064 ;
     RECT  34.837 26.064 34.985 29.064 ;
     RECT  32.944 8.544 35.309 11.208 ;
     RECT  34.481 30.096 35.309 30.84 ;
     RECT  34.789 33.168 35.309 33.96 ;
     RECT  34.373 24.624 35.749 24.696 ;
     RECT  34.373 12.24 36.205 23.304 ;
     RECT  35.309 30.48 36.371 30.84 ;
     RECT  36.371 30.528 36.467 30.84 ;
     RECT  35.749 24.576 36.515 24.696 ;
     RECT  36.467 30.72 36.515 30.84 ;
     RECT  32.944 1.248 36.565 2.232 ;
     RECT  36.515 30.72 36.893 30.744 ;
     RECT  34.985 28.224 37.249 29.064 ;
     RECT  33.251 6.096 37.34 6.744 ;
     RECT  37.34 6.096 37.573 6.84 ;
     RECT  36.205 12.24 37.621 23.352 ;
     RECT  36.515 24.576 37.621 24.6 ;
     RECT  35.309 33.936 37.669 33.96 ;
     RECT  35.309 9.024 38.005 11.208 ;
     RECT  37.621 12.24 38.005 24.6 ;
     RECT  36.565 1.248 38.048 3.096 ;
     RECT  37.573 6 38.048 6.84 ;
     RECT  38.005 9.024 38.048 24.6 ;
     RECT  34.985 26.064 38.048 26.616 ;
     RECT  37.249 27.936 38.048 29.064 ;
     RECT  37.669 33.024 38.048 33.96 ;
     RECT  37.609 37.68 38.048 37.704 ;
     RECT  38.048 0.528 38.152 39.972 ;
     RECT  38.152 0.798 38.24 39.972 ;
     RECT  38.24 0.798 38.344 40.242 ;
     RECT  38.344 8.736 38.483 23.736 ;
     RECT  38.344 37.776 38.585 37.8 ;
     RECT  38.344 33.936 38.909 33.96 ;
     RECT  38.483 9.024 39.017 23.688 ;
     RECT  39.017 12.24 39.233 23.688 ;
     RECT  38.344 5.232 39.347 7.32 ;
     RECT  39.233 12.24 39.347 23.352 ;
     RECT  38.344 30.816 39.349 30.84 ;
     RECT  39.404 33.36 39.491 33.384 ;
     RECT  39.769 37.68 39.853 37.704 ;
     RECT  38.344 26.064 40.093 29.064 ;
     RECT  40.093 25.104 40.141 29.064 ;
     RECT  39.347 12.24 40.453 23.304 ;
     RECT  40.141 28.272 41.069 29.064 ;
     RECT  39.017 9.024 41.125 11.208 ;
     RECT  41.125 8.736 41.213 11.208 ;
     RECT  38.344 1.248 41.276 4.248 ;
     RECT  39.347 5.232 41.276 6.936 ;
     RECT  41.276 1.248 41.363 6.936 ;
     RECT  40.453 12.24 41.461 23.976 ;
     RECT  40.141 25.104 41.461 27.096 ;
     RECT  41.069 28.464 41.605 29.064 ;
     RECT  41.137 30.192 41.605 30.216 ;
     RECT  41.461 12.24 42.005 27.336 ;
     RECT  41.213 8.88 42.037 11.208 ;
     RECT  42.005 12.24 42.131 24.072 ;
     RECT  42.005 25.104 42.179 27.336 ;
     RECT  42.037 8.88 42.181 11.256 ;
     RECT  42.179 25.536 42.185 27.336 ;
     RECT  42.173 31.392 42.257 31.416 ;
     RECT  41.363 5.232 42.476 6.936 ;
     RECT  42.181 8.352 42.476 11.256 ;
     RECT  41.363 1.248 43.009 4.248 ;
     RECT  42.476 5.232 43.009 11.256 ;
     RECT  43.285 35.472 43.333 35.496 ;
     RECT  43.009 1.248 43.369 11.256 ;
     RECT  42.131 12.24 43.369 23.64 ;
     RECT  43.369 1.248 43.448 23.64 ;
     RECT  42.185 25.536 43.448 27.24 ;
     RECT  41.605 28.464 43.448 30.216 ;
     RECT  43.333 35.376 43.448 35.496 ;
     RECT  43.448 0.528 43.552 39.972 ;
     RECT  43.552 0.798 43.64 39.972 ;
     RECT  43.64 0.798 43.744 40.242 ;
     RECT  43.744 28.368 43.859 29.544 ;
     RECT  43.744 1.248 43.913 6.936 ;
     RECT  43.859 28.368 44.597 29.4 ;
     RECT  43.744 30.816 45.385 30.84 ;
     RECT  43.744 9.024 45.445 23.736 ;
     RECT  45.385 30.816 45.452 30.936 ;
     RECT  43.744 25.536 45.557 26.616 ;
     RECT  45.445 9.024 45.587 23.832 ;
     RECT  45.587 18.48 45.589 23.832 ;
     RECT  43.913 1.344 45.641 6.936 ;
     RECT  45.589 18.48 45.676 24.312 ;
     RECT  45.557 25.536 45.788 26.856 ;
     RECT  44.597 28.368 45.788 29.112 ;
     RECT  45.788 25.536 45.875 29.112 ;
     RECT  45.875 25.536 46.141 26.616 ;
     RECT  45.452 30.336 46.165 30.936 ;
     RECT  46.165 30.288 46.469 30.936 ;
     RECT  46.741 35.376 46.789 35.4 ;
     RECT  45.641 1.344 46.793 6.84 ;
     RECT  46.793 1.392 46.865 6.84 ;
     RECT  46.789 35.376 46.865 35.976 ;
     RECT  46.865 35.952 46.883 35.976 ;
     RECT  45.587 9.024 46.901 17.448 ;
     RECT  46.901 12.288 47.173 17.448 ;
     RECT  45.676 18.48 47.173 23.688 ;
     RECT  45.875 28.368 47.317 29.112 ;
     RECT  47.317 28.368 47.833 29.592 ;
     RECT  46.901 9.024 48.188 11.256 ;
     RECT  47.173 12.288 48.188 23.688 ;
     RECT  47.833 28.272 48.469 29.592 ;
     RECT  48.469 28.272 48.689 29.88 ;
     RECT  46.469 30.912 48.689 30.936 ;
     RECT  46.865 1.44 48.848 6.84 ;
     RECT  48.188 9.024 48.848 23.688 ;
     RECT  46.141 24.672 48.848 26.616 ;
     RECT  48.689 28.272 48.848 30.936 ;
     RECT  48.848 0.528 48.952 39.972 ;
     RECT  48.952 0.798 49.04 39.972 ;
     RECT  49.04 0.798 49.144 40.242 ;
     RECT  49.144 8.4 49.349 26.616 ;
     RECT  49.144 36.528 49.379 36.552 ;
     RECT  49.144 31.968 49.564 31.992 ;
     RECT  49.144 27.936 49.673 29.016 ;
     RECT  49.144 33.12 50.069 33.144 ;
     RECT  49.144 30.912 50.389 30.936 ;
     RECT  50.389 30.912 50.476 31.896 ;
     RECT  49.144 1.44 50.485 6.84 ;
     RECT  50.485 1.44 50.713 7.416 ;
     RECT  49.349 8.4 50.713 23.688 ;
     RECT  50.713 1.44 50.749 23.688 ;
     RECT  50.476 30.912 50.893 30.984 ;
     RECT  49.349 24.672 51.157 26.616 ;
     RECT  50.725 32.928 51.157 32.952 ;
     RECT  51.157 32.928 51.253 33.864 ;
     RECT  51.253 32.928 51.299 33.912 ;
     RECT  50.749 1.2 51.301 23.688 ;
     RECT  51.157 24.672 51.301 26.712 ;
     RECT  51.299 33.84 51.337 33.912 ;
     RECT  51.301 1.2 51.395 27.192 ;
     RECT  51.337 33.84 51.401 33.864 ;
     RECT  49.673 28.272 51.493 29.016 ;
     RECT  50.893 30.864 51.493 30.984 ;
     RECT  51.395 1.2 51.539 6.936 ;
     RECT  51.493 28.272 51.58 30.984 ;
     RECT  51.395 8.4 51.653 27.192 ;
     RECT  51.58 30.864 51.941 30.984 ;
     RECT  51.857 32.592 51.941 32.616 ;
     RECT  51.653 8.4 52.049 27.048 ;
     RECT  51.941 30.912 52.441 30.984 ;
     RECT  52.441 30.912 52.525 31.224 ;
     RECT  51.58 28.272 52.733 29.016 ;
     RECT  52.049 9.024 52.841 27.048 ;
     RECT  52.841 9.024 53.237 26.616 ;
     RECT  51.539 1.2 53.317 6.84 ;
     RECT  53.317 1.2 53.468 7.464 ;
     RECT  53.468 33.024 53.557 33.048 ;
     RECT  53.468 1.2 54.248 8.04 ;
     RECT  53.237 9.024 54.248 23.688 ;
     RECT  53.237 24.672 54.248 26.616 ;
     RECT  52.733 28.272 54.248 28.488 ;
     RECT  52.525 30.912 54.248 30.936 ;
     RECT  53.557 32.736 54.248 33.048 ;
     RECT  54.248 0.528 54.352 39.972 ;
     RECT  54.352 0.798 54.44 39.972 ;
     RECT  54.44 0.798 54.544 40.242 ;
     RECT  54.544 30.912 54.829 31.896 ;
     RECT  54.544 1.2 54.851 7.464 ;
     RECT  54.544 8.928 55.001 26.808 ;
     RECT  54.544 28.272 55.181 28.488 ;
     RECT  55.181 28.416 55.537 28.488 ;
     RECT  54.544 35.712 55.541 35.736 ;
     RECT  55.001 8.976 55.789 26.808 ;
     RECT  55.789 8.976 55.873 26.856 ;
     RECT  55.873 8.976 55.937 26.808 ;
     RECT  54.851 1.248 56.081 7.464 ;
     RECT  54.829 30.912 56.245 30.936 ;
     RECT  56.245 30.912 56.333 31.416 ;
     RECT  56.081 1.488 56.477 7.464 ;
     RECT  56.333 30.912 56.513 31.128 ;
     RECT  56.437 34.896 56.945 34.92 ;
     RECT  55.937 9.024 57.013 26.808 ;
     RECT  57.013 9.024 57.161 27.24 ;
     RECT  56.477 1.488 57.589 7.272 ;
     RECT  55.537 28.416 57.589 28.584 ;
     RECT  57.589 28.416 57.673 29.352 ;
     RECT  57.589 1.488 58.097 7.8 ;
     RECT  57.673 28.416 58.633 28.584 ;
     RECT  57.161 9.024 58.741 26.616 ;
     RECT  58.633 27.6 58.741 28.584 ;
     RECT  58.693 32.976 58.813 33 ;
     RECT  58.741 9.024 59.269 28.584 ;
     RECT  58.097 1.488 59.648 7.272 ;
     RECT  59.269 9.024 59.648 29.016 ;
     RECT  56.513 30.912 59.648 30.936 ;
     RECT  58.813 32.544 59.648 33 ;
     RECT  59.648 0.528 59.752 39.972 ;
     RECT  59.752 0.798 59.84 39.972 ;
     RECT  59.84 0.798 59.944 40.242 ;
     RECT  59.944 26.064 60.083 28.536 ;
     RECT  59.944 9.024 60.323 25.032 ;
     RECT  59.944 34.656 60.329 34.68 ;
     RECT  60.083 28.416 60.365 28.536 ;
     RECT  60.083 26.064 60.617 27.336 ;
     RECT  59.944 29.904 60.905 29.928 ;
     RECT  60.323 12.24 61.121 25.032 ;
     RECT  60.997 28.992 61.121 29.016 ;
     RECT  60.997 34.608 61.265 34.632 ;
     RECT  59.944 1.488 61.477 6.84 ;
     RECT  59.944 30.912 61.541 30.936 ;
     RECT  61.477 1.488 61.564 7.224 ;
     RECT  61.564 1.488 61.801 6.84 ;
     RECT  60.617 26.064 61.957 26.76 ;
     RECT  61.657 27.744 61.957 27.768 ;
     RECT  61.957 26.064 62.044 27.768 ;
     RECT  62.044 27.744 62.099 27.768 ;
     RECT  61.121 12.24 62.125 23.688 ;
     RECT  61.121 24.672 62.125 25.032 ;
     RECT  62.125 12.24 62.149 25.032 ;
     RECT  62.044 26.064 62.149 26.616 ;
     RECT  61.541 30.72 62.149 30.936 ;
     RECT  62.149 30.576 62.237 30.936 ;
     RECT  60.323 9.024 62.521 11.256 ;
     RECT  62.449 29.616 62.533 29.64 ;
     RECT  62.521 8.784 62.557 11.256 ;
     RECT  62.557 8.256 62.593 11.256 ;
     RECT  62.593 7.872 62.701 11.256 ;
     RECT  62.149 12.24 62.701 26.616 ;
     RECT  62.237 30.912 62.725 30.936 ;
     RECT  62.637 37.824 62.764 37.848 ;
     RECT  62.725 30.912 63.101 31.752 ;
     RECT  62.725 35.136 63.101 35.16 ;
     RECT  63.068 27.84 63.155 27.864 ;
     RECT  62.701 7.872 63.253 26.616 ;
     RECT  63.253 29.472 63.425 29.496 ;
     RECT  63.673 32.544 63.757 32.568 ;
     RECT  63.101 30.912 63.884 30.936 ;
     RECT  61.801 1.152 63.889 6.84 ;
     RECT  63.829 32.832 63.929 32.856 ;
     RECT  63.884 29.952 63.971 30.936 ;
     RECT  63.253 7.872 64.405 27.72 ;
     RECT  63.889 1.152 64.933 6.888 ;
     RECT  64.405 7.872 64.933 28.44 ;
     RECT  64.933 1.152 65.048 28.44 ;
     RECT  64.405 29.808 65.048 29.832 ;
     RECT  63.971 30.912 65.048 30.936 ;
     RECT  65.048 0.528 65.152 39.972 ;
     RECT  65.152 0.798 65.24 39.972 ;
     RECT  65.24 0.798 65.344 40.242 ;
     RECT  65.344 33.504 65.459 33.528 ;
     RECT  65.344 35.616 65.485 37.032 ;
     RECT  65.344 30.912 65.5 31.848 ;
     RECT  65.485 35.616 65.693 35.64 ;
     RECT  65.344 26.064 66.275 27.096 ;
     RECT  65.485 37.008 66.305 37.032 ;
     RECT  65.344 1.152 66.661 25.032 ;
     RECT  66.661 1.152 67.313 25.08 ;
     RECT  65.5 30.912 67.676 30.936 ;
     RECT  67.676 30.864 67.763 30.936 ;
     RECT  67.813 35.856 68.069 35.88 ;
     RECT  67.763 30.912 68.389 30.936 ;
     RECT  68.389 30.912 68.681 31.032 ;
     RECT  67.313 1.152 68.929 11.208 ;
     RECT  68.012 33.216 69.049 33.24 ;
     RECT  68.681 30.912 69.157 30.936 ;
     RECT  69.157 30.624 69.244 30.936 ;
     RECT  66.275 26.064 69.541 26.616 ;
     RECT  67.313 12.24 70.117 25.08 ;
     RECT  69.541 26.064 70.117 27.144 ;
     RECT  70.117 12.24 70.22 27.144 ;
     RECT  68.929 0.864 70.333 11.256 ;
     RECT  70.22 12.24 70.333 27.336 ;
     RECT  70.333 0.864 70.448 27.336 ;
     RECT  69.541 29.472 70.448 29.496 ;
     RECT  69.244 30.672 70.448 30.936 ;
     RECT  70.117 34.416 70.448 34.44 ;
     RECT  70.448 0.528 70.552 39.972 ;
     RECT  70.552 0.672 70.64 39.972 ;
     RECT  70.64 0.672 70.744 40.242 ;
     RECT  70.744 29.568 71.129 29.592 ;
     RECT  71.797 29.424 72.065 29.448 ;
     RECT  70.744 30.912 72.131 30.936 ;
     RECT  70.744 26.304 72.209 27.336 ;
     RECT  72.209 27.216 72.323 27.336 ;
     RECT  70.744 0.672 72.385 25.32 ;
     RECT  72.323 27.216 72.605 27.24 ;
     RECT  72.385 0.624 72.828 25.32 ;
     RECT  72.828 25.2 72.947 25.32 ;
    LAYER M5 ;
     RECT  0.24 0.517 0.36 0.787 ;
     RECT  5.64 0.517 5.76 0.787 ;
     RECT  11.04 0.517 11.16 0.787 ;
     RECT  16.44 0.517 16.56 0.787 ;
     RECT  21.84 0.517 21.96 0.787 ;
     RECT  27.24 0.517 27.36 0.787 ;
     RECT  32.64 0.517 32.76 0.787 ;
     RECT  38.04 0.517 38.16 0.787 ;
     RECT  43.44 0.517 43.56 0.787 ;
     RECT  48.84 0.517 48.96 0.787 ;
     RECT  54.24 0.517 54.36 0.787 ;
     RECT  59.64 0.517 59.76 0.787 ;
     RECT  65.04 0.517 65.16 0.787 ;
     RECT  70.44 0.517 70.56 0.787 ;
     RECT  54.24 0.787 54.552 1.189 ;
     RECT  21.84 0.787 22.152 1.237 ;
     RECT  2.88 1.237 2.904 1.391 ;
     RECT  70.44 0.787 70.752 1.397 ;
     RECT  52.896 1.237 52.92 1.451 ;
     RECT  54.24 1.189 54.84 1.451 ;
     RECT  2.88 1.391 3.048 1.475 ;
     RECT  21.84 1.237 22.824 1.475 ;
     RECT  54.24 1.451 54.744 1.475 ;
     RECT  70.44 1.397 70.872 1.667 ;
     RECT  2.88 1.475 2.904 2.027 ;
     RECT  46.8 2.543 46.824 2.627 ;
     RECT  72.672 1.669 72.696 2.629 ;
     RECT  43.44 0.787 43.752 2.677 ;
     RECT  51.984 2.677 52.008 2.771 ;
     RECT  52.464 2.773 52.488 2.859 ;
     RECT  72.624 2.629 72.696 2.867 ;
     RECT  72.672 2.867 72.696 2.869 ;
     RECT  72.672 2.869 72.84 2.923 ;
     RECT  65.04 0.787 65.352 3.013 ;
     RECT  65.04 3.013 65.592 3.115 ;
     RECT  21.84 1.475 22.152 3.119 ;
     RECT  21.12 3.119 22.152 3.203 ;
     RECT  65.04 3.115 65.448 3.283 ;
     RECT  42.768 2.677 43.752 3.337 ;
     RECT  20.208 3.205 20.232 3.371 ;
     RECT  64.512 3.283 65.448 3.371 ;
     RECT  67.824 2.821 67.848 3.371 ;
     RECT  41.616 3.301 41.64 3.385 ;
     RECT  65.04 3.371 65.448 3.435 ;
     RECT  3.36 3.445 3.384 3.539 ;
     RECT  48.84 0.787 49.152 3.637 ;
     RECT  59.64 0.787 59.952 3.685 ;
     RECT  47.904 3.637 49.152 3.731 ;
     RECT  58.704 3.685 59.952 3.769 ;
     RECT  47.232 3.733 47.256 3.819 ;
     RECT  63.408 4.021 63.432 4.117 ;
     RECT  52.992 4.085 53.016 4.173 ;
     RECT  63.408 4.117 63.864 4.203 ;
     RECT  41.04 4.165 41.352 4.267 ;
     RECT  32.64 0.787 32.952 4.277 ;
     RECT  2.784 4.243 2.808 4.331 ;
     RECT  41.328 4.267 41.352 4.331 ;
     RECT  19.776 4.261 19.8 4.395 ;
     RECT  23.952 4.319 23.976 4.403 ;
     RECT  16.44 0.787 16.752 4.511 ;
     RECT  63.408 4.203 63.432 4.587 ;
     RECT  32.64 4.277 33.672 4.595 ;
     RECT  16.32 4.511 16.752 4.729 ;
     RECT  54.24 1.475 54.552 4.853 ;
     RECT  62.16 4.533 62.184 4.883 ;
     RECT  58.032 3.877 58.056 4.931 ;
     RECT  14.928 4.895 14.952 4.979 ;
     RECT  54.144 4.853 54.552 4.979 ;
     RECT  8.88 4.917 8.904 5.005 ;
     RECT  62.736 4.981 62.76 5.065 ;
     RECT  3.936 5.087 3.96 5.171 ;
     RECT  38.04 0.787 38.352 5.237 ;
     RECT  38.04 5.237 40.248 5.459 ;
     RECT  55.872 4.789 55.896 5.459 ;
     RECT  48.84 3.731 49.152 5.461 ;
     RECT  50.16 5.413 50.184 5.461 ;
     RECT  48.84 5.461 50.184 5.497 ;
     RECT  41.136 5.587 41.16 5.675 ;
     RECT  60.96 5.605 60.984 5.689 ;
     RECT  44.976 5.663 45 5.747 ;
     RECT  32.64 4.595 32.952 5.749 ;
     RECT  48.84 5.497 49.56 5.807 ;
     RECT  65.04 3.435 65.352 5.807 ;
     RECT  44.88 5.749 44.904 5.833 ;
     RECT  32.64 5.749 33.24 5.877 ;
     RECT  51.312 5.749 51.336 5.877 ;
     RECT  47.904 5.807 49.56 5.891 ;
     RECT  50.736 5.877 51.336 5.893 ;
     RECT  52.752 5.877 52.776 5.893 ;
     RECT  59.28 3.769 59.952 6.025 ;
     RECT  47.232 5.893 47.256 6.059 ;
     RECT  48.84 5.891 49.56 6.059 ;
     RECT  50.736 5.893 52.776 6.123 ;
     RECT  67.824 6.047 67.848 6.131 ;
     RECT  64.944 5.807 65.352 6.133 ;
     RECT  32.64 5.877 33.288 6.187 ;
     RECT  59.64 6.025 59.952 6.191 ;
     RECT  51.504 6.123 52.488 6.217 ;
     RECT  32.64 6.187 33.192 6.251 ;
     RECT  7.248 6.191 7.272 6.275 ;
     RECT  59.64 6.191 60.456 6.275 ;
     RECT  46.752 6.229 46.968 6.315 ;
     RECT  18 6.005 18.024 6.323 ;
     RECT  57.6 6.239 57.624 6.323 ;
     RECT  46.944 6.315 46.968 6.419 ;
     RECT  72.816 2.923 72.84 6.469 ;
     RECT  72.528 6.469 72.84 6.547 ;
     RECT  72.48 6.547 72.84 6.635 ;
     RECT  64.944 6.133 65.592 6.709 ;
     RECT  43.44 3.337 43.752 6.739 ;
     RECT  27.24 0.787 27.552 6.757 ;
     RECT  32.64 6.251 32.952 6.757 ;
     RECT  3.408 6.133 3.432 6.767 ;
     RECT  43.44 6.739 43.848 6.767 ;
     RECT  72.528 6.635 72.84 6.803 ;
     RECT  2.832 6.767 3.432 6.805 ;
     RECT  11.04 0.787 11.352 6.805 ;
     RECT  38.04 5.459 39.768 6.805 ;
     RECT  45.888 6.739 45.912 6.827 ;
     RECT  2.832 6.805 4.008 6.837 ;
     RECT  11.04 6.805 11.976 6.837 ;
     RECT  43.44 6.767 43.944 6.851 ;
     RECT  64.656 6.709 65.592 6.891 ;
     RECT  23.904 6.661 23.928 6.899 ;
     RECT  27.24 6.757 27.96 6.899 ;
     RECT  31.872 6.757 32.952 6.899 ;
     RECT  2.688 6.837 4.008 6.925 ;
     RECT  10.848 6.837 11.976 6.925 ;
     RECT  37.392 6.805 40.536 6.947 ;
     RECT  51.504 6.217 51.528 6.947 ;
     RECT  10.944 6.925 11.976 6.995 ;
     RECT  3.408 6.925 4.008 7.043 ;
     RECT  10.944 6.995 11.352 7.139 ;
     RECT  37.392 6.947 39.336 7.331 ;
     RECT  16.44 4.729 16.752 7.333 ;
     RECT  21.84 3.203 22.152 7.333 ;
     RECT  0.24 0.787 0.552 7.343 ;
     RECT  15.072 7.333 15.096 7.343 ;
     RECT  54.24 4.979 54.552 7.349 ;
     RECT  21.84 7.333 22.248 7.381 ;
     RECT  43.44 6.851 43.752 7.381 ;
     RECT  57.024 6.709 57.048 7.403 ;
     RECT  14.976 7.343 15.096 7.417 ;
     RECT  0.24 7.343 0.648 7.427 ;
     RECT  14.976 7.417 15 7.427 ;
     RECT  37.392 7.331 38.352 7.467 ;
     RECT  40.512 6.947 40.536 7.467 ;
     RECT  53.328 7.349 54.552 7.475 ;
     RECT  50.496 7.381 50.52 7.477 ;
     RECT  9.072 6.277 9.096 7.659 ;
     RECT  32.64 6.899 32.952 7.669 ;
     RECT  42.672 7.381 43.752 7.669 ;
     RECT  21.84 7.381 22.344 7.723 ;
     RECT  42.624 7.669 43.752 7.765 ;
     RECT  32.64 7.669 33.096 7.797 ;
     RECT  57.6 7.727 57.624 7.811 ;
     RECT  30.24 7.541 30.264 7.907 ;
     RECT  61.488 7.189 61.512 7.915 ;
     RECT  32.64 7.797 33.192 7.979 ;
     RECT  53.52 7.475 54.552 8.107 ;
     RECT  16.08 7.333 16.752 8.111 ;
     RECT  27.24 6.899 27.552 8.181 ;
     RECT  54.144 8.107 54.552 8.235 ;
     RECT  26.88 8.181 27.552 8.245 ;
     RECT  48.84 6.059 49.152 8.245 ;
     RECT  50.496 7.477 51.384 8.245 ;
     RECT  42.528 7.765 43.752 8.303 ;
     RECT  26.688 8.245 27.552 8.329 ;
     RECT  48.84 8.245 51.384 8.351 ;
     RECT  2.88 8.053 2.904 8.427 ;
     RECT  48.84 8.351 51.912 8.435 ;
     RECT  65.04 6.891 65.352 8.485 ;
     RECT  16.08 8.111 16.872 8.491 ;
     RECT  65.04 8.485 66.168 8.569 ;
     RECT  3.12 8.543 3.144 8.627 ;
     RECT  7.104 8.543 7.128 8.627 ;
     RECT  12.624 8.543 12.648 8.627 ;
     RECT  38.04 7.467 38.352 8.629 ;
     RECT  42.192 8.303 43.752 8.811 ;
     RECT  54.24 8.235 54.552 8.879 ;
     RECT  63.264 8.821 63.288 8.905 ;
     RECT  42.192 8.811 42.216 8.939 ;
     RECT  54.24 8.879 54.744 8.963 ;
     RECT  18.192 8.927 18.216 9.011 ;
     RECT  16.44 8.491 16.872 9.043 ;
     RECT  32.64 7.979 32.952 9.043 ;
     RECT  55.872 8.965 55.896 9.067 ;
     RECT  38.04 8.629 38.472 9.071 ;
     RECT  0.24 7.427 0.552 9.119 ;
     RECT  1.968 8.543 2.04 9.119 ;
     RECT  16.44 9.043 17.688 9.131 ;
     RECT  32.64 9.043 33.768 9.131 ;
     RECT  41.136 8.725 41.16 9.131 ;
     RECT  5.64 0.787 5.952 9.141 ;
     RECT  38.04 9.071 39.336 9.155 ;
     RECT  50.928 8.435 50.952 9.195 ;
     RECT  0.24 9.119 2.04 9.203 ;
     RECT  27.24 8.329 27.552 9.205 ;
     RECT  30.816 8.735 30.84 9.205 ;
     RECT  62.304 9.212 62.328 9.235 ;
     RECT  35.328 9.205 35.352 9.299 ;
     RECT  61.44 9.235 62.328 9.323 ;
     RECT  45.024 9.253 45.048 9.337 ;
     RECT  47.232 9.253 47.256 9.363 ;
     RECT  48.84 8.435 49.608 9.363 ;
     RECT  27.24 9.205 28.248 9.387 ;
     RECT  30.816 9.205 31.368 9.387 ;
     RECT  65.04 8.569 65.448 9.395 ;
     RECT  72.816 6.803 72.84 9.445 ;
     RECT  5.64 9.141 6.744 9.451 ;
     RECT  47.232 9.363 49.608 9.451 ;
     RECT  30.864 9.387 31.368 9.491 ;
     RECT  35.856 9.445 35.88 9.493 ;
     RECT  63.456 8.965 63.912 9.515 ;
     RECT  29.664 9.445 29.688 9.529 ;
     RECT  35.856 9.493 36.504 9.529 ;
     RECT  36.48 9.529 36.504 9.579 ;
     RECT  21.84 7.723 22.152 9.619 ;
     RECT  30.864 9.491 31.272 9.673 ;
     RECT  1.632 9.203 2.04 9.695 ;
     RECT  21.696 9.619 22.152 9.707 ;
     RECT  47.232 9.451 47.256 9.707 ;
     RECT  1.632 9.695 2.568 9.779 ;
     RECT  3.936 9.205 3.96 9.779 ;
     RECT  39.888 9.695 39.912 9.779 ;
     RECT  48.72 9.451 49.608 9.779 ;
     RECT  11.04 7.139 11.352 9.781 ;
     RECT  43.344 8.811 43.752 9.835 ;
     RECT  56.448 9.781 56.472 9.899 ;
     RECT  59.64 6.275 59.952 9.909 ;
     RECT  30.864 9.673 30.888 9.923 ;
     RECT  48.84 9.779 49.608 9.971 ;
     RECT  62.304 9.323 62.328 9.973 ;
     RECT  58.992 9.909 59.952 10.021 ;
     RECT  65.04 9.395 65.352 10.021 ;
     RECT  2.304 9.779 2.568 10.027 ;
     RECT  50.688 9.973 50.712 10.057 ;
     RECT  62.304 9.973 63.288 10.057 ;
     RECT  64.416 10.021 65.352 10.105 ;
     RECT  72.432 9.445 72.84 10.117 ;
     RECT  23.856 9.887 23.88 10.213 ;
     RECT  27.24 9.387 27.672 10.213 ;
     RECT  54.24 8.963 54.552 10.213 ;
     RECT  50.16 10.069 50.184 10.219 ;
     RECT  58.992 10.021 60.072 10.229 ;
     RECT  53.52 10.213 54.552 10.261 ;
     RECT  23.856 10.213 23.976 10.271 ;
     RECT  58.992 10.229 60.456 10.283 ;
     RECT  26.352 10.213 27.672 10.297 ;
     RECT  52.464 10.213 52.488 10.297 ;
     RECT  3.216 10.271 3.24 10.355 ;
     RECT  8.448 10.271 8.472 10.355 ;
     RECT  23.856 10.271 24.456 10.355 ;
     RECT  53.52 10.261 54.696 10.357 ;
     RECT  53.52 10.357 55.32 10.441 ;
     RECT  29.088 10.405 29.112 10.489 ;
     RECT  72.384 10.117 72.84 10.499 ;
     RECT  53.52 10.441 54.552 10.539 ;
     RECT  13.632 10.323 13.656 10.547 ;
     RECT  19.248 10.323 19.272 10.549 ;
     RECT  25.632 10.357 25.656 10.549 ;
     RECT  59.64 10.283 60.456 10.595 ;
     RECT  62.304 10.057 62.328 10.595 ;
     RECT  25.104 10.549 25.656 10.643 ;
     RECT  57.552 9.637 57.576 10.655 ;
     RECT  61.008 10.597 61.032 10.681 ;
     RECT  0.24 9.203 0.552 10.693 ;
     RECT  0.144 10.693 0.552 10.789 ;
     RECT  72.432 10.499 72.84 10.795 ;
     RECT  10.944 9.781 11.352 10.805 ;
     RECT  19.248 10.549 19.992 10.805 ;
     RECT  25.632 10.643 25.656 10.835 ;
     RECT  57.552 10.655 57.624 10.837 ;
     RECT  18.912 10.805 20.616 10.883 ;
     RECT  10.224 10.805 11.352 10.885 ;
     RECT  20.592 10.883 20.616 10.893 ;
     RECT  23.664 10.805 23.832 10.893 ;
     RECT  51.888 10.805 51.912 10.893 ;
     RECT  57.072 10.837 57.624 10.923 ;
     RECT  38.04 9.155 38.352 10.933 ;
     RECT  21.84 9.707 22.152 10.997 ;
     RECT  15.024 10.869 15.048 11.029 ;
     RECT  37.92 10.933 38.352 11.029 ;
     RECT  10.224 10.885 12.024 11.061 ;
     RECT  18.912 10.883 19.416 11.065 ;
     RECT  35.328 10.991 35.352 11.075 ;
     RECT  51.312 11.061 51.72 11.171 ;
     RECT  57.984 11.029 58.008 11.179 ;
     RECT  72.432 10.795 72.792 11.179 ;
     RECT  9.072 11.125 9.096 11.209 ;
     RECT  10.224 11.061 12.552 11.243 ;
     RECT  18.912 11.065 19.32 11.243 ;
     RECT  23.808 10.893 23.832 11.243 ;
     RECT  62.88 11.125 63.288 11.243 ;
     RECT  48.84 9.971 49.152 11.253 ;
     RECT  1.68 11.183 1.704 11.267 ;
     RECT  72.48 11.179 72.792 11.267 ;
     RECT  37.056 11.029 38.352 11.307 ;
     RECT  30.768 11.231 30.792 11.315 ;
     RECT  62.88 11.243 62.904 11.371 ;
     RECT  16.44 9.131 16.752 11.375 ;
     RECT  38.04 11.307 38.352 11.375 ;
     RECT  14.4 11.029 15.048 11.381 ;
     RECT  48.84 11.253 49.272 11.388 ;
     RECT  20.688 10.997 22.152 11.411 ;
     RECT  21.072 11.411 22.152 11.445 ;
     RECT  45.6 11.423 45.624 11.445 ;
     RECT  19.296 11.243 19.32 11.449 ;
     RECT  21.072 11.445 22.824 11.459 ;
     RECT  48.384 11.388 49.272 11.459 ;
     RECT  4.32 11.423 4.344 11.507 ;
     RECT  23.904 11.347 24.648 11.507 ;
     RECT  45.6 11.445 45.96 11.507 ;
     RECT  51.312 11.171 51.336 11.593 ;
     RECT  65.04 10.105 65.352 11.615 ;
     RECT  14.4 11.381 15.192 11.637 ;
     RECT  27.24 10.297 27.672 11.637 ;
     RECT  48.384 11.459 49.152 11.637 ;
     RECT  45.792 11.507 45.96 11.651 ;
     RECT  67.248 11.567 67.272 11.651 ;
     RECT  36.624 11.445 36.648 11.691 ;
     RECT  10.224 11.243 11.352 11.699 ;
     RECT  65.04 11.615 66.168 11.699 ;
     RECT  70.44 1.667 70.752 11.701 ;
     RECT  25.056 11.637 25.08 11.725 ;
     RECT  45.936 11.651 45.96 11.795 ;
     RECT  72.48 11.267 72.696 11.883 ;
     RECT  26.88 11.637 27.672 11.939 ;
     RECT  48.24 11.637 49.152 11.939 ;
     RECT  72.48 11.883 72.552 11.939 ;
     RECT  12.528 11.243 12.552 12.035 ;
     RECT  21.84 11.459 22.824 12.083 ;
     RECT  57.12 12.037 57.144 12.143 ;
     RECT  59.64 10.595 59.952 12.143 ;
     RECT  27.24 11.939 27.672 12.149 ;
     RECT  59.64 12.143 60.168 12.149 ;
     RECT  43.44 9.835 43.752 12.181 ;
     RECT  58.704 12.149 60.168 12.181 ;
     RECT  63.984 11.317 64.008 12.181 ;
     RECT  65.04 11.699 65.352 12.181 ;
     RECT  9.408 12.115 9.816 12.203 ;
     RECT  29.376 12.037 29.4 12.203 ;
     RECT  56.448 12.143 57.144 12.203 ;
     RECT  43.44 12.181 43.944 12.213 ;
     RECT  9.408 12.203 9.672 12.217 ;
     RECT  9.648 12.217 9.672 12.227 ;
     RECT  56.448 12.203 57.048 12.227 ;
     RECT  11.04 11.699 11.352 12.229 ;
     RECT  16.44 11.375 17.64 12.229 ;
     RECT  27.24 12.149 28.152 12.237 ;
     RECT  63.984 12.181 65.352 12.267 ;
     RECT  43.44 12.213 44.04 12.301 ;
     RECT  58.704 12.181 60.312 12.323 ;
     RECT  38.04 11.375 38.904 12.373 ;
     RECT  38.04 12.373 39.048 12.469 ;
     RECT  59.64 12.323 60.312 12.515 ;
     RECT  5.64 9.451 5.952 12.517 ;
     RECT  43.44 12.301 43.752 12.517 ;
     RECT  70.44 11.701 71.16 12.597 ;
     RECT  72.48 11.939 72.504 12.597 ;
     RECT  70.44 12.597 72.504 12.685 ;
     RECT  0.048 10.789 0.552 12.709 ;
     RECT  2.832 11.365 2.856 12.709 ;
     RECT  3.936 12.149 3.96 12.709 ;
     RECT  2.208 12.709 3.96 12.719 ;
     RECT  11.04 12.229 11.496 12.725 ;
     RECT  14.256 11.637 15.192 12.725 ;
     RECT  16.44 12.229 17.688 12.725 ;
     RECT  14.256 12.725 17.688 12.757 ;
     RECT  46.176 12.277 46.776 12.757 ;
     RECT  14.208 12.757 17.688 12.767 ;
     RECT  42.672 12.517 43.752 12.779 ;
     RECT  5.64 12.517 6.936 12.789 ;
     RECT  41.616 12.719 41.64 12.803 ;
     RECT  46.176 12.757 46.824 12.843 ;
     RECT  61.008 12.517 61.032 12.843 ;
     RECT  14.016 12.767 17.688 12.851 ;
     RECT  5.64 12.789 6.984 12.877 ;
     RECT  14.112 12.851 17.688 12.899 ;
     RECT  20.016 12.883 20.04 12.901 ;
     RECT  53.04 12.709 53.064 12.901 ;
     RECT  10.848 12.725 11.496 12.907 ;
     RECT  35.328 12.757 35.352 12.907 ;
     RECT  55.584 12.373 55.608 12.907 ;
     RECT  54.24 10.539 54.552 12.959 ;
     RECT  19.344 12.901 20.04 12.971 ;
     RECT  50.208 12.517 50.232 12.971 ;
     RECT  8.544 12.901 8.568 12.985 ;
     RECT  48.384 11.939 49.152 12.995 ;
     RECT  72.432 12.685 72.504 12.995 ;
     RECT  5.64 12.877 6.936 13.005 ;
     RECT  56.592 12.227 57.048 13.005 ;
     RECT  5.64 13.005 6.84 13.035 ;
     RECT  11.04 12.907 11.496 13.035 ;
     RECT  19.344 12.971 19.992 13.043 ;
     RECT  54.24 12.959 55.32 13.043 ;
     RECT  0.048 12.709 0.696 13.045 ;
     RECT  2.064 12.719 3.96 13.045 ;
     RECT  58.464 12.917 58.488 13.099 ;
     RECT  0.048 13.045 3.96 13.103 ;
     RECT  32.64 9.131 32.952 13.103 ;
     RECT  57.024 13.005 57.048 13.129 ;
     RECT  70.44 12.685 71.16 13.139 ;
     RECT  15.024 12.899 17.688 13.163 ;
     RECT  46.176 12.843 46.776 13.163 ;
     RECT  0.048 13.103 4.296 13.173 ;
     RECT  26.112 12.037 26.136 13.187 ;
     RECT  41.04 13.103 41.064 13.187 ;
     RECT  46.176 13.163 46.536 13.285 ;
     RECT  45.312 13.285 46.536 13.291 ;
     RECT  15.024 13.163 15.048 13.331 ;
     RECT  21.84 12.083 22.152 13.333 ;
     RECT  27.24 12.237 27.552 13.333 ;
     RECT  63.984 12.267 64.008 13.333 ;
     RECT  65.04 12.267 65.352 13.333 ;
     RECT  45.312 13.291 45.528 13.343 ;
     RECT  30.816 12.229 30.84 13.355 ;
     RECT  52.32 12.901 53.064 13.355 ;
     RECT  0.048 13.173 4.44 13.419 ;
     RECT  52.32 13.355 52.344 13.419 ;
     RECT  45.024 13.343 45.528 13.427 ;
     RECT  27.24 13.333 27.672 13.429 ;
     RECT  37.632 12.469 39.048 13.477 ;
     RECT  19.968 13.043 19.992 13.483 ;
     RECT  54.24 13.043 54.648 13.487 ;
     RECT  37.632 13.477 39.192 13.525 ;
     RECT  43.44 12.779 43.752 13.525 ;
     RECT  54.144 13.487 54.648 13.571 ;
     RECT  32.64 13.103 33.048 13.573 ;
     RECT  26.688 13.429 27.672 13.611 ;
     RECT  37.056 13.525 39.192 13.611 ;
     RECT  43.44 13.525 44.472 13.611 ;
     RECT  3.264 13.419 4.44 13.679 ;
     RECT  5.64 13.035 5.952 13.679 ;
     RECT  21.648 13.333 22.152 13.679 ;
     RECT  61.584 13.621 61.608 13.705 ;
     RECT  59.64 12.515 59.952 13.727 ;
     RECT  21.552 13.679 22.152 13.749 ;
     RECT  63.984 13.333 65.352 13.749 ;
     RECT  3.264 13.679 5.952 13.763 ;
     RECT  7.968 13.727 7.992 13.811 ;
     RECT  46.512 13.291 46.536 13.811 ;
     RECT  59.64 13.727 60.072 13.811 ;
     RECT  40.56 13.717 40.584 13.867 ;
     RECT  59.64 13.811 59.952 13.877 ;
     RECT  32.64 13.573 33.24 13.909 ;
     RECT  34.992 13.103 35.256 13.919 ;
     RECT  21.12 13.749 22.152 13.955 ;
     RECT  26.688 13.611 27.552 13.955 ;
     RECT  34.512 13.919 35.256 14.003 ;
     RECT  18.816 13.749 18.84 14.005 ;
     RECT  16.44 13.163 17.688 14.111 ;
     RECT  18.768 14.005 18.84 14.111 ;
     RECT  32.496 13.909 33.24 14.123 ;
     RECT  25.296 14.133 25.32 14.149 ;
     RECT  63.36 13.749 65.352 14.187 ;
     RECT  34.8 14.003 35.256 14.197 ;
     RECT  43.44 13.611 43.848 14.197 ;
     RECT  25.296 14.149 26.232 14.243 ;
     RECT  38.04 13.611 38.808 14.251 ;
     RECT  64.704 14.187 65.352 14.251 ;
     RECT  21.216 13.955 22.152 14.261 ;
     RECT  34.8 14.197 35.88 14.261 ;
     RECT  54.24 13.571 54.648 14.261 ;
     RECT  16.44 14.111 18.84 14.325 ;
     RECT  45.504 13.427 45.528 14.339 ;
     RECT  54.24 14.261 54.84 14.341 ;
     RECT  3.264 13.763 3.96 14.387 ;
     RECT  34.8 14.261 35.928 14.389 ;
     RECT  34.8 14.389 36.408 14.435 ;
     RECT  72.432 12.995 72.456 14.437 ;
     RECT  54.24 14.341 55.224 14.443 ;
     RECT  0.048 13.419 2.28 14.453 ;
     RECT  46.176 14.389 46.248 14.473 ;
     RECT  63.264 14.447 63.336 14.531 ;
     RECT  29.088 13.669 29.112 14.571 ;
     RECT  46.224 14.473 46.248 14.579 ;
     RECT  16.44 14.325 19.56 14.635 ;
     RECT  34.848 14.435 36.408 14.635 ;
     RECT  38.04 14.251 38.712 14.635 ;
     RECT  59.28 13.877 59.952 14.635 ;
     RECT  41.472 14.581 42.312 14.675 ;
     RECT  24.048 14.245 24.072 14.699 ;
     RECT  38.04 14.635 38.616 14.699 ;
     RECT  9.984 14.687 10.008 14.709 ;
     RECT  11.04 13.035 11.352 14.709 ;
     RECT  14.256 13.941 14.28 14.723 ;
     RECT  16.44 14.635 19.128 14.763 ;
     RECT  21.216 14.261 22.824 14.763 ;
     RECT  34.848 14.635 34.968 14.763 ;
     RECT  9.984 14.709 11.352 14.771 ;
     RECT  13.152 14.645 13.176 14.771 ;
     RECT  56.448 14.687 56.472 14.771 ;
     RECT  34.848 14.763 34.872 14.827 ;
     RECT  36.48 14.739 36.504 14.827 ;
     RECT  61.008 14.739 61.032 14.827 ;
     RECT  21.696 14.763 22.824 14.869 ;
     RECT  27.24 13.955 27.552 14.879 ;
     RECT  14.064 14.831 14.088 14.915 ;
     RECT  21.696 14.869 22.92 14.955 ;
     RECT  55.872 14.879 55.896 14.963 ;
     RECT  5.64 13.763 5.952 14.965 ;
     RECT  6.96 14.931 6.984 14.965 ;
     RECT  16.44 14.763 17.688 14.965 ;
     RECT  40.464 14.005 40.488 15.013 ;
     RECT  72.288 14.437 72.456 15.013 ;
     RECT  16.128 14.965 17.688 15.019 ;
     RECT  25.68 14.243 26.232 15.059 ;
     RECT  41.616 14.675 41.736 15.059 ;
     RECT  26.208 15.059 26.232 15.061 ;
     RECT  27.24 14.879 28.248 15.061 ;
     RECT  63.312 14.531 63.336 15.083 ;
     RECT  21.84 14.955 22.92 15.093 ;
     RECT  38.04 14.699 38.568 15.107 ;
     RECT  72.288 15.013 72.696 15.109 ;
     RECT  5.64 14.965 6.984 15.147 ;
     RECT  51.888 15.061 52.824 15.147 ;
     RECT  16.128 15.019 16.752 15.155 ;
     RECT  72.288 15.109 72.792 15.203 ;
     RECT  48.84 12.995 49.152 15.205 ;
     RECT  57.312 15.061 57.336 15.211 ;
     RECT  6.96 15.147 6.984 15.275 ;
     RECT  21.84 15.093 23.352 15.275 ;
     RECT  48.84 15.205 49.272 15.289 ;
     RECT  72.528 15.203 72.792 15.339 ;
     RECT  72.528 15.339 72.648 15.395 ;
     RECT  18.816 14.763 19.128 15.403 ;
     RECT  0.048 14.453 3.144 15.407 ;
     RECT  26.208 15.061 28.248 15.443 ;
     RECT  52.8 15.147 52.824 15.445 ;
     RECT  63.84 15.349 63.864 15.467 ;
     RECT  0.048 15.407 3.768 15.491 ;
     RECT  10.224 14.771 11.352 15.491 ;
     RECT  20.448 15.407 20.472 15.491 ;
     RECT  26.256 15.443 28.248 15.541 ;
     RECT  46.176 15.541 46.2 15.635 ;
     RECT  18.816 15.403 19.032 15.659 ;
     RECT  21.84 15.275 23.304 15.659 ;
     RECT  26.256 15.541 28.488 15.669 ;
     RECT  50.736 15.541 50.76 15.683 ;
     RECT  39.888 15.013 40.488 15.699 ;
     RECT  52.8 15.445 53.064 15.723 ;
     RECT  38.04 15.107 38.352 15.733 ;
     RECT  70.44 13.139 70.752 15.733 ;
     RECT  18.816 15.659 18.936 15.787 ;
     RECT  21.84 15.659 23.112 15.787 ;
     RECT  39.408 15.699 40.488 15.787 ;
     RECT  54.24 14.443 54.552 15.791 ;
     RECT  39.888 15.787 40.488 15.861 ;
     RECT  26.256 15.669 28.872 15.875 ;
     RECT  54.24 15.791 55.32 15.875 ;
     RECT  39.888 15.861 40.584 15.949 ;
     RECT  21.84 15.787 22.824 15.973 ;
     RECT  14.832 15.733 14.856 16.031 ;
     RECT  32.64 14.123 33.24 16.053 ;
     RECT  62.64 16.021 62.664 16.053 ;
     RECT  43.344 14.197 43.848 16.069 ;
     RECT  65.04 14.251 65.352 16.069 ;
     RECT  21.408 15.973 22.824 16.107 ;
     RECT  62.64 16.053 62.904 16.107 ;
     RECT  7.824 16.031 7.848 16.115 ;
     RECT  14.592 16.031 14.856 16.115 ;
     RECT  26.256 15.875 27.912 16.115 ;
     RECT  61.584 16.031 61.608 16.115 ;
     RECT  72.624 15.395 72.648 16.115 ;
     RECT  54.24 15.875 54.648 16.117 ;
     RECT  32.64 16.053 33.528 16.147 ;
     RECT  65.04 16.069 65.448 16.147 ;
     RECT  66.72 16.021 66.744 16.147 ;
     RECT  70.44 15.733 70.872 16.165 ;
     RECT  35.328 16.117 35.352 16.201 ;
     RECT  30.24 16.117 30.264 16.211 ;
     RECT  53.472 16.117 54.648 16.211 ;
     RECT  65.04 16.147 66.744 16.211 ;
     RECT  32.64 16.147 34.248 16.235 ;
     RECT  65.04 16.211 66.408 16.235 ;
     RECT  39.888 15.949 39.912 16.259 ;
     RECT  62.736 16.107 62.904 16.299 ;
     RECT  37.92 15.733 38.352 16.309 ;
     RECT  16.32 15.155 16.752 16.363 ;
     RECT  41.616 15.059 41.64 16.405 ;
     RECT  62.88 16.299 62.904 16.427 ;
     RECT  56.448 15.973 56.472 16.467 ;
     RECT  30.864 16.309 30.888 16.491 ;
     RECT  34.848 16.309 34.92 16.491 ;
     RECT  42.768 16.069 43.848 16.491 ;
     RECT  53.568 16.211 54.648 16.499 ;
     RECT  41.232 16.405 41.64 16.501 ;
     RECT  43.44 16.491 43.848 16.501 ;
     RECT  56.352 16.467 56.472 16.501 ;
     RECT  18.528 16.053 18.696 16.547 ;
     RECT  12.528 14.917 13.08 16.549 ;
     RECT  18.528 16.547 18.552 16.555 ;
     RECT  56.352 16.501 57.048 16.555 ;
     RECT  4.512 15.925 4.536 16.559 ;
     RECT  10.272 15.491 11.352 16.559 ;
     RECT  0.048 15.491 2.904 16.565 ;
     RECT  57.024 16.555 57.048 16.585 ;
     RECT  4.464 16.559 4.536 16.597 ;
     RECT  70.44 16.165 71.16 16.597 ;
     RECT  46.848 16.405 46.872 16.619 ;
     RECT  10.08 16.559 11.352 16.645 ;
     RECT  37.92 16.309 38.904 16.645 ;
     RECT  12.528 16.549 13.176 16.691 ;
     RECT  4.464 16.597 4.632 16.693 ;
     RECT  5.64 15.147 5.952 16.693 ;
     RECT  9.696 16.645 11.352 16.693 ;
     RECT  12.528 16.691 12.552 16.693 ;
     RECT  26.256 16.115 27.552 16.741 ;
     RECT  4.464 16.693 5.952 16.747 ;
     RECT  0.048 16.565 3.48 16.757 ;
     RECT  15.36 16.693 15.432 16.787 ;
     RECT  70.44 16.597 71.304 16.787 ;
     RECT  59.64 14.635 59.952 16.799 ;
     RECT  9.696 16.693 12.552 16.811 ;
     RECT  29.088 16.165 29.112 16.811 ;
     RECT  31.392 16.799 31.416 16.821 ;
     RECT  32.64 16.235 33.432 16.821 ;
     RECT  21.648 16.107 22.824 16.825 ;
     RECT  26.112 16.741 27.552 16.825 ;
     RECT  58.8 16.799 59.952 16.837 ;
     RECT  13.632 16.693 13.896 16.875 ;
     RECT  0.048 16.757 3.72 16.883 ;
     RECT  31.392 16.821 33.432 16.883 ;
     RECT  58.128 16.837 59.952 16.883 ;
     RECT  54.24 16.499 54.648 16.885 ;
     RECT  31.728 16.883 33.432 16.909 ;
     RECT  18.24 16.757 18.264 16.931 ;
     RECT  19.824 16.821 19.992 16.931 ;
     RECT  21.84 16.825 22.824 16.931 ;
     RECT  25.056 16.885 25.08 16.933 ;
     RECT  0.048 16.883 3.528 16.939 ;
     RECT  41.232 16.501 42.312 16.939 ;
     RECT  19.968 16.931 19.992 16.949 ;
     RECT  24.528 16.933 25.08 16.969 ;
     RECT  26.208 16.825 27.552 16.979 ;
     RECT  0.048 16.939 3.48 17.003 ;
     RECT  15.408 16.787 15.432 17.003 ;
     RECT  58.128 16.883 58.152 17.003 ;
     RECT  24.528 16.969 24.552 17.013 ;
     RECT  24.192 17.013 24.552 17.017 ;
     RECT  19.968 16.949 20.52 17.067 ;
     RECT  34.896 16.491 34.92 17.067 ;
     RECT  7.44 16.549 7.608 17.077 ;
     RECT  43.44 16.501 43.944 17.077 ;
     RECT  72.384 16.597 72.408 17.077 ;
     RECT  10.224 16.811 12.552 17.123 ;
     RECT  47.328 17.013 47.352 17.123 ;
     RECT  54.24 16.885 55.32 17.123 ;
     RECT  4.704 16.747 5.952 17.171 ;
     RECT  7.296 17.077 7.656 17.171 ;
     RECT  11.04 17.123 12.552 17.171 ;
     RECT  13.68 16.875 13.896 17.171 ;
     RECT  50.16 17.077 50.28 17.171 ;
     RECT  59.376 16.883 59.952 17.219 ;
     RECT  65.04 16.235 65.592 17.219 ;
     RECT  0.048 17.003 3.384 17.267 ;
     RECT  72.288 17.077 72.408 17.267 ;
     RECT  32.64 16.909 33.432 17.363 ;
     RECT  37.056 16.645 38.904 17.461 ;
     RECT  11.04 17.171 12.024 17.507 ;
     RECT  65.04 17.219 65.352 17.509 ;
     RECT  43.44 17.077 44.664 17.567 ;
     RECT  48.84 15.289 49.152 17.567 ;
     RECT  42.624 17.567 44.664 17.589 ;
     RECT  50.256 17.171 50.28 17.589 ;
     RECT  62.736 17.557 62.76 17.589 ;
     RECT  36.48 17.461 38.904 17.603 ;
     RECT  20.16 17.067 20.52 17.605 ;
     RECT  42.624 17.589 44.76 17.619 ;
     RECT  42.624 17.619 45.576 17.643 ;
     RECT  50.256 17.589 50.376 17.643 ;
     RECT  62.736 17.589 62.856 17.643 ;
     RECT  64.416 17.509 65.352 17.643 ;
     RECT  42.624 17.643 43.752 17.651 ;
     RECT  48.72 17.567 49.152 17.651 ;
     RECT  41.232 16.939 41.256 17.653 ;
     RECT  52.032 17.619 52.056 17.653 ;
     RECT  72.384 17.267 72.408 17.653 ;
     RECT  44.736 17.643 45.576 17.677 ;
     RECT  50.352 17.643 50.376 17.677 ;
     RECT  62.832 17.643 62.856 17.677 ;
     RECT  13.68 17.171 13.704 17.699 ;
     RECT  29.136 17.619 29.4 17.707 ;
     RECT  45.552 17.677 45.576 17.707 ;
     RECT  51.744 17.653 52.056 17.737 ;
     RECT  7.632 17.171 7.656 17.747 ;
     RECT  39.888 17.653 39.912 17.747 ;
     RECT  57.6 17.653 57.624 17.747 ;
     RECT  41.04 17.653 41.256 17.795 ;
     RECT  26.976 16.979 27.552 17.941 ;
     RECT  0.144 17.267 3.384 18.085 ;
     RECT  21.84 16.931 22.776 18.085 ;
     RECT  34.656 17.653 34.68 18.133 ;
     RECT  51.84 17.737 52.056 18.133 ;
     RECT  9.216 18.133 9.24 18.143 ;
     RECT  20.16 17.605 20.616 18.143 ;
     RECT  21.84 18.085 22.872 18.143 ;
     RECT  26.976 17.941 27.672 18.165 ;
     RECT  41.232 17.795 41.256 18.179 ;
     RECT  24.192 17.017 24.216 18.181 ;
     RECT  0.144 18.085 3.528 18.218 ;
     RECT  9.12 18.143 9.24 18.219 ;
     RECT  11.04 17.507 11.832 18.219 ;
     RECT  25.824 17.797 25.848 18.219 ;
     RECT  29.136 17.707 29.304 18.219 ;
     RECT  34.656 18.133 34.776 18.219 ;
     RECT  37.92 17.603 38.904 18.219 ;
     RECT  9.12 18.219 9.144 18.227 ;
     RECT  47.184 18.143 47.208 18.227 ;
     RECT  11.04 18.219 11.736 18.229 ;
     RECT  16.44 16.363 16.752 18.229 ;
     RECT  17.904 18.165 17.928 18.229 ;
     RECT  26.976 18.165 27.768 18.229 ;
     RECT  10.272 18.229 11.736 18.275 ;
     RECT  20.16 18.143 22.872 18.277 ;
     RECT  24.096 18.181 24.216 18.277 ;
     RECT  20.16 18.277 24.216 18.283 ;
     RECT  36.48 17.603 36.504 18.283 ;
     RECT  14.88 18.229 14.904 18.357 ;
     RECT  0.144 18.218 3.576 18.373 ;
     RECT  5.328 17.171 5.952 18.411 ;
     RECT  25.92 18.229 27.768 18.411 ;
     RECT  29.136 18.219 29.16 18.421 ;
     RECT  5.64 18.411 5.952 18.469 ;
     RECT  29.04 18.421 29.16 18.505 ;
     RECT  35.184 18.229 35.208 18.563 ;
     RECT  51.84 18.133 52.488 18.563 ;
     RECT  63.264 18.527 63.288 18.611 ;
     RECT  14.88 18.357 15.384 18.613 ;
     RECT  31.344 18.517 31.368 18.613 ;
     RECT  70.44 16.787 71.16 18.659 ;
     RECT  57.024 17.845 57.048 18.661 ;
     RECT  0.048 18.373 3.576 18.667 ;
     RECT  29.136 18.505 29.16 18.667 ;
     RECT  31.344 18.613 31.464 18.667 ;
     RECT  26.208 18.411 27.768 18.697 ;
     RECT  46.752 18.613 46.776 18.697 ;
     RECT  5.64 18.469 7.416 18.709 ;
     RECT  48.84 17.651 49.152 18.709 ;
     RECT  56.448 18.661 57.048 18.745 ;
     RECT  5.64 18.709 8.04 18.795 ;
     RECT  26.784 18.697 27.768 18.795 ;
     RECT  31.44 18.667 31.464 18.795 ;
     RECT  47.904 18.709 49.152 18.795 ;
     RECT  72.384 17.653 72.456 18.805 ;
     RECT  5.64 18.795 7.992 18.851 ;
     RECT  14.832 18.613 15.384 18.851 ;
     RECT  72.384 18.805 72.504 18.853 ;
     RECT  51.84 18.563 51.912 18.864 ;
     RECT  5.64 18.851 6.984 18.899 ;
     RECT  20.544 18.283 24.216 18.911 ;
     RECT  32.64 17.363 33.096 18.911 ;
     RECT  59.64 17.219 59.952 18.911 ;
     RECT  1.968 18.667 3.576 18.933 ;
     RECT  51.888 18.864 51.912 18.947 ;
     RECT  32.496 18.911 33.096 18.949 ;
     RECT  40.464 18.869 40.488 18.995 ;
     RECT  59.28 18.911 59.952 18.995 ;
     RECT  16.44 18.229 17.928 18.997 ;
     RECT  19.536 18.565 19.56 18.997 ;
     RECT  16.44 18.997 19.56 19.051 ;
     RECT  20.544 18.911 24.504 19.051 ;
     RECT  27.24 18.795 27.768 19.061 ;
     RECT  42.768 17.651 43.752 19.061 ;
     RECT  20.544 19.051 23.16 19.081 ;
     RECT  55.872 18.997 55.896 19.081 ;
     RECT  21.072 19.081 23.16 19.091 ;
     RECT  32.496 18.949 33.672 19.115 ;
     RECT  37.92 18.219 38.352 19.141 ;
     RECT  57.024 18.745 57.048 19.141 ;
     RECT  72.096 18.853 72.504 19.141 ;
     RECT  1.968 18.933 3.912 19.155 ;
     RECT  37.632 19.141 38.352 19.155 ;
     RECT  13.152 19.045 13.176 19.179 ;
     RECT  72.096 19.141 72.6 19.237 ;
     RECT  39.888 19.189 39.912 19.273 ;
     RECT  10.272 18.275 11.352 19.285 ;
     RECT  42 19.061 43.752 19.285 ;
     RECT  72.096 19.237 72.696 19.295 ;
     RECT  46.08 19.285 46.2 19.371 ;
     RECT  32.496 19.115 33.048 19.379 ;
     RECT  72.096 19.295 72.792 19.379 ;
     RECT  1.968 19.155 4.296 19.381 ;
     RECT  5.64 18.899 6.552 19.381 ;
     RECT  10.272 19.285 12.072 19.381 ;
     RECT  65.04 17.643 65.352 19.381 ;
     RECT  16.44 19.051 17.112 19.427 ;
     RECT  10.032 19.381 12.504 19.435 ;
     RECT  21.312 19.091 23.16 19.435 ;
     RECT  1.968 19.381 6.552 19.475 ;
     RECT  10.032 19.435 11.352 19.475 ;
     RECT  12.48 19.435 12.504 19.475 ;
     RECT  32.496 19.379 32.952 19.475 ;
     RECT  24.192 19.051 24.504 19.487 ;
     RECT  57.024 19.141 57.624 19.499 ;
     RECT  1.968 19.475 4.584 19.523 ;
     RECT  16.44 19.427 16.872 19.523 ;
     RECT  42 19.285 44.472 19.525 ;
     RECT  18.24 19.051 19.56 19.571 ;
     RECT  24.192 19.487 24.552 19.571 ;
     RECT  27.24 19.061 27.912 19.621 ;
     RECT  37.296 19.155 38.352 19.621 ;
     RECT  27.24 19.621 27.96 19.705 ;
     RECT  7.968 18.851 7.992 19.813 ;
     RECT  37.056 19.621 38.352 19.819 ;
     RECT  54.24 17.123 54.552 19.829 ;
     RECT  46.176 19.371 46.2 19.849 ;
     RECT  7.872 19.813 7.992 19.897 ;
     RECT  42 19.525 44.568 19.897 ;
     RECT  37.632 19.819 38.352 19.947 ;
     RECT  0.048 18.667 0.936 19.955 ;
     RECT  18.816 19.571 19.56 19.957 ;
     RECT  53.568 19.829 54.552 20.003 ;
     RECT  21.312 19.435 22.824 20.011 ;
     RECT  18.816 19.957 19.896 20.041 ;
     RECT  19.872 20.041 19.896 20.051 ;
     RECT  38.04 19.947 38.352 20.053 ;
     RECT  42 19.897 43.752 20.053 ;
     RECT  57.024 19.499 57.048 20.099 ;
     RECT  29.568 20.053 29.592 20.139 ;
     RECT  38.04 20.053 38.76 20.139 ;
     RECT  41.808 20.053 43.752 20.139 ;
     RECT  59.64 18.995 59.952 20.149 ;
     RECT  64.368 19.381 65.352 20.179 ;
     RECT  19.968 20.149 19.992 20.233 ;
     RECT  35.088 20.179 35.112 20.267 ;
     RECT  64.08 20.179 65.352 20.267 ;
     RECT  18.816 20.041 18.84 20.331 ;
     RECT  14.832 18.851 14.952 20.341 ;
     RECT  59.64 20.149 60.072 20.341 ;
     RECT  38.04 20.139 38.616 20.365 ;
     RECT  54.24 20.003 54.552 20.399 ;
     RECT  4.224 19.523 4.584 20.437 ;
     RECT  5.64 19.475 6.552 20.437 ;
     RECT  14.832 20.341 15.288 20.459 ;
     RECT  8.448 20.437 8.472 20.523 ;
     RECT  38.04 20.365 38.472 20.523 ;
     RECT  1.968 19.523 3.096 20.533 ;
     RECT  4.224 20.437 6.552 20.533 ;
     RECT  10.848 19.475 11.352 20.533 ;
     RECT  16.44 19.523 16.752 20.533 ;
     RECT  1.968 20.533 6.888 20.597 ;
     RECT  9.552 20.533 9.576 20.617 ;
     RECT  36.24 20.293 36.264 20.789 ;
     RECT  1.968 20.597 6.984 20.819 ;
     RECT  1.968 20.819 2.904 20.843 ;
     RECT  64.944 20.267 65.352 20.867 ;
     RECT  45.024 20.639 45.048 20.907 ;
     RECT  34.848 20.469 34.872 20.915 ;
     RECT  13.056 20.597 13.08 20.917 ;
     RECT  72.096 19.379 72.552 20.947 ;
     RECT  59.64 20.341 60.456 20.965 ;
     RECT  3.984 20.819 6.984 20.971 ;
     RECT  0.048 19.955 0.888 20.981 ;
     RECT  1.968 20.843 2.52 20.981 ;
     RECT  71.76 20.947 72.552 20.981 ;
     RECT  12.384 20.917 13.08 21.001 ;
     RECT  41.616 20.597 41.64 21.011 ;
     RECT  3.984 20.971 5.952 21.035 ;
     RECT  21.744 20.011 22.824 21.035 ;
     RECT  71.76 20.981 72.696 21.035 ;
     RECT  59.52 20.965 61.608 21.049 ;
     RECT  38.04 20.523 38.352 21.075 ;
     RECT  35.856 20.789 36.264 21.099 ;
     RECT  72.096 21.035 72.696 21.107 ;
     RECT  21.84 21.035 22.824 21.109 ;
     RECT  23.952 20.053 23.976 21.109 ;
     RECT  32.64 19.475 32.952 21.109 ;
     RECT  37.92 21.075 38.352 21.109 ;
     RECT  12.528 21.001 13.08 21.155 ;
     RECT  27.24 19.705 27.552 21.157 ;
     RECT  59.52 21.049 60.984 21.163 ;
     RECT  62.352 21.075 62.376 21.163 ;
     RECT  63.84 21.061 63.864 21.163 ;
     RECT  43.44 20.139 43.752 21.173 ;
     RECT  29.808 21.109 29.832 21.203 ;
     RECT  39.984 21.109 40.008 21.203 ;
     RECT  15.024 20.459 15.288 21.237 ;
     RECT  16.44 20.533 16.968 21.237 ;
     RECT  54.24 20.399 55.32 21.241 ;
     RECT  63.264 21.215 63.768 21.299 ;
     RECT  10.752 20.533 11.352 21.301 ;
     RECT  25.68 20.591 25.704 21.301 ;
     RECT  26.784 21.157 27.552 21.301 ;
     RECT  32.64 21.109 33.048 21.301 ;
     RECT  15.024 21.237 16.968 21.347 ;
     RECT  19.968 21.267 19.992 21.355 ;
     RECT  31.392 21.253 31.416 21.355 ;
     RECT  35.856 21.099 35.88 21.355 ;
     RECT  48.84 18.795 49.152 21.359 ;
     RECT  9.696 21.237 9.72 21.365 ;
     RECT  10.752 21.301 11.544 21.365 ;
     RECT  58.128 21.109 58.152 21.385 ;
     RECT  32.64 21.301 33.672 21.395 ;
     RECT  16.44 21.347 16.968 21.445 ;
     RECT  59.64 21.163 60.456 21.483 ;
     RECT  21.84 21.109 23.976 21.539 ;
     RECT  37.632 21.109 38.352 21.541 ;
     RECT  39.888 21.205 39.912 21.541 ;
     RECT  54.24 21.241 54.696 21.547 ;
     RECT  6.96 20.971 6.984 21.577 ;
     RECT  31.344 21.493 31.368 21.587 ;
     RECT  70.44 18.659 70.752 21.589 ;
     RECT  37.632 21.541 39.912 21.611 ;
     RECT  16.44 21.445 17.112 21.637 ;
     RECT  15.024 21.347 15.048 21.675 ;
     RECT  37.632 21.611 39.048 21.675 ;
     RECT  43.344 21.173 43.752 21.685 ;
     RECT  65.04 20.867 65.352 21.749 ;
     RECT  3.984 21.035 4.248 21.875 ;
     RECT  41.904 21.157 42.216 21.923 ;
     RECT  0.048 20.981 2.52 21.925 ;
     RECT  48.84 21.359 49.272 21.925 ;
     RECT  16.44 21.637 17.688 21.931 ;
     RECT  21.84 21.539 23.832 21.931 ;
     RECT  57.552 21.541 57.576 21.931 ;
     RECT  42 21.923 42.216 21.941 ;
     RECT  63.744 21.299 63.768 21.995 ;
     RECT  0.048 21.925 2.616 22.005 ;
     RECT  42 21.941 42.264 22.059 ;
     RECT  43.344 21.685 43.992 22.059 ;
     RECT  47.904 21.925 49.272 22.059 ;
     RECT  0.048 22.005 2.76 22.069 ;
     RECT  13.584 22.005 13.608 22.069 ;
     RECT  65.04 21.749 66.168 22.127 ;
     RECT  13.584 22.069 13.992 22.133 ;
     RECT  37.632 21.675 39 22.165 ;
     RECT  46.704 22.117 46.728 22.165 ;
     RECT  63.84 22.127 66.168 22.211 ;
     RECT  5.64 21.035 5.952 22.213 ;
     RECT  70.272 21.589 70.752 22.213 ;
     RECT  23.712 21.931 23.832 22.251 ;
     RECT  43.344 22.059 43.896 22.251 ;
     RECT  46.608 22.165 47.112 22.251 ;
     RECT  0.048 22.069 3.432 22.259 ;
     RECT  65.04 22.211 66.168 22.259 ;
     RECT  8.544 21.157 8.568 22.261 ;
     RECT  9.696 21.365 11.544 22.261 ;
     RECT  42.192 22.059 42.264 22.261 ;
     RECT  43.344 22.251 43.848 22.261 ;
     RECT  42.192 22.261 43.848 22.307 ;
     RECT  7.824 22.261 11.544 22.309 ;
     RECT  12.528 21.155 12.552 22.309 ;
     RECT  30.24 21.685 30.264 22.319 ;
     RECT  7.824 22.309 12.552 22.355 ;
     RECT  7.824 22.355 7.848 22.403 ;
     RECT  16.44 21.931 17.64 22.403 ;
     RECT  25.68 21.301 28.488 22.403 ;
     RECT  9.168 22.355 12.552 22.413 ;
     RECT  10.176 22.413 12.552 22.443 ;
     RECT  12.528 22.443 12.552 22.451 ;
     RECT  52.464 21.061 52.488 22.451 ;
     RECT  56.448 22.367 56.472 22.451 ;
     RECT  54.24 21.547 54.552 22.453 ;
     RECT  53.568 22.453 54.552 22.537 ;
     RECT  55.632 22.453 55.656 22.537 ;
     RECT  10.176 22.443 11.448 22.547 ;
     RECT  70.224 22.213 70.752 22.645 ;
     RECT  10.176 22.547 11.352 22.691 ;
     RECT  0.048 22.259 3.288 22.835 ;
     RECT  13.584 22.133 14.088 22.835 ;
     RECT  23.808 22.251 23.832 22.835 ;
     RECT  42.192 22.307 43.752 22.835 ;
     RECT  25.68 22.403 27.552 22.933 ;
     RECT  30.24 22.319 30.648 22.933 ;
     RECT  5.136 22.213 5.952 22.943 ;
     RECT  18.96 22.789 18.984 22.943 ;
     RECT  37.584 22.165 39 22.943 ;
     RECT  19.968 22.885 19.992 22.965 ;
     RECT  5.088 22.943 5.952 23.026 ;
     RECT  18.816 22.943 18.984 23.027 ;
     RECT  25.104 22.933 27.552 23.027 ;
     RECT  63.84 22.211 64.056 23.027 ;
     RECT  5.04 23.026 5.952 23.029 ;
     RECT  19.968 22.965 20.616 23.029 ;
     RECT  21.84 21.931 22.344 23.029 ;
     RECT  25.104 23.027 25.128 23.029 ;
     RECT  48.84 22.059 49.272 23.029 ;
     RECT  25.056 23.029 25.128 23.03 ;
     RECT  30.24 22.933 31.368 23.075 ;
     RECT  25.056 23.03 25.08 23.113 ;
     RECT  47.904 23.029 50.856 23.113 ;
     RECT  62.784 23.029 62.808 23.113 ;
     RECT  26.688 23.027 27.552 23.123 ;
     RECT  30.24 23.075 31.272 23.123 ;
     RECT  30.528 23.123 31.272 23.171 ;
     RECT  42.192 22.835 42.216 23.315 ;
     RECT  9.168 22.413 9.192 23.317 ;
     RECT  36.864 22.943 39 23.317 ;
     RECT  19.968 23.029 22.344 23.365 ;
     RECT  26.736 23.123 27.552 23.411 ;
     RECT  9.12 23.317 9.192 23.519 ;
     RECT  5.04 23.029 6.072 23.541 ;
     RECT  36.288 23.317 39.336 23.541 ;
     RECT  36.288 23.541 39.432 23.595 ;
     RECT  5.04 23.541 6.984 23.603 ;
     RECT  8.352 23.519 9.672 23.603 ;
     RECT  59.64 21.483 59.952 23.605 ;
     RECT  45.552 23.541 46.728 23.651 ;
     RECT  13.104 23.125 13.128 23.659 ;
     RECT  43.44 22.835 43.752 23.663 ;
     RECT  14.784 23.029 14.856 23.669 ;
     RECT  58.944 23.605 59.952 23.699 ;
     RECT  5.184 23.603 6.984 23.723 ;
     RECT  34.8 23.541 34.824 23.723 ;
     RECT  63.984 23.027 64.056 23.733 ;
     RECT  65.04 22.259 65.352 23.733 ;
     RECT  12.48 23.663 12.552 23.747 ;
     RECT  43.44 23.663 44.472 23.747 ;
     RECT  37.392 23.595 39.432 23.757 ;
     RECT  45.552 23.651 45.624 23.763 ;
     RECT  14.784 23.669 15 23.797 ;
     RECT  24.576 23.635 24.648 23.797 ;
     RECT  39.408 23.757 39.432 23.851 ;
     RECT  45.456 23.763 45.624 23.851 ;
     RECT  50.496 23.113 50.856 23.851 ;
     RECT  30.816 23.171 31.272 23.881 ;
     RECT  24.384 23.797 24.648 23.891 ;
     RECT  14.688 23.797 15 23.903 ;
     RECT  63.984 23.733 65.352 23.915 ;
     RECT  0.048 22.835 2.952 23.925 ;
     RECT  16.44 22.403 17.208 23.925 ;
     RECT  14.688 23.903 15.288 23.939 ;
     RECT  18.768 23.797 18.792 23.979 ;
     RECT  14.832 23.939 15.288 23.987 ;
     RECT  40.464 23.669 40.488 23.987 ;
     RECT  64.704 23.915 65.352 23.989 ;
     RECT  0.048 23.925 3.048 24.035 ;
     RECT  19.776 23.365 22.344 24.037 ;
     RECT  19.248 24.037 22.344 24.083 ;
     RECT  34.224 23.989 34.248 24.083 ;
     RECT  32.64 21.395 32.952 24.117 ;
     RECT  16.44 23.925 17.592 24.131 ;
     RECT  51.312 24.085 51.336 24.171 ;
     RECT  4.176 24.053 4.2 24.181 ;
     RECT  9.12 23.603 9.672 24.181 ;
     RECT  10.848 22.691 11.352 24.181 ;
     RECT  68.496 24.053 68.52 24.181 ;
     RECT  19.248 24.083 19.896 24.227 ;
     RECT  32.64 24.117 33.672 24.227 ;
     RECT  53.04 23.605 53.064 24.229 ;
     RECT  14.832 23.987 15 24.235 ;
     RECT  68.496 24.181 69.192 24.275 ;
     RECT  70.176 22.645 70.752 24.287 ;
     RECT  9.12 24.181 11.352 24.299 ;
     RECT  12.528 23.747 12.552 24.299 ;
     RECT  9.648 24.299 11.352 24.333 ;
     RECT  45.6 23.851 45.624 24.363 ;
     RECT  68.496 24.275 68.52 24.363 ;
     RECT  42.096 24.019 42.12 24.403 ;
     RECT  19.248 24.227 19.848 24.427 ;
     RECT  41.616 24.403 42.12 24.431 ;
     RECT  9.648 24.333 9.672 24.457 ;
     RECT  4.08 24.181 4.2 24.479 ;
     RECT  58.128 23.701 58.152 24.479 ;
     RECT  61.008 24.421 61.032 24.505 ;
     RECT  41.472 24.431 42.12 24.515 ;
     RECT  3.936 24.479 4.2 24.563 ;
     RECT  14.976 24.235 15 24.563 ;
     RECT  57.6 24.479 58.152 24.563 ;
     RECT  64.704 23.989 65.592 24.563 ;
     RECT  10.944 24.333 11.352 24.565 ;
     RECT  21.168 24.083 22.344 24.565 ;
     RECT  27.24 23.411 27.552 24.565 ;
     RECT  30.816 23.881 30.84 24.565 ;
     RECT  54.24 22.537 54.552 24.565 ;
     RECT  55.824 24.531 55.848 24.565 ;
     RECT  35.76 24.565 35.784 24.595 ;
     RECT  37.392 23.757 38.352 24.619 ;
     RECT  52.464 24.229 53.064 24.619 ;
     RECT  54.24 24.565 55.848 24.619 ;
     RECT  58.128 24.563 58.152 24.619 ;
     RECT  35.76 24.595 35.928 24.629 ;
     RECT  47.424 23.669 47.448 24.629 ;
     RECT  48.84 23.113 49.272 24.629 ;
     RECT  0.048 24.035 2.856 24.649 ;
     RECT  30.624 24.565 30.84 24.649 ;
     RECT  35.76 24.629 36.504 24.649 ;
     RECT  10.944 24.565 11.448 24.659 ;
     RECT  26.976 24.565 27.672 24.659 ;
     RECT  54.24 24.619 55.608 24.659 ;
     RECT  4.128 24.563 4.2 24.661 ;
     RECT  5.184 23.723 6.888 24.661 ;
     RECT  26.976 24.659 27.552 24.671 ;
     RECT  35.904 24.649 36.504 24.683 ;
     RECT  55.584 24.659 55.608 24.683 ;
     RECT  36.48 24.683 36.504 24.717 ;
     RECT  11.04 24.659 11.448 24.747 ;
     RECT  46.704 24.629 47.448 24.755 ;
     RECT  48.84 24.629 50.136 24.755 ;
     RECT  4.128 24.661 6.888 24.757 ;
     RECT  26.88 24.671 27.552 24.757 ;
     RECT  70.128 24.287 70.752 24.757 ;
     RECT  72.096 21.107 72.648 24.757 ;
     RECT  19.392 24.427 19.848 24.811 ;
     RECT  41.616 24.515 42.12 24.885 ;
     RECT  56.928 24.565 56.952 24.899 ;
     RECT  4.128 24.757 7.656 24.947 ;
     RECT  26.784 24.757 27.552 24.949 ;
     RECT  70.128 24.757 72.648 24.949 ;
     RECT  30.816 24.649 30.84 24.997 ;
     RECT  32.64 24.227 32.952 24.997 ;
     RECT  54.24 24.659 54.552 24.997 ;
     RECT  47.616 24.805 47.64 25.003 ;
     RECT  21.168 24.565 23.064 25.055 ;
     RECT  4.128 24.947 7.56 25.067 ;
     RECT  25.92 24.949 27.552 25.067 ;
     RECT  30.816 24.997 32.952 25.081 ;
     RECT  70.128 24.949 72.696 25.101 ;
     RECT  54.144 24.997 54.552 25.107 ;
     RECT  41.616 24.885 42.168 25.139 ;
     RECT  59.64 23.699 59.952 25.141 ;
     RECT  70.176 25.101 72.696 25.189 ;
     RECT  53.712 25.107 54.552 25.195 ;
     RECT  52.464 24.619 52.488 25.225 ;
     RECT  25.92 25.067 26.232 25.237 ;
     RECT  64.704 24.563 65.352 25.237 ;
     RECT  21.12 25.055 23.064 25.247 ;
     RECT  58.704 25.141 59.952 25.259 ;
     RECT  64.416 25.237 65.352 25.285 ;
     RECT  19.392 24.811 19.512 25.323 ;
     RECT  63.84 25.285 65.352 25.323 ;
     RECT  70.176 25.189 72.936 25.331 ;
     RECT  21.12 25.247 23.352 25.381 ;
     RECT  24.384 25.363 24.408 25.381 ;
     RECT  25.68 25.237 26.232 25.387 ;
     RECT  48.84 24.755 49.152 25.429 ;
     RECT  29.088 24.693 29.112 25.439 ;
     RECT  32.4 25.081 32.952 25.439 ;
     RECT  21.12 25.381 24.408 25.451 ;
     RECT  41.616 25.139 41.736 25.451 ;
     RECT  63.84 25.323 63.864 25.477 ;
     RECT  28.608 25.439 29.112 25.523 ;
     RECT  15.024 25.477 15.048 25.525 ;
     RECT  63.12 25.477 63.864 25.525 ;
     RECT  58.8 25.259 59.952 25.571 ;
     RECT  13.056 25.045 13.704 25.579 ;
     RECT  21.12 25.451 24.36 25.579 ;
     RECT  62.16 25.525 63.864 25.579 ;
     RECT  13.536 25.579 13.704 25.583 ;
     RECT  14.928 25.525 15.048 25.583 ;
     RECT  62.16 25.579 62.184 25.609 ;
     RECT  4.128 25.067 6.744 25.631 ;
     RECT  27.24 25.067 27.552 25.631 ;
     RECT  0.048 24.649 2.376 25.653 ;
     RECT  16.44 24.131 17.496 25.669 ;
     RECT  21.12 25.579 23.976 25.683 ;
     RECT  29.088 25.523 29.112 25.707 ;
     RECT  4.032 25.631 6.744 25.715 ;
     RECT  27.24 25.631 27.912 25.715 ;
     RECT  13.536 25.583 15.048 25.717 ;
     RECT  30.144 25.653 30.168 25.811 ;
     RECT  8.592 25.429 8.616 25.845 ;
     RECT  9.648 25.621 9.672 25.845 ;
     RECT  53.04 25.775 53.064 25.859 ;
     RECT  50.832 25.631 50.856 25.861 ;
     RECT  56.16 25.781 56.184 25.869 ;
     RECT  8.592 25.845 9.672 25.899 ;
     RECT  26.016 25.387 26.232 25.907 ;
     RECT  11.04 24.747 11.352 25.909 ;
     RECT  0.048 25.653 3 25.955 ;
     RECT  20.544 25.683 23.976 25.955 ;
     RECT  13.536 25.717 15.432 25.957 ;
     RECT  16.44 25.669 17.592 25.957 ;
     RECT  8.592 25.899 9.192 25.973 ;
     RECT  47.328 26.015 47.352 26.053 ;
     RECT  48.576 25.429 49.152 26.053 ;
     RECT  13.536 25.957 17.592 26.091 ;
     RECT  26.112 25.907 26.232 26.091 ;
     RECT  41.712 25.451 41.736 26.091 ;
     RECT  47.328 26.053 49.152 26.099 ;
     RECT  70.176 25.331 70.752 26.099 ;
     RECT  32.4 25.439 33.144 26.149 ;
     RECT  50.592 25.861 50.856 26.149 ;
     RECT  47.904 26.099 49.152 26.195 ;
     RECT  16.44 26.091 17.592 26.197 ;
     RECT  18.576 25.621 18.888 26.197 ;
     RECT  59.28 25.571 59.952 26.197 ;
     RECT  32.4 26.149 33.672 26.207 ;
     RECT  0.144 25.955 3 26.219 ;
     RECT  27.24 25.715 27.672 26.219 ;
     RECT  20.544 25.955 23.688 26.229 ;
     RECT  32.352 26.207 33.672 26.233 ;
     RECT  4.08 25.715 6.12 26.291 ;
     RECT  10.848 25.909 11.352 26.293 ;
     RECT  12.528 25.765 12.552 26.293 ;
     RECT  10.848 26.293 12.552 26.341 ;
     RECT  16.44 26.197 18.888 26.357 ;
     RECT  54.096 25.195 54.552 26.357 ;
     RECT  35.904 26.399 35.928 26.421 ;
     RECT  32.352 26.233 33.432 26.435 ;
     RECT  32.544 26.435 33.432 26.475 ;
     RECT  35.904 26.421 36.744 26.483 ;
     RECT  36.72 26.483 36.744 26.531 ;
     RECT  16.44 26.357 18.936 26.533 ;
     RECT  20.064 26.229 23.688 26.533 ;
     RECT  13.536 26.091 15.432 26.539 ;
     RECT  53.712 26.357 54.552 26.539 ;
     RECT  27.24 26.219 27.552 26.549 ;
     RECT  50.592 26.149 51.336 26.549 ;
     RECT  59.28 26.197 60.072 26.579 ;
     RECT  65.04 25.323 65.352 26.591 ;
     RECT  8.544 25.973 9.192 26.603 ;
     RECT  8.544 26.603 8.568 26.617 ;
     RECT  16.44 26.533 23.688 26.617 ;
     RECT  50.592 26.549 51.96 26.617 ;
     RECT  65.04 26.591 66.168 26.725 ;
     RECT  51.168 26.617 51.96 26.731 ;
     RECT  4.176 26.291 6.12 26.795 ;
     RECT  10.32 26.341 12.552 26.795 ;
     RECT  16.44 26.617 18.264 26.795 ;
     RECT  19.44 26.617 23.688 26.795 ;
     RECT  26.784 26.549 27.552 26.795 ;
     RECT  32.64 26.475 33.432 26.795 ;
     RECT  61.584 26.707 61.608 26.795 ;
     RECT  12.528 26.795 12.552 26.805 ;
     RECT  13.536 26.539 15.144 26.805 ;
     RECT  12.528 26.805 15.144 26.819 ;
     RECT  19.92 26.795 23.688 26.819 ;
     RECT  45.6 26.783 45.624 26.867 ;
     RECT  5.088 26.795 6.12 26.893 ;
     RECT  13.056 26.819 15.144 26.893 ;
     RECT  21.12 26.819 23.688 26.893 ;
     RECT  55.824 26.805 55.848 26.893 ;
     RECT  51.312 26.731 51.96 26.915 ;
     RECT  42.144 26.869 42.168 26.963 ;
     RECT  29.328 26.869 29.352 27.011 ;
     RECT  64.944 26.725 66.168 27.027 ;
     RECT  52.464 26.975 52.488 27.059 ;
     RECT  43.44 23.747 43.752 27.061 ;
     RECT  70.272 26.099 70.752 27.061 ;
     RECT  5.184 26.893 6.12 27.107 ;
     RECT  64.944 27.027 66.264 27.115 ;
     RECT  69.552 27.061 70.752 27.155 ;
     RECT  51.312 26.915 51.336 27.203 ;
     RECT  43.152 27.061 43.752 27.205 ;
     RECT  57.024 27.167 57.048 27.251 ;
     RECT  63.552 26.805 63.576 27.253 ;
     RECT  38.04 24.619 38.352 27.283 ;
     RECT  38.04 27.283 39 27.301 ;
     RECT  40.416 27.061 40.536 27.301 ;
     RECT  59.424 26.579 60.072 27.301 ;
     RECT  38.04 27.301 41.496 27.307 ;
     RECT  43.056 27.205 43.752 27.307 ;
     RECT  38.04 27.307 40.104 27.317 ;
     RECT  70.272 27.155 70.752 27.347 ;
     RECT  72.096 25.331 72.312 27.347 ;
     RECT  0.144 26.219 2.904 27.371 ;
     RECT  37.92 27.317 40.104 27.371 ;
     RECT  41.472 27.307 41.496 27.385 ;
     RECT  59.424 27.301 60.456 27.385 ;
     RECT  0.144 27.371 2.568 27.475 ;
     RECT  39.888 27.371 40.104 27.499 ;
     RECT  45.84 27.411 45.864 27.499 ;
     RECT  16.44 26.795 16.872 27.509 ;
     RECT  48.84 26.195 49.152 27.509 ;
     RECT  26.16 27.445 26.184 27.539 ;
     RECT  30.864 26.293 30.888 27.573 ;
     RECT  34.848 27.301 34.872 27.573 ;
     RECT  23.184 26.893 23.688 27.589 ;
     RECT  30.864 27.573 30.984 27.589 ;
     RECT  32.64 26.795 33.144 27.627 ;
     RECT  19.92 26.819 19.944 27.635 ;
     RECT  16.32 27.509 16.872 27.661 ;
     RECT  30.72 27.589 30.984 27.661 ;
     RECT  23.184 27.589 23.976 27.683 ;
     RECT  34.8 27.573 35.4 27.683 ;
     RECT  63.264 27.253 63.576 27.685 ;
     RECT  10.704 26.795 11.448 27.691 ;
     RECT  13.104 26.893 15.144 27.691 ;
     RECT  21.12 26.893 22.152 27.691 ;
     RECT  23.952 27.683 23.976 27.691 ;
     RECT  29.088 27.205 29.16 27.691 ;
     RECT  35.376 27.683 35.4 27.701 ;
     RECT  61.968 27.301 61.992 27.701 ;
     RECT  30.72 27.661 30.888 27.755 ;
     RECT  35.376 27.701 35.496 27.755 ;
     RECT  63.264 27.685 63.864 27.769 ;
     RECT  61.968 27.701 62.088 27.789 ;
     RECT  13.104 27.691 14.952 27.819 ;
     RECT  61.968 27.789 61.992 27.819 ;
     RECT  27.24 26.795 27.552 27.829 ;
     RECT  32.64 27.627 33.096 27.829 ;
     RECT  37.92 27.371 38.808 27.829 ;
     RECT  13.104 27.819 14.664 27.883 ;
     RECT  16.32 27.661 16.752 27.883 ;
     RECT  25.056 27.589 25.08 27.883 ;
     RECT  29.136 27.691 29.16 27.883 ;
     RECT  35.472 27.755 35.496 27.883 ;
     RECT  63.12 27.795 63.144 27.883 ;
     RECT  14.64 27.883 14.664 27.913 ;
     RECT  26.928 27.829 27.552 27.913 ;
     RECT  40.08 27.499 40.104 27.913 ;
     RECT  32.256 27.829 33.096 27.923 ;
     RECT  10.704 27.691 11.352 27.971 ;
     RECT  37.296 27.829 38.808 27.971 ;
     RECT  48.84 27.509 49.608 27.971 ;
     RECT  0.048 27.475 2.568 28.019 ;
     RECT  32.4 27.923 33.096 28.019 ;
     RECT  0.048 28.019 2.28 28.067 ;
     RECT  5.424 27.107 6.12 28.069 ;
     RECT  0.144 28.067 2.28 28.115 ;
     RECT  5.424 28.069 6.792 28.117 ;
     RECT  21.648 27.691 22.152 28.357 ;
     RECT  4.032 27.973 4.056 28.405 ;
     RECT  5.424 28.117 7.464 28.405 ;
     RECT  54.24 26.539 54.552 28.405 ;
     RECT  59.424 27.385 60.072 28.405 ;
     RECT  64.944 27.115 65.352 28.405 ;
     RECT  27.12 27.913 27.552 28.451 ;
     RECT  18.192 26.795 18.216 28.453 ;
     RECT  46.752 27.701 46.776 28.453 ;
     RECT  4.032 28.405 7.464 28.459 ;
     RECT  9.552 28.309 9.576 28.459 ;
     RECT  7.392 28.459 7.464 28.489 ;
     RECT  64.416 28.405 65.352 28.489 ;
     RECT  0.144 28.115 1.752 28.499 ;
     RECT  21.648 28.357 22.824 28.499 ;
     RECT  38.04 27.971 38.808 28.499 ;
     RECT  4.176 28.459 5.952 28.547 ;
     RECT  18.192 28.453 18.984 28.547 ;
     RECT  21.648 28.499 22.152 28.547 ;
     RECT  59.424 28.405 60.168 28.547 ;
     RECT  46.752 28.453 47.304 28.645 ;
     RECT  7.44 28.489 7.464 28.981 ;
     RECT  10.944 27.971 11.352 28.981 ;
     RECT  23.712 28.933 23.736 28.981 ;
     RECT  25.104 28.933 25.128 28.981 ;
     RECT  59.424 28.547 59.952 28.981 ;
     RECT  7.44 28.981 7.8 29.027 ;
     RECT  32.4 28.019 32.952 29.029 ;
     RECT  23.712 28.981 25.128 29.035 ;
     RECT  0.144 28.499 1.416 29.045 ;
     RECT  7.776 29.027 7.8 29.065 ;
     RECT  23.808 29.035 25.08 29.065 ;
     RECT  59.28 28.981 59.952 29.065 ;
     RECT  61.008 28.981 61.032 29.065 ;
     RECT  2.88 28.981 2.904 29.087 ;
     RECT  24.96 29.065 25.08 29.099 ;
     RECT  29.184 28.837 29.208 29.099 ;
     RECT  54.24 28.405 55.272 29.099 ;
     RECT  2.832 29.087 2.904 29.109 ;
     RECT  46.608 28.645 47.304 29.109 ;
     RECT  30.912 29.029 32.952 29.113 ;
     RECT  23.808 29.065 23.832 29.123 ;
     RECT  41.904 29.039 41.928 29.173 ;
     RECT  43.44 27.307 43.752 29.173 ;
     RECT  46.608 29.109 47.64 29.219 ;
     RECT  41.904 29.173 43.752 29.221 ;
     RECT  41.616 29.221 43.752 29.305 ;
     RECT  57.6 29.279 57.624 29.363 ;
     RECT  42 29.305 43.752 29.365 ;
     RECT  72.096 27.347 72.12 29.365 ;
     RECT  42 29.365 44.472 29.449 ;
     RECT  71.808 29.365 72.12 29.459 ;
     RECT  70.44 27.347 70.752 29.461 ;
     RECT  0.048 29.045 1.416 29.493 ;
     RECT  2.832 29.109 2.952 29.493 ;
     RECT  7.968 29.423 7.992 29.507 ;
     RECT  63.264 29.423 63.288 29.507 ;
     RECT  4.272 28.547 5.952 29.509 ;
     RECT  10.944 28.981 12.072 29.509 ;
     RECT  13.056 28.405 13.08 29.509 ;
     RECT  69.552 29.461 70.752 29.547 ;
     RECT  15.12 29.461 15.144 29.557 ;
     RECT  27.24 28.451 27.552 29.557 ;
     RECT  70.44 29.547 70.752 29.557 ;
     RECT  3.984 29.509 5.952 29.611 ;
     RECT  14.16 29.557 15.144 29.611 ;
     RECT  36.48 28.405 36.504 29.611 ;
     RECT  46.608 29.219 47.352 29.611 ;
     RECT  21.84 28.547 22.152 29.621 ;
     RECT  47.28 29.611 47.352 29.641 ;
     RECT  70.44 29.557 70.872 29.641 ;
     RECT  4.464 29.611 5.952 29.685 ;
     RECT  42 29.449 43.848 29.699 ;
     RECT  18.96 28.547 18.984 29.739 ;
     RECT  63.936 29.749 63.96 29.797 ;
     RECT  65.04 28.489 65.352 29.797 ;
     RECT  10.944 29.509 13.08 29.803 ;
     RECT  47.28 29.641 47.304 29.803 ;
     RECT  62.496 29.605 62.52 29.803 ;
     RECT  48.84 27.971 49.152 29.807 ;
     RECT  59.64 29.065 59.952 29.855 ;
     RECT  16.44 27.883 16.752 29.877 ;
     RECT  20.208 29.221 20.232 29.877 ;
     RECT  63.936 29.797 65.352 29.881 ;
     RECT  48.48 29.807 49.152 29.891 ;
     RECT  59.64 29.855 60.456 29.939 ;
     RECT  16.32 29.877 16.752 29.965 ;
     RECT  51.504 29.907 51.528 29.995 ;
     RECT  63.936 29.881 63.96 29.995 ;
     RECT  43.344 29.699 43.848 30.073 ;
     RECT  11.04 29.803 13.08 30.131 ;
     RECT  20.208 29.877 20.568 30.131 ;
     RECT  42 29.699 42.12 30.131 ;
     RECT  21.84 29.621 22.248 30.133 ;
     RECT  12.528 30.131 13.08 30.157 ;
     RECT  4.464 29.685 6.072 30.187 ;
     RECT  42.096 30.131 42.12 30.187 ;
     RECT  5.136 30.187 6.072 30.191 ;
     RECT  27.24 29.557 28.536 30.217 ;
     RECT  27.24 30.217 27.552 30.239 ;
     RECT  5.136 30.191 6.648 30.261 ;
     RECT  9.648 30.191 9.672 30.275 ;
     RECT  19.632 30.239 19.656 30.323 ;
     RECT  26.112 30.239 27.552 30.323 ;
     RECT  46.176 30.239 46.2 30.323 ;
     RECT  0.048 29.493 2.952 30.325 ;
     RECT  16.44 29.965 16.752 30.325 ;
     RECT  18.192 30.191 18.264 30.325 ;
     RECT  25.056 29.099 25.08 30.325 ;
     RECT  32.64 29.113 32.952 30.389 ;
     RECT  34.32 30.181 34.344 30.389 ;
     RECT  38.04 28.499 38.352 30.389 ;
     RECT  45.504 30.325 45.528 30.443 ;
     RECT  5.136 30.261 6.792 30.453 ;
     RECT  0.048 30.325 3.096 30.507 ;
     RECT  25.056 30.325 25.176 30.517 ;
     RECT  36.336 30.389 36.456 30.565 ;
     RECT  25.008 30.517 25.176 30.571 ;
     RECT  14.16 29.611 14.952 30.575 ;
     RECT  5.136 30.453 6.888 30.581 ;
     RECT  21.072 30.133 22.248 30.581 ;
     RECT  30.24 30.389 30.36 30.581 ;
     RECT  35.568 30.565 36.456 30.581 ;
     RECT  69.168 30.581 69.192 30.623 ;
     RECT  70.44 29.641 70.752 30.623 ;
     RECT  0.048 30.507 3.048 30.635 ;
     RECT  5.136 30.581 6.984 30.635 ;
     RECT  32.64 30.389 34.344 30.635 ;
     RECT  48.72 29.891 49.152 30.635 ;
     RECT  38.04 30.389 38.472 30.645 ;
     RECT  35.568 30.581 36.504 30.649 ;
     RECT  62.16 30.565 62.184 30.649 ;
     RECT  25.008 30.571 25.128 30.659 ;
     RECT  69.168 30.623 70.752 30.669 ;
     RECT  29.088 30.613 29.112 30.675 ;
     RECT  30.24 30.581 30.888 30.675 ;
     RECT  36.48 30.649 36.504 30.675 ;
     RECT  70.128 30.669 70.752 30.707 ;
     RECT  0.096 30.635 2.952 30.763 ;
     RECT  6.96 30.635 6.984 30.763 ;
     RECT  29.088 30.675 30.888 30.763 ;
     RECT  34.224 30.635 34.344 30.763 ;
     RECT  36.48 30.675 36.552 30.763 ;
     RECT  43.44 30.073 43.848 30.805 ;
     RECT  13.584 30.575 14.952 30.851 ;
     RECT  36.48 30.763 36.504 30.851 ;
     RECT  38.04 30.645 39.336 30.851 ;
     RECT  13.584 30.851 13.608 30.861 ;
     RECT  16.44 30.325 18.264 30.891 ;
     RECT  43.44 30.805 44.472 30.891 ;
     RECT  67.728 30.837 67.752 30.925 ;
     RECT  72.096 29.459 72.12 30.947 ;
     RECT  8.016 30.565 8.04 30.965 ;
     RECT  24 30.133 24.024 30.965 ;
     RECT  51.312 30.901 51.336 30.995 ;
     RECT  11.04 30.131 11.352 31.029 ;
     RECT  16.44 30.891 17.688 31.083 ;
     RECT  68.4 30.997 68.424 31.083 ;
     RECT  18.672 31.007 18.696 31.091 ;
     RECT  8.016 30.965 8.136 31.139 ;
     RECT  56.448 31.093 56.472 31.177 ;
     RECT  21.072 30.581 22.824 31.189 ;
     RECT  5.136 30.635 5.952 31.211 ;
     RECT  52.464 31.151 52.488 31.235 ;
     RECT  19.968 31.189 22.824 31.275 ;
     RECT  19.968 31.275 19.992 31.283 ;
     RECT  65.04 29.881 65.352 31.333 ;
     RECT  61.584 30.709 61.608 31.339 ;
     RECT  14.688 30.851 14.952 31.343 ;
     RECT  10.944 31.029 11.352 31.349 ;
     RECT  21.12 31.275 22.824 31.413 ;
     RECT  23.952 30.965 24.024 31.413 ;
     RECT  14.688 31.343 15.384 31.427 ;
     RECT  21.12 31.413 24.024 31.427 ;
     RECT  29.52 30.763 30.264 31.427 ;
     RECT  16.44 31.083 16.752 31.464 ;
     RECT  42.192 31.381 42.216 31.467 ;
     RECT  10.944 31.349 11.448 31.477 ;
     RECT  12.528 30.157 12.552 31.477 ;
     RECT  27.24 30.323 27.552 31.477 ;
     RECT  21.84 31.427 24.024 31.525 ;
     RECT  34.224 30.763 34.248 31.531 ;
     RECT  10.944 31.477 12.552 31.541 ;
     RECT  26.784 31.477 27.552 31.605 ;
     RECT  10.848 31.541 12.552 31.609 ;
     RECT  16.128 31.464 16.752 31.659 ;
     RECT  18.816 31.413 18.936 31.659 ;
     RECT  10.848 31.609 12.216 31.669 ;
     RECT  26.16 31.605 27.552 31.715 ;
     RECT  10.704 31.669 12.216 31.723 ;
     RECT  25.056 30.659 25.128 31.733 ;
     RECT  26.16 31.715 26.184 31.733 ;
     RECT  31.296 31.669 31.32 31.753 ;
     RECT  7.44 31.669 7.992 31.763 ;
     RECT  25.056 31.733 26.184 31.787 ;
     RECT  10.704 31.723 11.544 31.797 ;
     RECT  62.736 31.717 62.76 31.801 ;
     RECT  54.24 29.099 54.552 31.827 ;
     RECT  21.84 31.525 24.072 31.861 ;
     RECT  25.056 31.787 26.088 31.861 ;
     RECT  10.56 31.797 11.544 31.907 ;
     RECT  21.84 31.861 26.088 31.915 ;
     RECT  54.24 31.827 54.792 31.915 ;
     RECT  56.256 31.381 56.28 31.915 ;
     RECT  65.04 31.333 65.448 31.915 ;
     RECT  21.84 31.915 25.656 31.945 ;
     RECT  48.84 30.635 49.152 31.957 ;
     RECT  50.4 31.861 50.424 31.957 ;
     RECT  48.84 31.957 50.424 32.043 ;
     RECT  0.096 30.763 2.76 32.053 ;
     RECT  9.12 32.053 9.144 32.117 ;
     RECT  25.104 31.945 25.656 32.147 ;
     RECT  23.952 31.945 24.072 32.171 ;
     RECT  25.104 32.147 25.128 32.235 ;
     RECT  7.44 31.763 7.464 32.243 ;
     RECT  13.68 31.925 13.704 32.291 ;
     RECT  0.096 32.053 2.856 32.309 ;
     RECT  9.12 32.117 9.72 32.351 ;
     RECT  23.952 32.171 23.976 32.363 ;
     RECT  50.4 32.043 50.424 32.427 ;
     RECT  8.496 32.351 9.72 32.435 ;
     RECT  29.472 31.967 29.496 32.437 ;
     RECT  8.832 32.435 9.72 32.491 ;
     RECT  31.44 32.403 31.464 32.491 ;
     RECT  14.688 31.427 14.712 32.495 ;
     RECT  59.64 29.939 59.952 32.495 ;
     RECT  5.232 31.211 5.952 32.565 ;
     RECT  11.04 31.907 11.544 32.579 ;
     RECT  13.92 32.495 15 32.579 ;
     RECT  63.696 32.495 63.72 32.579 ;
     RECT  51.888 32.543 51.912 32.627 ;
     RECT  20.592 32.437 20.616 32.629 ;
     RECT  0.048 32.309 2.856 32.693 ;
     RECT  54.24 31.915 54.552 32.725 ;
     RECT  3.984 32.565 4.008 32.787 ;
     RECT  3.984 32.787 4.104 32.819 ;
     RECT  8.832 32.491 9.144 32.819 ;
     RECT  4.08 32.819 4.104 32.821 ;
     RECT  5.136 32.565 5.952 32.821 ;
     RECT  0.048 32.693 2.952 32.875 ;
     RECT  4.08 32.821 5.952 32.875 ;
     RECT  8.832 32.819 8.952 32.875 ;
     RECT  27.24 31.715 27.552 32.879 ;
     RECT  63.84 32.821 63.864 32.905 ;
     RECT  29.424 32.437 29.496 32.927 ;
     RECT  58.848 32.495 59.952 32.927 ;
     RECT  26.688 32.879 27.552 32.949 ;
     RECT  29.088 32.927 29.496 32.949 ;
     RECT  14.16 32.579 14.952 32.963 ;
     RECT  38.04 30.851 38.352 32.979 ;
     RECT  53.568 32.725 54.552 32.979 ;
     RECT  21.84 31.945 22.824 33.003 ;
     RECT  46.752 32.693 46.776 33.003 ;
     RECT  50.736 32.693 51.336 33.003 ;
     RECT  29.088 32.949 29.544 33.011 ;
     RECT  58.704 32.927 59.952 33.011 ;
     RECT  21.84 33.003 22.152 33.013 ;
     RECT  51.168 33.003 51.336 33.014 ;
     RECT  26.592 32.949 27.552 33.037 ;
     RECT  29.52 33.011 29.544 33.037 ;
     RECT  4.56 32.875 5.952 33.067 ;
     RECT  14.928 32.963 14.952 33.067 ;
     RECT  37.68 32.979 38.352 33.067 ;
     RECT  53.52 32.979 54.552 33.067 ;
     RECT  32.64 30.635 32.952 33.071 ;
     RECT  48.84 32.043 49.152 33.071 ;
     RECT  7.2 32.917 7.224 33.077 ;
     RECT  11.04 32.579 11.448 33.077 ;
     RECT  12.528 33.013 12.552 33.077 ;
     RECT  12.528 33.077 12.6 33.097 ;
     RECT  32.64 33.071 33.192 33.155 ;
     RECT  48.84 33.071 49.608 33.155 ;
     RECT  19.92 32.629 20.616 33.195 ;
     RECT  34.8 33.119 34.824 33.203 ;
     RECT  18.816 31.659 18.84 33.205 ;
     RECT  21.744 33.013 22.152 33.205 ;
     RECT  68.064 33.077 68.088 33.205 ;
     RECT  68.064 33.205 69 33.251 ;
     RECT  6.96 33.077 7.224 33.259 ;
     RECT  12.576 33.097 12.6 33.259 ;
     RECT  16.44 31.659 16.752 33.269 ;
     RECT  18.528 33.205 18.84 33.269 ;
     RECT  65.04 31.915 65.352 33.269 ;
     RECT  68.976 33.251 69 33.289 ;
     RECT  20.688 33.205 22.152 33.337 ;
     RECT  18.528 33.269 19.56 33.347 ;
     RECT  20.784 33.337 22.152 33.347 ;
     RECT  24.624 33.141 24.648 33.347 ;
     RECT  20.784 33.347 20.808 33.395 ;
     RECT  39.456 33.269 39.48 33.395 ;
     RECT  65.04 33.269 65.448 33.539 ;
     RECT  16.44 33.269 16.872 33.635 ;
     RECT  19.536 33.347 19.56 33.731 ;
     RECT  8.832 32.875 8.856 33.779 ;
     RECT  10.944 33.077 11.448 33.781 ;
     RECT  4.848 33.067 5.952 33.835 ;
     RECT  10.8 33.781 11.496 33.839 ;
     RECT  7.104 33.259 7.224 33.877 ;
     RECT  51.168 33.014 51.288 33.913 ;
     RECT  51.264 33.913 51.288 33.923 ;
     RECT  10.704 33.839 11.496 33.925 ;
     RECT  21.84 33.347 22.152 33.973 ;
     RECT  0.048 32.875 2.76 34.021 ;
     RECT  70.44 30.707 70.752 34.357 ;
     RECT  70.128 34.357 70.752 34.451 ;
     RECT  27.24 33.037 27.552 34.485 ;
     RECT  16.44 33.635 16.752 34.501 ;
     RECT  29.952 34.485 29.976 34.501 ;
     RECT  16.176 34.501 16.752 34.597 ;
     RECT  32.64 33.155 32.952 34.645 ;
     RECT  59.64 33.011 59.952 34.645 ;
     RECT  61.008 34.597 61.032 34.645 ;
     RECT  15.36 34.597 16.752 34.655 ;
     RECT  5.088 33.835 5.952 34.667 ;
     RECT  9.888 33.925 11.496 34.667 ;
     RECT  26.88 34.485 27.552 34.667 ;
     RECT  28.896 34.501 29.976 34.667 ;
     RECT  14.88 34.655 16.752 34.677 ;
     RECT  5.328 34.667 5.952 34.681 ;
     RECT  59.64 34.645 61.032 34.681 ;
     RECT  13.104 34.453 13.128 34.707 ;
     RECT  20.544 34.453 20.568 34.731 ;
     RECT  59.64 34.681 60.072 34.731 ;
     RECT  14.88 34.677 17.112 34.739 ;
     RECT  0.048 34.021 3.096 34.741 ;
     RECT  5.64 34.681 5.952 34.741 ;
     RECT  7.104 33.877 7.464 34.741 ;
     RECT  14.928 34.739 17.112 34.789 ;
     RECT  18.432 34.165 18.456 34.789 ;
     RECT  9.888 34.667 11.352 34.795 ;
     RECT  13.104 34.707 13.752 34.795 ;
     RECT  14.928 34.789 18.456 34.799 ;
     RECT  21.84 33.973 22.92 34.799 ;
     RECT  13.728 34.795 13.752 34.806 ;
     RECT  5.64 34.741 7.464 34.869 ;
     RECT  14.928 34.799 18.744 34.869 ;
     RECT  4.272 34.799 4.296 34.883 ;
     RECT  0.048 34.741 3.192 34.885 ;
     RECT  56.448 34.847 56.472 34.931 ;
     RECT  32.64 34.645 33.096 34.933 ;
     RECT  0.048 34.885 3.24 34.987 ;
     RECT  14.928 34.869 19.032 34.987 ;
     RECT  18.672 34.987 19.032 34.997 ;
     RECT  32.64 34.933 33.672 35.017 ;
     RECT  14.928 34.987 17.4 35.027 ;
     RECT  5.64 34.869 8.136 35.039 ;
     RECT  0.048 34.987 3.192 35.115 ;
     RECT  5.64 35.039 8.52 35.115 ;
     RECT  7.68 35.115 8.52 35.123 ;
     RECT  18.672 34.997 19.08 35.125 ;
     RECT  62.736 35.125 62.76 35.209 ;
     RECT  5.64 35.115 6.312 35.219 ;
     RECT  16.032 35.027 17.4 35.219 ;
     RECT  21.648 34.799 22.92 35.257 ;
     RECT  0.048 35.115 3.096 35.307 ;
     RECT  18.672 35.125 19.128 35.307 ;
     RECT  43.44 30.891 43.752 35.317 ;
     RECT  43.344 35.317 43.752 35.41 ;
     RECT  21.648 35.257 22.152 35.411 ;
     RECT  9.888 34.795 9.912 35.435 ;
     RECT  7.68 35.123 7.704 35.449 ;
     RECT  46.752 35.365 46.776 35.449 ;
     RECT  43.296 35.41 43.752 35.507 ;
     RECT  65.04 33.539 65.352 35.605 ;
     RECT  11.04 34.795 11.352 35.701 ;
     RECT  54.24 33.067 54.552 35.701 ;
     RECT  54.24 35.701 55.32 35.785 ;
     RECT  19.968 35.749 19.992 35.833 ;
     RECT  9.696 35.573 9.816 35.893 ;
     RECT  11.04 35.701 11.448 35.893 ;
     RECT  27.24 34.667 27.552 35.893 ;
     RECT  16.44 35.219 17.4 35.917 ;
     RECT  5.64 35.219 5.952 35.941 ;
     RECT  9.024 35.893 9.816 35.977 ;
     RECT  27.072 35.893 27.552 35.987 ;
     RECT  46.848 35.893 46.872 35.987 ;
     RECT  67.824 35.845 67.848 36.075 ;
     RECT  5.088 35.941 5.952 36.085 ;
     RECT  4.608 36.085 5.952 36.109 ;
     RECT  10.848 35.893 11.448 36.139 ;
     RECT  4.608 36.109 4.632 36.179 ;
     RECT  5.64 36.109 5.952 36.191 ;
     RECT  5.64 36.191 6.312 36.277 ;
     RECT  9.792 35.977 9.816 36.371 ;
     RECT  32.64 35.017 32.952 36.421 ;
     RECT  5.64 36.277 6.408 36.469 ;
     RECT  48.84 33.155 49.152 36.469 ;
     RECT  14.928 35.027 14.952 36.515 ;
     RECT  30.72 36.085 30.744 36.523 ;
     RECT  21.84 35.411 22.152 36.527 ;
     RECT  48.84 36.469 49.368 36.563 ;
     RECT  7.872 36.527 7.896 36.611 ;
     RECT  21.84 36.527 22.92 36.611 ;
     RECT  0.048 35.307 3 36.707 ;
     RECT  4.512 36.719 4.536 36.803 ;
     RECT  0.144 36.707 3 36.853 ;
     RECT  0.144 36.853 3.432 36.947 ;
     RECT  0.144 36.947 2.904 36.995 ;
     RECT  30.24 36.911 30.264 36.995 ;
     RECT  21.84 36.611 22.152 36.997 ;
     RECT  65.04 35.605 65.64 36.997 ;
     RECT  32.64 36.421 33.528 37.035 ;
     RECT  34.08 37.045 34.104 37.139 ;
     RECT  5.64 36.469 6.504 37.151 ;
     RECT  16.44 35.917 17.256 37.173 ;
     RECT  5.64 37.151 6.744 37.235 ;
     RECT  16.32 37.173 17.256 37.261 ;
     RECT  21.648 36.997 22.152 37.291 ;
     RECT  16.44 37.261 17.256 37.419 ;
     RECT  65.04 36.997 66.168 37.611 ;
     RECT  34.704 37.535 34.728 37.619 ;
     RECT  38.04 33.067 38.352 37.621 ;
     RECT  37.632 37.621 38.352 37.715 ;
     RECT  39.792 37.621 39.816 37.715 ;
     RECT  38.04 37.715 38.352 37.727 ;
     RECT  38.04 37.727 38.472 37.811 ;
     RECT  0.144 36.995 0.936 37.813 ;
     RECT  62.688 37.813 62.712 37.897 ;
     RECT  5.64 37.235 6.072 37.945 ;
     RECT  12.48 37.861 12.504 37.945 ;
     RECT  19.392 37.919 19.416 38.003 ;
     RECT  2.016 36.995 2.904 38.099 ;
     RECT  0.048 37.813 0.936 38.123 ;
     RECT  0.144 38.123 0.936 38.197 ;
     RECT  0.144 38.197 1.992 38.291 ;
     RECT  4.512 38.303 4.536 38.387 ;
     RECT  26.208 37.429 26.232 38.473 ;
     RECT  3.408 38.629 3.432 38.713 ;
     RECT  27.24 35.987 27.552 39.205 ;
     RECT  2.256 39.157 2.28 39.251 ;
     RECT  27.24 39.205 27.96 39.289 ;
     RECT  1.872 39.541 1.896 39.787 ;
     RECT  5.64 37.945 5.952 39.983 ;
     RECT  11.04 36.139 11.352 39.983 ;
     RECT  16.44 37.419 16.752 39.983 ;
     RECT  21.84 37.291 22.152 39.983 ;
     RECT  27.24 39.289 27.552 39.983 ;
     RECT  32.64 37.035 32.952 39.983 ;
     RECT  38.04 37.811 38.352 39.983 ;
     RECT  43.44 35.507 43.752 39.983 ;
     RECT  48.84 36.563 49.152 39.983 ;
     RECT  54.24 35.785 54.552 39.983 ;
     RECT  59.64 34.731 59.952 39.983 ;
     RECT  65.04 37.611 65.352 39.983 ;
     RECT  70.44 34.451 70.752 39.983 ;
     RECT  0.144 38.291 0.84 40.019 ;
     RECT  0.432 40.019 0.84 40.163 ;
     RECT  0.432 40.163 0.552 40.253 ;
     RECT  5.832 39.983 5.952 40.253 ;
     RECT  11.232 39.983 11.352 40.253 ;
     RECT  16.632 39.983 16.752 40.253 ;
     RECT  22.032 39.983 22.152 40.253 ;
     RECT  27.432 39.983 27.552 40.253 ;
     RECT  32.832 39.983 32.952 40.253 ;
     RECT  38.232 39.983 38.352 40.253 ;
     RECT  43.632 39.983 43.752 40.253 ;
     RECT  49.032 39.983 49.152 40.253 ;
     RECT  54.432 39.983 54.552 40.253 ;
     RECT  59.832 39.983 59.952 40.253 ;
     RECT  65.232 39.983 65.352 40.253 ;
     RECT  70.632 39.983 70.752 40.253 ;
    LAYER M6 ;
     RECT  0 17.196 0.037 18.06 ;
     RECT  0 22.596 0.037 23.46 ;
     RECT  0 27.996 0.037 28.86 ;
     RECT  0 33.396 0.037 34.26 ;
     RECT  0 38.796 0.037 39.66 ;
     RECT  0.037 17.196 0.053 20.384 ;
     RECT  0.037 27.52 0.053 30.624 ;
     RECT  0.037 32.32 0.053 36.512 ;
     RECT  0.053 17.088 0.117 20.384 ;
     RECT  0.037 22.272 0.117 25.696 ;
     RECT  0.117 15.616 0.133 15.648 ;
     RECT  0.117 17.088 0.133 25.696 ;
     RECT  0.053 27.52 0.133 36.512 ;
     RECT  0.037 38.08 0.133 39.66 ;
     RECT  0 11.796 0.181 12.66 ;
     RECT  0 6.396 0.373 7.26 ;
     RECT  0.373 5.76 0.437 7.26 ;
     RECT  0.133 15.616 0.565 39.968 ;
     RECT  0.437 5.76 0.629 7.392 ;
     RECT  0.565 15.424 0.629 39.968 ;
     RECT  0.629 15.232 0.661 39.968 ;
     RECT  0.661 15.104 0.707 39.968 ;
     RECT  0.181 11.796 1.093 13.536 ;
     RECT  1.093 11.796 1.205 13.6 ;
     RECT  0.707 15.104 1.205 39.776 ;
     RECT  0.693 10.432 1.269 10.464 ;
     RECT  1.205 11.796 1.269 39.776 ;
     RECT  0.629 4.672 1.333 7.392 ;
     RECT  1.205 9.088 1.333 9.12 ;
     RECT  1.269 10.432 1.333 39.776 ;
     RECT  1.333 4.672 1.653 39.776 ;
     RECT  0 0.996 2.677 1.86 ;
     RECT  2.677 0.996 3.061 2.016 ;
     RECT  1.653 3.648 3.061 39.776 ;
     RECT  3.061 0.996 20.011 39.776 ;
     RECT  20.011 0.996 34.155 39.66 ;
     RECT  34.155 0.996 49.333 36.192 ;
     RECT  34.155 37.568 49.333 39.66 ;
     RECT  49.333 0.996 49.402 39.66 ;
     RECT  49.402 0.996 59.315 36.192 ;
     RECT  59.315 20.16 60.083 36.192 ;
     RECT  60.083 20.224 62.771 36.192 ;
     RECT  59.315 0.996 63.299 18.592 ;
     RECT  63.299 0.996 63.443 18.06 ;
     RECT  63.443 5.632 63.595 18.06 ;
     RECT  62.771 20.224 63.731 34.26 ;
     RECT  63.443 0.996 63.875 4.192 ;
     RECT  63.731 20.224 63.875 31.392 ;
     RECT  63.731 32.832 63.875 34.26 ;
     RECT  63.595 5.824 64.019 18.06 ;
     RECT  63.875 20.224 64.115 25.312 ;
     RECT  64.019 5.824 64.451 10.08 ;
     RECT  64.115 20.8 64.451 25.312 ;
     RECT  64.019 11.584 64.747 18.06 ;
     RECT  64.747 11.584 64.762 14.24 ;
     RECT  64.451 5.824 64.979 9.376 ;
     RECT  64.762 11.584 64.979 13.472 ;
     RECT  64.451 20.8 64.979 25.184 ;
     RECT  64.357 19.392 65.003 19.424 ;
     RECT  63.875 26.624 65.333 31.392 ;
     RECT  62.771 36.032 65.333 36.192 ;
     RECT  49.402 37.568 65.333 39.66 ;
     RECT  63.875 0.996 65.459 3.424 ;
     RECT  64.979 6.08 65.459 9.376 ;
     RECT  64.747 16.128 65.459 18.06 ;
     RECT  65.333 36.032 65.459 39.66 ;
     RECT  65.333 26.624 65.515 31.904 ;
     RECT  65.459 6.08 65.579 8.608 ;
     RECT  65.459 0.996 65.603 3.36 ;
     RECT  65.459 36.032 65.651 36.192 ;
     RECT  65.579 6.08 66.179 8.544 ;
     RECT  64.979 21.76 66.179 25.184 ;
     RECT  65.515 26.624 66.179 31.072 ;
     RECT  65.459 37.568 66.179 39.66 ;
     RECT  65.459 16.192 66.419 18.06 ;
     RECT  64.979 11.584 67.283 12.66 ;
     RECT  65.603 3.328 67.859 3.36 ;
     RECT  66.179 6.08 67.859 7.26 ;
     RECT  65.651 36.032 67.859 36.064 ;
     RECT  63.875 33.216 68.053 34.26 ;
     RECT  66.179 27.072 68.435 31.072 ;
     RECT  68.053 33.088 68.981 34.26 ;
     RECT  68.435 27.072 69.035 30.88 ;
     RECT  68.981 33.088 69.035 34.4 ;
     RECT  69.035 27.072 69.587 30.688 ;
     RECT  66.179 22.596 70.163 25.184 ;
     RECT  69.587 27.996 70.163 30.688 ;
     RECT  69.035 33.396 70.163 34.4 ;
     RECT  65.603 0.996 70.56 1.86 ;
     RECT  67.859 6.396 70.56 7.26 ;
     RECT  67.283 11.796 70.56 12.66 ;
     RECT  66.419 17.196 70.56 18.06 ;
     RECT  70.163 22.596 70.56 23.46 ;
     RECT  70.163 27.996 70.56 29.6 ;
     RECT  70.163 33.396 70.56 34.26 ;
     RECT  66.179 38.796 70.56 39.66 ;
     RECT  70.56 1.408 70.883 1.86 ;
     RECT  70.56 28.572 70.883 29.6 ;
     RECT  70.883 1.572 71.344 1.86 ;
     RECT  70.56 6.972 71.344 7.26 ;
     RECT  70.56 12.372 71.344 12.66 ;
     RECT  70.56 17.772 71.344 18.06 ;
     RECT  70.56 23.172 71.344 23.46 ;
     RECT  70.883 28.572 71.344 29.408 ;
     RECT  70.56 33.972 71.344 34.26 ;
     RECT  70.56 39.372 71.344 39.66 ;
     RECT  71.344 29.376 71.843 29.408 ;
     RECT  70.163 24.768 72.419 25.184 ;
     RECT  71.344 12.372 72.421 12.64 ;
     RECT  72.421 11.136 72.467 12.64 ;
     RECT  72.467 11.136 72.469 11.872 ;
     RECT  72.325 15.04 72.517 15.072 ;
     RECT  72.419 24.768 72.517 24.992 ;
     RECT  72.469 6.592 72.659 6.624 ;
     RECT  72.517 15.04 72.659 15.328 ;
     RECT  72.517 24.512 72.659 24.992 ;
     RECT  72.469 10.752 72.707 11.872 ;
     RECT  71.749 20.992 72.707 21.024 ;
     RECT  72.659 24.96 72.707 24.992 ;
     RECT  72.707 10.752 72.803 11.168 ;
     RECT  72.659 15.296 72.803 15.328 ;
     RECT  72.325 19.328 72.803 19.36 ;
     RECT  72.661 2.88 72.851 2.912 ;
     RECT  72.803 10.752 72.851 10.784 ;
    LAYER M7 ;
     RECT  0.856 0.531 1.144 1.397 ;
     RECT  17.056 0.531 17.344 2.549 ;
     RECT  17.056 2.549 18.016 2.677 ;
     RECT  0.856 1.397 3.168 2.805 ;
     RECT  0.856 2.805 3.424 3.061 ;
     RECT  11.656 0.531 11.944 3.253 ;
     RECT  22.456 0.531 22.744 3.381 ;
     RECT  16.448 2.677 18.016 3.701 ;
     RECT  63.424 3.317 63.456 4.075 ;
     RECT  52.992 1.397 53.024 4.139 ;
     RECT  15.168 3.701 18.016 4.149 ;
     RECT  0.856 3.061 3.552 4.213 ;
     RECT  41.6 3.317 41.632 4.277 ;
     RECT  15.04 4.149 18.016 4.587 ;
     RECT  0.856 4.213 4 4.661 ;
     RECT  44.056 0.531 44.344 4.661 ;
     RECT  0.64 4.661 4 5.163 ;
     RECT  41.344 4.277 41.632 5.291 ;
     RECT  41.344 5.291 41.376 5.419 ;
     RECT  22.144 3.381 22.744 5.557 ;
     RECT  6.256 0.531 6.544 5.621 ;
     RECT  44.056 4.661 45.024 5.739 ;
     RECT  0.64 5.163 3.552 5.749 ;
     RECT  47.232 3.765 47.264 5.813 ;
     RECT  49.456 0.531 49.744 5.813 ;
     RECT  11.656 3.253 12.64 5.941 ;
     RECT  17.056 4.587 18.016 6.059 ;
     RECT  51.968 6.005 52 6.133 ;
     RECT  6.256 5.621 7.136 6.197 ;
     RECT  8.448 4.981 8.48 6.197 ;
     RECT  38.656 0.531 38.944 6.197 ;
     RECT  47.232 5.813 49.744 6.261 ;
     RECT  46.976 6.261 49.744 6.773 ;
     RECT  65.656 0.531 65.944 6.837 ;
     RECT  11.328 5.941 12.64 6.891 ;
     RECT  0.384 5.749 3.552 7.349 ;
     RECT  51.968 6.133 52.768 7.349 ;
     RECT  38.208 6.197 39.392 7.413 ;
     RECT  20.224 3.317 20.256 7.541 ;
     RECT  21.76 5.557 22.744 7.541 ;
     RECT  20.224 7.541 22.744 7.733 ;
     RECT  0.384 7.349 4 7.797 ;
     RECT  42.688 7.413 42.72 7.797 ;
     RECT  37.376 7.413 40.544 7.851 ;
     RECT  51.968 7.349 53.472 8.053 ;
     RECT  54.856 0.531 55.144 8.053 ;
     RECT  27.856 0.531 28.144 8.245 ;
     RECT  37.376 7.851 38.944 8.299 ;
     RECT  0.384 7.797 4.384 8.309 ;
     RECT  15.04 4.587 15.2 8.437 ;
     RECT  17.056 6.059 17.344 8.437 ;
     RECT  11.52 6.891 12.64 8.501 ;
     RECT  15.04 8.437 17.344 8.501 ;
     RECT  65.536 6.837 65.944 8.619 ;
     RECT  42.496 7.797 42.72 8.811 ;
     RECT  20.224 7.733 23.136 8.821 ;
     RECT  24.448 7.925 24.48 8.821 ;
     RECT  6.256 6.197 8.48 8.885 ;
     RECT  42.56 8.811 42.72 8.939 ;
     RECT  46.016 6.773 49.744 9.003 ;
     RECT  63.552 5.621 63.584 9.013 ;
     RECT  63.36 9.013 63.584 9.067 ;
     RECT  33.256 0.531 33.544 9.077 ;
     RECT  26.88 8.245 28.144 9.141 ;
     RECT  6.256 8.885 9.696 9.195 ;
     RECT  60.256 0.531 60.544 9.269 ;
     RECT  26.88 9.141 28.256 9.451 ;
     RECT  0.384 8.309 4.96 9.589 ;
     RECT  6.256 9.195 6.544 9.589 ;
     RECT  20.224 8.821 24.48 9.653 ;
     RECT  18.944 9.653 24.48 9.707 ;
     RECT  8.448 9.195 9.696 9.717 ;
     RECT  8.448 9.717 10.08 9.845 ;
     RECT  11.52 8.501 17.344 9.845 ;
     RECT  33.256 9.077 33.76 9.845 ;
     RECT  40.512 7.851 40.544 9.909 ;
     RECT  51.968 8.053 55.144 10.027 ;
     RECT  51.968 10.027 52 10.229 ;
     RECT  60.256 9.269 60.96 10.283 ;
     RECT  8.448 9.845 17.344 10.347 ;
     RECT  53.44 10.027 55.144 10.347 ;
     RECT  9.664 10.347 17.344 10.411 ;
     RECT  33.152 9.845 33.76 10.421 ;
     RECT  36.032 10.357 36.512 10.421 ;
     RECT  46.976 9.003 49.744 10.475 ;
     RECT  40.256 9.909 40.544 10.795 ;
     RECT  20.608 9.707 24.48 10.859 ;
     RECT  51.84 10.229 52 11.115 ;
     RECT  33.152 10.421 36.512 11.189 ;
     RECT  18.944 9.707 18.976 11.317 ;
     RECT  42.56 8.939 42.592 11.381 ;
     RECT  26.368 10.229 26.4 11.445 ;
     RECT  46.976 10.475 47.2 11.445 ;
     RECT  21.248 10.859 24.48 11.499 ;
     RECT  33.024 11.189 36.512 11.499 ;
     RECT  17.056 10.411 17.344 11.637 ;
     RECT  18.944 11.317 19.936 11.637 ;
     RECT  26.368 11.445 26.464 11.637 ;
     RECT  27.856 9.451 28.256 11.637 ;
     RECT  53.44 10.347 53.472 11.637 ;
     RECT  54.856 10.347 55.144 11.637 ;
     RECT  31.36 9.525 31.392 11.691 ;
     RECT  33.024 11.499 36.064 11.691 ;
     RECT  51.968 11.115 52 11.691 ;
     RECT  26.24 11.637 28.256 12.149 ;
     RECT  29.824 9.397 29.856 12.149 ;
     RECT  9.664 10.411 15.392 12.213 ;
     RECT  57.152 10.869 57.184 12.267 ;
     RECT  38.656 8.299 38.944 12.725 ;
     RECT  42.176 11.381 42.592 12.725 ;
     RECT  42.176 12.725 42.72 12.853 ;
     RECT  49.456 10.475 49.744 12.917 ;
     RECT  60.256 10.283 60.544 13.045 ;
     RECT  41.728 12.853 42.72 13.109 ;
     RECT  44.056 5.739 44.344 13.109 ;
     RECT  33.024 11.691 35.296 13.163 ;
     RECT  37.632 12.725 38.944 13.237 ;
     RECT  40.256 10.795 40.288 13.237 ;
     RECT  17.056 11.637 19.936 13.301 ;
     RECT  21.248 11.499 23.136 13.301 ;
     RECT  53.44 11.637 55.144 13.301 ;
     RECT  0.384 9.589 6.544 13.365 ;
     RECT  41.728 13.109 44.344 13.365 ;
     RECT  45.824 11.445 47.2 13.365 ;
     RECT  0.384 13.365 7.84 13.493 ;
     RECT  37.632 13.237 40.288 13.557 ;
     RECT  17.056 13.301 23.136 13.621 ;
     RECT  33.152 13.163 35.296 13.739 ;
     RECT  37.056 13.557 40.288 13.877 ;
     RECT  41.728 13.365 47.2 13.877 ;
     RECT  0.192 13.493 7.84 13.931 ;
     RECT  37.056 13.877 47.2 13.931 ;
     RECT  59.264 13.045 60.544 13.931 ;
     RECT  47.168 13.931 47.2 14.059 ;
     RECT  16.896 13.621 23.136 14.069 ;
     RECT  24.448 11.499 24.48 14.069 ;
     RECT  16.896 14.069 24.48 14.133 ;
     RECT  26.24 12.149 29.856 14.133 ;
     RECT  65.656 8.619 65.944 14.197 ;
     RECT  52.736 13.301 55.144 14.315 ;
     RECT  37.056 13.931 38.944 14.389 ;
     RECT  63.36 9.067 63.392 14.635 ;
     RECT  49.456 12.917 50.208 14.891 ;
     RECT  52.736 14.315 53.472 15.093 ;
     RECT  16.896 14.133 29.856 15.467 ;
     RECT  0.192 13.931 4.768 15.605 ;
     RECT  40.256 13.931 45.856 15.659 ;
     RECT  33.152 13.739 35.104 15.669 ;
     RECT  36.48 14.389 38.944 15.669 ;
     RECT  40.256 15.659 45.472 15.669 ;
     RECT  36.48 15.669 45.472 15.723 ;
     RECT  6.144 13.931 7.84 16.107 ;
     RECT  16.896 15.467 19.872 16.107 ;
     RECT  33.088 15.669 35.104 16.171 ;
     RECT  51.904 15.093 53.472 16.171 ;
     RECT  64.704 14.197 65.944 16.171 ;
     RECT  33.256 16.171 35.104 16.181 ;
     RECT  33.256 16.181 35.808 16.235 ;
     RECT  16.896 16.107 18.464 16.245 ;
     RECT  0.128 15.605 4.768 16.629 ;
     RECT  6.144 16.107 7.456 16.629 ;
     RECT  9.536 12.213 15.392 16.693 ;
     RECT  16.832 16.245 18.464 16.693 ;
     RECT  9.536 16.693 18.464 16.811 ;
     RECT  19.84 16.107 19.872 16.811 ;
     RECT  31.616 13.237 31.648 16.821 ;
     RECT  37.312 15.723 45.472 16.875 ;
     RECT  9.536 16.811 13.152 16.939 ;
     RECT  59.392 13.931 60.544 17.067 ;
     RECT  0.128 16.629 7.456 17.077 ;
     RECT  31.488 16.821 31.648 17.077 ;
     RECT  31.488 17.077 31.712 17.131 ;
     RECT  49.456 14.891 49.744 17.589 ;
     RECT  38.656 16.875 45.472 17.707 ;
     RECT  51.904 16.171 52.768 17.707 ;
     RECT  21.184 15.467 29.856 18.229 ;
     RECT  33.256 16.235 33.544 18.229 ;
     RECT  14.912 16.811 18.464 18.283 ;
     RECT  56.448 16.501 56.48 18.411 ;
     RECT  0.064 17.077 7.456 18.475 ;
     RECT  20.16 18.229 29.856 18.603 ;
     RECT  31.68 17.131 31.712 18.677 ;
     RECT  33.024 18.229 33.544 18.677 ;
     RECT  34.88 16.235 35.808 18.677 ;
     RECT  0.128 18.475 7.456 18.741 ;
     RECT  20.16 18.603 25.312 18.805 ;
     RECT  38.656 17.707 44.448 18.923 ;
     RECT  47.296 18.165 47.328 18.997 ;
     RECT  49.024 17.589 49.744 18.997 ;
     RECT  15.744 18.283 18.464 19.051 ;
     RECT  38.656 18.923 40.096 19.051 ;
     RECT  9.536 16.939 12.512 19.125 ;
     RECT  34.88 18.677 36.768 19.189 ;
     RECT  38.656 19.051 40.032 19.189 ;
     RECT  0.128 18.741 8.032 19.243 ;
     RECT  47.296 18.997 49.744 19.317 ;
     RECT  52.736 17.707 52.768 19.317 ;
     RECT  52.736 19.317 52.96 19.371 ;
     RECT  31.68 18.677 33.544 19.435 ;
     RECT  64.96 16.171 65.944 19.435 ;
     RECT  46.08 19.317 49.744 19.627 ;
     RECT  15.744 19.051 17.344 19.829 ;
     RECT  19.904 18.805 25.312 20.011 ;
     RECT  9.536 19.125 13.152 20.021 ;
     RECT  47.424 19.627 49.744 20.331 ;
     RECT  15.36 19.829 17.344 20.341 ;
     RECT  0.384 19.243 8.032 20.469 ;
     RECT  9.536 20.021 13.664 20.469 ;
     RECT  15.296 20.341 17.344 20.469 ;
     RECT  0.384 20.469 13.664 20.587 ;
     RECT  41.664 18.923 44.448 20.651 ;
     RECT  41.728 20.651 44.448 20.779 ;
     RECT  20.48 20.011 25.312 20.981 ;
     RECT  26.624 18.603 29.856 20.981 ;
     RECT  34.88 19.189 40.032 21.163 ;
     RECT  46.08 19.627 46.112 21.173 ;
     RECT  47.424 20.331 47.456 21.173 ;
     RECT  15.232 20.469 17.344 21.291 ;
     RECT  20.48 20.981 29.856 21.301 ;
     RECT  0.384 20.587 9.12 21.493 ;
     RECT  54.856 14.315 55.144 21.493 ;
     RECT  46.08 21.173 47.456 21.611 ;
     RECT  15.232 21.291 15.392 21.621 ;
     RECT  31.68 19.435 31.84 21.621 ;
     RECT  33.256 19.435 33.544 21.621 ;
     RECT  34.88 21.163 39.072 21.621 ;
     RECT  17.056 21.291 17.344 21.813 ;
     RECT  17.056 21.813 17.632 21.877 ;
     RECT  19.904 21.301 29.856 21.877 ;
     RECT  11.072 20.587 13.664 22.005 ;
     RECT  0.128 21.493 9.12 22.133 ;
     RECT  10.816 22.005 13.664 22.133 ;
     RECT  0.128 22.133 13.664 22.197 ;
     RECT  14.976 21.621 15.392 22.197 ;
     RECT  0.128 22.197 15.392 22.315 ;
     RECT  46.08 21.611 47.328 22.325 ;
     RECT  19.904 21.877 30.24 22.389 ;
     RECT  31.68 21.621 31.904 22.389 ;
     RECT  52.928 19.371 52.96 22.389 ;
     RECT  17.056 21.877 17.696 22.965 ;
     RECT  19.904 22.389 31.904 22.965 ;
     RECT  49.456 20.331 49.744 23.029 ;
     RECT  33.256 21.621 39.072 23.541 ;
     RECT  46.016 22.325 47.328 23.541 ;
     RECT  8.384 22.315 8.416 23.595 ;
     RECT  0.128 22.315 6.688 23.669 ;
     RECT  17.056 22.965 31.904 23.669 ;
     RECT  41.728 20.779 44.344 23.669 ;
     RECT  46.016 23.541 47.648 23.669 ;
     RECT  65.656 19.435 65.944 23.861 ;
     RECT  0.128 23.669 6.88 23.979 ;
     RECT  41.728 23.669 47.648 24.043 ;
     RECT  10.24 22.315 15.392 24.299 ;
     RECT  52.736 22.389 52.96 24.363 ;
     RECT  41.728 24.043 45.088 24.437 ;
     RECT  64.704 23.861 65.944 24.555 ;
     RECT  62.976 21.941 63.008 24.629 ;
     RECT  62.976 24.629 63.136 24.683 ;
     RECT  0.856 23.979 6.88 24.757 ;
     RECT  16.896 23.669 31.904 24.757 ;
     RECT  33.256 23.541 39.328 24.757 ;
     RECT  63.104 24.683 63.136 24.885 ;
     RECT  41.6 24.437 45.088 24.939 ;
     RECT  0.856 24.757 7.648 25.269 ;
     RECT  46.72 24.043 47.648 25.461 ;
     RECT  49.456 23.029 51.04 25.461 ;
     RECT  0.384 25.269 7.648 25.589 ;
     RECT  54.856 21.493 55.648 25.781 ;
     RECT  41.6 24.939 44.768 25.899 ;
     RECT  16.896 24.757 39.328 26.027 ;
     RECT  46.72 25.461 51.04 26.037 ;
     RECT  0.384 25.589 8.608 26.283 ;
     RECT  16.896 26.027 39.2 26.411 ;
     RECT  22.272 26.411 39.2 26.475 ;
     RECT  4.16 26.283 8.608 26.485 ;
     RECT  46.208 26.037 51.04 26.485 ;
     RECT  16.896 26.411 19.872 26.603 ;
     RECT  4.16 26.485 8.8 26.677 ;
     RECT  10.88 24.299 15.392 26.741 ;
     RECT  10.304 26.741 15.392 26.859 ;
     RECT  54.856 25.781 55.84 26.859 ;
     RECT  0.384 26.283 2.848 26.923 ;
     RECT  40.512 26.997 40.544 27.253 ;
     RECT  41.856 25.899 44.768 27.253 ;
     RECT  46.208 26.485 51.104 27.435 ;
     RECT  46.208 27.435 46.24 27.499 ;
     RECT  4.16 26.677 8.928 27.829 ;
     RECT  10.304 26.859 12.192 27.829 ;
     RECT  37.312 26.475 39.2 27.829 ;
     RECT  40.512 27.253 44.768 27.829 ;
     RECT  4.16 27.829 12.192 27.883 ;
     RECT  37.312 27.829 44.768 27.883 ;
     RECT  4.16 27.883 9.696 28.459 ;
     RECT  60.256 17.067 60.544 28.981 ;
     RECT  54.856 26.859 55.144 29.045 ;
     RECT  22.272 26.475 35.616 29.099 ;
     RECT  0.856 26.923 2.848 29.365 ;
     RECT  59.776 28.981 60.544 29.365 ;
     RECT  16.896 26.603 19.68 29.557 ;
     RECT  16.896 29.557 20.256 29.739 ;
     RECT  47.616 27.435 51.104 29.813 ;
     RECT  65.656 24.555 65.944 29.941 ;
     RECT  11.328 27.883 12.192 30.005 ;
     RECT  13.568 26.859 15.392 30.005 ;
     RECT  4.288 28.459 9.696 30.251 ;
     RECT  47.616 29.813 51.296 30.251 ;
     RECT  46.208 29.557 46.24 30.443 ;
     RECT  37.568 27.883 44.768 30.571 ;
     RECT  0.384 29.365 2.848 30.699 ;
     RECT  33.088 29.099 35.616 30.699 ;
     RECT  0.384 30.699 2.72 30.827 ;
     RECT  11.328 30.005 15.392 30.837 ;
     RECT  37.568 30.571 40.736 30.837 ;
     RECT  22.272 29.099 31.648 30.901 ;
     RECT  17.056 29.739 20.256 31.029 ;
     RECT  16.704 31.029 20.256 31.221 ;
     RECT  10.816 30.837 15.392 31.349 ;
     RECT  16.704 31.221 20.32 31.349 ;
     RECT  63.104 24.885 63.712 31.403 ;
     RECT  42.112 30.571 44.768 31.595 ;
     RECT  10.816 31.349 20.32 31.797 ;
     RECT  47.616 30.251 49.888 31.851 ;
     RECT  0.384 30.827 2.656 31.861 ;
     RECT  65.472 29.941 65.944 31.861 ;
     RECT  47.616 31.851 49.744 31.979 ;
     RECT  21.632 30.901 31.648 32.043 ;
     RECT  37.312 30.837 40.736 32.107 ;
     RECT  37.312 32.107 39.2 32.299 ;
     RECT  4.288 30.251 9.056 32.437 ;
     RECT  10.56 31.797 20.32 32.437 ;
     RECT  21.632 32.043 24.992 32.437 ;
     RECT  58.88 29.365 60.544 32.555 ;
     RECT  63.68 31.403 63.712 32.555 ;
     RECT  4.288 32.437 24.992 32.683 ;
     RECT  42.112 31.595 44.344 32.683 ;
     RECT  14.144 32.683 24.992 32.747 ;
     RECT  42.944 32.683 44.344 32.939 ;
     RECT  26.688 32.043 31.648 33.003 ;
     RECT  4.288 32.683 12.512 33.067 ;
     RECT  14.912 32.747 24.992 33.131 ;
     RECT  47.616 31.979 47.648 33.131 ;
     RECT  33.088 30.699 34.528 33.323 ;
     RECT  49.28 31.979 49.744 33.323 ;
     RECT  52.736 24.363 52.768 33.835 ;
     RECT  51.264 30.251 51.296 33.899 ;
     RECT  68.992 29.557 69.024 34.411 ;
     RECT  40.704 32.107 40.736 34.603 ;
     RECT  37.312 32.299 38.944 34.613 ;
     RECT  33.088 33.323 34.144 34.667 ;
     RECT  54.856 29.045 55.264 34.731 ;
     RECT  59.776 32.555 60.544 34.741 ;
     RECT  0.064 31.861 2.656 34.795 ;
     RECT  27.072 33.003 31.648 34.795 ;
     RECT  10.56 33.067 12.512 34.805 ;
     RECT  14.912 33.131 23.648 34.805 ;
     RECT  4.288 33.067 9.056 34.859 ;
     RECT  10.56 34.805 23.648 34.859 ;
     RECT  10.56 34.859 20.704 34.987 ;
     RECT  10.56 34.987 13.792 35.051 ;
     RECT  24.96 33.131 24.992 35.051 ;
     RECT  59.648 34.741 60.544 35.115 ;
     RECT  15.168 34.987 20.704 35.371 ;
     RECT  37.312 34.613 39.84 35.371 ;
     RECT  43.456 32.939 44.344 35.371 ;
     RECT  4.352 34.859 9.056 35.947 ;
     RECT  27.072 34.795 29.344 35.947 ;
     RECT  46.848 33.269 46.88 35.947 ;
     RECT  15.168 35.371 20.32 36.011 ;
     RECT  0.064 34.795 1.44 36.213 ;
     RECT  2.816 35.125 2.848 36.213 ;
     RECT  27.856 35.947 29.344 36.267 ;
     RECT  22.144 34.859 23.648 36.331 ;
     RECT  4.352 35.947 7.904 36.395 ;
     RECT  22.144 36.331 22.944 36.395 ;
     RECT  49.344 33.323 49.744 36.523 ;
     RECT  65.344 31.861 65.944 36.523 ;
     RECT  6.08 36.395 7.904 36.587 ;
     RECT  22.456 36.395 22.944 36.587 ;
     RECT  31.616 34.795 31.648 36.779 ;
     RECT  4.352 36.395 4.64 36.843 ;
     RECT  33.256 34.667 34.144 37.099 ;
     RECT  6.08 36.587 6.752 37.227 ;
     RECT  16.128 36.011 20.32 37.227 ;
     RECT  17.056 37.227 20.32 37.355 ;
     RECT  17.056 37.355 17.952 37.675 ;
     RECT  37.632 35.371 39.84 37.675 ;
     RECT  19.968 37.355 20.32 37.739 ;
     RECT  6.08 37.227 6.544 37.931 ;
     RECT  10.56 35.051 12.512 37.931 ;
     RECT  0.064 36.213 2.848 38.059 ;
     RECT  0.064 38.059 2.016 38.251 ;
     RECT  17.056 37.675 17.76 38.379 ;
     RECT  10.56 37.931 11.944 38.699 ;
     RECT  0.384 38.251 1.144 39.211 ;
     RECT  4.608 36.843 4.64 39.211 ;
     RECT  19.968 37.739 20 39.787 ;
     RECT  0.856 39.211 1.144 40.239 ;
     RECT  6.256 37.931 6.544 40.239 ;
     RECT  11.656 38.699 11.944 40.239 ;
     RECT  17.056 38.379 17.344 40.239 ;
     RECT  22.456 36.587 22.744 40.239 ;
     RECT  27.856 36.267 28.144 40.239 ;
     RECT  33.256 37.099 33.544 40.239 ;
     RECT  38.656 37.675 38.944 40.239 ;
     RECT  44.056 35.371 44.344 40.239 ;
     RECT  49.456 36.523 49.744 40.239 ;
     RECT  54.856 34.731 55.144 40.239 ;
     RECT  60.256 35.115 60.544 40.239 ;
     RECT  65.656 36.523 65.944 40.239 ;
     RECT  71.056 0.531 71.344 40.239 ;
  END
END hfd_stn_r34
END LIBRARY
